VERSION 5.8 ;
BUSBITCHARS "[]" ;
DIVIDERCHAR "/" ;
UNITS
    DATABASE MICRONS 1000 ;
END UNITS

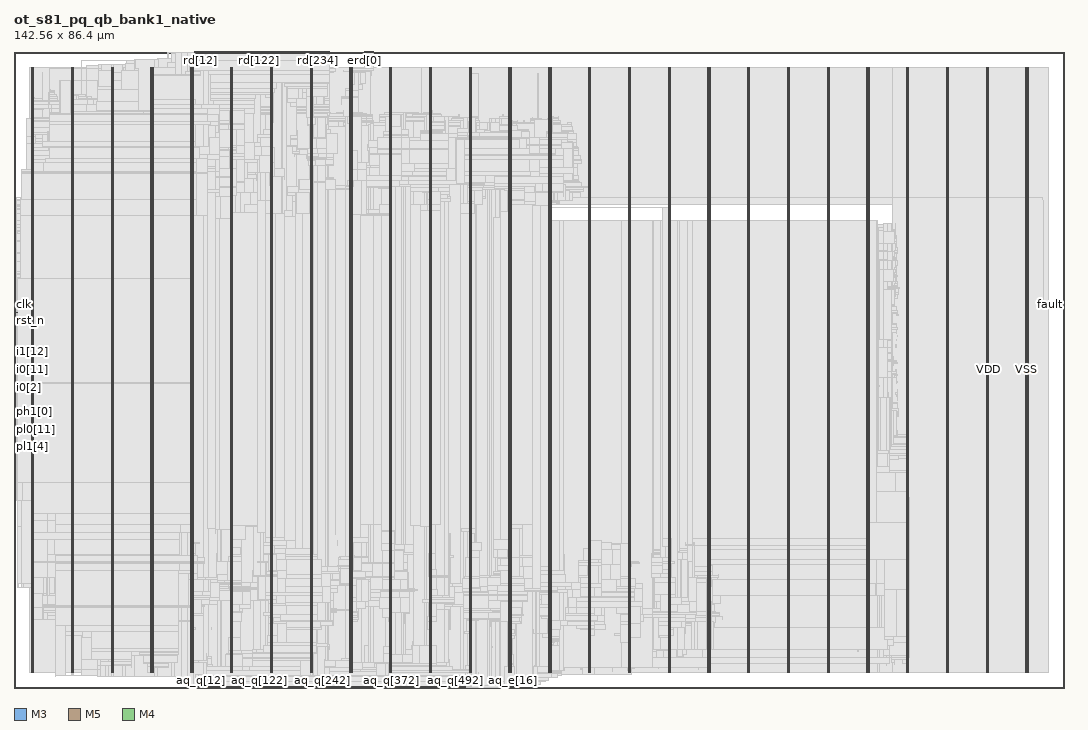
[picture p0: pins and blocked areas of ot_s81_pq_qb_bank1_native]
MACRO ot_s81_pq_qb_bank1_native
  FOREIGN ot_s81_pq_qb_bank1_native 0 0 ;
  CLASS BLOCK ;
  SIZE 142.56 BY 86.4 ;
  PIN aq_e[0]
    DIRECTION INPUT ;
    USE SIGNAL ;
    PORT
      LAYER M3 ;
        RECT  66.528 0 66.546 0.144 ;
    END
  END aq_e[0]
  PIN aq_e[10]
    DIRECTION INPUT ;
    USE SIGNAL ;
    PORT
      LAYER M3 ;
        RECT  67.248 0 67.266 0.144 ;
    END
  END aq_e[10]
  PIN aq_e[11]
    DIRECTION INPUT ;
    USE SIGNAL ;
    PORT
      LAYER M5 ;
        RECT  67.296 0 67.32 0.192 ;
    END
  END aq_e[11]
  PIN aq_e[12]
    DIRECTION INPUT ;
    USE SIGNAL ;
    PORT
      LAYER M3 ;
        RECT  67.392 0 67.41 0.144 ;
    END
  END aq_e[12]
  PIN aq_e[13]
    DIRECTION INPUT ;
    USE SIGNAL ;
    PORT
      LAYER M5 ;
        RECT  67.44 0 67.464 0.192 ;
    END
  END aq_e[13]
  PIN aq_e[14]
    DIRECTION INPUT ;
    USE SIGNAL ;
    PORT
      LAYER M3 ;
        RECT  67.536 0 67.554 0.144 ;
    END
  END aq_e[14]
  PIN aq_e[15]
    DIRECTION INPUT ;
    USE SIGNAL ;
    PORT
      LAYER M5 ;
        RECT  67.584 0 67.608 0.192 ;
    END
  END aq_e[15]
  PIN aq_e[16]
    DIRECTION INPUT ;
    USE SIGNAL ;
    PORT
      LAYER M3 ;
        RECT  67.68 0 67.698 0.144 ;
    END
  END aq_e[16]
  PIN aq_e[17]
    DIRECTION INPUT ;
    USE SIGNAL ;
    PORT
      LAYER M5 ;
        RECT  67.728 0 67.752 0.192 ;
    END
  END aq_e[17]
  PIN aq_e[18]
    DIRECTION INPUT ;
    USE SIGNAL ;
    PORT
      LAYER M3 ;
        RECT  67.824 0 67.842 0.144 ;
    END
  END aq_e[18]
  PIN aq_e[19]
    DIRECTION INPUT ;
    USE SIGNAL ;
    PORT
      LAYER M5 ;
        RECT  67.872 0 67.896 0.192 ;
    END
  END aq_e[19]
  PIN aq_e[1]
    DIRECTION INPUT ;
    USE SIGNAL ;
    PORT
      LAYER M5 ;
        RECT  66.576 0 66.6 0.192 ;
    END
  END aq_e[1]
  PIN aq_e[2]
    DIRECTION INPUT ;
    USE SIGNAL ;
    PORT
      LAYER M3 ;
        RECT  66.672 0 66.69 0.144 ;
    END
  END aq_e[2]
  PIN aq_e[3]
    DIRECTION INPUT ;
    USE SIGNAL ;
    PORT
      LAYER M5 ;
        RECT  66.72 0 66.744 0.192 ;
    END
  END aq_e[3]
  PIN aq_e[4]
    DIRECTION INPUT ;
    USE SIGNAL ;
    PORT
      LAYER M3 ;
        RECT  66.816 0 66.834 0.144 ;
    END
  END aq_e[4]
  PIN aq_e[5]
    DIRECTION INPUT ;
    USE SIGNAL ;
    PORT
      LAYER M5 ;
        RECT  66.864 0 66.888 0.192 ;
    END
  END aq_e[5]
  PIN aq_e[6]
    DIRECTION INPUT ;
    USE SIGNAL ;
    PORT
      LAYER M3 ;
        RECT  66.96 0 66.978 0.144 ;
    END
  END aq_e[6]
  PIN aq_e[7]
    DIRECTION INPUT ;
    USE SIGNAL ;
    PORT
      LAYER M5 ;
        RECT  67.008 0 67.032 0.192 ;
    END
  END aq_e[7]
  PIN aq_e[8]
    DIRECTION INPUT ;
    USE SIGNAL ;
    PORT
      LAYER M3 ;
        RECT  67.104 0 67.122 0.144 ;
    END
  END aq_e[8]
  PIN aq_e[9]
    DIRECTION INPUT ;
    USE SIGNAL ;
    PORT
      LAYER M5 ;
        RECT  67.152 0 67.176 0.192 ;
    END
  END aq_e[9]
  PIN aq_p[0]
    DIRECTION INPUT ;
    USE SIGNAL ;
    PORT
      LAYER M3 ;
        RECT  70.488 0 70.506 0.144 ;
    END
  END aq_p[0]
  PIN aq_p[1]
    DIRECTION INPUT ;
    USE SIGNAL ;
    PORT
      LAYER M5 ;
        RECT  70.512 0 70.536 0.192 ;
    END
  END aq_p[1]
  PIN aq_p[2]
    DIRECTION INPUT ;
    USE SIGNAL ;
    PORT
      LAYER M3 ;
        RECT  70.632 0 70.65 0.144 ;
    END
  END aq_p[2]
  PIN aq_p[3]
    DIRECTION INPUT ;
    USE SIGNAL ;
    PORT
      LAYER M5 ;
        RECT  70.656 0 70.68 0.192 ;
    END
  END aq_p[3]
  PIN aq_p[4]
    DIRECTION INPUT ;
    USE SIGNAL ;
    PORT
      LAYER M3 ;
        RECT  70.776 0 70.794 0.144 ;
    END
  END aq_p[4]
  PIN aq_p[5]
    DIRECTION INPUT ;
    USE SIGNAL ;
    PORT
      LAYER M5 ;
        RECT  70.8 0 70.824 0.192 ;
    END
  END aq_p[5]
  PIN aq_p[6]
    DIRECTION INPUT ;
    USE SIGNAL ;
    PORT
      LAYER M3 ;
        RECT  70.92 0 70.938 0.144 ;
    END
  END aq_p[6]
  PIN aq_p[7]
    DIRECTION INPUT ;
    USE SIGNAL ;
    PORT
      LAYER M5 ;
        RECT  70.944 0 70.968 0.192 ;
    END
  END aq_p[7]
  PIN aq_p[8]
    DIRECTION INPUT ;
    USE SIGNAL ;
    PORT
      LAYER M3 ;
        RECT  71.064 0 71.082 0.144 ;
    END
  END aq_p[8]
  PIN aq_p[9]
    DIRECTION INPUT ;
    USE SIGNAL ;
    PORT
      LAYER M5 ;
        RECT  71.088 0 71.112 0.192 ;
    END
  END aq_p[9]
  PIN aq_q[0]
    DIRECTION INPUT ;
    USE SIGNAL ;
    PORT
      LAYER M3 ;
        RECT  24.48 0 24.498 0.144 ;
    END
  END aq_q[0]
  PIN aq_q[100]
    DIRECTION INPUT ;
    USE SIGNAL ;
    PORT
      LAYER M3 ;
        RECT  31.68 0 31.698 0.144 ;
    END
  END aq_q[100]
  PIN aq_q[101]
    DIRECTION INPUT ;
    USE SIGNAL ;
    PORT
      LAYER M5 ;
        RECT  31.728 0 31.752 0.192 ;
    END
  END aq_q[101]
  PIN aq_q[102]
    DIRECTION INPUT ;
    USE SIGNAL ;
    PORT
      LAYER M3 ;
        RECT  31.824 0 31.842 0.144 ;
    END
  END aq_q[102]
  PIN aq_q[103]
    DIRECTION INPUT ;
    USE SIGNAL ;
    PORT
      LAYER M5 ;
        RECT  31.872 0 31.896 0.192 ;
    END
  END aq_q[103]
  PIN aq_q[104]
    DIRECTION INPUT ;
    USE SIGNAL ;
    PORT
      LAYER M3 ;
        RECT  31.968 0 31.986 0.144 ;
    END
  END aq_q[104]
  PIN aq_q[105]
    DIRECTION INPUT ;
    USE SIGNAL ;
    PORT
      LAYER M5 ;
        RECT  32.016 0 32.04 0.192 ;
    END
  END aq_q[105]
  PIN aq_q[106]
    DIRECTION INPUT ;
    USE SIGNAL ;
    PORT
      LAYER M3 ;
        RECT  32.112 0 32.13 0.144 ;
    END
  END aq_q[106]
  PIN aq_q[107]
    DIRECTION INPUT ;
    USE SIGNAL ;
    PORT
      LAYER M5 ;
        RECT  32.16 0 32.184 0.192 ;
    END
  END aq_q[107]
  PIN aq_q[108]
    DIRECTION INPUT ;
    USE SIGNAL ;
    PORT
      LAYER M3 ;
        RECT  32.256 0 32.274 0.144 ;
    END
  END aq_q[108]
  PIN aq_q[109]
    DIRECTION INPUT ;
    USE SIGNAL ;
    PORT
      LAYER M5 ;
        RECT  32.304 0 32.328 0.192 ;
    END
  END aq_q[109]
  PIN aq_q[10]
    DIRECTION INPUT ;
    USE SIGNAL ;
    PORT
      LAYER M3 ;
        RECT  25.2 0 25.218 0.144 ;
    END
  END aq_q[10]
  PIN aq_q[110]
    DIRECTION INPUT ;
    USE SIGNAL ;
    PORT
      LAYER M3 ;
        RECT  32.4 0 32.418 0.144 ;
    END
  END aq_q[110]
  PIN aq_q[111]
    DIRECTION INPUT ;
    USE SIGNAL ;
    PORT
      LAYER M5 ;
        RECT  32.448 0 32.472 0.192 ;
    END
  END aq_q[111]
  PIN aq_q[112]
    DIRECTION INPUT ;
    USE SIGNAL ;
    PORT
      LAYER M3 ;
        RECT  32.544 0 32.562 0.144 ;
    END
  END aq_q[112]
  PIN aq_q[113]
    DIRECTION INPUT ;
    USE SIGNAL ;
    PORT
      LAYER M5 ;
        RECT  32.592 0 32.616 0.192 ;
    END
  END aq_q[113]
  PIN aq_q[114]
    DIRECTION INPUT ;
    USE SIGNAL ;
    PORT
      LAYER M3 ;
        RECT  32.688 0 32.706 0.144 ;
    END
  END aq_q[114]
  PIN aq_q[115]
    DIRECTION INPUT ;
    USE SIGNAL ;
    PORT
      LAYER M5 ;
        RECT  32.736 0 32.76 0.192 ;
    END
  END aq_q[115]
  PIN aq_q[116]
    DIRECTION INPUT ;
    USE SIGNAL ;
    PORT
      LAYER M3 ;
        RECT  32.832 0 32.85 0.144 ;
    END
  END aq_q[116]
  PIN aq_q[117]
    DIRECTION INPUT ;
    USE SIGNAL ;
    PORT
      LAYER M5 ;
        RECT  32.88 0 32.904 0.192 ;
    END
  END aq_q[117]
  PIN aq_q[118]
    DIRECTION INPUT ;
    USE SIGNAL ;
    PORT
      LAYER M3 ;
        RECT  32.976 0 32.994 0.144 ;
    END
  END aq_q[118]
  PIN aq_q[119]
    DIRECTION INPUT ;
    USE SIGNAL ;
    PORT
      LAYER M5 ;
        RECT  33.024 0 33.048 0.192 ;
    END
  END aq_q[119]
  PIN aq_q[11]
    DIRECTION INPUT ;
    USE SIGNAL ;
    PORT
      LAYER M5 ;
        RECT  25.248 0 25.272 0.192 ;
    END
  END aq_q[11]
  PIN aq_q[120]
    DIRECTION INPUT ;
    USE SIGNAL ;
    PORT
      LAYER M3 ;
        RECT  33.12 0 33.138 0.144 ;
    END
  END aq_q[120]
  PIN aq_q[121]
    DIRECTION INPUT ;
    USE SIGNAL ;
    PORT
      LAYER M5 ;
        RECT  33.168 0 33.192 0.192 ;
    END
  END aq_q[121]
  PIN aq_q[122]
    DIRECTION INPUT ;
    USE SIGNAL ;
    PORT
      LAYER M3 ;
        RECT  33.264 0 33.282 0.144 ;
    END
  END aq_q[122]
  PIN aq_q[123]
    DIRECTION INPUT ;
    USE SIGNAL ;
    PORT
      LAYER M5 ;
        RECT  33.312 0 33.336 0.192 ;
    END
  END aq_q[123]
  PIN aq_q[124]
    DIRECTION INPUT ;
    USE SIGNAL ;
    PORT
      LAYER M3 ;
        RECT  33.408 0 33.426 0.144 ;
    END
  END aq_q[124]
  PIN aq_q[125]
    DIRECTION INPUT ;
    USE SIGNAL ;
    PORT
      LAYER M5 ;
        RECT  33.456 0 33.48 0.192 ;
    END
  END aq_q[125]
  PIN aq_q[126]
    DIRECTION INPUT ;
    USE SIGNAL ;
    PORT
      LAYER M3 ;
        RECT  33.552 0 33.57 0.144 ;
    END
  END aq_q[126]
  PIN aq_q[127]
    DIRECTION INPUT ;
    USE SIGNAL ;
    PORT
      LAYER M5 ;
        RECT  33.6 0 33.624 0.192 ;
    END
  END aq_q[127]
  PIN aq_q[128]
    DIRECTION INPUT ;
    USE SIGNAL ;
    PORT
      LAYER M3 ;
        RECT  33.696 0 33.714 0.144 ;
    END
  END aq_q[128]
  PIN aq_q[129]
    DIRECTION INPUT ;
    USE SIGNAL ;
    PORT
      LAYER M5 ;
        RECT  33.744 0 33.768 0.192 ;
    END
  END aq_q[129]
  PIN aq_q[12]
    DIRECTION INPUT ;
    USE SIGNAL ;
    PORT
      LAYER M3 ;
        RECT  25.344 0 25.362 0.144 ;
    END
  END aq_q[12]
  PIN aq_q[130]
    DIRECTION INPUT ;
    USE SIGNAL ;
    PORT
      LAYER M3 ;
        RECT  33.84 0 33.858 0.144 ;
    END
  END aq_q[130]
  PIN aq_q[131]
    DIRECTION INPUT ;
    USE SIGNAL ;
    PORT
      LAYER M5 ;
        RECT  33.888 0 33.912 0.192 ;
    END
  END aq_q[131]
  PIN aq_q[132]
    DIRECTION INPUT ;
    USE SIGNAL ;
    PORT
      LAYER M3 ;
        RECT  33.984 0 34.002 0.144 ;
    END
  END aq_q[132]
  PIN aq_q[133]
    DIRECTION INPUT ;
    USE SIGNAL ;
    PORT
      LAYER M5 ;
        RECT  34.032 0 34.056 0.192 ;
    END
  END aq_q[133]
  PIN aq_q[134]
    DIRECTION INPUT ;
    USE SIGNAL ;
    PORT
      LAYER M3 ;
        RECT  34.128 0 34.146 0.144 ;
    END
  END aq_q[134]
  PIN aq_q[135]
    DIRECTION INPUT ;
    USE SIGNAL ;
    PORT
      LAYER M5 ;
        RECT  34.176 0 34.2 0.192 ;
    END
  END aq_q[135]
  PIN aq_q[136]
    DIRECTION INPUT ;
    USE SIGNAL ;
    PORT
      LAYER M3 ;
        RECT  34.272 0 34.29 0.144 ;
    END
  END aq_q[136]
  PIN aq_q[137]
    DIRECTION INPUT ;
    USE SIGNAL ;
    PORT
      LAYER M5 ;
        RECT  34.32 0 34.344 0.192 ;
    END
  END aq_q[137]
  PIN aq_q[138]
    DIRECTION INPUT ;
    USE SIGNAL ;
    PORT
      LAYER M3 ;
        RECT  34.416 0 34.434 0.144 ;
    END
  END aq_q[138]
  PIN aq_q[139]
    DIRECTION INPUT ;
    USE SIGNAL ;
    PORT
      LAYER M5 ;
        RECT  34.464 0 34.488 0.192 ;
    END
  END aq_q[139]
  PIN aq_q[13]
    DIRECTION INPUT ;
    USE SIGNAL ;
    PORT
      LAYER M5 ;
        RECT  25.392 0 25.416 0.192 ;
    END
  END aq_q[13]
  PIN aq_q[140]
    DIRECTION INPUT ;
    USE SIGNAL ;
    PORT
      LAYER M3 ;
        RECT  34.56 0 34.578 0.144 ;
    END
  END aq_q[140]
  PIN aq_q[141]
    DIRECTION INPUT ;
    USE SIGNAL ;
    PORT
      LAYER M5 ;
        RECT  34.608 0 34.632 0.192 ;
    END
  END aq_q[141]
  PIN aq_q[142]
    DIRECTION INPUT ;
    USE SIGNAL ;
    PORT
      LAYER M3 ;
        RECT  34.704 0 34.722 0.144 ;
    END
  END aq_q[142]
  PIN aq_q[143]
    DIRECTION INPUT ;
    USE SIGNAL ;
    PORT
      LAYER M5 ;
        RECT  34.752 0 34.776 0.192 ;
    END
  END aq_q[143]
  PIN aq_q[144]
    DIRECTION INPUT ;
    USE SIGNAL ;
    PORT
      LAYER M3 ;
        RECT  34.848 0 34.866 0.144 ;
    END
  END aq_q[144]
  PIN aq_q[145]
    DIRECTION INPUT ;
    USE SIGNAL ;
    PORT
      LAYER M5 ;
        RECT  34.896 0 34.92 0.192 ;
    END
  END aq_q[145]
  PIN aq_q[146]
    DIRECTION INPUT ;
    USE SIGNAL ;
    PORT
      LAYER M3 ;
        RECT  34.992 0 35.01 0.144 ;
    END
  END aq_q[146]
  PIN aq_q[147]
    DIRECTION INPUT ;
    USE SIGNAL ;
    PORT
      LAYER M5 ;
        RECT  35.04 0 35.064 0.192 ;
    END
  END aq_q[147]
  PIN aq_q[148]
    DIRECTION INPUT ;
    USE SIGNAL ;
    PORT
      LAYER M3 ;
        RECT  35.136 0 35.154 0.144 ;
    END
  END aq_q[148]
  PIN aq_q[149]
    DIRECTION INPUT ;
    USE SIGNAL ;
    PORT
      LAYER M5 ;
        RECT  35.184 0 35.208 0.192 ;
    END
  END aq_q[149]
  PIN aq_q[14]
    DIRECTION INPUT ;
    USE SIGNAL ;
    PORT
      LAYER M3 ;
        RECT  25.488 0 25.506 0.144 ;
    END
  END aq_q[14]
  PIN aq_q[150]
    DIRECTION INPUT ;
    USE SIGNAL ;
    PORT
      LAYER M3 ;
        RECT  35.28 0 35.298 0.144 ;
    END
  END aq_q[150]
  PIN aq_q[151]
    DIRECTION INPUT ;
    USE SIGNAL ;
    PORT
      LAYER M5 ;
        RECT  35.328 0 35.352 0.192 ;
    END
  END aq_q[151]
  PIN aq_q[152]
    DIRECTION INPUT ;
    USE SIGNAL ;
    PORT
      LAYER M3 ;
        RECT  35.424 0 35.442 0.144 ;
    END
  END aq_q[152]
  PIN aq_q[153]
    DIRECTION INPUT ;
    USE SIGNAL ;
    PORT
      LAYER M5 ;
        RECT  35.472 0 35.496 0.192 ;
    END
  END aq_q[153]
  PIN aq_q[154]
    DIRECTION INPUT ;
    USE SIGNAL ;
    PORT
      LAYER M3 ;
        RECT  35.568 0 35.586 0.144 ;
    END
  END aq_q[154]
  PIN aq_q[155]
    DIRECTION INPUT ;
    USE SIGNAL ;
    PORT
      LAYER M5 ;
        RECT  35.616 0 35.64 0.192 ;
    END
  END aq_q[155]
  PIN aq_q[156]
    DIRECTION INPUT ;
    USE SIGNAL ;
    PORT
      LAYER M3 ;
        RECT  35.712 0 35.73 0.144 ;
    END
  END aq_q[156]
  PIN aq_q[157]
    DIRECTION INPUT ;
    USE SIGNAL ;
    PORT
      LAYER M5 ;
        RECT  35.76 0 35.784 0.192 ;
    END
  END aq_q[157]
  PIN aq_q[158]
    DIRECTION INPUT ;
    USE SIGNAL ;
    PORT
      LAYER M3 ;
        RECT  35.856 0 35.874 0.144 ;
    END
  END aq_q[158]
  PIN aq_q[159]
    DIRECTION INPUT ;
    USE SIGNAL ;
    PORT
      LAYER M5 ;
        RECT  35.904 0 35.928 0.192 ;
    END
  END aq_q[159]
  PIN aq_q[15]
    DIRECTION INPUT ;
    USE SIGNAL ;
    PORT
      LAYER M5 ;
        RECT  25.536 0 25.56 0.192 ;
    END
  END aq_q[15]
  PIN aq_q[160]
    DIRECTION INPUT ;
    USE SIGNAL ;
    PORT
      LAYER M3 ;
        RECT  36 0 36.018 0.144 ;
    END
  END aq_q[160]
  PIN aq_q[161]
    DIRECTION INPUT ;
    USE SIGNAL ;
    PORT
      LAYER M5 ;
        RECT  36.048 0 36.072 0.192 ;
    END
  END aq_q[161]
  PIN aq_q[162]
    DIRECTION INPUT ;
    USE SIGNAL ;
    PORT
      LAYER M3 ;
        RECT  36.144 0 36.162 0.144 ;
    END
  END aq_q[162]
  PIN aq_q[163]
    DIRECTION INPUT ;
    USE SIGNAL ;
    PORT
      LAYER M5 ;
        RECT  36.192 0 36.216 0.192 ;
    END
  END aq_q[163]
  PIN aq_q[164]
    DIRECTION INPUT ;
    USE SIGNAL ;
    PORT
      LAYER M3 ;
        RECT  36.288 0 36.306 0.144 ;
    END
  END aq_q[164]
  PIN aq_q[165]
    DIRECTION INPUT ;
    USE SIGNAL ;
    PORT
      LAYER M5 ;
        RECT  36.336 0 36.36 0.192 ;
    END
  END aq_q[165]
  PIN aq_q[166]
    DIRECTION INPUT ;
    USE SIGNAL ;
    PORT
      LAYER M3 ;
        RECT  36.432 0 36.45 0.144 ;
    END
  END aq_q[166]
  PIN aq_q[167]
    DIRECTION INPUT ;
    USE SIGNAL ;
    PORT
      LAYER M5 ;
        RECT  36.48 0 36.504 0.192 ;
    END
  END aq_q[167]
  PIN aq_q[168]
    DIRECTION INPUT ;
    USE SIGNAL ;
    PORT
      LAYER M3 ;
        RECT  36.576 0 36.594 0.144 ;
    END
  END aq_q[168]
  PIN aq_q[169]
    DIRECTION INPUT ;
    USE SIGNAL ;
    PORT
      LAYER M5 ;
        RECT  36.624 0 36.648 0.192 ;
    END
  END aq_q[169]
  PIN aq_q[16]
    DIRECTION INPUT ;
    USE SIGNAL ;
    PORT
      LAYER M3 ;
        RECT  25.632 0 25.65 0.144 ;
    END
  END aq_q[16]
  PIN aq_q[170]
    DIRECTION INPUT ;
    USE SIGNAL ;
    PORT
      LAYER M3 ;
        RECT  36.72 0 36.738 0.144 ;
    END
  END aq_q[170]
  PIN aq_q[171]
    DIRECTION INPUT ;
    USE SIGNAL ;
    PORT
      LAYER M5 ;
        RECT  36.768 0 36.792 0.192 ;
    END
  END aq_q[171]
  PIN aq_q[172]
    DIRECTION INPUT ;
    USE SIGNAL ;
    PORT
      LAYER M3 ;
        RECT  36.864 0 36.882 0.144 ;
    END
  END aq_q[172]
  PIN aq_q[173]
    DIRECTION INPUT ;
    USE SIGNAL ;
    PORT
      LAYER M5 ;
        RECT  36.912 0 36.936 0.192 ;
    END
  END aq_q[173]
  PIN aq_q[174]
    DIRECTION INPUT ;
    USE SIGNAL ;
    PORT
      LAYER M3 ;
        RECT  37.008 0 37.026 0.144 ;
    END
  END aq_q[174]
  PIN aq_q[175]
    DIRECTION INPUT ;
    USE SIGNAL ;
    PORT
      LAYER M5 ;
        RECT  37.056 0 37.08 0.192 ;
    END
  END aq_q[175]
  PIN aq_q[176]
    DIRECTION INPUT ;
    USE SIGNAL ;
    PORT
      LAYER M3 ;
        RECT  37.152 0 37.17 0.144 ;
    END
  END aq_q[176]
  PIN aq_q[177]
    DIRECTION INPUT ;
    USE SIGNAL ;
    PORT
      LAYER M5 ;
        RECT  37.2 0 37.224 0.192 ;
    END
  END aq_q[177]
  PIN aq_q[178]
    DIRECTION INPUT ;
    USE SIGNAL ;
    PORT
      LAYER M3 ;
        RECT  37.296 0 37.314 0.144 ;
    END
  END aq_q[178]
  PIN aq_q[179]
    DIRECTION INPUT ;
    USE SIGNAL ;
    PORT
      LAYER M5 ;
        RECT  37.344 0 37.368 0.192 ;
    END
  END aq_q[179]
  PIN aq_q[17]
    DIRECTION INPUT ;
    USE SIGNAL ;
    PORT
      LAYER M5 ;
        RECT  25.68 0 25.704 0.192 ;
    END
  END aq_q[17]
  PIN aq_q[180]
    DIRECTION INPUT ;
    USE SIGNAL ;
    PORT
      LAYER M3 ;
        RECT  37.44 0 37.458 0.144 ;
    END
  END aq_q[180]
  PIN aq_q[181]
    DIRECTION INPUT ;
    USE SIGNAL ;
    PORT
      LAYER M5 ;
        RECT  37.488 0 37.512 0.192 ;
    END
  END aq_q[181]
  PIN aq_q[182]
    DIRECTION INPUT ;
    USE SIGNAL ;
    PORT
      LAYER M3 ;
        RECT  37.584 0 37.602 0.144 ;
    END
  END aq_q[182]
  PIN aq_q[183]
    DIRECTION INPUT ;
    USE SIGNAL ;
    PORT
      LAYER M5 ;
        RECT  37.632 0 37.656 0.192 ;
    END
  END aq_q[183]
  PIN aq_q[184]
    DIRECTION INPUT ;
    USE SIGNAL ;
    PORT
      LAYER M3 ;
        RECT  37.728 0 37.746 0.144 ;
    END
  END aq_q[184]
  PIN aq_q[185]
    DIRECTION INPUT ;
    USE SIGNAL ;
    PORT
      LAYER M5 ;
        RECT  37.776 0 37.8 0.192 ;
    END
  END aq_q[185]
  PIN aq_q[186]
    DIRECTION INPUT ;
    USE SIGNAL ;
    PORT
      LAYER M3 ;
        RECT  37.872 0 37.89 0.144 ;
    END
  END aq_q[186]
  PIN aq_q[187]
    DIRECTION INPUT ;
    USE SIGNAL ;
    PORT
      LAYER M5 ;
        RECT  37.92 0 37.944 0.192 ;
    END
  END aq_q[187]
  PIN aq_q[188]
    DIRECTION INPUT ;
    USE SIGNAL ;
    PORT
      LAYER M3 ;
        RECT  38.016 0 38.034 0.144 ;
    END
  END aq_q[188]
  PIN aq_q[189]
    DIRECTION INPUT ;
    USE SIGNAL ;
    PORT
      LAYER M5 ;
        RECT  38.064 0 38.088 0.192 ;
    END
  END aq_q[189]
  PIN aq_q[18]
    DIRECTION INPUT ;
    USE SIGNAL ;
    PORT
      LAYER M3 ;
        RECT  25.776 0 25.794 0.144 ;
    END
  END aq_q[18]
  PIN aq_q[190]
    DIRECTION INPUT ;
    USE SIGNAL ;
    PORT
      LAYER M3 ;
        RECT  38.16 0 38.178 0.144 ;
    END
  END aq_q[190]
  PIN aq_q[191]
    DIRECTION INPUT ;
    USE SIGNAL ;
    PORT
      LAYER M5 ;
        RECT  38.208 0 38.232 0.192 ;
    END
  END aq_q[191]
  PIN aq_q[192]
    DIRECTION INPUT ;
    USE SIGNAL ;
    PORT
      LAYER M3 ;
        RECT  38.304 0 38.322 0.144 ;
    END
  END aq_q[192]
  PIN aq_q[193]
    DIRECTION INPUT ;
    USE SIGNAL ;
    PORT
      LAYER M5 ;
        RECT  38.352 0 38.376 0.192 ;
    END
  END aq_q[193]
  PIN aq_q[194]
    DIRECTION INPUT ;
    USE SIGNAL ;
    PORT
      LAYER M3 ;
        RECT  38.448 0 38.466 0.144 ;
    END
  END aq_q[194]
  PIN aq_q[195]
    DIRECTION INPUT ;
    USE SIGNAL ;
    PORT
      LAYER M5 ;
        RECT  38.496 0 38.52 0.192 ;
    END
  END aq_q[195]
  PIN aq_q[196]
    DIRECTION INPUT ;
    USE SIGNAL ;
    PORT
      LAYER M3 ;
        RECT  38.592 0 38.61 0.144 ;
    END
  END aq_q[196]
  PIN aq_q[197]
    DIRECTION INPUT ;
    USE SIGNAL ;
    PORT
      LAYER M5 ;
        RECT  38.64 0 38.664 0.192 ;
    END
  END aq_q[197]
  PIN aq_q[198]
    DIRECTION INPUT ;
    USE SIGNAL ;
    PORT
      LAYER M3 ;
        RECT  38.736 0 38.754 0.144 ;
    END
  END aq_q[198]
  PIN aq_q[199]
    DIRECTION INPUT ;
    USE SIGNAL ;
    PORT
      LAYER M5 ;
        RECT  38.784 0 38.808 0.192 ;
    END
  END aq_q[199]
  PIN aq_q[19]
    DIRECTION INPUT ;
    USE SIGNAL ;
    PORT
      LAYER M5 ;
        RECT  25.824 0 25.848 0.192 ;
    END
  END aq_q[19]
  PIN aq_q[1]
    DIRECTION INPUT ;
    USE SIGNAL ;
    PORT
      LAYER M5 ;
        RECT  24.528 0 24.552 0.192 ;
    END
  END aq_q[1]
  PIN aq_q[200]
    DIRECTION INPUT ;
    USE SIGNAL ;
    PORT
      LAYER M3 ;
        RECT  38.88 0 38.898 0.144 ;
    END
  END aq_q[200]
  PIN aq_q[201]
    DIRECTION INPUT ;
    USE SIGNAL ;
    PORT
      LAYER M5 ;
        RECT  38.928 0 38.952 0.192 ;
    END
  END aq_q[201]
  PIN aq_q[202]
    DIRECTION INPUT ;
    USE SIGNAL ;
    PORT
      LAYER M3 ;
        RECT  39.024 0 39.042 0.144 ;
    END
  END aq_q[202]
  PIN aq_q[203]
    DIRECTION INPUT ;
    USE SIGNAL ;
    PORT
      LAYER M5 ;
        RECT  39.072 0 39.096 0.192 ;
    END
  END aq_q[203]
  PIN aq_q[204]
    DIRECTION INPUT ;
    USE SIGNAL ;
    PORT
      LAYER M3 ;
        RECT  39.168 0 39.186 0.144 ;
    END
  END aq_q[204]
  PIN aq_q[205]
    DIRECTION INPUT ;
    USE SIGNAL ;
    PORT
      LAYER M5 ;
        RECT  39.216 0 39.24 0.192 ;
    END
  END aq_q[205]
  PIN aq_q[206]
    DIRECTION INPUT ;
    USE SIGNAL ;
    PORT
      LAYER M3 ;
        RECT  39.312 0 39.33 0.144 ;
    END
  END aq_q[206]
  PIN aq_q[207]
    DIRECTION INPUT ;
    USE SIGNAL ;
    PORT
      LAYER M5 ;
        RECT  39.36 0 39.384 0.192 ;
    END
  END aq_q[207]
  PIN aq_q[208]
    DIRECTION INPUT ;
    USE SIGNAL ;
    PORT
      LAYER M3 ;
        RECT  39.456 0 39.474 0.144 ;
    END
  END aq_q[208]
  PIN aq_q[209]
    DIRECTION INPUT ;
    USE SIGNAL ;
    PORT
      LAYER M5 ;
        RECT  39.504 0 39.528 0.192 ;
    END
  END aq_q[209]
  PIN aq_q[20]
    DIRECTION INPUT ;
    USE SIGNAL ;
    PORT
      LAYER M3 ;
        RECT  25.92 0 25.938 0.144 ;
    END
  END aq_q[20]
  PIN aq_q[210]
    DIRECTION INPUT ;
    USE SIGNAL ;
    PORT
      LAYER M3 ;
        RECT  39.6 0 39.618 0.144 ;
    END
  END aq_q[210]
  PIN aq_q[211]
    DIRECTION INPUT ;
    USE SIGNAL ;
    PORT
      LAYER M5 ;
        RECT  39.648 0 39.672 0.192 ;
    END
  END aq_q[211]
  PIN aq_q[212]
    DIRECTION INPUT ;
    USE SIGNAL ;
    PORT
      LAYER M3 ;
        RECT  39.744 0 39.762 0.144 ;
    END
  END aq_q[212]
  PIN aq_q[213]
    DIRECTION INPUT ;
    USE SIGNAL ;
    PORT
      LAYER M5 ;
        RECT  39.792 0 39.816 0.192 ;
    END
  END aq_q[213]
  PIN aq_q[214]
    DIRECTION INPUT ;
    USE SIGNAL ;
    PORT
      LAYER M3 ;
        RECT  39.888 0 39.906 0.144 ;
    END
  END aq_q[214]
  PIN aq_q[215]
    DIRECTION INPUT ;
    USE SIGNAL ;
    PORT
      LAYER M5 ;
        RECT  39.936 0 39.96 0.192 ;
    END
  END aq_q[215]
  PIN aq_q[216]
    DIRECTION INPUT ;
    USE SIGNAL ;
    PORT
      LAYER M3 ;
        RECT  40.032 0 40.05 0.144 ;
    END
  END aq_q[216]
  PIN aq_q[217]
    DIRECTION INPUT ;
    USE SIGNAL ;
    PORT
      LAYER M5 ;
        RECT  40.08 0 40.104 0.192 ;
    END
  END aq_q[217]
  PIN aq_q[218]
    DIRECTION INPUT ;
    USE SIGNAL ;
    PORT
      LAYER M3 ;
        RECT  40.176 0 40.194 0.144 ;
    END
  END aq_q[218]
  PIN aq_q[219]
    DIRECTION INPUT ;
    USE SIGNAL ;
    PORT
      LAYER M5 ;
        RECT  40.224 0 40.248 0.192 ;
    END
  END aq_q[219]
  PIN aq_q[21]
    DIRECTION INPUT ;
    USE SIGNAL ;
    PORT
      LAYER M5 ;
        RECT  25.968 0 25.992 0.192 ;
    END
  END aq_q[21]
  PIN aq_q[220]
    DIRECTION INPUT ;
    USE SIGNAL ;
    PORT
      LAYER M3 ;
        RECT  40.32 0 40.338 0.144 ;
    END
  END aq_q[220]
  PIN aq_q[221]
    DIRECTION INPUT ;
    USE SIGNAL ;
    PORT
      LAYER M5 ;
        RECT  40.368 0 40.392 0.192 ;
    END
  END aq_q[221]
  PIN aq_q[222]
    DIRECTION INPUT ;
    USE SIGNAL ;
    PORT
      LAYER M3 ;
        RECT  40.464 0 40.482 0.144 ;
    END
  END aq_q[222]
  PIN aq_q[223]
    DIRECTION INPUT ;
    USE SIGNAL ;
    PORT
      LAYER M5 ;
        RECT  40.512 0 40.536 0.192 ;
    END
  END aq_q[223]
  PIN aq_q[224]
    DIRECTION INPUT ;
    USE SIGNAL ;
    PORT
      LAYER M3 ;
        RECT  40.608 0 40.626 0.144 ;
    END
  END aq_q[224]
  PIN aq_q[225]
    DIRECTION INPUT ;
    USE SIGNAL ;
    PORT
      LAYER M5 ;
        RECT  40.656 0 40.68 0.192 ;
    END
  END aq_q[225]
  PIN aq_q[226]
    DIRECTION INPUT ;
    USE SIGNAL ;
    PORT
      LAYER M3 ;
        RECT  40.752 0 40.77 0.144 ;
    END
  END aq_q[226]
  PIN aq_q[227]
    DIRECTION INPUT ;
    USE SIGNAL ;
    PORT
      LAYER M5 ;
        RECT  40.8 0 40.824 0.192 ;
    END
  END aq_q[227]
  PIN aq_q[228]
    DIRECTION INPUT ;
    USE SIGNAL ;
    PORT
      LAYER M3 ;
        RECT  40.896 0 40.914 0.144 ;
    END
  END aq_q[228]
  PIN aq_q[229]
    DIRECTION INPUT ;
    USE SIGNAL ;
    PORT
      LAYER M5 ;
        RECT  40.944 0 40.968 0.192 ;
    END
  END aq_q[229]
  PIN aq_q[22]
    DIRECTION INPUT ;
    USE SIGNAL ;
    PORT
      LAYER M3 ;
        RECT  26.064 0 26.082 0.144 ;
    END
  END aq_q[22]
  PIN aq_q[230]
    DIRECTION INPUT ;
    USE SIGNAL ;
    PORT
      LAYER M3 ;
        RECT  41.04 0 41.058 0.144 ;
    END
  END aq_q[230]
  PIN aq_q[231]
    DIRECTION INPUT ;
    USE SIGNAL ;
    PORT
      LAYER M5 ;
        RECT  41.088 0 41.112 0.192 ;
    END
  END aq_q[231]
  PIN aq_q[232]
    DIRECTION INPUT ;
    USE SIGNAL ;
    PORT
      LAYER M3 ;
        RECT  41.184 0 41.202 0.144 ;
    END
  END aq_q[232]
  PIN aq_q[233]
    DIRECTION INPUT ;
    USE SIGNAL ;
    PORT
      LAYER M5 ;
        RECT  41.232 0 41.256 0.192 ;
    END
  END aq_q[233]
  PIN aq_q[234]
    DIRECTION INPUT ;
    USE SIGNAL ;
    PORT
      LAYER M3 ;
        RECT  41.328 0 41.346 0.144 ;
    END
  END aq_q[234]
  PIN aq_q[235]
    DIRECTION INPUT ;
    USE SIGNAL ;
    PORT
      LAYER M5 ;
        RECT  41.376 0 41.4 0.192 ;
    END
  END aq_q[235]
  PIN aq_q[236]
    DIRECTION INPUT ;
    USE SIGNAL ;
    PORT
      LAYER M3 ;
        RECT  41.472 0 41.49 0.144 ;
    END
  END aq_q[236]
  PIN aq_q[237]
    DIRECTION INPUT ;
    USE SIGNAL ;
    PORT
      LAYER M5 ;
        RECT  41.52 0 41.544 0.192 ;
    END
  END aq_q[237]
  PIN aq_q[238]
    DIRECTION INPUT ;
    USE SIGNAL ;
    PORT
      LAYER M3 ;
        RECT  41.616 0 41.634 0.144 ;
    END
  END aq_q[238]
  PIN aq_q[239]
    DIRECTION INPUT ;
    USE SIGNAL ;
    PORT
      LAYER M5 ;
        RECT  41.664 0 41.688 0.192 ;
    END
  END aq_q[239]
  PIN aq_q[23]
    DIRECTION INPUT ;
    USE SIGNAL ;
    PORT
      LAYER M5 ;
        RECT  26.112 0 26.136 0.192 ;
    END
  END aq_q[23]
  PIN aq_q[240]
    DIRECTION INPUT ;
    USE SIGNAL ;
    PORT
      LAYER M3 ;
        RECT  41.76 0 41.778 0.144 ;
    END
  END aq_q[240]
  PIN aq_q[241]
    DIRECTION INPUT ;
    USE SIGNAL ;
    PORT
      LAYER M5 ;
        RECT  41.808 0 41.832 0.192 ;
    END
  END aq_q[241]
  PIN aq_q[242]
    DIRECTION INPUT ;
    USE SIGNAL ;
    PORT
      LAYER M3 ;
        RECT  41.904 0 41.922 0.144 ;
    END
  END aq_q[242]
  PIN aq_q[243]
    DIRECTION INPUT ;
    USE SIGNAL ;
    PORT
      LAYER M5 ;
        RECT  41.952 0 41.976 0.192 ;
    END
  END aq_q[243]
  PIN aq_q[244]
    DIRECTION INPUT ;
    USE SIGNAL ;
    PORT
      LAYER M3 ;
        RECT  42.048 0 42.066 0.144 ;
    END
  END aq_q[244]
  PIN aq_q[245]
    DIRECTION INPUT ;
    USE SIGNAL ;
    PORT
      LAYER M5 ;
        RECT  42.096 0 42.12 0.192 ;
    END
  END aq_q[245]
  PIN aq_q[246]
    DIRECTION INPUT ;
    USE SIGNAL ;
    PORT
      LAYER M3 ;
        RECT  42.192 0 42.21 0.144 ;
    END
  END aq_q[246]
  PIN aq_q[247]
    DIRECTION INPUT ;
    USE SIGNAL ;
    PORT
      LAYER M5 ;
        RECT  42.24 0 42.264 0.192 ;
    END
  END aq_q[247]
  PIN aq_q[248]
    DIRECTION INPUT ;
    USE SIGNAL ;
    PORT
      LAYER M3 ;
        RECT  42.336 0 42.354 0.144 ;
    END
  END aq_q[248]
  PIN aq_q[249]
    DIRECTION INPUT ;
    USE SIGNAL ;
    PORT
      LAYER M5 ;
        RECT  42.384 0 42.408 0.192 ;
    END
  END aq_q[249]
  PIN aq_q[24]
    DIRECTION INPUT ;
    USE SIGNAL ;
    PORT
      LAYER M3 ;
        RECT  26.208 0 26.226 0.144 ;
    END
  END aq_q[24]
  PIN aq_q[250]
    DIRECTION INPUT ;
    USE SIGNAL ;
    PORT
      LAYER M3 ;
        RECT  42.48 0 42.498 0.144 ;
    END
  END aq_q[250]
  PIN aq_q[251]
    DIRECTION INPUT ;
    USE SIGNAL ;
    PORT
      LAYER M5 ;
        RECT  42.528 0 42.552 0.192 ;
    END
  END aq_q[251]
  PIN aq_q[252]
    DIRECTION INPUT ;
    USE SIGNAL ;
    PORT
      LAYER M3 ;
        RECT  42.624 0 42.642 0.144 ;
    END
  END aq_q[252]
  PIN aq_q[253]
    DIRECTION INPUT ;
    USE SIGNAL ;
    PORT
      LAYER M5 ;
        RECT  42.672 0 42.696 0.192 ;
    END
  END aq_q[253]
  PIN aq_q[254]
    DIRECTION INPUT ;
    USE SIGNAL ;
    PORT
      LAYER M3 ;
        RECT  42.768 0 42.786 0.144 ;
    END
  END aq_q[254]
  PIN aq_q[255]
    DIRECTION INPUT ;
    USE SIGNAL ;
    PORT
      LAYER M5 ;
        RECT  42.816 0 42.84 0.192 ;
    END
  END aq_q[255]
  PIN aq_q[256]
    DIRECTION INPUT ;
    USE SIGNAL ;
    PORT
      LAYER M3 ;
        RECT  42.912 0 42.93 0.144 ;
    END
  END aq_q[256]
  PIN aq_q[257]
    DIRECTION INPUT ;
    USE SIGNAL ;
    PORT
      LAYER M5 ;
        RECT  42.96 0 42.984 0.192 ;
    END
  END aq_q[257]
  PIN aq_q[258]
    DIRECTION INPUT ;
    USE SIGNAL ;
    PORT
      LAYER M3 ;
        RECT  43.056 0 43.074 0.144 ;
    END
  END aq_q[258]
  PIN aq_q[259]
    DIRECTION INPUT ;
    USE SIGNAL ;
    PORT
      LAYER M5 ;
        RECT  43.104 0 43.128 0.192 ;
    END
  END aq_q[259]
  PIN aq_q[25]
    DIRECTION INPUT ;
    USE SIGNAL ;
    PORT
      LAYER M5 ;
        RECT  26.256 0 26.28 0.192 ;
    END
  END aq_q[25]
  PIN aq_q[260]
    DIRECTION INPUT ;
    USE SIGNAL ;
    PORT
      LAYER M3 ;
        RECT  43.2 0 43.218 0.144 ;
    END
  END aq_q[260]
  PIN aq_q[261]
    DIRECTION INPUT ;
    USE SIGNAL ;
    PORT
      LAYER M5 ;
        RECT  43.248 0 43.272 0.192 ;
    END
  END aq_q[261]
  PIN aq_q[262]
    DIRECTION INPUT ;
    USE SIGNAL ;
    PORT
      LAYER M3 ;
        RECT  43.344 0 43.362 0.144 ;
    END
  END aq_q[262]
  PIN aq_q[263]
    DIRECTION INPUT ;
    USE SIGNAL ;
    PORT
      LAYER M5 ;
        RECT  43.392 0 43.416 0.192 ;
    END
  END aq_q[263]
  PIN aq_q[264]
    DIRECTION INPUT ;
    USE SIGNAL ;
    PORT
      LAYER M3 ;
        RECT  43.488 0 43.506 0.144 ;
    END
  END aq_q[264]
  PIN aq_q[265]
    DIRECTION INPUT ;
    USE SIGNAL ;
    PORT
      LAYER M5 ;
        RECT  43.536 0 43.56 0.192 ;
    END
  END aq_q[265]
  PIN aq_q[266]
    DIRECTION INPUT ;
    USE SIGNAL ;
    PORT
      LAYER M3 ;
        RECT  43.632 0 43.65 0.144 ;
    END
  END aq_q[266]
  PIN aq_q[267]
    DIRECTION INPUT ;
    USE SIGNAL ;
    PORT
      LAYER M5 ;
        RECT  43.68 0 43.704 0.192 ;
    END
  END aq_q[267]
  PIN aq_q[268]
    DIRECTION INPUT ;
    USE SIGNAL ;
    PORT
      LAYER M3 ;
        RECT  43.776 0 43.794 0.144 ;
    END
  END aq_q[268]
  PIN aq_q[269]
    DIRECTION INPUT ;
    USE SIGNAL ;
    PORT
      LAYER M5 ;
        RECT  43.824 0 43.848 0.192 ;
    END
  END aq_q[269]
  PIN aq_q[26]
    DIRECTION INPUT ;
    USE SIGNAL ;
    PORT
      LAYER M3 ;
        RECT  26.352 0 26.37 0.144 ;
    END
  END aq_q[26]
  PIN aq_q[270]
    DIRECTION INPUT ;
    USE SIGNAL ;
    PORT
      LAYER M3 ;
        RECT  43.92 0 43.938 0.144 ;
    END
  END aq_q[270]
  PIN aq_q[271]
    DIRECTION INPUT ;
    USE SIGNAL ;
    PORT
      LAYER M5 ;
        RECT  43.968 0 43.992 0.192 ;
    END
  END aq_q[271]
  PIN aq_q[272]
    DIRECTION INPUT ;
    USE SIGNAL ;
    PORT
      LAYER M3 ;
        RECT  44.064 0 44.082 0.144 ;
    END
  END aq_q[272]
  PIN aq_q[273]
    DIRECTION INPUT ;
    USE SIGNAL ;
    PORT
      LAYER M5 ;
        RECT  44.112 0 44.136 0.192 ;
    END
  END aq_q[273]
  PIN aq_q[274]
    DIRECTION INPUT ;
    USE SIGNAL ;
    PORT
      LAYER M3 ;
        RECT  44.208 0 44.226 0.144 ;
    END
  END aq_q[274]
  PIN aq_q[275]
    DIRECTION INPUT ;
    USE SIGNAL ;
    PORT
      LAYER M5 ;
        RECT  44.256 0 44.28 0.192 ;
    END
  END aq_q[275]
  PIN aq_q[276]
    DIRECTION INPUT ;
    USE SIGNAL ;
    PORT
      LAYER M3 ;
        RECT  44.352 0 44.37 0.144 ;
    END
  END aq_q[276]
  PIN aq_q[277]
    DIRECTION INPUT ;
    USE SIGNAL ;
    PORT
      LAYER M5 ;
        RECT  44.4 0 44.424 0.192 ;
    END
  END aq_q[277]
  PIN aq_q[278]
    DIRECTION INPUT ;
    USE SIGNAL ;
    PORT
      LAYER M3 ;
        RECT  44.496 0 44.514 0.144 ;
    END
  END aq_q[278]
  PIN aq_q[279]
    DIRECTION INPUT ;
    USE SIGNAL ;
    PORT
      LAYER M5 ;
        RECT  44.544 0 44.568 0.192 ;
    END
  END aq_q[279]
  PIN aq_q[27]
    DIRECTION INPUT ;
    USE SIGNAL ;
    PORT
      LAYER M5 ;
        RECT  26.4 0 26.424 0.192 ;
    END
  END aq_q[27]
  PIN aq_q[280]
    DIRECTION INPUT ;
    USE SIGNAL ;
    PORT
      LAYER M3 ;
        RECT  44.64 0 44.658 0.144 ;
    END
  END aq_q[280]
  PIN aq_q[281]
    DIRECTION INPUT ;
    USE SIGNAL ;
    PORT
      LAYER M5 ;
        RECT  44.688 0 44.712 0.192 ;
    END
  END aq_q[281]
  PIN aq_q[282]
    DIRECTION INPUT ;
    USE SIGNAL ;
    PORT
      LAYER M3 ;
        RECT  44.784 0 44.802 0.144 ;
    END
  END aq_q[282]
  PIN aq_q[283]
    DIRECTION INPUT ;
    USE SIGNAL ;
    PORT
      LAYER M5 ;
        RECT  44.832 0 44.856 0.192 ;
    END
  END aq_q[283]
  PIN aq_q[284]
    DIRECTION INPUT ;
    USE SIGNAL ;
    PORT
      LAYER M3 ;
        RECT  44.928 0 44.946 0.144 ;
    END
  END aq_q[284]
  PIN aq_q[285]
    DIRECTION INPUT ;
    USE SIGNAL ;
    PORT
      LAYER M5 ;
        RECT  44.976 0 45 0.192 ;
    END
  END aq_q[285]
  PIN aq_q[286]
    DIRECTION INPUT ;
    USE SIGNAL ;
    PORT
      LAYER M3 ;
        RECT  45.072 0 45.09 0.144 ;
    END
  END aq_q[286]
  PIN aq_q[287]
    DIRECTION INPUT ;
    USE SIGNAL ;
    PORT
      LAYER M5 ;
        RECT  45.12 0 45.144 0.192 ;
    END
  END aq_q[287]
  PIN aq_q[288]
    DIRECTION INPUT ;
    USE SIGNAL ;
    PORT
      LAYER M3 ;
        RECT  45.216 0 45.234 0.144 ;
    END
  END aq_q[288]
  PIN aq_q[289]
    DIRECTION INPUT ;
    USE SIGNAL ;
    PORT
      LAYER M5 ;
        RECT  45.264 0 45.288 0.192 ;
    END
  END aq_q[289]
  PIN aq_q[28]
    DIRECTION INPUT ;
    USE SIGNAL ;
    PORT
      LAYER M3 ;
        RECT  26.496 0 26.514 0.144 ;
    END
  END aq_q[28]
  PIN aq_q[290]
    DIRECTION INPUT ;
    USE SIGNAL ;
    PORT
      LAYER M3 ;
        RECT  45.36 0 45.378 0.144 ;
    END
  END aq_q[290]
  PIN aq_q[291]
    DIRECTION INPUT ;
    USE SIGNAL ;
    PORT
      LAYER M5 ;
        RECT  45.408 0 45.432 0.192 ;
    END
  END aq_q[291]
  PIN aq_q[292]
    DIRECTION INPUT ;
    USE SIGNAL ;
    PORT
      LAYER M3 ;
        RECT  45.504 0 45.522 0.144 ;
    END
  END aq_q[292]
  PIN aq_q[293]
    DIRECTION INPUT ;
    USE SIGNAL ;
    PORT
      LAYER M5 ;
        RECT  45.552 0 45.576 0.192 ;
    END
  END aq_q[293]
  PIN aq_q[294]
    DIRECTION INPUT ;
    USE SIGNAL ;
    PORT
      LAYER M3 ;
        RECT  45.648 0 45.666 0.144 ;
    END
  END aq_q[294]
  PIN aq_q[295]
    DIRECTION INPUT ;
    USE SIGNAL ;
    PORT
      LAYER M5 ;
        RECT  45.696 0 45.72 0.192 ;
    END
  END aq_q[295]
  PIN aq_q[296]
    DIRECTION INPUT ;
    USE SIGNAL ;
    PORT
      LAYER M3 ;
        RECT  45.792 0 45.81 0.144 ;
    END
  END aq_q[296]
  PIN aq_q[297]
    DIRECTION INPUT ;
    USE SIGNAL ;
    PORT
      LAYER M5 ;
        RECT  45.84 0 45.864 0.192 ;
    END
  END aq_q[297]
  PIN aq_q[298]
    DIRECTION INPUT ;
    USE SIGNAL ;
    PORT
      LAYER M3 ;
        RECT  45.936 0 45.954 0.144 ;
    END
  END aq_q[298]
  PIN aq_q[299]
    DIRECTION INPUT ;
    USE SIGNAL ;
    PORT
      LAYER M5 ;
        RECT  45.984 0 46.008 0.192 ;
    END
  END aq_q[299]
  PIN aq_q[29]
    DIRECTION INPUT ;
    USE SIGNAL ;
    PORT
      LAYER M5 ;
        RECT  26.544 0 26.568 0.192 ;
    END
  END aq_q[29]
  PIN aq_q[2]
    DIRECTION INPUT ;
    USE SIGNAL ;
    PORT
      LAYER M3 ;
        RECT  24.624 0 24.642 0.144 ;
    END
  END aq_q[2]
  PIN aq_q[300]
    DIRECTION INPUT ;
    USE SIGNAL ;
    PORT
      LAYER M3 ;
        RECT  46.08 0 46.098 0.144 ;
    END
  END aq_q[300]
  PIN aq_q[301]
    DIRECTION INPUT ;
    USE SIGNAL ;
    PORT
      LAYER M5 ;
        RECT  46.128 0 46.152 0.192 ;
    END
  END aq_q[301]
  PIN aq_q[302]
    DIRECTION INPUT ;
    USE SIGNAL ;
    PORT
      LAYER M3 ;
        RECT  46.224 0 46.242 0.144 ;
    END
  END aq_q[302]
  PIN aq_q[303]
    DIRECTION INPUT ;
    USE SIGNAL ;
    PORT
      LAYER M5 ;
        RECT  46.272 0 46.296 0.192 ;
    END
  END aq_q[303]
  PIN aq_q[304]
    DIRECTION INPUT ;
    USE SIGNAL ;
    PORT
      LAYER M3 ;
        RECT  46.368 0 46.386 0.144 ;
    END
  END aq_q[304]
  PIN aq_q[305]
    DIRECTION INPUT ;
    USE SIGNAL ;
    PORT
      LAYER M5 ;
        RECT  46.416 0 46.44 0.192 ;
    END
  END aq_q[305]
  PIN aq_q[306]
    DIRECTION INPUT ;
    USE SIGNAL ;
    PORT
      LAYER M3 ;
        RECT  46.512 0 46.53 0.144 ;
    END
  END aq_q[306]
  PIN aq_q[307]
    DIRECTION INPUT ;
    USE SIGNAL ;
    PORT
      LAYER M5 ;
        RECT  46.56 0 46.584 0.192 ;
    END
  END aq_q[307]
  PIN aq_q[308]
    DIRECTION INPUT ;
    USE SIGNAL ;
    PORT
      LAYER M3 ;
        RECT  46.656 0 46.674 0.144 ;
    END
  END aq_q[308]
  PIN aq_q[309]
    DIRECTION INPUT ;
    USE SIGNAL ;
    PORT
      LAYER M5 ;
        RECT  46.704 0 46.728 0.192 ;
    END
  END aq_q[309]
  PIN aq_q[30]
    DIRECTION INPUT ;
    USE SIGNAL ;
    PORT
      LAYER M3 ;
        RECT  26.64 0 26.658 0.144 ;
    END
  END aq_q[30]
  PIN aq_q[310]
    DIRECTION INPUT ;
    USE SIGNAL ;
    PORT
      LAYER M3 ;
        RECT  46.8 0 46.818 0.144 ;
    END
  END aq_q[310]
  PIN aq_q[311]
    DIRECTION INPUT ;
    USE SIGNAL ;
    PORT
      LAYER M5 ;
        RECT  46.848 0 46.872 0.192 ;
    END
  END aq_q[311]
  PIN aq_q[312]
    DIRECTION INPUT ;
    USE SIGNAL ;
    PORT
      LAYER M3 ;
        RECT  46.944 0 46.962 0.144 ;
    END
  END aq_q[312]
  PIN aq_q[313]
    DIRECTION INPUT ;
    USE SIGNAL ;
    PORT
      LAYER M5 ;
        RECT  46.992 0 47.016 0.192 ;
    END
  END aq_q[313]
  PIN aq_q[314]
    DIRECTION INPUT ;
    USE SIGNAL ;
    PORT
      LAYER M3 ;
        RECT  47.088 0 47.106 0.144 ;
    END
  END aq_q[314]
  PIN aq_q[315]
    DIRECTION INPUT ;
    USE SIGNAL ;
    PORT
      LAYER M5 ;
        RECT  47.136 0 47.16 0.192 ;
    END
  END aq_q[315]
  PIN aq_q[316]
    DIRECTION INPUT ;
    USE SIGNAL ;
    PORT
      LAYER M3 ;
        RECT  47.232 0 47.25 0.144 ;
    END
  END aq_q[316]
  PIN aq_q[317]
    DIRECTION INPUT ;
    USE SIGNAL ;
    PORT
      LAYER M5 ;
        RECT  47.28 0 47.304 0.192 ;
    END
  END aq_q[317]
  PIN aq_q[318]
    DIRECTION INPUT ;
    USE SIGNAL ;
    PORT
      LAYER M3 ;
        RECT  47.376 0 47.394 0.144 ;
    END
  END aq_q[318]
  PIN aq_q[319]
    DIRECTION INPUT ;
    USE SIGNAL ;
    PORT
      LAYER M5 ;
        RECT  47.424 0 47.448 0.192 ;
    END
  END aq_q[319]
  PIN aq_q[31]
    DIRECTION INPUT ;
    USE SIGNAL ;
    PORT
      LAYER M5 ;
        RECT  26.688 0 26.712 0.192 ;
    END
  END aq_q[31]
  PIN aq_q[320]
    DIRECTION INPUT ;
    USE SIGNAL ;
    PORT
      LAYER M3 ;
        RECT  47.52 0 47.538 0.144 ;
    END
  END aq_q[320]
  PIN aq_q[321]
    DIRECTION INPUT ;
    USE SIGNAL ;
    PORT
      LAYER M5 ;
        RECT  47.568 0 47.592 0.192 ;
    END
  END aq_q[321]
  PIN aq_q[322]
    DIRECTION INPUT ;
    USE SIGNAL ;
    PORT
      LAYER M3 ;
        RECT  47.664 0 47.682 0.144 ;
    END
  END aq_q[322]
  PIN aq_q[323]
    DIRECTION INPUT ;
    USE SIGNAL ;
    PORT
      LAYER M5 ;
        RECT  47.712 0 47.736 0.192 ;
    END
  END aq_q[323]
  PIN aq_q[324]
    DIRECTION INPUT ;
    USE SIGNAL ;
    PORT
      LAYER M3 ;
        RECT  47.808 0 47.826 0.144 ;
    END
  END aq_q[324]
  PIN aq_q[325]
    DIRECTION INPUT ;
    USE SIGNAL ;
    PORT
      LAYER M5 ;
        RECT  47.856 0 47.88 0.192 ;
    END
  END aq_q[325]
  PIN aq_q[326]
    DIRECTION INPUT ;
    USE SIGNAL ;
    PORT
      LAYER M3 ;
        RECT  47.952 0 47.97 0.144 ;
    END
  END aq_q[326]
  PIN aq_q[327]
    DIRECTION INPUT ;
    USE SIGNAL ;
    PORT
      LAYER M5 ;
        RECT  48 0 48.024 0.192 ;
    END
  END aq_q[327]
  PIN aq_q[328]
    DIRECTION INPUT ;
    USE SIGNAL ;
    PORT
      LAYER M3 ;
        RECT  48.096 0 48.114 0.144 ;
    END
  END aq_q[328]
  PIN aq_q[329]
    DIRECTION INPUT ;
    USE SIGNAL ;
    PORT
      LAYER M5 ;
        RECT  48.144 0 48.168 0.192 ;
    END
  END aq_q[329]
  PIN aq_q[32]
    DIRECTION INPUT ;
    USE SIGNAL ;
    PORT
      LAYER M3 ;
        RECT  26.784 0 26.802 0.144 ;
    END
  END aq_q[32]
  PIN aq_q[330]
    DIRECTION INPUT ;
    USE SIGNAL ;
    PORT
      LAYER M3 ;
        RECT  48.24 0 48.258 0.144 ;
    END
  END aq_q[330]
  PIN aq_q[331]
    DIRECTION INPUT ;
    USE SIGNAL ;
    PORT
      LAYER M5 ;
        RECT  48.288 0 48.312 0.192 ;
    END
  END aq_q[331]
  PIN aq_q[332]
    DIRECTION INPUT ;
    USE SIGNAL ;
    PORT
      LAYER M3 ;
        RECT  48.384 0 48.402 0.144 ;
    END
  END aq_q[332]
  PIN aq_q[333]
    DIRECTION INPUT ;
    USE SIGNAL ;
    PORT
      LAYER M5 ;
        RECT  48.432 0 48.456 0.192 ;
    END
  END aq_q[333]
  PIN aq_q[334]
    DIRECTION INPUT ;
    USE SIGNAL ;
    PORT
      LAYER M3 ;
        RECT  48.528 0 48.546 0.144 ;
    END
  END aq_q[334]
  PIN aq_q[335]
    DIRECTION INPUT ;
    USE SIGNAL ;
    PORT
      LAYER M5 ;
        RECT  48.576 0 48.6 0.192 ;
    END
  END aq_q[335]
  PIN aq_q[336]
    DIRECTION INPUT ;
    USE SIGNAL ;
    PORT
      LAYER M3 ;
        RECT  48.672 0 48.69 0.144 ;
    END
  END aq_q[336]
  PIN aq_q[337]
    DIRECTION INPUT ;
    USE SIGNAL ;
    PORT
      LAYER M5 ;
        RECT  48.72 0 48.744 0.192 ;
    END
  END aq_q[337]
  PIN aq_q[338]
    DIRECTION INPUT ;
    USE SIGNAL ;
    PORT
      LAYER M3 ;
        RECT  48.816 0 48.834 0.144 ;
    END
  END aq_q[338]
  PIN aq_q[339]
    DIRECTION INPUT ;
    USE SIGNAL ;
    PORT
      LAYER M5 ;
        RECT  48.864 0 48.888 0.192 ;
    END
  END aq_q[339]
  PIN aq_q[33]
    DIRECTION INPUT ;
    USE SIGNAL ;
    PORT
      LAYER M5 ;
        RECT  26.832 0 26.856 0.192 ;
    END
  END aq_q[33]
  PIN aq_q[340]
    DIRECTION INPUT ;
    USE SIGNAL ;
    PORT
      LAYER M3 ;
        RECT  48.96 0 48.978 0.144 ;
    END
  END aq_q[340]
  PIN aq_q[341]
    DIRECTION INPUT ;
    USE SIGNAL ;
    PORT
      LAYER M5 ;
        RECT  49.008 0 49.032 0.192 ;
    END
  END aq_q[341]
  PIN aq_q[342]
    DIRECTION INPUT ;
    USE SIGNAL ;
    PORT
      LAYER M3 ;
        RECT  49.104 0 49.122 0.144 ;
    END
  END aq_q[342]
  PIN aq_q[343]
    DIRECTION INPUT ;
    USE SIGNAL ;
    PORT
      LAYER M5 ;
        RECT  49.152 0 49.176 0.192 ;
    END
  END aq_q[343]
  PIN aq_q[344]
    DIRECTION INPUT ;
    USE SIGNAL ;
    PORT
      LAYER M3 ;
        RECT  49.248 0 49.266 0.144 ;
    END
  END aq_q[344]
  PIN aq_q[345]
    DIRECTION INPUT ;
    USE SIGNAL ;
    PORT
      LAYER M5 ;
        RECT  49.296 0 49.32 0.192 ;
    END
  END aq_q[345]
  PIN aq_q[346]
    DIRECTION INPUT ;
    USE SIGNAL ;
    PORT
      LAYER M3 ;
        RECT  49.392 0 49.41 0.144 ;
    END
  END aq_q[346]
  PIN aq_q[347]
    DIRECTION INPUT ;
    USE SIGNAL ;
    PORT
      LAYER M5 ;
        RECT  49.44 0 49.464 0.192 ;
    END
  END aq_q[347]
  PIN aq_q[348]
    DIRECTION INPUT ;
    USE SIGNAL ;
    PORT
      LAYER M3 ;
        RECT  49.536 0 49.554 0.144 ;
    END
  END aq_q[348]
  PIN aq_q[349]
    DIRECTION INPUT ;
    USE SIGNAL ;
    PORT
      LAYER M5 ;
        RECT  49.584 0 49.608 0.192 ;
    END
  END aq_q[349]
  PIN aq_q[34]
    DIRECTION INPUT ;
    USE SIGNAL ;
    PORT
      LAYER M3 ;
        RECT  26.928 0 26.946 0.144 ;
    END
  END aq_q[34]
  PIN aq_q[350]
    DIRECTION INPUT ;
    USE SIGNAL ;
    PORT
      LAYER M3 ;
        RECT  49.68 0 49.698 0.144 ;
    END
  END aq_q[350]
  PIN aq_q[351]
    DIRECTION INPUT ;
    USE SIGNAL ;
    PORT
      LAYER M5 ;
        RECT  49.728 0 49.752 0.192 ;
    END
  END aq_q[351]
  PIN aq_q[352]
    DIRECTION INPUT ;
    USE SIGNAL ;
    PORT
      LAYER M3 ;
        RECT  49.824 0 49.842 0.144 ;
    END
  END aq_q[352]
  PIN aq_q[353]
    DIRECTION INPUT ;
    USE SIGNAL ;
    PORT
      LAYER M5 ;
        RECT  49.872 0 49.896 0.192 ;
    END
  END aq_q[353]
  PIN aq_q[354]
    DIRECTION INPUT ;
    USE SIGNAL ;
    PORT
      LAYER M3 ;
        RECT  49.968 0 49.986 0.144 ;
    END
  END aq_q[354]
  PIN aq_q[355]
    DIRECTION INPUT ;
    USE SIGNAL ;
    PORT
      LAYER M5 ;
        RECT  50.016 0 50.04 0.192 ;
    END
  END aq_q[355]
  PIN aq_q[356]
    DIRECTION INPUT ;
    USE SIGNAL ;
    PORT
      LAYER M3 ;
        RECT  50.112 0 50.13 0.144 ;
    END
  END aq_q[356]
  PIN aq_q[357]
    DIRECTION INPUT ;
    USE SIGNAL ;
    PORT
      LAYER M5 ;
        RECT  50.16 0 50.184 0.192 ;
    END
  END aq_q[357]
  PIN aq_q[358]
    DIRECTION INPUT ;
    USE SIGNAL ;
    PORT
      LAYER M3 ;
        RECT  50.256 0 50.274 0.144 ;
    END
  END aq_q[358]
  PIN aq_q[359]
    DIRECTION INPUT ;
    USE SIGNAL ;
    PORT
      LAYER M5 ;
        RECT  50.304 0 50.328 0.192 ;
    END
  END aq_q[359]
  PIN aq_q[35]
    DIRECTION INPUT ;
    USE SIGNAL ;
    PORT
      LAYER M5 ;
        RECT  26.976 0 27 0.192 ;
    END
  END aq_q[35]
  PIN aq_q[360]
    DIRECTION INPUT ;
    USE SIGNAL ;
    PORT
      LAYER M3 ;
        RECT  50.4 0 50.418 0.144 ;
    END
  END aq_q[360]
  PIN aq_q[361]
    DIRECTION INPUT ;
    USE SIGNAL ;
    PORT
      LAYER M5 ;
        RECT  50.448 0 50.472 0.192 ;
    END
  END aq_q[361]
  PIN aq_q[362]
    DIRECTION INPUT ;
    USE SIGNAL ;
    PORT
      LAYER M3 ;
        RECT  50.544 0 50.562 0.144 ;
    END
  END aq_q[362]
  PIN aq_q[363]
    DIRECTION INPUT ;
    USE SIGNAL ;
    PORT
      LAYER M5 ;
        RECT  50.592 0 50.616 0.192 ;
    END
  END aq_q[363]
  PIN aq_q[364]
    DIRECTION INPUT ;
    USE SIGNAL ;
    PORT
      LAYER M3 ;
        RECT  50.688 0 50.706 0.144 ;
    END
  END aq_q[364]
  PIN aq_q[365]
    DIRECTION INPUT ;
    USE SIGNAL ;
    PORT
      LAYER M5 ;
        RECT  50.736 0 50.76 0.192 ;
    END
  END aq_q[365]
  PIN aq_q[366]
    DIRECTION INPUT ;
    USE SIGNAL ;
    PORT
      LAYER M3 ;
        RECT  50.832 0 50.85 0.144 ;
    END
  END aq_q[366]
  PIN aq_q[367]
    DIRECTION INPUT ;
    USE SIGNAL ;
    PORT
      LAYER M5 ;
        RECT  50.88 0 50.904 0.192 ;
    END
  END aq_q[367]
  PIN aq_q[368]
    DIRECTION INPUT ;
    USE SIGNAL ;
    PORT
      LAYER M3 ;
        RECT  50.976 0 50.994 0.144 ;
    END
  END aq_q[368]
  PIN aq_q[369]
    DIRECTION INPUT ;
    USE SIGNAL ;
    PORT
      LAYER M5 ;
        RECT  51.024 0 51.048 0.192 ;
    END
  END aq_q[369]
  PIN aq_q[36]
    DIRECTION INPUT ;
    USE SIGNAL ;
    PORT
      LAYER M3 ;
        RECT  27.072 0 27.09 0.144 ;
    END
  END aq_q[36]
  PIN aq_q[370]
    DIRECTION INPUT ;
    USE SIGNAL ;
    PORT
      LAYER M3 ;
        RECT  51.12 0 51.138 0.144 ;
    END
  END aq_q[370]
  PIN aq_q[371]
    DIRECTION INPUT ;
    USE SIGNAL ;
    PORT
      LAYER M5 ;
        RECT  51.168 0 51.192 0.192 ;
    END
  END aq_q[371]
  PIN aq_q[372]
    DIRECTION INPUT ;
    USE SIGNAL ;
    PORT
      LAYER M3 ;
        RECT  51.264 0 51.282 0.144 ;
    END
  END aq_q[372]
  PIN aq_q[373]
    DIRECTION INPUT ;
    USE SIGNAL ;
    PORT
      LAYER M5 ;
        RECT  51.312 0 51.336 0.192 ;
    END
  END aq_q[373]
  PIN aq_q[374]
    DIRECTION INPUT ;
    USE SIGNAL ;
    PORT
      LAYER M3 ;
        RECT  51.408 0 51.426 0.144 ;
    END
  END aq_q[374]
  PIN aq_q[375]
    DIRECTION INPUT ;
    USE SIGNAL ;
    PORT
      LAYER M5 ;
        RECT  51.456 0 51.48 0.192 ;
    END
  END aq_q[375]
  PIN aq_q[376]
    DIRECTION INPUT ;
    USE SIGNAL ;
    PORT
      LAYER M3 ;
        RECT  51.552 0 51.57 0.144 ;
    END
  END aq_q[376]
  PIN aq_q[377]
    DIRECTION INPUT ;
    USE SIGNAL ;
    PORT
      LAYER M5 ;
        RECT  51.6 0 51.624 0.192 ;
    END
  END aq_q[377]
  PIN aq_q[378]
    DIRECTION INPUT ;
    USE SIGNAL ;
    PORT
      LAYER M3 ;
        RECT  51.696 0 51.714 0.144 ;
    END
  END aq_q[378]
  PIN aq_q[379]
    DIRECTION INPUT ;
    USE SIGNAL ;
    PORT
      LAYER M5 ;
        RECT  51.744 0 51.768 0.192 ;
    END
  END aq_q[379]
  PIN aq_q[37]
    DIRECTION INPUT ;
    USE SIGNAL ;
    PORT
      LAYER M5 ;
        RECT  27.12 0 27.144 0.192 ;
    END
  END aq_q[37]
  PIN aq_q[380]
    DIRECTION INPUT ;
    USE SIGNAL ;
    PORT
      LAYER M3 ;
        RECT  51.84 0 51.858 0.144 ;
    END
  END aq_q[380]
  PIN aq_q[381]
    DIRECTION INPUT ;
    USE SIGNAL ;
    PORT
      LAYER M5 ;
        RECT  51.888 0 51.912 0.192 ;
    END
  END aq_q[381]
  PIN aq_q[382]
    DIRECTION INPUT ;
    USE SIGNAL ;
    PORT
      LAYER M3 ;
        RECT  51.984 0 52.002 0.144 ;
    END
  END aq_q[382]
  PIN aq_q[383]
    DIRECTION INPUT ;
    USE SIGNAL ;
    PORT
      LAYER M5 ;
        RECT  52.032 0 52.056 0.192 ;
    END
  END aq_q[383]
  PIN aq_q[384]
    DIRECTION INPUT ;
    USE SIGNAL ;
    PORT
      LAYER M3 ;
        RECT  52.128 0 52.146 0.144 ;
    END
  END aq_q[384]
  PIN aq_q[385]
    DIRECTION INPUT ;
    USE SIGNAL ;
    PORT
      LAYER M5 ;
        RECT  52.176 0 52.2 0.192 ;
    END
  END aq_q[385]
  PIN aq_q[386]
    DIRECTION INPUT ;
    USE SIGNAL ;
    PORT
      LAYER M3 ;
        RECT  52.272 0 52.29 0.144 ;
    END
  END aq_q[386]
  PIN aq_q[387]
    DIRECTION INPUT ;
    USE SIGNAL ;
    PORT
      LAYER M5 ;
        RECT  52.32 0 52.344 0.192 ;
    END
  END aq_q[387]
  PIN aq_q[388]
    DIRECTION INPUT ;
    USE SIGNAL ;
    PORT
      LAYER M3 ;
        RECT  52.416 0 52.434 0.144 ;
    END
  END aq_q[388]
  PIN aq_q[389]
    DIRECTION INPUT ;
    USE SIGNAL ;
    PORT
      LAYER M5 ;
        RECT  52.464 0 52.488 0.192 ;
    END
  END aq_q[389]
  PIN aq_q[38]
    DIRECTION INPUT ;
    USE SIGNAL ;
    PORT
      LAYER M3 ;
        RECT  27.216 0 27.234 0.144 ;
    END
  END aq_q[38]
  PIN aq_q[390]
    DIRECTION INPUT ;
    USE SIGNAL ;
    PORT
      LAYER M3 ;
        RECT  52.56 0 52.578 0.144 ;
    END
  END aq_q[390]
  PIN aq_q[391]
    DIRECTION INPUT ;
    USE SIGNAL ;
    PORT
      LAYER M5 ;
        RECT  52.608 0 52.632 0.192 ;
    END
  END aq_q[391]
  PIN aq_q[392]
    DIRECTION INPUT ;
    USE SIGNAL ;
    PORT
      LAYER M3 ;
        RECT  52.704 0 52.722 0.144 ;
    END
  END aq_q[392]
  PIN aq_q[393]
    DIRECTION INPUT ;
    USE SIGNAL ;
    PORT
      LAYER M5 ;
        RECT  52.752 0 52.776 0.192 ;
    END
  END aq_q[393]
  PIN aq_q[394]
    DIRECTION INPUT ;
    USE SIGNAL ;
    PORT
      LAYER M3 ;
        RECT  52.848 0 52.866 0.144 ;
    END
  END aq_q[394]
  PIN aq_q[395]
    DIRECTION INPUT ;
    USE SIGNAL ;
    PORT
      LAYER M5 ;
        RECT  52.896 0 52.92 0.192 ;
    END
  END aq_q[395]
  PIN aq_q[396]
    DIRECTION INPUT ;
    USE SIGNAL ;
    PORT
      LAYER M3 ;
        RECT  52.992 0 53.01 0.144 ;
    END
  END aq_q[396]
  PIN aq_q[397]
    DIRECTION INPUT ;
    USE SIGNAL ;
    PORT
      LAYER M5 ;
        RECT  53.04 0 53.064 0.192 ;
    END
  END aq_q[397]
  PIN aq_q[398]
    DIRECTION INPUT ;
    USE SIGNAL ;
    PORT
      LAYER M3 ;
        RECT  53.136 0 53.154 0.144 ;
    END
  END aq_q[398]
  PIN aq_q[399]
    DIRECTION INPUT ;
    USE SIGNAL ;
    PORT
      LAYER M5 ;
        RECT  53.184 0 53.208 0.192 ;
    END
  END aq_q[399]
  PIN aq_q[39]
    DIRECTION INPUT ;
    USE SIGNAL ;
    PORT
      LAYER M5 ;
        RECT  27.264 0 27.288 0.192 ;
    END
  END aq_q[39]
  PIN aq_q[3]
    DIRECTION INPUT ;
    USE SIGNAL ;
    PORT
      LAYER M5 ;
        RECT  24.672 0 24.696 0.192 ;
    END
  END aq_q[3]
  PIN aq_q[400]
    DIRECTION INPUT ;
    USE SIGNAL ;
    PORT
      LAYER M3 ;
        RECT  53.28 0 53.298 0.144 ;
    END
  END aq_q[400]
  PIN aq_q[401]
    DIRECTION INPUT ;
    USE SIGNAL ;
    PORT
      LAYER M5 ;
        RECT  53.328 0 53.352 0.192 ;
    END
  END aq_q[401]
  PIN aq_q[402]
    DIRECTION INPUT ;
    USE SIGNAL ;
    PORT
      LAYER M3 ;
        RECT  53.424 0 53.442 0.144 ;
    END
  END aq_q[402]
  PIN aq_q[403]
    DIRECTION INPUT ;
    USE SIGNAL ;
    PORT
      LAYER M5 ;
        RECT  53.472 0 53.496 0.192 ;
    END
  END aq_q[403]
  PIN aq_q[404]
    DIRECTION INPUT ;
    USE SIGNAL ;
    PORT
      LAYER M3 ;
        RECT  53.568 0 53.586 0.144 ;
    END
  END aq_q[404]
  PIN aq_q[405]
    DIRECTION INPUT ;
    USE SIGNAL ;
    PORT
      LAYER M5 ;
        RECT  53.616 0 53.64 0.192 ;
    END
  END aq_q[405]
  PIN aq_q[406]
    DIRECTION INPUT ;
    USE SIGNAL ;
    PORT
      LAYER M3 ;
        RECT  53.712 0 53.73 0.144 ;
    END
  END aq_q[406]
  PIN aq_q[407]
    DIRECTION INPUT ;
    USE SIGNAL ;
    PORT
      LAYER M5 ;
        RECT  53.76 0 53.784 0.192 ;
    END
  END aq_q[407]
  PIN aq_q[408]
    DIRECTION INPUT ;
    USE SIGNAL ;
    PORT
      LAYER M3 ;
        RECT  53.856 0 53.874 0.144 ;
    END
  END aq_q[408]
  PIN aq_q[409]
    DIRECTION INPUT ;
    USE SIGNAL ;
    PORT
      LAYER M5 ;
        RECT  53.904 0 53.928 0.192 ;
    END
  END aq_q[409]
  PIN aq_q[40]
    DIRECTION INPUT ;
    USE SIGNAL ;
    PORT
      LAYER M3 ;
        RECT  27.36 0 27.378 0.144 ;
    END
  END aq_q[40]
  PIN aq_q[410]
    DIRECTION INPUT ;
    USE SIGNAL ;
    PORT
      LAYER M3 ;
        RECT  54 0 54.018 0.144 ;
    END
  END aq_q[410]
  PIN aq_q[411]
    DIRECTION INPUT ;
    USE SIGNAL ;
    PORT
      LAYER M5 ;
        RECT  54.048 0 54.072 0.192 ;
    END
  END aq_q[411]
  PIN aq_q[412]
    DIRECTION INPUT ;
    USE SIGNAL ;
    PORT
      LAYER M3 ;
        RECT  54.144 0 54.162 0.144 ;
    END
  END aq_q[412]
  PIN aq_q[413]
    DIRECTION INPUT ;
    USE SIGNAL ;
    PORT
      LAYER M5 ;
        RECT  54.192 0 54.216 0.192 ;
    END
  END aq_q[413]
  PIN aq_q[414]
    DIRECTION INPUT ;
    USE SIGNAL ;
    PORT
      LAYER M3 ;
        RECT  54.288 0 54.306 0.144 ;
    END
  END aq_q[414]
  PIN aq_q[415]
    DIRECTION INPUT ;
    USE SIGNAL ;
    PORT
      LAYER M5 ;
        RECT  54.336 0 54.36 0.192 ;
    END
  END aq_q[415]
  PIN aq_q[416]
    DIRECTION INPUT ;
    USE SIGNAL ;
    PORT
      LAYER M3 ;
        RECT  54.432 0 54.45 0.144 ;
    END
  END aq_q[416]
  PIN aq_q[417]
    DIRECTION INPUT ;
    USE SIGNAL ;
    PORT
      LAYER M5 ;
        RECT  54.48 0 54.504 0.192 ;
    END
  END aq_q[417]
  PIN aq_q[418]
    DIRECTION INPUT ;
    USE SIGNAL ;
    PORT
      LAYER M3 ;
        RECT  54.576 0 54.594 0.144 ;
    END
  END aq_q[418]
  PIN aq_q[419]
    DIRECTION INPUT ;
    USE SIGNAL ;
    PORT
      LAYER M5 ;
        RECT  54.624 0 54.648 0.192 ;
    END
  END aq_q[419]
  PIN aq_q[41]
    DIRECTION INPUT ;
    USE SIGNAL ;
    PORT
      LAYER M5 ;
        RECT  27.408 0 27.432 0.192 ;
    END
  END aq_q[41]
  PIN aq_q[420]
    DIRECTION INPUT ;
    USE SIGNAL ;
    PORT
      LAYER M3 ;
        RECT  54.72 0 54.738 0.144 ;
    END
  END aq_q[420]
  PIN aq_q[421]
    DIRECTION INPUT ;
    USE SIGNAL ;
    PORT
      LAYER M5 ;
        RECT  54.768 0 54.792 0.192 ;
    END
  END aq_q[421]
  PIN aq_q[422]
    DIRECTION INPUT ;
    USE SIGNAL ;
    PORT
      LAYER M3 ;
        RECT  54.864 0 54.882 0.144 ;
    END
  END aq_q[422]
  PIN aq_q[423]
    DIRECTION INPUT ;
    USE SIGNAL ;
    PORT
      LAYER M5 ;
        RECT  54.912 0 54.936 0.192 ;
    END
  END aq_q[423]
  PIN aq_q[424]
    DIRECTION INPUT ;
    USE SIGNAL ;
    PORT
      LAYER M3 ;
        RECT  55.008 0 55.026 0.144 ;
    END
  END aq_q[424]
  PIN aq_q[425]
    DIRECTION INPUT ;
    USE SIGNAL ;
    PORT
      LAYER M5 ;
        RECT  55.056 0 55.08 0.192 ;
    END
  END aq_q[425]
  PIN aq_q[426]
    DIRECTION INPUT ;
    USE SIGNAL ;
    PORT
      LAYER M3 ;
        RECT  55.152 0 55.17 0.144 ;
    END
  END aq_q[426]
  PIN aq_q[427]
    DIRECTION INPUT ;
    USE SIGNAL ;
    PORT
      LAYER M5 ;
        RECT  55.2 0 55.224 0.192 ;
    END
  END aq_q[427]
  PIN aq_q[428]
    DIRECTION INPUT ;
    USE SIGNAL ;
    PORT
      LAYER M3 ;
        RECT  55.296 0 55.314 0.144 ;
    END
  END aq_q[428]
  PIN aq_q[429]
    DIRECTION INPUT ;
    USE SIGNAL ;
    PORT
      LAYER M5 ;
        RECT  55.344 0 55.368 0.192 ;
    END
  END aq_q[429]
  PIN aq_q[42]
    DIRECTION INPUT ;
    USE SIGNAL ;
    PORT
      LAYER M3 ;
        RECT  27.504 0 27.522 0.144 ;
    END
  END aq_q[42]
  PIN aq_q[430]
    DIRECTION INPUT ;
    USE SIGNAL ;
    PORT
      LAYER M3 ;
        RECT  55.44 0 55.458 0.144 ;
    END
  END aq_q[430]
  PIN aq_q[431]
    DIRECTION INPUT ;
    USE SIGNAL ;
    PORT
      LAYER M5 ;
        RECT  55.488 0 55.512 0.192 ;
    END
  END aq_q[431]
  PIN aq_q[432]
    DIRECTION INPUT ;
    USE SIGNAL ;
    PORT
      LAYER M3 ;
        RECT  55.584 0 55.602 0.144 ;
    END
  END aq_q[432]
  PIN aq_q[433]
    DIRECTION INPUT ;
    USE SIGNAL ;
    PORT
      LAYER M5 ;
        RECT  55.632 0 55.656 0.192 ;
    END
  END aq_q[433]
  PIN aq_q[434]
    DIRECTION INPUT ;
    USE SIGNAL ;
    PORT
      LAYER M3 ;
        RECT  55.728 0 55.746 0.144 ;
    END
  END aq_q[434]
  PIN aq_q[435]
    DIRECTION INPUT ;
    USE SIGNAL ;
    PORT
      LAYER M5 ;
        RECT  55.776 0 55.8 0.192 ;
    END
  END aq_q[435]
  PIN aq_q[436]
    DIRECTION INPUT ;
    USE SIGNAL ;
    PORT
      LAYER M3 ;
        RECT  55.872 0 55.89 0.144 ;
    END
  END aq_q[436]
  PIN aq_q[437]
    DIRECTION INPUT ;
    USE SIGNAL ;
    PORT
      LAYER M5 ;
        RECT  55.92 0 55.944 0.192 ;
    END
  END aq_q[437]
  PIN aq_q[438]
    DIRECTION INPUT ;
    USE SIGNAL ;
    PORT
      LAYER M3 ;
        RECT  56.016 0 56.034 0.144 ;
    END
  END aq_q[438]
  PIN aq_q[439]
    DIRECTION INPUT ;
    USE SIGNAL ;
    PORT
      LAYER M5 ;
        RECT  56.064 0 56.088 0.192 ;
    END
  END aq_q[439]
  PIN aq_q[43]
    DIRECTION INPUT ;
    USE SIGNAL ;
    PORT
      LAYER M5 ;
        RECT  27.552 0 27.576 0.192 ;
    END
  END aq_q[43]
  PIN aq_q[440]
    DIRECTION INPUT ;
    USE SIGNAL ;
    PORT
      LAYER M3 ;
        RECT  56.16 0 56.178 0.144 ;
    END
  END aq_q[440]
  PIN aq_q[441]
    DIRECTION INPUT ;
    USE SIGNAL ;
    PORT
      LAYER M5 ;
        RECT  56.208 0 56.232 0.192 ;
    END
  END aq_q[441]
  PIN aq_q[442]
    DIRECTION INPUT ;
    USE SIGNAL ;
    PORT
      LAYER M3 ;
        RECT  56.304 0 56.322 0.144 ;
    END
  END aq_q[442]
  PIN aq_q[443]
    DIRECTION INPUT ;
    USE SIGNAL ;
    PORT
      LAYER M5 ;
        RECT  56.352 0 56.376 0.192 ;
    END
  END aq_q[443]
  PIN aq_q[444]
    DIRECTION INPUT ;
    USE SIGNAL ;
    PORT
      LAYER M3 ;
        RECT  56.448 0 56.466 0.144 ;
    END
  END aq_q[444]
  PIN aq_q[445]
    DIRECTION INPUT ;
    USE SIGNAL ;
    PORT
      LAYER M5 ;
        RECT  56.496 0 56.52 0.192 ;
    END
  END aq_q[445]
  PIN aq_q[446]
    DIRECTION INPUT ;
    USE SIGNAL ;
    PORT
      LAYER M3 ;
        RECT  56.592 0 56.61 0.144 ;
    END
  END aq_q[446]
  PIN aq_q[447]
    DIRECTION INPUT ;
    USE SIGNAL ;
    PORT
      LAYER M5 ;
        RECT  56.64 0 56.664 0.192 ;
    END
  END aq_q[447]
  PIN aq_q[448]
    DIRECTION INPUT ;
    USE SIGNAL ;
    PORT
      LAYER M3 ;
        RECT  56.736 0 56.754 0.144 ;
    END
  END aq_q[448]
  PIN aq_q[449]
    DIRECTION INPUT ;
    USE SIGNAL ;
    PORT
      LAYER M5 ;
        RECT  56.784 0 56.808 0.192 ;
    END
  END aq_q[449]
  PIN aq_q[44]
    DIRECTION INPUT ;
    USE SIGNAL ;
    PORT
      LAYER M3 ;
        RECT  27.648 0 27.666 0.144 ;
    END
  END aq_q[44]
  PIN aq_q[450]
    DIRECTION INPUT ;
    USE SIGNAL ;
    PORT
      LAYER M3 ;
        RECT  56.88 0 56.898 0.144 ;
    END
  END aq_q[450]
  PIN aq_q[451]
    DIRECTION INPUT ;
    USE SIGNAL ;
    PORT
      LAYER M5 ;
        RECT  56.928 0 56.952 0.192 ;
    END
  END aq_q[451]
  PIN aq_q[452]
    DIRECTION INPUT ;
    USE SIGNAL ;
    PORT
      LAYER M3 ;
        RECT  57.024 0 57.042 0.144 ;
    END
  END aq_q[452]
  PIN aq_q[453]
    DIRECTION INPUT ;
    USE SIGNAL ;
    PORT
      LAYER M5 ;
        RECT  57.072 0 57.096 0.192 ;
    END
  END aq_q[453]
  PIN aq_q[454]
    DIRECTION INPUT ;
    USE SIGNAL ;
    PORT
      LAYER M3 ;
        RECT  57.168 0 57.186 0.144 ;
    END
  END aq_q[454]
  PIN aq_q[455]
    DIRECTION INPUT ;
    USE SIGNAL ;
    PORT
      LAYER M5 ;
        RECT  57.216 0 57.24 0.192 ;
    END
  END aq_q[455]
  PIN aq_q[456]
    DIRECTION INPUT ;
    USE SIGNAL ;
    PORT
      LAYER M3 ;
        RECT  57.312 0 57.33 0.144 ;
    END
  END aq_q[456]
  PIN aq_q[457]
    DIRECTION INPUT ;
    USE SIGNAL ;
    PORT
      LAYER M5 ;
        RECT  57.36 0 57.384 0.192 ;
    END
  END aq_q[457]
  PIN aq_q[458]
    DIRECTION INPUT ;
    USE SIGNAL ;
    PORT
      LAYER M3 ;
        RECT  57.456 0 57.474 0.144 ;
    END
  END aq_q[458]
  PIN aq_q[459]
    DIRECTION INPUT ;
    USE SIGNAL ;
    PORT
      LAYER M5 ;
        RECT  57.504 0 57.528 0.192 ;
    END
  END aq_q[459]
  PIN aq_q[45]
    DIRECTION INPUT ;
    USE SIGNAL ;
    PORT
      LAYER M5 ;
        RECT  27.696 0 27.72 0.192 ;
    END
  END aq_q[45]
  PIN aq_q[460]
    DIRECTION INPUT ;
    USE SIGNAL ;
    PORT
      LAYER M3 ;
        RECT  57.6 0 57.618 0.144 ;
    END
  END aq_q[460]
  PIN aq_q[461]
    DIRECTION INPUT ;
    USE SIGNAL ;
    PORT
      LAYER M5 ;
        RECT  57.648 0 57.672 0.192 ;
    END
  END aq_q[461]
  PIN aq_q[462]
    DIRECTION INPUT ;
    USE SIGNAL ;
    PORT
      LAYER M3 ;
        RECT  57.744 0 57.762 0.144 ;
    END
  END aq_q[462]
  PIN aq_q[463]
    DIRECTION INPUT ;
    USE SIGNAL ;
    PORT
      LAYER M5 ;
        RECT  57.792 0 57.816 0.192 ;
    END
  END aq_q[463]
  PIN aq_q[464]
    DIRECTION INPUT ;
    USE SIGNAL ;
    PORT
      LAYER M3 ;
        RECT  57.888 0 57.906 0.144 ;
    END
  END aq_q[464]
  PIN aq_q[465]
    DIRECTION INPUT ;
    USE SIGNAL ;
    PORT
      LAYER M5 ;
        RECT  57.936 0 57.96 0.192 ;
    END
  END aq_q[465]
  PIN aq_q[466]
    DIRECTION INPUT ;
    USE SIGNAL ;
    PORT
      LAYER M3 ;
        RECT  58.032 0 58.05 0.144 ;
    END
  END aq_q[466]
  PIN aq_q[467]
    DIRECTION INPUT ;
    USE SIGNAL ;
    PORT
      LAYER M5 ;
        RECT  58.08 0 58.104 0.192 ;
    END
  END aq_q[467]
  PIN aq_q[468]
    DIRECTION INPUT ;
    USE SIGNAL ;
    PORT
      LAYER M3 ;
        RECT  58.176 0 58.194 0.144 ;
    END
  END aq_q[468]
  PIN aq_q[469]
    DIRECTION INPUT ;
    USE SIGNAL ;
    PORT
      LAYER M5 ;
        RECT  58.224 0 58.248 0.192 ;
    END
  END aq_q[469]
  PIN aq_q[46]
    DIRECTION INPUT ;
    USE SIGNAL ;
    PORT
      LAYER M3 ;
        RECT  27.792 0 27.81 0.144 ;
    END
  END aq_q[46]
  PIN aq_q[470]
    DIRECTION INPUT ;
    USE SIGNAL ;
    PORT
      LAYER M3 ;
        RECT  58.32 0 58.338 0.144 ;
    END
  END aq_q[470]
  PIN aq_q[471]
    DIRECTION INPUT ;
    USE SIGNAL ;
    PORT
      LAYER M5 ;
        RECT  58.368 0 58.392 0.192 ;
    END
  END aq_q[471]
  PIN aq_q[472]
    DIRECTION INPUT ;
    USE SIGNAL ;
    PORT
      LAYER M3 ;
        RECT  58.464 0 58.482 0.144 ;
    END
  END aq_q[472]
  PIN aq_q[473]
    DIRECTION INPUT ;
    USE SIGNAL ;
    PORT
      LAYER M5 ;
        RECT  58.512 0 58.536 0.192 ;
    END
  END aq_q[473]
  PIN aq_q[474]
    DIRECTION INPUT ;
    USE SIGNAL ;
    PORT
      LAYER M3 ;
        RECT  58.608 0 58.626 0.144 ;
    END
  END aq_q[474]
  PIN aq_q[475]
    DIRECTION INPUT ;
    USE SIGNAL ;
    PORT
      LAYER M5 ;
        RECT  58.656 0 58.68 0.192 ;
    END
  END aq_q[475]
  PIN aq_q[476]
    DIRECTION INPUT ;
    USE SIGNAL ;
    PORT
      LAYER M3 ;
        RECT  58.752 0 58.77 0.144 ;
    END
  END aq_q[476]
  PIN aq_q[477]
    DIRECTION INPUT ;
    USE SIGNAL ;
    PORT
      LAYER M5 ;
        RECT  58.8 0 58.824 0.192 ;
    END
  END aq_q[477]
  PIN aq_q[478]
    DIRECTION INPUT ;
    USE SIGNAL ;
    PORT
      LAYER M3 ;
        RECT  58.896 0 58.914 0.144 ;
    END
  END aq_q[478]
  PIN aq_q[479]
    DIRECTION INPUT ;
    USE SIGNAL ;
    PORT
      LAYER M5 ;
        RECT  58.944 0 58.968 0.192 ;
    END
  END aq_q[479]
  PIN aq_q[47]
    DIRECTION INPUT ;
    USE SIGNAL ;
    PORT
      LAYER M5 ;
        RECT  27.84 0 27.864 0.192 ;
    END
  END aq_q[47]
  PIN aq_q[480]
    DIRECTION INPUT ;
    USE SIGNAL ;
    PORT
      LAYER M3 ;
        RECT  59.04 0 59.058 0.144 ;
    END
  END aq_q[480]
  PIN aq_q[481]
    DIRECTION INPUT ;
    USE SIGNAL ;
    PORT
      LAYER M5 ;
        RECT  59.088 0 59.112 0.192 ;
    END
  END aq_q[481]
  PIN aq_q[482]
    DIRECTION INPUT ;
    USE SIGNAL ;
    PORT
      LAYER M3 ;
        RECT  59.184 0 59.202 0.144 ;
    END
  END aq_q[482]
  PIN aq_q[483]
    DIRECTION INPUT ;
    USE SIGNAL ;
    PORT
      LAYER M5 ;
        RECT  59.232 0 59.256 0.192 ;
    END
  END aq_q[483]
  PIN aq_q[484]
    DIRECTION INPUT ;
    USE SIGNAL ;
    PORT
      LAYER M3 ;
        RECT  59.328 0 59.346 0.144 ;
    END
  END aq_q[484]
  PIN aq_q[485]
    DIRECTION INPUT ;
    USE SIGNAL ;
    PORT
      LAYER M5 ;
        RECT  59.376 0 59.4 0.192 ;
    END
  END aq_q[485]
  PIN aq_q[486]
    DIRECTION INPUT ;
    USE SIGNAL ;
    PORT
      LAYER M3 ;
        RECT  59.472 0 59.49 0.144 ;
    END
  END aq_q[486]
  PIN aq_q[487]
    DIRECTION INPUT ;
    USE SIGNAL ;
    PORT
      LAYER M5 ;
        RECT  59.52 0 59.544 0.192 ;
    END
  END aq_q[487]
  PIN aq_q[488]
    DIRECTION INPUT ;
    USE SIGNAL ;
    PORT
      LAYER M3 ;
        RECT  59.616 0 59.634 0.144 ;
    END
  END aq_q[488]
  PIN aq_q[489]
    DIRECTION INPUT ;
    USE SIGNAL ;
    PORT
      LAYER M5 ;
        RECT  59.664 0 59.688 0.192 ;
    END
  END aq_q[489]
  PIN aq_q[48]
    DIRECTION INPUT ;
    USE SIGNAL ;
    PORT
      LAYER M3 ;
        RECT  27.936 0 27.954 0.144 ;
    END
  END aq_q[48]
  PIN aq_q[490]
    DIRECTION INPUT ;
    USE SIGNAL ;
    PORT
      LAYER M3 ;
        RECT  59.76 0 59.778 0.144 ;
    END
  END aq_q[490]
  PIN aq_q[491]
    DIRECTION INPUT ;
    USE SIGNAL ;
    PORT
      LAYER M5 ;
        RECT  59.808 0 59.832 0.192 ;
    END
  END aq_q[491]
  PIN aq_q[492]
    DIRECTION INPUT ;
    USE SIGNAL ;
    PORT
      LAYER M3 ;
        RECT  59.904 0 59.922 0.144 ;
    END
  END aq_q[492]
  PIN aq_q[493]
    DIRECTION INPUT ;
    USE SIGNAL ;
    PORT
      LAYER M5 ;
        RECT  59.952 0 59.976 0.192 ;
    END
  END aq_q[493]
  PIN aq_q[494]
    DIRECTION INPUT ;
    USE SIGNAL ;
    PORT
      LAYER M3 ;
        RECT  60.048 0 60.066 0.144 ;
    END
  END aq_q[494]
  PIN aq_q[495]
    DIRECTION INPUT ;
    USE SIGNAL ;
    PORT
      LAYER M5 ;
        RECT  60.096 0 60.12 0.192 ;
    END
  END aq_q[495]
  PIN aq_q[496]
    DIRECTION INPUT ;
    USE SIGNAL ;
    PORT
      LAYER M3 ;
        RECT  60.192 0 60.21 0.144 ;
    END
  END aq_q[496]
  PIN aq_q[497]
    DIRECTION INPUT ;
    USE SIGNAL ;
    PORT
      LAYER M5 ;
        RECT  60.24 0 60.264 0.192 ;
    END
  END aq_q[497]
  PIN aq_q[498]
    DIRECTION INPUT ;
    USE SIGNAL ;
    PORT
      LAYER M3 ;
        RECT  60.336 0 60.354 0.144 ;
    END
  END aq_q[498]
  PIN aq_q[499]
    DIRECTION INPUT ;
    USE SIGNAL ;
    PORT
      LAYER M5 ;
        RECT  60.384 0 60.408 0.192 ;
    END
  END aq_q[499]
  PIN aq_q[49]
    DIRECTION INPUT ;
    USE SIGNAL ;
    PORT
      LAYER M5 ;
        RECT  27.984 0 28.008 0.192 ;
    END
  END aq_q[49]
  PIN aq_q[4]
    DIRECTION INPUT ;
    USE SIGNAL ;
    PORT
      LAYER M3 ;
        RECT  24.768 0 24.786 0.144 ;
    END
  END aq_q[4]
  PIN aq_q[500]
    DIRECTION INPUT ;
    USE SIGNAL ;
    PORT
      LAYER M3 ;
        RECT  60.48 0 60.498 0.144 ;
    END
  END aq_q[500]
  PIN aq_q[501]
    DIRECTION INPUT ;
    USE SIGNAL ;
    PORT
      LAYER M5 ;
        RECT  60.528 0 60.552 0.192 ;
    END
  END aq_q[501]
  PIN aq_q[502]
    DIRECTION INPUT ;
    USE SIGNAL ;
    PORT
      LAYER M3 ;
        RECT  60.624 0 60.642 0.144 ;
    END
  END aq_q[502]
  PIN aq_q[503]
    DIRECTION INPUT ;
    USE SIGNAL ;
    PORT
      LAYER M5 ;
        RECT  60.672 0 60.696 0.192 ;
    END
  END aq_q[503]
  PIN aq_q[504]
    DIRECTION INPUT ;
    USE SIGNAL ;
    PORT
      LAYER M3 ;
        RECT  60.768 0 60.786 0.144 ;
    END
  END aq_q[504]
  PIN aq_q[505]
    DIRECTION INPUT ;
    USE SIGNAL ;
    PORT
      LAYER M5 ;
        RECT  60.816 0 60.84 0.192 ;
    END
  END aq_q[505]
  PIN aq_q[506]
    DIRECTION INPUT ;
    USE SIGNAL ;
    PORT
      LAYER M3 ;
        RECT  60.912 0 60.93 0.144 ;
    END
  END aq_q[506]
  PIN aq_q[507]
    DIRECTION INPUT ;
    USE SIGNAL ;
    PORT
      LAYER M5 ;
        RECT  60.96 0 60.984 0.192 ;
    END
  END aq_q[507]
  PIN aq_q[508]
    DIRECTION INPUT ;
    USE SIGNAL ;
    PORT
      LAYER M3 ;
        RECT  61.056 0 61.074 0.144 ;
    END
  END aq_q[508]
  PIN aq_q[509]
    DIRECTION INPUT ;
    USE SIGNAL ;
    PORT
      LAYER M5 ;
        RECT  61.104 0 61.128 0.192 ;
    END
  END aq_q[509]
  PIN aq_q[50]
    DIRECTION INPUT ;
    USE SIGNAL ;
    PORT
      LAYER M3 ;
        RECT  28.08 0 28.098 0.144 ;
    END
  END aq_q[50]
  PIN aq_q[510]
    DIRECTION INPUT ;
    USE SIGNAL ;
    PORT
      LAYER M3 ;
        RECT  61.2 0 61.218 0.144 ;
    END
  END aq_q[510]
  PIN aq_q[511]
    DIRECTION INPUT ;
    USE SIGNAL ;
    PORT
      LAYER M5 ;
        RECT  61.248 0 61.272 0.192 ;
    END
  END aq_q[511]
  PIN aq_q[51]
    DIRECTION INPUT ;
    USE SIGNAL ;
    PORT
      LAYER M5 ;
        RECT  28.128 0 28.152 0.192 ;
    END
  END aq_q[51]
  PIN aq_q[52]
    DIRECTION INPUT ;
    USE SIGNAL ;
    PORT
      LAYER M3 ;
        RECT  28.224 0 28.242 0.144 ;
    END
  END aq_q[52]
  PIN aq_q[53]
    DIRECTION INPUT ;
    USE SIGNAL ;
    PORT
      LAYER M5 ;
        RECT  28.272 0 28.296 0.192 ;
    END
  END aq_q[53]
  PIN aq_q[54]
    DIRECTION INPUT ;
    USE SIGNAL ;
    PORT
      LAYER M3 ;
        RECT  28.368 0 28.386 0.144 ;
    END
  END aq_q[54]
  PIN aq_q[55]
    DIRECTION INPUT ;
    USE SIGNAL ;
    PORT
      LAYER M5 ;
        RECT  28.416 0 28.44 0.192 ;
    END
  END aq_q[55]
  PIN aq_q[56]
    DIRECTION INPUT ;
    USE SIGNAL ;
    PORT
      LAYER M3 ;
        RECT  28.512 0 28.53 0.144 ;
    END
  END aq_q[56]
  PIN aq_q[57]
    DIRECTION INPUT ;
    USE SIGNAL ;
    PORT
      LAYER M5 ;
        RECT  28.56 0 28.584 0.192 ;
    END
  END aq_q[57]
  PIN aq_q[58]
    DIRECTION INPUT ;
    USE SIGNAL ;
    PORT
      LAYER M3 ;
        RECT  28.656 0 28.674 0.144 ;
    END
  END aq_q[58]
  PIN aq_q[59]
    DIRECTION INPUT ;
    USE SIGNAL ;
    PORT
      LAYER M5 ;
        RECT  28.704 0 28.728 0.192 ;
    END
  END aq_q[59]
  PIN aq_q[5]
    DIRECTION INPUT ;
    USE SIGNAL ;
    PORT
      LAYER M5 ;
        RECT  24.816 0 24.84 0.192 ;
    END
  END aq_q[5]
  PIN aq_q[60]
    DIRECTION INPUT ;
    USE SIGNAL ;
    PORT
      LAYER M3 ;
        RECT  28.8 0 28.818 0.144 ;
    END
  END aq_q[60]
  PIN aq_q[61]
    DIRECTION INPUT ;
    USE SIGNAL ;
    PORT
      LAYER M5 ;
        RECT  28.848 0 28.872 0.192 ;
    END
  END aq_q[61]
  PIN aq_q[62]
    DIRECTION INPUT ;
    USE SIGNAL ;
    PORT
      LAYER M3 ;
        RECT  28.944 0 28.962 0.144 ;
    END
  END aq_q[62]
  PIN aq_q[63]
    DIRECTION INPUT ;
    USE SIGNAL ;
    PORT
      LAYER M5 ;
        RECT  28.992 0 29.016 0.192 ;
    END
  END aq_q[63]
  PIN aq_q[64]
    DIRECTION INPUT ;
    USE SIGNAL ;
    PORT
      LAYER M3 ;
        RECT  29.088 0 29.106 0.144 ;
    END
  END aq_q[64]
  PIN aq_q[65]
    DIRECTION INPUT ;
    USE SIGNAL ;
    PORT
      LAYER M5 ;
        RECT  29.136 0 29.16 0.192 ;
    END
  END aq_q[65]
  PIN aq_q[66]
    DIRECTION INPUT ;
    USE SIGNAL ;
    PORT
      LAYER M3 ;
        RECT  29.232 0 29.25 0.144 ;
    END
  END aq_q[66]
  PIN aq_q[67]
    DIRECTION INPUT ;
    USE SIGNAL ;
    PORT
      LAYER M5 ;
        RECT  29.28 0 29.304 0.192 ;
    END
  END aq_q[67]
  PIN aq_q[68]
    DIRECTION INPUT ;
    USE SIGNAL ;
    PORT
      LAYER M3 ;
        RECT  29.376 0 29.394 0.144 ;
    END
  END aq_q[68]
  PIN aq_q[69]
    DIRECTION INPUT ;
    USE SIGNAL ;
    PORT
      LAYER M5 ;
        RECT  29.424 0 29.448 0.192 ;
    END
  END aq_q[69]
  PIN aq_q[6]
    DIRECTION INPUT ;
    USE SIGNAL ;
    PORT
      LAYER M3 ;
        RECT  24.912 0 24.93 0.144 ;
    END
  END aq_q[6]
  PIN aq_q[70]
    DIRECTION INPUT ;
    USE SIGNAL ;
    PORT
      LAYER M3 ;
        RECT  29.52 0 29.538 0.144 ;
    END
  END aq_q[70]
  PIN aq_q[71]
    DIRECTION INPUT ;
    USE SIGNAL ;
    PORT
      LAYER M5 ;
        RECT  29.568 0 29.592 0.192 ;
    END
  END aq_q[71]
  PIN aq_q[72]
    DIRECTION INPUT ;
    USE SIGNAL ;
    PORT
      LAYER M3 ;
        RECT  29.664 0 29.682 0.144 ;
    END
  END aq_q[72]
  PIN aq_q[73]
    DIRECTION INPUT ;
    USE SIGNAL ;
    PORT
      LAYER M5 ;
        RECT  29.712 0 29.736 0.192 ;
    END
  END aq_q[73]
  PIN aq_q[74]
    DIRECTION INPUT ;
    USE SIGNAL ;
    PORT
      LAYER M3 ;
        RECT  29.808 0 29.826 0.144 ;
    END
  END aq_q[74]
  PIN aq_q[75]
    DIRECTION INPUT ;
    USE SIGNAL ;
    PORT
      LAYER M5 ;
        RECT  29.856 0 29.88 0.192 ;
    END
  END aq_q[75]
  PIN aq_q[76]
    DIRECTION INPUT ;
    USE SIGNAL ;
    PORT
      LAYER M3 ;
        RECT  29.952 0 29.97 0.144 ;
    END
  END aq_q[76]
  PIN aq_q[77]
    DIRECTION INPUT ;
    USE SIGNAL ;
    PORT
      LAYER M5 ;
        RECT  30 0 30.024 0.192 ;
    END
  END aq_q[77]
  PIN aq_q[78]
    DIRECTION INPUT ;
    USE SIGNAL ;
    PORT
      LAYER M3 ;
        RECT  30.096 0 30.114 0.144 ;
    END
  END aq_q[78]
  PIN aq_q[79]
    DIRECTION INPUT ;
    USE SIGNAL ;
    PORT
      LAYER M5 ;
        RECT  30.144 0 30.168 0.192 ;
    END
  END aq_q[79]
  PIN aq_q[7]
    DIRECTION INPUT ;
    USE SIGNAL ;
    PORT
      LAYER M5 ;
        RECT  24.96 0 24.984 0.192 ;
    END
  END aq_q[7]
  PIN aq_q[80]
    DIRECTION INPUT ;
    USE SIGNAL ;
    PORT
      LAYER M3 ;
        RECT  30.24 0 30.258 0.144 ;
    END
  END aq_q[80]
  PIN aq_q[81]
    DIRECTION INPUT ;
    USE SIGNAL ;
    PORT
      LAYER M5 ;
        RECT  30.288 0 30.312 0.192 ;
    END
  END aq_q[81]
  PIN aq_q[82]
    DIRECTION INPUT ;
    USE SIGNAL ;
    PORT
      LAYER M3 ;
        RECT  30.384 0 30.402 0.144 ;
    END
  END aq_q[82]
  PIN aq_q[83]
    DIRECTION INPUT ;
    USE SIGNAL ;
    PORT
      LAYER M5 ;
        RECT  30.432 0 30.456 0.192 ;
    END
  END aq_q[83]
  PIN aq_q[84]
    DIRECTION INPUT ;
    USE SIGNAL ;
    PORT
      LAYER M3 ;
        RECT  30.528 0 30.546 0.144 ;
    END
  END aq_q[84]
  PIN aq_q[85]
    DIRECTION INPUT ;
    USE SIGNAL ;
    PORT
      LAYER M5 ;
        RECT  30.576 0 30.6 0.192 ;
    END
  END aq_q[85]
  PIN aq_q[86]
    DIRECTION INPUT ;
    USE SIGNAL ;
    PORT
      LAYER M3 ;
        RECT  30.672 0 30.69 0.144 ;
    END
  END aq_q[86]
  PIN aq_q[87]
    DIRECTION INPUT ;
    USE SIGNAL ;
    PORT
      LAYER M5 ;
        RECT  30.72 0 30.744 0.192 ;
    END
  END aq_q[87]
  PIN aq_q[88]
    DIRECTION INPUT ;
    USE SIGNAL ;
    PORT
      LAYER M3 ;
        RECT  30.816 0 30.834 0.144 ;
    END
  END aq_q[88]
  PIN aq_q[89]
    DIRECTION INPUT ;
    USE SIGNAL ;
    PORT
      LAYER M5 ;
        RECT  30.864 0 30.888 0.192 ;
    END
  END aq_q[89]
  PIN aq_q[8]
    DIRECTION INPUT ;
    USE SIGNAL ;
    PORT
      LAYER M3 ;
        RECT  25.056 0 25.074 0.144 ;
    END
  END aq_q[8]
  PIN aq_q[90]
    DIRECTION INPUT ;
    USE SIGNAL ;
    PORT
      LAYER M3 ;
        RECT  30.96 0 30.978 0.144 ;
    END
  END aq_q[90]
  PIN aq_q[91]
    DIRECTION INPUT ;
    USE SIGNAL ;
    PORT
      LAYER M5 ;
        RECT  31.008 0 31.032 0.192 ;
    END
  END aq_q[91]
  PIN aq_q[92]
    DIRECTION INPUT ;
    USE SIGNAL ;
    PORT
      LAYER M3 ;
        RECT  31.104 0 31.122 0.144 ;
    END
  END aq_q[92]
  PIN aq_q[93]
    DIRECTION INPUT ;
    USE SIGNAL ;
    PORT
      LAYER M5 ;
        RECT  31.152 0 31.176 0.192 ;
    END
  END aq_q[93]
  PIN aq_q[94]
    DIRECTION INPUT ;
    USE SIGNAL ;
    PORT
      LAYER M3 ;
        RECT  31.248 0 31.266 0.144 ;
    END
  END aq_q[94]
  PIN aq_q[95]
    DIRECTION INPUT ;
    USE SIGNAL ;
    PORT
      LAYER M5 ;
        RECT  31.296 0 31.32 0.192 ;
    END
  END aq_q[95]
  PIN aq_q[96]
    DIRECTION INPUT ;
    USE SIGNAL ;
    PORT
      LAYER M3 ;
        RECT  31.392 0 31.41 0.144 ;
    END
  END aq_q[96]
  PIN aq_q[97]
    DIRECTION INPUT ;
    USE SIGNAL ;
    PORT
      LAYER M5 ;
        RECT  31.44 0 31.464 0.192 ;
    END
  END aq_q[97]
  PIN aq_q[98]
    DIRECTION INPUT ;
    USE SIGNAL ;
    PORT
      LAYER M3 ;
        RECT  31.536 0 31.554 0.144 ;
    END
  END aq_q[98]
  PIN aq_q[99]
    DIRECTION INPUT ;
    USE SIGNAL ;
    PORT
      LAYER M5 ;
        RECT  31.584 0 31.608 0.192 ;
    END
  END aq_q[99]
  PIN aq_q[9]
    DIRECTION INPUT ;
    USE SIGNAL ;
    PORT
      LAYER M5 ;
        RECT  25.104 0 25.128 0.192 ;
    END
  END aq_q[9]
  PIN clk
    DIRECTION INPUT ;
    USE SIGNAL ;
    PORT
      LAYER M4 ;
        RECT  0 52.032 0.192 52.056 ;
    END
    PORT
      LAYER M4 ;
        RECT  0.156 52.032 0.205 52.056 ;
    END
  END clk
  PIN erd[0]
    DIRECTION OUTPUT ;
    USE SIGNAL ;
    PORT
      LAYER M3 ;
        RECT  47.52 86.256 47.538 86.4 ;
    END
  END erd[0]
  PIN erd[1]
    DIRECTION OUTPUT ;
    USE SIGNAL ;
    PORT
      LAYER M3 ;
        RECT  47.664 86.256 47.682 86.4 ;
    END
  END erd[1]
  PIN erd[2]
    DIRECTION OUTPUT ;
    USE SIGNAL ;
    PORT
      LAYER M3 ;
        RECT  47.808 86.256 47.826 86.4 ;
    END
  END erd[2]
  PIN erd[3]
    DIRECTION OUTPUT ;
    USE SIGNAL ;
    PORT
      LAYER M3 ;
        RECT  47.952 86.256 47.97 86.4 ;
    END
  END erd[3]
  PIN erd[4]
    DIRECTION OUTPUT ;
    USE SIGNAL ;
    PORT
      LAYER M3 ;
        RECT  48.096 86.256 48.114 86.4 ;
    END
  END erd[4]
  PIN erd[5]
    DIRECTION OUTPUT ;
    USE SIGNAL ;
    PORT
      LAYER M3 ;
        RECT  48.24 86.256 48.258 86.4 ;
    END
  END erd[5]
  PIN erd[6]
    DIRECTION OUTPUT ;
    USE SIGNAL ;
    PORT
      LAYER M3 ;
        RECT  48.384 86.256 48.402 86.4 ;
    END
  END erd[6]
  PIN erd[7]
    DIRECTION OUTPUT ;
    USE SIGNAL ;
    PORT
      LAYER M3 ;
        RECT  48.528 86.256 48.546 86.4 ;
    END
  END erd[7]
  PIN erd[8]
    DIRECTION OUTPUT ;
    USE SIGNAL ;
    PORT
      LAYER M3 ;
        RECT  48.672 86.256 48.69 86.4 ;
    END
  END erd[8]
  PIN erd[9]
    DIRECTION OUTPUT ;
    USE SIGNAL ;
    PORT
      LAYER M3 ;
        RECT  48.816 86.256 48.834 86.4 ;
    END
  END erd[9]
  PIN fault
    DIRECTION OUTPUT ;
    USE SIGNAL ;
    PORT
      LAYER M4 ;
        RECT  142.368 52.032 142.56 52.056 ;
    END
    PORT
      LAYER M4 ;
        RECT  139.813 52.032 142.38 52.056 ;
    END
  END fault
  PIN i0[0]
    DIRECTION INPUT ;
    USE SIGNAL ;
    PORT
      LAYER M4 ;
        RECT  0 41.616 0.192 41.64 ;
    END
  END i0[0]
  PIN i0[10]
    DIRECTION INPUT ;
    USE SIGNAL ;
    PORT
      LAYER M4 ;
        RECT  0 43.056 0.192 43.08 ;
    END
  END i0[10]
  PIN i0[11]
    DIRECTION INPUT ;
    USE SIGNAL ;
    PORT
      LAYER M4 ;
        RECT  0 43.2 0.192 43.224 ;
    END
  END i0[11]
  PIN i0[12]
    DIRECTION INPUT ;
    USE SIGNAL ;
    PORT
      LAYER M4 ;
        RECT  0 43.344 0.192 43.368 ;
    END
  END i0[12]
  PIN i0[13]
    DIRECTION INPUT ;
    USE SIGNAL ;
    PORT
      LAYER M4 ;
        RECT  0 43.488 0.192 43.512 ;
    END
  END i0[13]
  PIN i0[14]
    DIRECTION INPUT ;
    USE SIGNAL ;
    PORT
      LAYER M4 ;
        RECT  0 43.632 0.192 43.656 ;
    END
  END i0[14]
  PIN i0[15]
    DIRECTION INPUT ;
    USE SIGNAL ;
    PORT
      LAYER M4 ;
        RECT  0 43.776 0.192 43.8 ;
    END
  END i0[15]
  PIN i0[1]
    DIRECTION INPUT ;
    USE SIGNAL ;
    PORT
      LAYER M4 ;
        RECT  0 41.76 0.192 41.784 ;
    END
  END i0[1]
  PIN i0[2]
    DIRECTION INPUT ;
    USE SIGNAL ;
    PORT
      LAYER M4 ;
        RECT  0 41.904 0.192 41.928 ;
    END
  END i0[2]
  PIN i0[3]
    DIRECTION INPUT ;
    USE SIGNAL ;
    PORT
      LAYER M4 ;
        RECT  0 42.048 0.192 42.072 ;
    END
  END i0[3]
  PIN i0[4]
    DIRECTION INPUT ;
    USE SIGNAL ;
    PORT
      LAYER M4 ;
        RECT  0 42.192 0.192 42.216 ;
    END
  END i0[4]
  PIN i0[5]
    DIRECTION INPUT ;
    USE SIGNAL ;
    PORT
      LAYER M4 ;
        RECT  0 42.336 0.192 42.36 ;
    END
  END i0[5]
  PIN i0[6]
    DIRECTION INPUT ;
    USE SIGNAL ;
    PORT
      LAYER M4 ;
        RECT  0 42.48 0.192 42.504 ;
    END
  END i0[6]
  PIN i0[7]
    DIRECTION INPUT ;
    USE SIGNAL ;
    PORT
      LAYER M4 ;
        RECT  0 42.624 0.192 42.648 ;
    END
  END i0[7]
  PIN i0[8]
    DIRECTION INPUT ;
    USE SIGNAL ;
    PORT
      LAYER M4 ;
        RECT  0 42.768 0.192 42.792 ;
    END
  END i0[8]
  PIN i0[9]
    DIRECTION INPUT ;
    USE SIGNAL ;
    PORT
      LAYER M4 ;
        RECT  0 42.912 0.192 42.936 ;
    END
  END i0[9]
  PIN i1[0]
    DIRECTION INPUT ;
    USE SIGNAL ;
    PORT
      LAYER M4 ;
        RECT  0 43.92 0.192 43.944 ;
    END
  END i1[0]
  PIN i1[10]
    DIRECTION INPUT ;
    USE SIGNAL ;
    PORT
      LAYER M4 ;
        RECT  0 45.36 0.192 45.384 ;
    END
  END i1[10]
  PIN i1[11]
    DIRECTION INPUT ;
    USE SIGNAL ;
    PORT
      LAYER M4 ;
        RECT  0 45.504 0.192 45.528 ;
    END
  END i1[11]
  PIN i1[12]
    DIRECTION INPUT ;
    USE SIGNAL ;
    PORT
      LAYER M4 ;
        RECT  0 45.648 0.192 45.672 ;
    END
  END i1[12]
  PIN i1[13]
    DIRECTION INPUT ;
    USE SIGNAL ;
    PORT
      LAYER M4 ;
        RECT  0 45.792 0.192 45.816 ;
    END
  END i1[13]
  PIN i1[14]
    DIRECTION INPUT ;
    USE SIGNAL ;
    PORT
      LAYER M4 ;
        RECT  0 45.936 0.192 45.96 ;
    END
  END i1[14]
  PIN i1[15]
    DIRECTION INPUT ;
    USE SIGNAL ;
    PORT
      LAYER M4 ;
        RECT  0 46.08 0.192 46.104 ;
    END
  END i1[15]
  PIN i1[1]
    DIRECTION INPUT ;
    USE SIGNAL ;
    PORT
      LAYER M4 ;
        RECT  0 44.064 0.192 44.088 ;
    END
  END i1[1]
  PIN i1[2]
    DIRECTION INPUT ;
    USE SIGNAL ;
    PORT
      LAYER M4 ;
        RECT  0 44.208 0.192 44.232 ;
    END
  END i1[2]
  PIN i1[3]
    DIRECTION INPUT ;
    USE SIGNAL ;
    PORT
      LAYER M4 ;
        RECT  0 44.352 0.192 44.376 ;
    END
  END i1[3]
  PIN i1[4]
    DIRECTION INPUT ;
    USE SIGNAL ;
    PORT
      LAYER M4 ;
        RECT  0 44.496 0.192 44.52 ;
    END
  END i1[4]
  PIN i1[5]
    DIRECTION INPUT ;
    USE SIGNAL ;
    PORT
      LAYER M4 ;
        RECT  0 44.64 0.192 44.664 ;
    END
  END i1[5]
  PIN i1[6]
    DIRECTION INPUT ;
    USE SIGNAL ;
    PORT
      LAYER M4 ;
        RECT  0 44.784 0.192 44.808 ;
    END
  END i1[6]
  PIN i1[7]
    DIRECTION INPUT ;
    USE SIGNAL ;
    PORT
      LAYER M4 ;
        RECT  0 44.928 0.192 44.952 ;
    END
  END i1[7]
  PIN i1[8]
    DIRECTION INPUT ;
    USE SIGNAL ;
    PORT
      LAYER M4 ;
        RECT  0 45.072 0.192 45.096 ;
    END
  END i1[8]
  PIN i1[9]
    DIRECTION INPUT ;
    USE SIGNAL ;
    PORT
      LAYER M4 ;
        RECT  0 45.216 0.192 45.24 ;
    END
  END i1[9]
  PIN ph0[0]
    DIRECTION INPUT ;
    USE SIGNAL ;
    PORT
      LAYER M4 ;
        RECT  0 38.448 0.192 38.472 ;
    END
  END ph0[0]
  PIN ph0[1]
    DIRECTION INPUT ;
    USE SIGNAL ;
    PORT
      LAYER M4 ;
        RECT  0 38.304 0.192 38.328 ;
    END
  END ph0[1]
  PIN ph0[2]
    DIRECTION INPUT ;
    USE SIGNAL ;
    PORT
      LAYER M4 ;
        RECT  0 38.16 0.192 38.184 ;
    END
  END ph0[2]
  PIN ph0[3]
    DIRECTION INPUT ;
    USE SIGNAL ;
    PORT
      LAYER M4 ;
        RECT  0 38.016 0.192 38.04 ;
    END
  END ph0[3]
  PIN ph0[4]
    DIRECTION INPUT ;
    USE SIGNAL ;
    PORT
      LAYER M4 ;
        RECT  0 37.872 0.192 37.896 ;
    END
  END ph0[4]
  PIN ph0[5]
    DIRECTION INPUT ;
    USE SIGNAL ;
    PORT
      LAYER M4 ;
        RECT  0 37.728 0.192 37.752 ;
    END
  END ph0[5]
  PIN ph1[0]
    DIRECTION INPUT ;
    USE SIGNAL ;
    PORT
      LAYER M4 ;
        RECT  0 37.584 0.192 37.608 ;
    END
  END ph1[0]
  PIN ph1[1]
    DIRECTION INPUT ;
    USE SIGNAL ;
    PORT
      LAYER M4 ;
        RECT  0 37.44 0.192 37.464 ;
    END
  END ph1[1]
  PIN ph1[2]
    DIRECTION INPUT ;
    USE SIGNAL ;
    PORT
      LAYER M4 ;
        RECT  0 37.296 0.192 37.32 ;
    END
  END ph1[2]
  PIN ph1[3]
    DIRECTION INPUT ;
    USE SIGNAL ;
    PORT
      LAYER M4 ;
        RECT  0 37.152 0.192 37.176 ;
    END
  END ph1[3]
  PIN ph1[4]
    DIRECTION INPUT ;
    USE SIGNAL ;
    PORT
      LAYER M4 ;
        RECT  0 37.008 0.192 37.032 ;
    END
  END ph1[4]
  PIN ph1[5]
    DIRECTION INPUT ;
    USE SIGNAL ;
    PORT
      LAYER M4 ;
        RECT  0 36.864 0.192 36.888 ;
    END
  END ph1[5]
  PIN pl0[0]
    DIRECTION INPUT ;
    USE SIGNAL ;
    PORT
      LAYER M4 ;
        RECT  0 36.72 0.192 36.744 ;
    END
  END pl0[0]
  PIN pl0[10]
    DIRECTION INPUT ;
    USE SIGNAL ;
    PORT
      LAYER M4 ;
        RECT  0 35.28 0.192 35.304 ;
    END
  END pl0[10]
  PIN pl0[11]
    DIRECTION INPUT ;
    USE SIGNAL ;
    PORT
      LAYER M4 ;
        RECT  0 35.136 0.192 35.16 ;
    END
  END pl0[11]
  PIN pl0[12]
    DIRECTION INPUT ;
    USE SIGNAL ;
    PORT
      LAYER M4 ;
        RECT  0 34.992 0.192 35.016 ;
    END
  END pl0[12]
  PIN pl0[13]
    DIRECTION INPUT ;
    USE SIGNAL ;
    PORT
      LAYER M4 ;
        RECT  0 34.848 0.192 34.872 ;
    END
  END pl0[13]
  PIN pl0[14]
    DIRECTION INPUT ;
    USE SIGNAL ;
    PORT
      LAYER M4 ;
        RECT  0 34.704 0.192 34.728 ;
    END
  END pl0[14]
  PIN pl0[15]
    DIRECTION INPUT ;
    USE SIGNAL ;
    PORT
      LAYER M4 ;
        RECT  0 34.56 0.192 34.584 ;
    END
  END pl0[15]
  PIN pl0[1]
    DIRECTION INPUT ;
    USE SIGNAL ;
    PORT
      LAYER M4 ;
        RECT  0 36.576 0.192 36.6 ;
    END
  END pl0[1]
  PIN pl0[2]
    DIRECTION INPUT ;
    USE SIGNAL ;
    PORT
      LAYER M4 ;
        RECT  0 36.432 0.192 36.456 ;
    END
  END pl0[2]
  PIN pl0[3]
    DIRECTION INPUT ;
    USE SIGNAL ;
    PORT
      LAYER M4 ;
        RECT  0 36.288 0.192 36.312 ;
    END
  END pl0[3]
  PIN pl0[4]
    DIRECTION INPUT ;
    USE SIGNAL ;
    PORT
      LAYER M4 ;
        RECT  0 36.144 0.192 36.168 ;
    END
  END pl0[4]
  PIN pl0[5]
    DIRECTION INPUT ;
    USE SIGNAL ;
    PORT
      LAYER M4 ;
        RECT  0 36 0.192 36.024 ;
    END
  END pl0[5]
  PIN pl0[6]
    DIRECTION INPUT ;
    USE SIGNAL ;
    PORT
      LAYER M4 ;
        RECT  0 35.856 0.192 35.88 ;
    END
  END pl0[6]
  PIN pl0[7]
    DIRECTION INPUT ;
    USE SIGNAL ;
    PORT
      LAYER M4 ;
        RECT  0 35.712 0.192 35.736 ;
    END
  END pl0[7]
  PIN pl0[8]
    DIRECTION INPUT ;
    USE SIGNAL ;
    PORT
      LAYER M4 ;
        RECT  0 35.568 0.192 35.592 ;
    END
  END pl0[8]
  PIN pl0[9]
    DIRECTION INPUT ;
    USE SIGNAL ;
    PORT
      LAYER M4 ;
        RECT  0 35.424 0.192 35.448 ;
    END
  END pl0[9]
  PIN pl1[0]
    DIRECTION INPUT ;
    USE SIGNAL ;
    PORT
      LAYER M4 ;
        RECT  0 34.416 0.192 34.44 ;
    END
  END pl1[0]
  PIN pl1[10]
    DIRECTION INPUT ;
    USE SIGNAL ;
    PORT
      LAYER M4 ;
        RECT  0 32.976 0.192 33 ;
    END
  END pl1[10]
  PIN pl1[11]
    DIRECTION INPUT ;
    USE SIGNAL ;
    PORT
      LAYER M4 ;
        RECT  0 32.832 0.192 32.856 ;
    END
  END pl1[11]
  PIN pl1[12]
    DIRECTION INPUT ;
    USE SIGNAL ;
    PORT
      LAYER M4 ;
        RECT  0 32.688 0.192 32.712 ;
    END
  END pl1[12]
  PIN pl1[13]
    DIRECTION INPUT ;
    USE SIGNAL ;
    PORT
      LAYER M4 ;
        RECT  0 32.544 0.192 32.568 ;
    END
  END pl1[13]
  PIN pl1[14]
    DIRECTION INPUT ;
    USE SIGNAL ;
    PORT
      LAYER M4 ;
        RECT  0 32.4 0.192 32.424 ;
    END
  END pl1[14]
  PIN pl1[15]
    DIRECTION INPUT ;
    USE SIGNAL ;
    PORT
      LAYER M4 ;
        RECT  0 32.256 0.192 32.28 ;
    END
  END pl1[15]
  PIN pl1[1]
    DIRECTION INPUT ;
    USE SIGNAL ;
    PORT
      LAYER M4 ;
        RECT  0 34.272 0.192 34.296 ;
    END
  END pl1[1]
  PIN pl1[2]
    DIRECTION INPUT ;
    USE SIGNAL ;
    PORT
      LAYER M4 ;
        RECT  0 34.128 0.192 34.152 ;
    END
  END pl1[2]
  PIN pl1[3]
    DIRECTION INPUT ;
    USE SIGNAL ;
    PORT
      LAYER M4 ;
        RECT  0 33.984 0.192 34.008 ;
    END
  END pl1[3]
  PIN pl1[4]
    DIRECTION INPUT ;
    USE SIGNAL ;
    PORT
      LAYER M4 ;
        RECT  0 33.84 0.192 33.864 ;
    END
  END pl1[4]
  PIN pl1[5]
    DIRECTION INPUT ;
    USE SIGNAL ;
    PORT
      LAYER M4 ;
        RECT  0 33.696 0.192 33.72 ;
    END
  END pl1[5]
  PIN pl1[6]
    DIRECTION INPUT ;
    USE SIGNAL ;
    PORT
      LAYER M4 ;
        RECT  0 33.552 0.192 33.576 ;
    END
  END pl1[6]
  PIN pl1[7]
    DIRECTION INPUT ;
    USE SIGNAL ;
    PORT
      LAYER M4 ;
        RECT  0 33.408 0.192 33.432 ;
    END
  END pl1[7]
  PIN pl1[8]
    DIRECTION INPUT ;
    USE SIGNAL ;
    PORT
      LAYER M4 ;
        RECT  0 33.264 0.192 33.288 ;
    END
  END pl1[8]
  PIN pl1[9]
    DIRECTION INPUT ;
    USE SIGNAL ;
    PORT
      LAYER M4 ;
        RECT  0 33.12 0.192 33.144 ;
    END
  END pl1[9]
  PIN rd[0]
    DIRECTION OUTPUT ;
    USE SIGNAL ;
    PORT
      LAYER M3 ;
        RECT  24.48 86.256 24.498 86.4 ;
    END
  END rd[0]
  PIN rd[100]
    DIRECTION OUTPUT ;
    USE SIGNAL ;
    PORT
      LAYER M3 ;
        RECT  31.68 86.256 31.698 86.4 ;
    END
  END rd[100]
  PIN rd[101]
    DIRECTION OUTPUT ;
    USE SIGNAL ;
    PORT
      LAYER M5 ;
        RECT  31.728 86.208 31.752 86.4 ;
    END
  END rd[101]
  PIN rd[102]
    DIRECTION OUTPUT ;
    USE SIGNAL ;
    PORT
      LAYER M3 ;
        RECT  31.824 86.256 31.842 86.4 ;
    END
  END rd[102]
  PIN rd[103]
    DIRECTION OUTPUT ;
    USE SIGNAL ;
    PORT
      LAYER M5 ;
        RECT  31.872 86.208 31.896 86.4 ;
    END
  END rd[103]
  PIN rd[104]
    DIRECTION OUTPUT ;
    USE SIGNAL ;
    PORT
      LAYER M3 ;
        RECT  31.968 86.256 31.986 86.4 ;
    END
  END rd[104]
  PIN rd[105]
    DIRECTION OUTPUT ;
    USE SIGNAL ;
    PORT
      LAYER M5 ;
        RECT  32.016 86.208 32.04 86.4 ;
    END
  END rd[105]
  PIN rd[106]
    DIRECTION OUTPUT ;
    USE SIGNAL ;
    PORT
      LAYER M3 ;
        RECT  32.112 86.256 32.13 86.4 ;
    END
  END rd[106]
  PIN rd[107]
    DIRECTION OUTPUT ;
    USE SIGNAL ;
    PORT
      LAYER M5 ;
        RECT  32.16 86.208 32.184 86.4 ;
    END
  END rd[107]
  PIN rd[108]
    DIRECTION OUTPUT ;
    USE SIGNAL ;
    PORT
      LAYER M3 ;
        RECT  32.256 86.256 32.274 86.4 ;
    END
  END rd[108]
  PIN rd[109]
    DIRECTION OUTPUT ;
    USE SIGNAL ;
    PORT
      LAYER M5 ;
        RECT  32.304 86.208 32.328 86.4 ;
    END
  END rd[109]
  PIN rd[10]
    DIRECTION OUTPUT ;
    USE SIGNAL ;
    PORT
      LAYER M3 ;
        RECT  25.2 86.256 25.218 86.4 ;
    END
  END rd[10]
  PIN rd[110]
    DIRECTION OUTPUT ;
    USE SIGNAL ;
    PORT
      LAYER M3 ;
        RECT  32.4 86.256 32.418 86.4 ;
    END
  END rd[110]
  PIN rd[111]
    DIRECTION OUTPUT ;
    USE SIGNAL ;
    PORT
      LAYER M5 ;
        RECT  32.448 86.208 32.472 86.4 ;
    END
  END rd[111]
  PIN rd[112]
    DIRECTION OUTPUT ;
    USE SIGNAL ;
    PORT
      LAYER M3 ;
        RECT  32.544 86.256 32.562 86.4 ;
    END
  END rd[112]
  PIN rd[113]
    DIRECTION OUTPUT ;
    USE SIGNAL ;
    PORT
      LAYER M5 ;
        RECT  32.592 86.208 32.616 86.4 ;
    END
  END rd[113]
  PIN rd[114]
    DIRECTION OUTPUT ;
    USE SIGNAL ;
    PORT
      LAYER M3 ;
        RECT  32.688 86.256 32.706 86.4 ;
    END
    PORT
      LAYER M3 ;
        RECT  32.652 86.268 32.778 86.333 ;
    END
  END rd[114]
  PIN rd[115]
    DIRECTION OUTPUT ;
    USE SIGNAL ;
    PORT
      LAYER M5 ;
        RECT  32.736 86.208 32.76 86.4 ;
    END
  END rd[115]
  PIN rd[116]
    DIRECTION OUTPUT ;
    USE SIGNAL ;
    PORT
      LAYER M3 ;
        RECT  32.832 86.256 32.85 86.4 ;
    END
  END rd[116]
  PIN rd[117]
    DIRECTION OUTPUT ;
    USE SIGNAL ;
    PORT
      LAYER M5 ;
        RECT  32.88 86.208 32.904 86.4 ;
    END
  END rd[117]
  PIN rd[118]
    DIRECTION OUTPUT ;
    USE SIGNAL ;
    PORT
      LAYER M3 ;
        RECT  32.976 86.256 32.994 86.4 ;
    END
  END rd[118]
  PIN rd[119]
    DIRECTION OUTPUT ;
    USE SIGNAL ;
    PORT
      LAYER M5 ;
        RECT  33.024 86.208 33.048 86.4 ;
    END
  END rd[119]
  PIN rd[11]
    DIRECTION OUTPUT ;
    USE SIGNAL ;
    PORT
      LAYER M5 ;
        RECT  25.248 86.208 25.272 86.4 ;
    END
  END rd[11]
  PIN rd[120]
    DIRECTION OUTPUT ;
    USE SIGNAL ;
    PORT
      LAYER M3 ;
        RECT  33.12 86.256 33.138 86.4 ;
    END
  END rd[120]
  PIN rd[121]
    DIRECTION OUTPUT ;
    USE SIGNAL ;
    PORT
      LAYER M5 ;
        RECT  33.168 86.208 33.192 86.4 ;
    END
  END rd[121]
  PIN rd[122]
    DIRECTION OUTPUT ;
    USE SIGNAL ;
    PORT
      LAYER M3 ;
        RECT  33.264 86.256 33.282 86.4 ;
    END
  END rd[122]
  PIN rd[123]
    DIRECTION OUTPUT ;
    USE SIGNAL ;
    PORT
      LAYER M5 ;
        RECT  33.312 86.208 33.336 86.4 ;
    END
  END rd[123]
  PIN rd[124]
    DIRECTION OUTPUT ;
    USE SIGNAL ;
    PORT
      LAYER M3 ;
        RECT  33.408 86.256 33.426 86.4 ;
    END
  END rd[124]
  PIN rd[125]
    DIRECTION OUTPUT ;
    USE SIGNAL ;
    PORT
      LAYER M5 ;
        RECT  33.456 86.208 33.48 86.4 ;
    END
  END rd[125]
  PIN rd[126]
    DIRECTION OUTPUT ;
    USE SIGNAL ;
    PORT
      LAYER M3 ;
        RECT  33.552 86.256 33.57 86.4 ;
    END
  END rd[126]
  PIN rd[127]
    DIRECTION OUTPUT ;
    USE SIGNAL ;
    PORT
      LAYER M5 ;
        RECT  33.6 86.208 33.624 86.4 ;
    END
  END rd[127]
  PIN rd[128]
    DIRECTION OUTPUT ;
    USE SIGNAL ;
    PORT
      LAYER M3 ;
        RECT  33.696 86.256 33.714 86.4 ;
    END
  END rd[128]
  PIN rd[129]
    DIRECTION OUTPUT ;
    USE SIGNAL ;
    PORT
      LAYER M5 ;
        RECT  33.744 86.208 33.768 86.4 ;
    END
  END rd[129]
  PIN rd[12]
    DIRECTION OUTPUT ;
    USE SIGNAL ;
    PORT
      LAYER M3 ;
        RECT  25.344 86.256 25.362 86.4 ;
    END
  END rd[12]
  PIN rd[130]
    DIRECTION OUTPUT ;
    USE SIGNAL ;
    PORT
      LAYER M3 ;
        RECT  33.84 86.256 33.858 86.4 ;
    END
  END rd[130]
  PIN rd[131]
    DIRECTION OUTPUT ;
    USE SIGNAL ;
    PORT
      LAYER M5 ;
        RECT  33.888 86.208 33.912 86.4 ;
    END
  END rd[131]
  PIN rd[132]
    DIRECTION OUTPUT ;
    USE SIGNAL ;
    PORT
      LAYER M3 ;
        RECT  33.984 86.256 34.002 86.4 ;
    END
    PORT
      LAYER M3 ;
        RECT  33.948 86.268 34.074 86.333 ;
    END
  END rd[132]
  PIN rd[133]
    DIRECTION OUTPUT ;
    USE SIGNAL ;
    PORT
      LAYER M5 ;
        RECT  34.032 86.208 34.056 86.4 ;
    END
  END rd[133]
  PIN rd[134]
    DIRECTION OUTPUT ;
    USE SIGNAL ;
    PORT
      LAYER M3 ;
        RECT  34.128 86.256 34.146 86.4 ;
    END
  END rd[134]
  PIN rd[135]
    DIRECTION OUTPUT ;
    USE SIGNAL ;
    PORT
      LAYER M5 ;
        RECT  34.176 86.208 34.2 86.4 ;
    END
  END rd[135]
  PIN rd[136]
    DIRECTION OUTPUT ;
    USE SIGNAL ;
    PORT
      LAYER M3 ;
        RECT  34.272 86.256 34.29 86.4 ;
    END
  END rd[136]
  PIN rd[137]
    DIRECTION OUTPUT ;
    USE SIGNAL ;
    PORT
      LAYER M5 ;
        RECT  34.32 86.208 34.344 86.4 ;
    END
  END rd[137]
  PIN rd[138]
    DIRECTION OUTPUT ;
    USE SIGNAL ;
    PORT
      LAYER M3 ;
        RECT  34.416 86.256 34.434 86.4 ;
    END
  END rd[138]
  PIN rd[139]
    DIRECTION OUTPUT ;
    USE SIGNAL ;
    PORT
      LAYER M5 ;
        RECT  34.464 86.208 34.488 86.4 ;
    END
  END rd[139]
  PIN rd[13]
    DIRECTION OUTPUT ;
    USE SIGNAL ;
    PORT
      LAYER M5 ;
        RECT  25.392 86.208 25.416 86.4 ;
    END
  END rd[13]
  PIN rd[140]
    DIRECTION OUTPUT ;
    USE SIGNAL ;
    PORT
      LAYER M3 ;
        RECT  34.56 86.256 34.578 86.4 ;
    END
  END rd[140]
  PIN rd[141]
    DIRECTION OUTPUT ;
    USE SIGNAL ;
    PORT
      LAYER M5 ;
        RECT  34.608 86.208 34.632 86.4 ;
    END
  END rd[141]
  PIN rd[142]
    DIRECTION OUTPUT ;
    USE SIGNAL ;
    PORT
      LAYER M3 ;
        RECT  34.704 86.256 34.722 86.4 ;
    END
  END rd[142]
  PIN rd[143]
    DIRECTION OUTPUT ;
    USE SIGNAL ;
    PORT
      LAYER M5 ;
        RECT  34.752 86.208 34.776 86.4 ;
    END
  END rd[143]
  PIN rd[144]
    DIRECTION OUTPUT ;
    USE SIGNAL ;
    PORT
      LAYER M3 ;
        RECT  34.848 86.256 34.866 86.4 ;
    END
  END rd[144]
  PIN rd[145]
    DIRECTION OUTPUT ;
    USE SIGNAL ;
    PORT
      LAYER M5 ;
        RECT  34.896 86.208 34.92 86.4 ;
    END
  END rd[145]
  PIN rd[146]
    DIRECTION OUTPUT ;
    USE SIGNAL ;
    PORT
      LAYER M3 ;
        RECT  34.992 86.256 35.01 86.4 ;
    END
  END rd[146]
  PIN rd[147]
    DIRECTION OUTPUT ;
    USE SIGNAL ;
    PORT
      LAYER M5 ;
        RECT  35.04 86.208 35.064 86.4 ;
    END
  END rd[147]
  PIN rd[148]
    DIRECTION OUTPUT ;
    USE SIGNAL ;
    PORT
      LAYER M3 ;
        RECT  35.136 86.256 35.154 86.4 ;
    END
  END rd[148]
  PIN rd[149]
    DIRECTION OUTPUT ;
    USE SIGNAL ;
    PORT
      LAYER M5 ;
        RECT  35.184 86.208 35.208 86.4 ;
    END
  END rd[149]
  PIN rd[14]
    DIRECTION OUTPUT ;
    USE SIGNAL ;
    PORT
      LAYER M3 ;
        RECT  25.488 86.256 25.506 86.4 ;
    END
  END rd[14]
  PIN rd[150]
    DIRECTION OUTPUT ;
    USE SIGNAL ;
    PORT
      LAYER M3 ;
        RECT  35.28 86.256 35.298 86.4 ;
    END
  END rd[150]
  PIN rd[151]
    DIRECTION OUTPUT ;
    USE SIGNAL ;
    PORT
      LAYER M5 ;
        RECT  35.328 86.208 35.352 86.4 ;
    END
  END rd[151]
  PIN rd[152]
    DIRECTION OUTPUT ;
    USE SIGNAL ;
    PORT
      LAYER M3 ;
        RECT  35.424 86.256 35.442 86.4 ;
    END
  END rd[152]
  PIN rd[153]
    DIRECTION OUTPUT ;
    USE SIGNAL ;
    PORT
      LAYER M5 ;
        RECT  35.472 86.208 35.496 86.4 ;
    END
  END rd[153]
  PIN rd[154]
    DIRECTION OUTPUT ;
    USE SIGNAL ;
    PORT
      LAYER M3 ;
        RECT  35.568 86.256 35.586 86.4 ;
    END
  END rd[154]
  PIN rd[155]
    DIRECTION OUTPUT ;
    USE SIGNAL ;
    PORT
      LAYER M5 ;
        RECT  35.616 86.208 35.64 86.4 ;
    END
  END rd[155]
  PIN rd[156]
    DIRECTION OUTPUT ;
    USE SIGNAL ;
    PORT
      LAYER M3 ;
        RECT  35.712 86.256 35.73 86.4 ;
    END
  END rd[156]
  PIN rd[157]
    DIRECTION OUTPUT ;
    USE SIGNAL ;
    PORT
      LAYER M5 ;
        RECT  35.76 86.208 35.784 86.4 ;
    END
  END rd[157]
  PIN rd[158]
    DIRECTION OUTPUT ;
    USE SIGNAL ;
    PORT
      LAYER M3 ;
        RECT  35.856 86.256 35.874 86.4 ;
    END
  END rd[158]
  PIN rd[159]
    DIRECTION OUTPUT ;
    USE SIGNAL ;
    PORT
      LAYER M5 ;
        RECT  35.904 86.208 35.928 86.4 ;
    END
  END rd[159]
  PIN rd[15]
    DIRECTION OUTPUT ;
    USE SIGNAL ;
    PORT
      LAYER M5 ;
        RECT  25.536 86.208 25.56 86.4 ;
    END
  END rd[15]
  PIN rd[160]
    DIRECTION OUTPUT ;
    USE SIGNAL ;
    PORT
      LAYER M3 ;
        RECT  36 86.256 36.018 86.4 ;
    END
  END rd[160]
  PIN rd[161]
    DIRECTION OUTPUT ;
    USE SIGNAL ;
    PORT
      LAYER M5 ;
        RECT  36.048 86.208 36.072 86.4 ;
    END
  END rd[161]
  PIN rd[162]
    DIRECTION OUTPUT ;
    USE SIGNAL ;
    PORT
      LAYER M3 ;
        RECT  36.144 86.256 36.162 86.4 ;
    END
  END rd[162]
  PIN rd[163]
    DIRECTION OUTPUT ;
    USE SIGNAL ;
    PORT
      LAYER M5 ;
        RECT  36.192 86.208 36.216 86.4 ;
    END
  END rd[163]
  PIN rd[164]
    DIRECTION OUTPUT ;
    USE SIGNAL ;
    PORT
      LAYER M3 ;
        RECT  36.288 86.256 36.306 86.4 ;
    END
  END rd[164]
  PIN rd[165]
    DIRECTION OUTPUT ;
    USE SIGNAL ;
    PORT
      LAYER M5 ;
        RECT  36.336 86.208 36.36 86.4 ;
    END
  END rd[165]
  PIN rd[166]
    DIRECTION OUTPUT ;
    USE SIGNAL ;
    PORT
      LAYER M3 ;
        RECT  36.432 86.256 36.45 86.4 ;
    END
  END rd[166]
  PIN rd[167]
    DIRECTION OUTPUT ;
    USE SIGNAL ;
    PORT
      LAYER M5 ;
        RECT  36.48 86.208 36.504 86.4 ;
    END
  END rd[167]
  PIN rd[168]
    DIRECTION OUTPUT ;
    USE SIGNAL ;
    PORT
      LAYER M3 ;
        RECT  36.576 86.256 36.594 86.4 ;
    END
  END rd[168]
  PIN rd[169]
    DIRECTION OUTPUT ;
    USE SIGNAL ;
    PORT
      LAYER M5 ;
        RECT  36.624 86.208 36.648 86.4 ;
    END
  END rd[169]
  PIN rd[16]
    DIRECTION OUTPUT ;
    USE SIGNAL ;
    PORT
      LAYER M3 ;
        RECT  25.632 86.256 25.65 86.4 ;
    END
  END rd[16]
  PIN rd[170]
    DIRECTION OUTPUT ;
    USE SIGNAL ;
    PORT
      LAYER M3 ;
        RECT  36.72 86.256 36.738 86.4 ;
    END
  END rd[170]
  PIN rd[171]
    DIRECTION OUTPUT ;
    USE SIGNAL ;
    PORT
      LAYER M5 ;
        RECT  36.768 86.208 36.792 86.4 ;
    END
  END rd[171]
  PIN rd[172]
    DIRECTION OUTPUT ;
    USE SIGNAL ;
    PORT
      LAYER M3 ;
        RECT  36.864 86.256 36.882 86.4 ;
    END
  END rd[172]
  PIN rd[173]
    DIRECTION OUTPUT ;
    USE SIGNAL ;
    PORT
      LAYER M5 ;
        RECT  36.912 86.208 36.936 86.4 ;
    END
  END rd[173]
  PIN rd[174]
    DIRECTION OUTPUT ;
    USE SIGNAL ;
    PORT
      LAYER M3 ;
        RECT  37.008 86.256 37.026 86.4 ;
    END
  END rd[174]
  PIN rd[175]
    DIRECTION OUTPUT ;
    USE SIGNAL ;
    PORT
      LAYER M5 ;
        RECT  37.056 86.208 37.08 86.4 ;
    END
  END rd[175]
  PIN rd[176]
    DIRECTION OUTPUT ;
    USE SIGNAL ;
    PORT
      LAYER M3 ;
        RECT  37.152 86.256 37.17 86.4 ;
    END
  END rd[176]
  PIN rd[177]
    DIRECTION OUTPUT ;
    USE SIGNAL ;
    PORT
      LAYER M5 ;
        RECT  37.2 86.208 37.224 86.4 ;
    END
  END rd[177]
  PIN rd[178]
    DIRECTION OUTPUT ;
    USE SIGNAL ;
    PORT
      LAYER M3 ;
        RECT  37.296 86.256 37.314 86.4 ;
    END
  END rd[178]
  PIN rd[179]
    DIRECTION OUTPUT ;
    USE SIGNAL ;
    PORT
      LAYER M5 ;
        RECT  37.344 86.208 37.368 86.4 ;
    END
  END rd[179]
  PIN rd[17]
    DIRECTION OUTPUT ;
    USE SIGNAL ;
    PORT
      LAYER M5 ;
        RECT  25.68 86.208 25.704 86.4 ;
    END
  END rd[17]
  PIN rd[180]
    DIRECTION OUTPUT ;
    USE SIGNAL ;
    PORT
      LAYER M3 ;
        RECT  37.44 86.256 37.458 86.4 ;
    END
  END rd[180]
  PIN rd[181]
    DIRECTION OUTPUT ;
    USE SIGNAL ;
    PORT
      LAYER M5 ;
        RECT  37.488 86.208 37.512 86.4 ;
    END
  END rd[181]
  PIN rd[182]
    DIRECTION OUTPUT ;
    USE SIGNAL ;
    PORT
      LAYER M3 ;
        RECT  37.584 86.256 37.602 86.4 ;
    END
  END rd[182]
  PIN rd[183]
    DIRECTION OUTPUT ;
    USE SIGNAL ;
    PORT
      LAYER M5 ;
        RECT  37.632 86.208 37.656 86.4 ;
    END
  END rd[183]
  PIN rd[184]
    DIRECTION OUTPUT ;
    USE SIGNAL ;
    PORT
      LAYER M3 ;
        RECT  37.728 86.256 37.746 86.4 ;
    END
  END rd[184]
  PIN rd[185]
    DIRECTION OUTPUT ;
    USE SIGNAL ;
    PORT
      LAYER M5 ;
        RECT  37.776 86.208 37.8 86.4 ;
    END
  END rd[185]
  PIN rd[186]
    DIRECTION OUTPUT ;
    USE SIGNAL ;
    PORT
      LAYER M3 ;
        RECT  37.872 86.256 37.89 86.4 ;
    END
  END rd[186]
  PIN rd[187]
    DIRECTION OUTPUT ;
    USE SIGNAL ;
    PORT
      LAYER M5 ;
        RECT  37.92 86.208 37.944 86.4 ;
    END
  END rd[187]
  PIN rd[188]
    DIRECTION OUTPUT ;
    USE SIGNAL ;
    PORT
      LAYER M3 ;
        RECT  38.016 86.256 38.034 86.4 ;
    END
  END rd[188]
  PIN rd[189]
    DIRECTION OUTPUT ;
    USE SIGNAL ;
    PORT
      LAYER M5 ;
        RECT  38.064 86.208 38.088 86.4 ;
    END
  END rd[189]
  PIN rd[18]
    DIRECTION OUTPUT ;
    USE SIGNAL ;
    PORT
      LAYER M3 ;
        RECT  25.776 86.256 25.794 86.4 ;
    END
  END rd[18]
  PIN rd[190]
    DIRECTION OUTPUT ;
    USE SIGNAL ;
    PORT
      LAYER M3 ;
        RECT  38.16 86.256 38.178 86.4 ;
    END
  END rd[190]
  PIN rd[191]
    DIRECTION OUTPUT ;
    USE SIGNAL ;
    PORT
      LAYER M5 ;
        RECT  38.208 86.208 38.232 86.4 ;
    END
  END rd[191]
  PIN rd[192]
    DIRECTION OUTPUT ;
    USE SIGNAL ;
    PORT
      LAYER M3 ;
        RECT  38.304 86.256 38.322 86.4 ;
    END
  END rd[192]
  PIN rd[193]
    DIRECTION OUTPUT ;
    USE SIGNAL ;
    PORT
      LAYER M5 ;
        RECT  38.352 86.208 38.376 86.4 ;
    END
  END rd[193]
  PIN rd[194]
    DIRECTION OUTPUT ;
    USE SIGNAL ;
    PORT
      LAYER M3 ;
        RECT  38.448 86.256 38.466 86.4 ;
    END
  END rd[194]
  PIN rd[195]
    DIRECTION OUTPUT ;
    USE SIGNAL ;
    PORT
      LAYER M5 ;
        RECT  38.496 86.208 38.52 86.4 ;
    END
  END rd[195]
  PIN rd[196]
    DIRECTION OUTPUT ;
    USE SIGNAL ;
    PORT
      LAYER M3 ;
        RECT  38.592 86.256 38.61 86.4 ;
    END
  END rd[196]
  PIN rd[197]
    DIRECTION OUTPUT ;
    USE SIGNAL ;
    PORT
      LAYER M5 ;
        RECT  38.64 86.208 38.664 86.4 ;
    END
  END rd[197]
  PIN rd[198]
    DIRECTION OUTPUT ;
    USE SIGNAL ;
    PORT
      LAYER M3 ;
        RECT  38.736 86.256 38.754 86.4 ;
    END
  END rd[198]
  PIN rd[199]
    DIRECTION OUTPUT ;
    USE SIGNAL ;
    PORT
      LAYER M5 ;
        RECT  38.784 86.208 38.808 86.4 ;
    END
  END rd[199]
  PIN rd[19]
    DIRECTION OUTPUT ;
    USE SIGNAL ;
    PORT
      LAYER M5 ;
        RECT  25.824 86.208 25.848 86.4 ;
    END
  END rd[19]
  PIN rd[1]
    DIRECTION OUTPUT ;
    USE SIGNAL ;
    PORT
      LAYER M5 ;
        RECT  24.528 86.208 24.552 86.4 ;
    END
  END rd[1]
  PIN rd[200]
    DIRECTION OUTPUT ;
    USE SIGNAL ;
    PORT
      LAYER M3 ;
        RECT  38.88 86.256 38.898 86.4 ;
    END
  END rd[200]
  PIN rd[201]
    DIRECTION OUTPUT ;
    USE SIGNAL ;
    PORT
      LAYER M5 ;
        RECT  38.928 86.208 38.952 86.4 ;
    END
  END rd[201]
  PIN rd[202]
    DIRECTION OUTPUT ;
    USE SIGNAL ;
    PORT
      LAYER M3 ;
        RECT  39.024 86.256 39.042 86.4 ;
    END
  END rd[202]
  PIN rd[203]
    DIRECTION OUTPUT ;
    USE SIGNAL ;
    PORT
      LAYER M5 ;
        RECT  39.072 86.208 39.096 86.4 ;
    END
  END rd[203]
  PIN rd[204]
    DIRECTION OUTPUT ;
    USE SIGNAL ;
    PORT
      LAYER M3 ;
        RECT  39.168 86.256 39.186 86.4 ;
    END
  END rd[204]
  PIN rd[205]
    DIRECTION OUTPUT ;
    USE SIGNAL ;
    PORT
      LAYER M5 ;
        RECT  39.216 86.208 39.24 86.4 ;
    END
  END rd[205]
  PIN rd[206]
    DIRECTION OUTPUT ;
    USE SIGNAL ;
    PORT
      LAYER M3 ;
        RECT  39.312 86.256 39.33 86.4 ;
    END
  END rd[206]
  PIN rd[207]
    DIRECTION OUTPUT ;
    USE SIGNAL ;
    PORT
      LAYER M5 ;
        RECT  39.36 86.208 39.384 86.4 ;
    END
  END rd[207]
  PIN rd[208]
    DIRECTION OUTPUT ;
    USE SIGNAL ;
    PORT
      LAYER M3 ;
        RECT  39.456 86.256 39.474 86.4 ;
    END
    PORT
      LAYER M3 ;
        RECT  39.42 86.268 39.546 86.333 ;
    END
  END rd[208]
  PIN rd[209]
    DIRECTION OUTPUT ;
    USE SIGNAL ;
    PORT
      LAYER M5 ;
        RECT  39.504 86.208 39.528 86.4 ;
    END
  END rd[209]
  PIN rd[20]
    DIRECTION OUTPUT ;
    USE SIGNAL ;
    PORT
      LAYER M3 ;
        RECT  25.92 86.256 25.938 86.4 ;
    END
  END rd[20]
  PIN rd[210]
    DIRECTION OUTPUT ;
    USE SIGNAL ;
    PORT
      LAYER M3 ;
        RECT  39.6 86.256 39.618 86.4 ;
    END
  END rd[210]
  PIN rd[211]
    DIRECTION OUTPUT ;
    USE SIGNAL ;
    PORT
      LAYER M5 ;
        RECT  39.648 86.208 39.672 86.4 ;
    END
  END rd[211]
  PIN rd[212]
    DIRECTION OUTPUT ;
    USE SIGNAL ;
    PORT
      LAYER M3 ;
        RECT  39.744 86.256 39.762 86.4 ;
    END
  END rd[212]
  PIN rd[213]
    DIRECTION OUTPUT ;
    USE SIGNAL ;
    PORT
      LAYER M5 ;
        RECT  39.792 86.208 39.816 86.4 ;
    END
  END rd[213]
  PIN rd[214]
    DIRECTION OUTPUT ;
    USE SIGNAL ;
    PORT
      LAYER M3 ;
        RECT  39.888 86.256 39.906 86.4 ;
    END
  END rd[214]
  PIN rd[215]
    DIRECTION OUTPUT ;
    USE SIGNAL ;
    PORT
      LAYER M5 ;
        RECT  39.936 86.208 39.96 86.4 ;
    END
  END rd[215]
  PIN rd[216]
    DIRECTION OUTPUT ;
    USE SIGNAL ;
    PORT
      LAYER M3 ;
        RECT  40.032 86.256 40.05 86.4 ;
    END
  END rd[216]
  PIN rd[217]
    DIRECTION OUTPUT ;
    USE SIGNAL ;
    PORT
      LAYER M5 ;
        RECT  40.08 86.208 40.104 86.4 ;
    END
  END rd[217]
  PIN rd[218]
    DIRECTION OUTPUT ;
    USE SIGNAL ;
    PORT
      LAYER M3 ;
        RECT  40.176 86.256 40.194 86.4 ;
    END
  END rd[218]
  PIN rd[219]
    DIRECTION OUTPUT ;
    USE SIGNAL ;
    PORT
      LAYER M5 ;
        RECT  40.224 86.208 40.248 86.4 ;
    END
  END rd[219]
  PIN rd[21]
    DIRECTION OUTPUT ;
    USE SIGNAL ;
    PORT
      LAYER M5 ;
        RECT  25.968 86.208 25.992 86.4 ;
    END
  END rd[21]
  PIN rd[220]
    DIRECTION OUTPUT ;
    USE SIGNAL ;
    PORT
      LAYER M3 ;
        RECT  40.32 86.256 40.338 86.4 ;
    END
  END rd[220]
  PIN rd[221]
    DIRECTION OUTPUT ;
    USE SIGNAL ;
    PORT
      LAYER M5 ;
        RECT  40.368 86.208 40.392 86.4 ;
    END
  END rd[221]
  PIN rd[222]
    DIRECTION OUTPUT ;
    USE SIGNAL ;
    PORT
      LAYER M3 ;
        RECT  40.464 86.256 40.482 86.4 ;
    END
  END rd[222]
  PIN rd[223]
    DIRECTION OUTPUT ;
    USE SIGNAL ;
    PORT
      LAYER M5 ;
        RECT  40.512 86.208 40.536 86.4 ;
    END
  END rd[223]
  PIN rd[224]
    DIRECTION OUTPUT ;
    USE SIGNAL ;
    PORT
      LAYER M3 ;
        RECT  40.608 86.256 40.626 86.4 ;
    END
  END rd[224]
  PIN rd[225]
    DIRECTION OUTPUT ;
    USE SIGNAL ;
    PORT
      LAYER M5 ;
        RECT  40.656 86.208 40.68 86.4 ;
    END
  END rd[225]
  PIN rd[226]
    DIRECTION OUTPUT ;
    USE SIGNAL ;
    PORT
      LAYER M3 ;
        RECT  40.752 86.256 40.77 86.4 ;
    END
  END rd[226]
  PIN rd[227]
    DIRECTION OUTPUT ;
    USE SIGNAL ;
    PORT
      LAYER M5 ;
        RECT  40.8 86.208 40.824 86.4 ;
    END
  END rd[227]
  PIN rd[228]
    DIRECTION OUTPUT ;
    USE SIGNAL ;
    PORT
      LAYER M3 ;
        RECT  40.896 86.256 40.914 86.4 ;
    END
  END rd[228]
  PIN rd[229]
    DIRECTION OUTPUT ;
    USE SIGNAL ;
    PORT
      LAYER M5 ;
        RECT  40.944 86.208 40.968 86.4 ;
    END
  END rd[229]
  PIN rd[22]
    DIRECTION OUTPUT ;
    USE SIGNAL ;
    PORT
      LAYER M3 ;
        RECT  26.064 86.256 26.082 86.4 ;
    END
  END rd[22]
  PIN rd[230]
    DIRECTION OUTPUT ;
    USE SIGNAL ;
    PORT
      LAYER M3 ;
        RECT  41.04 86.256 41.058 86.4 ;
    END
  END rd[230]
  PIN rd[231]
    DIRECTION OUTPUT ;
    USE SIGNAL ;
    PORT
      LAYER M5 ;
        RECT  41.088 86.208 41.112 86.4 ;
    END
  END rd[231]
  PIN rd[232]
    DIRECTION OUTPUT ;
    USE SIGNAL ;
    PORT
      LAYER M3 ;
        RECT  41.184 86.256 41.202 86.4 ;
    END
  END rd[232]
  PIN rd[233]
    DIRECTION OUTPUT ;
    USE SIGNAL ;
    PORT
      LAYER M5 ;
        RECT  41.232 86.208 41.256 86.4 ;
    END
  END rd[233]
  PIN rd[234]
    DIRECTION OUTPUT ;
    USE SIGNAL ;
    PORT
      LAYER M3 ;
        RECT  41.328 86.256 41.346 86.4 ;
    END
  END rd[234]
  PIN rd[235]
    DIRECTION OUTPUT ;
    USE SIGNAL ;
    PORT
      LAYER M5 ;
        RECT  41.376 86.208 41.4 86.4 ;
    END
  END rd[235]
  PIN rd[236]
    DIRECTION OUTPUT ;
    USE SIGNAL ;
    PORT
      LAYER M3 ;
        RECT  41.472 86.256 41.49 86.4 ;
    END
  END rd[236]
  PIN rd[237]
    DIRECTION OUTPUT ;
    USE SIGNAL ;
    PORT
      LAYER M5 ;
        RECT  41.52 86.208 41.544 86.4 ;
    END
  END rd[237]
  PIN rd[238]
    DIRECTION OUTPUT ;
    USE SIGNAL ;
    PORT
      LAYER M3 ;
        RECT  41.616 86.256 41.634 86.4 ;
    END
  END rd[238]
  PIN rd[239]
    DIRECTION OUTPUT ;
    USE SIGNAL ;
    PORT
      LAYER M5 ;
        RECT  41.664 86.208 41.688 86.4 ;
    END
  END rd[239]
  PIN rd[23]
    DIRECTION OUTPUT ;
    USE SIGNAL ;
    PORT
      LAYER M5 ;
        RECT  26.112 86.208 26.136 86.4 ;
    END
  END rd[23]
  PIN rd[240]
    DIRECTION OUTPUT ;
    USE SIGNAL ;
    PORT
      LAYER M3 ;
        RECT  41.76 86.256 41.778 86.4 ;
    END
  END rd[240]
  PIN rd[241]
    DIRECTION OUTPUT ;
    USE SIGNAL ;
    PORT
      LAYER M5 ;
        RECT  41.808 86.208 41.832 86.4 ;
    END
  END rd[241]
  PIN rd[242]
    DIRECTION OUTPUT ;
    USE SIGNAL ;
    PORT
      LAYER M3 ;
        RECT  41.904 86.256 41.922 86.4 ;
    END
  END rd[242]
  PIN rd[243]
    DIRECTION OUTPUT ;
    USE SIGNAL ;
    PORT
      LAYER M5 ;
        RECT  41.952 86.208 41.976 86.4 ;
    END
  END rd[243]
  PIN rd[244]
    DIRECTION OUTPUT ;
    USE SIGNAL ;
    PORT
      LAYER M3 ;
        RECT  42.048 86.256 42.066 86.4 ;
    END
  END rd[244]
  PIN rd[245]
    DIRECTION OUTPUT ;
    USE SIGNAL ;
    PORT
      LAYER M5 ;
        RECT  42.096 86.208 42.12 86.4 ;
    END
  END rd[245]
  PIN rd[246]
    DIRECTION OUTPUT ;
    USE SIGNAL ;
    PORT
      LAYER M3 ;
        RECT  42.192 86.256 42.21 86.4 ;
    END
  END rd[246]
  PIN rd[247]
    DIRECTION OUTPUT ;
    USE SIGNAL ;
    PORT
      LAYER M5 ;
        RECT  42.24 86.208 42.264 86.4 ;
    END
  END rd[247]
  PIN rd[248]
    DIRECTION OUTPUT ;
    USE SIGNAL ;
    PORT
      LAYER M3 ;
        RECT  42.336 86.256 42.354 86.4 ;
    END
  END rd[248]
  PIN rd[249]
    DIRECTION OUTPUT ;
    USE SIGNAL ;
    PORT
      LAYER M5 ;
        RECT  42.384 86.208 42.408 86.4 ;
    END
  END rd[249]
  PIN rd[24]
    DIRECTION OUTPUT ;
    USE SIGNAL ;
    PORT
      LAYER M3 ;
        RECT  26.208 86.256 26.226 86.4 ;
    END
  END rd[24]
  PIN rd[250]
    DIRECTION OUTPUT ;
    USE SIGNAL ;
    PORT
      LAYER M3 ;
        RECT  42.48 86.256 42.498 86.4 ;
    END
  END rd[250]
  PIN rd[251]
    DIRECTION OUTPUT ;
    USE SIGNAL ;
    PORT
      LAYER M5 ;
        RECT  42.528 86.208 42.552 86.4 ;
    END
  END rd[251]
  PIN rd[252]
    DIRECTION OUTPUT ;
    USE SIGNAL ;
    PORT
      LAYER M3 ;
        RECT  42.624 86.256 42.642 86.4 ;
    END
  END rd[252]
  PIN rd[253]
    DIRECTION OUTPUT ;
    USE SIGNAL ;
    PORT
      LAYER M5 ;
        RECT  42.672 86.208 42.696 86.4 ;
    END
  END rd[253]
  PIN rd[254]
    DIRECTION OUTPUT ;
    USE SIGNAL ;
    PORT
      LAYER M3 ;
        RECT  42.768 86.256 42.786 86.4 ;
    END
  END rd[254]
  PIN rd[255]
    DIRECTION OUTPUT ;
    USE SIGNAL ;
    PORT
      LAYER M5 ;
        RECT  42.816 86.208 42.84 86.4 ;
    END
  END rd[255]
  PIN rd[25]
    DIRECTION OUTPUT ;
    USE SIGNAL ;
    PORT
      LAYER M5 ;
        RECT  26.256 86.208 26.28 86.4 ;
    END
  END rd[25]
  PIN rd[26]
    DIRECTION OUTPUT ;
    USE SIGNAL ;
    PORT
      LAYER M3 ;
        RECT  26.352 86.256 26.37 86.4 ;
    END
  END rd[26]
  PIN rd[27]
    DIRECTION OUTPUT ;
    USE SIGNAL ;
    PORT
      LAYER M5 ;
        RECT  26.4 86.208 26.424 86.4 ;
    END
  END rd[27]
  PIN rd[28]
    DIRECTION OUTPUT ;
    USE SIGNAL ;
    PORT
      LAYER M3 ;
        RECT  26.496 86.256 26.514 86.4 ;
    END
  END rd[28]
  PIN rd[29]
    DIRECTION OUTPUT ;
    USE SIGNAL ;
    PORT
      LAYER M5 ;
        RECT  26.544 86.208 26.568 86.4 ;
    END
  END rd[29]
  PIN rd[2]
    DIRECTION OUTPUT ;
    USE SIGNAL ;
    PORT
      LAYER M3 ;
        RECT  24.624 86.256 24.642 86.4 ;
    END
  END rd[2]
  PIN rd[30]
    DIRECTION OUTPUT ;
    USE SIGNAL ;
    PORT
      LAYER M3 ;
        RECT  26.64 86.256 26.658 86.4 ;
    END
  END rd[30]
  PIN rd[31]
    DIRECTION OUTPUT ;
    USE SIGNAL ;
    PORT
      LAYER M5 ;
        RECT  26.688 86.208 26.712 86.4 ;
    END
  END rd[31]
  PIN rd[32]
    DIRECTION OUTPUT ;
    USE SIGNAL ;
    PORT
      LAYER M3 ;
        RECT  26.784 86.256 26.802 86.4 ;
    END
  END rd[32]
  PIN rd[33]
    DIRECTION OUTPUT ;
    USE SIGNAL ;
    PORT
      LAYER M5 ;
        RECT  26.832 86.208 26.856 86.4 ;
    END
  END rd[33]
  PIN rd[34]
    DIRECTION OUTPUT ;
    USE SIGNAL ;
    PORT
      LAYER M3 ;
        RECT  26.928 86.256 26.946 86.4 ;
    END
  END rd[34]
  PIN rd[35]
    DIRECTION OUTPUT ;
    USE SIGNAL ;
    PORT
      LAYER M5 ;
        RECT  26.976 86.208 27 86.4 ;
    END
  END rd[35]
  PIN rd[36]
    DIRECTION OUTPUT ;
    USE SIGNAL ;
    PORT
      LAYER M3 ;
        RECT  27.072 86.256 27.09 86.4 ;
    END
  END rd[36]
  PIN rd[37]
    DIRECTION OUTPUT ;
    USE SIGNAL ;
    PORT
      LAYER M5 ;
        RECT  27.12 86.208 27.144 86.4 ;
    END
  END rd[37]
  PIN rd[38]
    DIRECTION OUTPUT ;
    USE SIGNAL ;
    PORT
      LAYER M3 ;
        RECT  27.216 86.256 27.234 86.4 ;
    END
  END rd[38]
  PIN rd[39]
    DIRECTION OUTPUT ;
    USE SIGNAL ;
    PORT
      LAYER M5 ;
        RECT  27.264 86.208 27.288 86.4 ;
    END
  END rd[39]
  PIN rd[3]
    DIRECTION OUTPUT ;
    USE SIGNAL ;
    PORT
      LAYER M5 ;
        RECT  24.672 86.208 24.696 86.4 ;
    END
  END rd[3]
  PIN rd[40]
    DIRECTION OUTPUT ;
    USE SIGNAL ;
    PORT
      LAYER M3 ;
        RECT  27.36 86.256 27.378 86.4 ;
    END
  END rd[40]
  PIN rd[41]
    DIRECTION OUTPUT ;
    USE SIGNAL ;
    PORT
      LAYER M5 ;
        RECT  27.408 86.208 27.432 86.4 ;
    END
  END rd[41]
  PIN rd[42]
    DIRECTION OUTPUT ;
    USE SIGNAL ;
    PORT
      LAYER M3 ;
        RECT  27.504 86.256 27.522 86.4 ;
    END
  END rd[42]
  PIN rd[43]
    DIRECTION OUTPUT ;
    USE SIGNAL ;
    PORT
      LAYER M5 ;
        RECT  27.552 86.208 27.576 86.4 ;
    END
  END rd[43]
  PIN rd[44]
    DIRECTION OUTPUT ;
    USE SIGNAL ;
    PORT
      LAYER M3 ;
        RECT  27.648 86.256 27.666 86.4 ;
    END
  END rd[44]
  PIN rd[45]
    DIRECTION OUTPUT ;
    USE SIGNAL ;
    PORT
      LAYER M5 ;
        RECT  27.696 86.208 27.72 86.4 ;
    END
  END rd[45]
  PIN rd[46]
    DIRECTION OUTPUT ;
    USE SIGNAL ;
    PORT
      LAYER M3 ;
        RECT  27.792 86.256 27.81 86.4 ;
    END
  END rd[46]
  PIN rd[47]
    DIRECTION OUTPUT ;
    USE SIGNAL ;
    PORT
      LAYER M5 ;
        RECT  27.84 86.208 27.864 86.4 ;
    END
  END rd[47]
  PIN rd[48]
    DIRECTION OUTPUT ;
    USE SIGNAL ;
    PORT
      LAYER M3 ;
        RECT  27.936 86.256 27.954 86.4 ;
    END
  END rd[48]
  PIN rd[49]
    DIRECTION OUTPUT ;
    USE SIGNAL ;
    PORT
      LAYER M5 ;
        RECT  27.984 86.208 28.008 86.4 ;
    END
  END rd[49]
  PIN rd[4]
    DIRECTION OUTPUT ;
    USE SIGNAL ;
    PORT
      LAYER M3 ;
        RECT  24.768 86.256 24.786 86.4 ;
    END
  END rd[4]
  PIN rd[50]
    DIRECTION OUTPUT ;
    USE SIGNAL ;
    PORT
      LAYER M3 ;
        RECT  28.08 86.256 28.098 86.4 ;
    END
  END rd[50]
  PIN rd[51]
    DIRECTION OUTPUT ;
    USE SIGNAL ;
    PORT
      LAYER M5 ;
        RECT  28.128 86.208 28.152 86.4 ;
    END
  END rd[51]
  PIN rd[52]
    DIRECTION OUTPUT ;
    USE SIGNAL ;
    PORT
      LAYER M3 ;
        RECT  28.224 86.256 28.242 86.4 ;
    END
  END rd[52]
  PIN rd[53]
    DIRECTION OUTPUT ;
    USE SIGNAL ;
    PORT
      LAYER M5 ;
        RECT  28.272 86.208 28.296 86.4 ;
    END
  END rd[53]
  PIN rd[54]
    DIRECTION OUTPUT ;
    USE SIGNAL ;
    PORT
      LAYER M3 ;
        RECT  28.368 86.256 28.386 86.4 ;
    END
  END rd[54]
  PIN rd[55]
    DIRECTION OUTPUT ;
    USE SIGNAL ;
    PORT
      LAYER M5 ;
        RECT  28.416 86.208 28.44 86.4 ;
    END
  END rd[55]
  PIN rd[56]
    DIRECTION OUTPUT ;
    USE SIGNAL ;
    PORT
      LAYER M3 ;
        RECT  28.512 86.256 28.53 86.4 ;
    END
  END rd[56]
  PIN rd[57]
    DIRECTION OUTPUT ;
    USE SIGNAL ;
    PORT
      LAYER M5 ;
        RECT  28.56 86.208 28.584 86.4 ;
    END
  END rd[57]
  PIN rd[58]
    DIRECTION OUTPUT ;
    USE SIGNAL ;
    PORT
      LAYER M3 ;
        RECT  28.656 86.256 28.674 86.4 ;
    END
  END rd[58]
  PIN rd[59]
    DIRECTION OUTPUT ;
    USE SIGNAL ;
    PORT
      LAYER M5 ;
        RECT  28.704 86.208 28.728 86.4 ;
    END
  END rd[59]
  PIN rd[5]
    DIRECTION OUTPUT ;
    USE SIGNAL ;
    PORT
      LAYER M5 ;
        RECT  24.816 86.208 24.84 86.4 ;
    END
  END rd[5]
  PIN rd[60]
    DIRECTION OUTPUT ;
    USE SIGNAL ;
    PORT
      LAYER M3 ;
        RECT  28.8 86.256 28.818 86.4 ;
    END
  END rd[60]
  PIN rd[61]
    DIRECTION OUTPUT ;
    USE SIGNAL ;
    PORT
      LAYER M5 ;
        RECT  28.848 86.208 28.872 86.4 ;
    END
  END rd[61]
  PIN rd[62]
    DIRECTION OUTPUT ;
    USE SIGNAL ;
    PORT
      LAYER M3 ;
        RECT  28.944 86.256 28.962 86.4 ;
    END
  END rd[62]
  PIN rd[63]
    DIRECTION OUTPUT ;
    USE SIGNAL ;
    PORT
      LAYER M5 ;
        RECT  28.992 86.208 29.016 86.4 ;
    END
  END rd[63]
  PIN rd[64]
    DIRECTION OUTPUT ;
    USE SIGNAL ;
    PORT
      LAYER M3 ;
        RECT  29.088 86.256 29.106 86.4 ;
    END
  END rd[64]
  PIN rd[65]
    DIRECTION OUTPUT ;
    USE SIGNAL ;
    PORT
      LAYER M5 ;
        RECT  29.136 86.208 29.16 86.4 ;
    END
  END rd[65]
  PIN rd[66]
    DIRECTION OUTPUT ;
    USE SIGNAL ;
    PORT
      LAYER M3 ;
        RECT  29.232 86.256 29.25 86.4 ;
    END
  END rd[66]
  PIN rd[67]
    DIRECTION OUTPUT ;
    USE SIGNAL ;
    PORT
      LAYER M5 ;
        RECT  29.28 86.208 29.304 86.4 ;
    END
  END rd[67]
  PIN rd[68]
    DIRECTION OUTPUT ;
    USE SIGNAL ;
    PORT
      LAYER M3 ;
        RECT  29.376 86.256 29.394 86.4 ;
    END
  END rd[68]
  PIN rd[69]
    DIRECTION OUTPUT ;
    USE SIGNAL ;
    PORT
      LAYER M5 ;
        RECT  29.424 86.208 29.448 86.4 ;
    END
  END rd[69]
  PIN rd[6]
    DIRECTION OUTPUT ;
    USE SIGNAL ;
    PORT
      LAYER M3 ;
        RECT  24.912 86.256 24.93 86.4 ;
    END
  END rd[6]
  PIN rd[70]
    DIRECTION OUTPUT ;
    USE SIGNAL ;
    PORT
      LAYER M3 ;
        RECT  29.52 86.256 29.538 86.4 ;
    END
  END rd[70]
  PIN rd[71]
    DIRECTION OUTPUT ;
    USE SIGNAL ;
    PORT
      LAYER M5 ;
        RECT  29.568 86.208 29.592 86.4 ;
    END
  END rd[71]
  PIN rd[72]
    DIRECTION OUTPUT ;
    USE SIGNAL ;
    PORT
      LAYER M3 ;
        RECT  29.664 86.256 29.682 86.4 ;
    END
  END rd[72]
  PIN rd[73]
    DIRECTION OUTPUT ;
    USE SIGNAL ;
    PORT
      LAYER M5 ;
        RECT  29.712 86.208 29.736 86.4 ;
    END
  END rd[73]
  PIN rd[74]
    DIRECTION OUTPUT ;
    USE SIGNAL ;
    PORT
      LAYER M3 ;
        RECT  29.808 86.256 29.826 86.4 ;
    END
  END rd[74]
  PIN rd[75]
    DIRECTION OUTPUT ;
    USE SIGNAL ;
    PORT
      LAYER M5 ;
        RECT  29.856 86.208 29.88 86.4 ;
    END
  END rd[75]
  PIN rd[76]
    DIRECTION OUTPUT ;
    USE SIGNAL ;
    PORT
      LAYER M3 ;
        RECT  29.952 86.256 29.97 86.4 ;
    END
  END rd[76]
  PIN rd[77]
    DIRECTION OUTPUT ;
    USE SIGNAL ;
    PORT
      LAYER M5 ;
        RECT  30 86.208 30.024 86.4 ;
    END
  END rd[77]
  PIN rd[78]
    DIRECTION OUTPUT ;
    USE SIGNAL ;
    PORT
      LAYER M3 ;
        RECT  30.096 86.256 30.114 86.4 ;
    END
  END rd[78]
  PIN rd[79]
    DIRECTION OUTPUT ;
    USE SIGNAL ;
    PORT
      LAYER M5 ;
        RECT  30.144 86.208 30.168 86.4 ;
    END
  END rd[79]
  PIN rd[7]
    DIRECTION OUTPUT ;
    USE SIGNAL ;
    PORT
      LAYER M5 ;
        RECT  24.96 86.208 24.984 86.4 ;
    END
  END rd[7]
  PIN rd[80]
    DIRECTION OUTPUT ;
    USE SIGNAL ;
    PORT
      LAYER M3 ;
        RECT  30.24 86.256 30.258 86.4 ;
    END
  END rd[80]
  PIN rd[81]
    DIRECTION OUTPUT ;
    USE SIGNAL ;
    PORT
      LAYER M5 ;
        RECT  30.288 86.208 30.312 86.4 ;
    END
  END rd[81]
  PIN rd[82]
    DIRECTION OUTPUT ;
    USE SIGNAL ;
    PORT
      LAYER M3 ;
        RECT  30.384 86.256 30.402 86.4 ;
    END
  END rd[82]
  PIN rd[83]
    DIRECTION OUTPUT ;
    USE SIGNAL ;
    PORT
      LAYER M5 ;
        RECT  30.432 86.208 30.456 86.4 ;
    END
  END rd[83]
  PIN rd[84]
    DIRECTION OUTPUT ;
    USE SIGNAL ;
    PORT
      LAYER M3 ;
        RECT  30.528 86.256 30.546 86.4 ;
    END
  END rd[84]
  PIN rd[85]
    DIRECTION OUTPUT ;
    USE SIGNAL ;
    PORT
      LAYER M5 ;
        RECT  30.576 86.208 30.6 86.4 ;
    END
  END rd[85]
  PIN rd[86]
    DIRECTION OUTPUT ;
    USE SIGNAL ;
    PORT
      LAYER M3 ;
        RECT  30.672 86.256 30.69 86.4 ;
    END
  END rd[86]
  PIN rd[87]
    DIRECTION OUTPUT ;
    USE SIGNAL ;
    PORT
      LAYER M5 ;
        RECT  30.72 86.208 30.744 86.4 ;
    END
  END rd[87]
  PIN rd[88]
    DIRECTION OUTPUT ;
    USE SIGNAL ;
    PORT
      LAYER M3 ;
        RECT  30.816 86.256 30.834 86.4 ;
    END
  END rd[88]
  PIN rd[89]
    DIRECTION OUTPUT ;
    USE SIGNAL ;
    PORT
      LAYER M5 ;
        RECT  30.864 86.208 30.888 86.4 ;
    END
  END rd[89]
  PIN rd[8]
    DIRECTION OUTPUT ;
    USE SIGNAL ;
    PORT
      LAYER M3 ;
        RECT  25.056 86.256 25.074 86.4 ;
    END
  END rd[8]
  PIN rd[90]
    DIRECTION OUTPUT ;
    USE SIGNAL ;
    PORT
      LAYER M3 ;
        RECT  30.96 86.256 30.978 86.4 ;
    END
  END rd[90]
  PIN rd[91]
    DIRECTION OUTPUT ;
    USE SIGNAL ;
    PORT
      LAYER M5 ;
        RECT  31.008 86.208 31.032 86.4 ;
    END
  END rd[91]
  PIN rd[92]
    DIRECTION OUTPUT ;
    USE SIGNAL ;
    PORT
      LAYER M3 ;
        RECT  31.104 86.256 31.122 86.4 ;
    END
  END rd[92]
  PIN rd[93]
    DIRECTION OUTPUT ;
    USE SIGNAL ;
    PORT
      LAYER M5 ;
        RECT  31.152 86.208 31.176 86.4 ;
    END
  END rd[93]
  PIN rd[94]
    DIRECTION OUTPUT ;
    USE SIGNAL ;
    PORT
      LAYER M3 ;
        RECT  31.248 86.256 31.266 86.4 ;
    END
  END rd[94]
  PIN rd[95]
    DIRECTION OUTPUT ;
    USE SIGNAL ;
    PORT
      LAYER M5 ;
        RECT  31.296 86.208 31.32 86.4 ;
    END
  END rd[95]
  PIN rd[96]
    DIRECTION OUTPUT ;
    USE SIGNAL ;
    PORT
      LAYER M3 ;
        RECT  31.392 86.256 31.41 86.4 ;
    END
  END rd[96]
  PIN rd[97]
    DIRECTION OUTPUT ;
    USE SIGNAL ;
    PORT
      LAYER M5 ;
        RECT  31.44 86.208 31.464 86.4 ;
    END
  END rd[97]
  PIN rd[98]
    DIRECTION OUTPUT ;
    USE SIGNAL ;
    PORT
      LAYER M3 ;
        RECT  31.536 86.256 31.554 86.4 ;
    END
  END rd[98]
  PIN rd[99]
    DIRECTION OUTPUT ;
    USE SIGNAL ;
    PORT
      LAYER M5 ;
        RECT  31.584 86.208 31.608 86.4 ;
    END
  END rd[99]
  PIN rd[9]
    DIRECTION OUTPUT ;
    USE SIGNAL ;
    PORT
      LAYER M5 ;
        RECT  25.104 86.208 25.128 86.4 ;
    END
  END rd[9]
  PIN rq0
    DIRECTION INPUT ;
    USE SIGNAL ;
    PORT
      LAYER M4 ;
        RECT  0 38.736 0.192 38.76 ;
    END
  END rq0
  PIN rq1
    DIRECTION INPUT ;
    USE SIGNAL ;
    PORT
      LAYER M4 ;
        RECT  0 38.592 0.192 38.616 ;
    END
  END rq1
  PIN rst_n
    DIRECTION INPUT ;
    USE SIGNAL ;
    PORT
      LAYER M4 ;
        RECT  0 51.024 0.192 51.048 ;
    END
    PORT
      LAYER M4 ;
        RECT  0.156 51.024 0.517 51.048 ;
    END
  END rst_n
  PIN w0[0]
    DIRECTION INPUT ;
    USE SIGNAL ;
    PORT
      LAYER M4 ;
        RECT  0 38.88 0.192 38.904 ;
    END
  END w0[0]
  PIN w0[1]
    DIRECTION INPUT ;
    USE SIGNAL ;
    PORT
      LAYER M4 ;
        RECT  0 39.024 0.192 39.048 ;
    END
  END w0[1]
  PIN w0[2]
    DIRECTION INPUT ;
    USE SIGNAL ;
    PORT
      LAYER M4 ;
        RECT  0 39.168 0.192 39.192 ;
    END
  END w0[2]
  PIN w0[3]
    DIRECTION INPUT ;
    USE SIGNAL ;
    PORT
      LAYER M4 ;
        RECT  0 39.312 0.192 39.336 ;
    END
  END w0[3]
  PIN w0[4]
    DIRECTION INPUT ;
    USE SIGNAL ;
    PORT
      LAYER M4 ;
        RECT  0 39.456 0.192 39.48 ;
    END
  END w0[4]
  PIN w0[5]
    DIRECTION INPUT ;
    USE SIGNAL ;
    PORT
      LAYER M4 ;
        RECT  0 39.6 0.192 39.624 ;
    END
  END w0[5]
  PIN w0[6]
    DIRECTION INPUT ;
    USE SIGNAL ;
    PORT
      LAYER M4 ;
        RECT  0 39.744 0.192 39.768 ;
    END
  END w0[6]
  PIN w0[7]
    DIRECTION INPUT ;
    USE SIGNAL ;
    PORT
      LAYER M4 ;
        RECT  0 39.888 0.192 39.912 ;
    END
  END w0[7]
  PIN w0[8]
    DIRECTION INPUT ;
    USE SIGNAL ;
    PORT
      LAYER M4 ;
        RECT  0 40.032 0.192 40.056 ;
    END
  END w0[8]
  PIN w1[0]
    DIRECTION INPUT ;
    USE SIGNAL ;
    PORT
      LAYER M4 ;
        RECT  0 40.176 0.192 40.2 ;
    END
  END w1[0]
  PIN w1[1]
    DIRECTION INPUT ;
    USE SIGNAL ;
    PORT
      LAYER M4 ;
        RECT  0 40.32 0.192 40.344 ;
    END
  END w1[1]
  PIN w1[2]
    DIRECTION INPUT ;
    USE SIGNAL ;
    PORT
      LAYER M4 ;
        RECT  0 40.464 0.192 40.488 ;
    END
  END w1[2]
  PIN w1[3]
    DIRECTION INPUT ;
    USE SIGNAL ;
    PORT
      LAYER M4 ;
        RECT  0 40.608 0.192 40.632 ;
    END
  END w1[3]
  PIN w1[4]
    DIRECTION INPUT ;
    USE SIGNAL ;
    PORT
      LAYER M4 ;
        RECT  0 40.752 0.192 40.776 ;
    END
  END w1[4]
  PIN w1[5]
    DIRECTION INPUT ;
    USE SIGNAL ;
    PORT
      LAYER M4 ;
        RECT  0 40.896 0.192 40.92 ;
    END
  END w1[5]
  PIN w1[6]
    DIRECTION INPUT ;
    USE SIGNAL ;
    PORT
      LAYER M4 ;
        RECT  0 41.04 0.192 41.064 ;
    END
  END w1[6]
  PIN w1[7]
    DIRECTION INPUT ;
    USE SIGNAL ;
    PORT
      LAYER M4 ;
        RECT  0 41.184 0.192 41.208 ;
    END
  END w1[7]
  PIN w1[8]
    DIRECTION INPUT ;
    USE SIGNAL ;
    PORT
      LAYER M4 ;
        RECT  0 41.328 0.192 41.352 ;
    END
  END w1[8]
  PIN wv
    DIRECTION INPUT ;
    USE SIGNAL ;
    PORT
      LAYER M4 ;
        RECT  0 41.472 0.192 41.496 ;
    END
  END wv
  PIN VDD
    DIRECTION INOUT ;
    USE POWER ;
    PORT
      LAYER M5 ;
        RECT  137.592 2.151 137.712 84.249 ;
        RECT  132.192 2.151 132.312 84.249 ;
        RECT  126.792 2.151 126.912 84.249 ;
        RECT  121.392 2.151 121.512 84.249 ;
        RECT  115.992 2.151 116.112 84.249 ;
        RECT  110.592 2.151 110.712 84.249 ;
        RECT  105.192 2.151 105.312 84.249 ;
        RECT  99.792 2.151 99.912 84.249 ;
        RECT  94.392 2.151 94.512 84.249 ;
        RECT  88.992 2.151 89.112 84.249 ;
        RECT  83.592 2.151 83.712 84.249 ;
        RECT  78.192 2.151 78.312 84.249 ;
        RECT  72.792 2.151 72.912 84.249 ;
        RECT  67.392 2.151 67.512 84.249 ;
        RECT  61.992 2.151 62.112 84.249 ;
        RECT  56.592 2.151 56.712 84.249 ;
        RECT  51.192 2.151 51.312 84.249 ;
        RECT  45.792 2.151 45.912 84.249 ;
        RECT  40.392 2.151 40.512 84.249 ;
        RECT  34.992 2.151 35.112 84.249 ;
        RECT  29.592 2.151 29.712 84.249 ;
        RECT  24.192 2.151 24.312 84.249 ;
        RECT  18.792 2.151 18.912 84.249 ;
        RECT  13.392 2.151 13.512 84.249 ;
        RECT  7.992 2.151 8.112 84.249 ;
        RECT  2.592 2.151 2.712 84.249 ;
    END
  END VDD
  PIN VSS
    DIRECTION INOUT ;
    USE GROUND ;
    PORT
      LAYER M5 ;
        RECT  137.4 2.137 137.52 84.263 ;
        RECT  132 2.137 132.12 84.263 ;
        RECT  126.6 2.137 126.72 84.263 ;
        RECT  121.2 2.137 121.32 84.263 ;
        RECT  115.8 2.137 115.92 84.263 ;
        RECT  110.4 2.137 110.52 84.263 ;
        RECT  105 2.137 105.12 84.263 ;
        RECT  99.6 2.137 99.72 84.263 ;
        RECT  94.2 2.137 94.32 84.263 ;
        RECT  88.8 2.137 88.92 84.263 ;
        RECT  83.4 2.137 83.52 84.263 ;
        RECT  78 2.137 78.12 84.263 ;
        RECT  72.6 2.137 72.72 84.263 ;
        RECT  67.2 2.137 67.32 84.263 ;
        RECT  61.8 2.137 61.92 84.263 ;
        RECT  56.4 2.137 56.52 84.263 ;
        RECT  51 2.137 51.12 84.263 ;
        RECT  45.6 2.137 45.72 84.263 ;
        RECT  40.2 2.137 40.32 84.263 ;
        RECT  34.8 2.137 34.92 84.263 ;
        RECT  29.4 2.137 29.52 84.263 ;
        RECT  24 2.137 24.12 84.263 ;
        RECT  18.6 2.137 18.72 84.263 ;
        RECT  13.2 2.137 13.32 84.263 ;
        RECT  7.8 2.137 7.92 84.263 ;
        RECT  2.4 2.137 2.52 84.263 ;
    END
  END VSS
  # OT_OBS_CLOSED layer=M5 d_um=1.536 added=485
  OBS
    LAYER RVTN ;
     RECT  2.16 2.16 140.4 2.295 ;
     RECT  2.16 2.565 140.4 2.835 ;
     RECT  2.16 3.105 140.4 3.375 ;
     RECT  2.16 3.645 140.4 3.915 ;
     RECT  2.16 4.185 140.4 4.455 ;
     RECT  2.16 4.725 140.4 4.995 ;
     RECT  2.16 5.265 140.4 5.535 ;
     RECT  2.16 5.805 140.4 6.075 ;
     RECT  2.16 6.345 140.4 6.615 ;
     RECT  2.16 6.885 140.4 7.155 ;
     RECT  2.16 7.425 140.4 7.695 ;
     RECT  2.16 7.965 140.4 8.235 ;
     RECT  2.16 8.505 140.4 8.775 ;
     RECT  2.16 9.045 140.4 9.315 ;
     RECT  2.16 9.585 140.4 9.855 ;
     RECT  2.16 10.125 140.4 10.395 ;
     RECT  2.16 10.665 140.4 10.935 ;
     RECT  2.16 11.205 140.4 11.475 ;
     RECT  2.16 11.745 140.4 12.015 ;
     RECT  2.16 12.285 140.4 12.555 ;
     RECT  2.16 12.825 140.4 13.095 ;
     RECT  2.16 13.365 140.4 13.635 ;
     RECT  2.16 13.905 140.4 14.175 ;
     RECT  2.16 14.445 140.4 14.715 ;
     RECT  2.16 14.985 140.4 15.255 ;
     RECT  2.16 15.525 140.4 15.795 ;
     RECT  2.16 16.065 140.4 16.335 ;
     RECT  2.16 16.605 140.4 16.875 ;
     RECT  2.16 17.145 140.4 17.415 ;
     RECT  2.16 17.685 140.4 17.955 ;
     RECT  2.16 18.225 140.4 18.495 ;
     RECT  2.16 18.765 140.4 19.035 ;
     RECT  2.16 19.305 140.4 19.575 ;
     RECT  2.16 19.845 140.4 20.115 ;
     RECT  2.16 20.385 20.412 20.655 ;
     RECT  119.34 20.385 140.4 20.655 ;
     RECT  2.16 20.925 20.412 21.195 ;
     RECT  119.34 20.925 140.4 21.195 ;
     RECT  2.16 21.465 20.412 21.735 ;
     RECT  119.34 21.465 140.4 21.735 ;
     RECT  2.16 22.005 20.412 22.275 ;
     RECT  119.34 22.005 140.4 22.275 ;
     RECT  2.16 22.545 20.412 22.815 ;
     RECT  119.34 22.545 140.4 22.815 ;
     RECT  2.16 23.085 20.412 23.355 ;
     RECT  119.34 23.085 140.4 23.355 ;
     RECT  2.16 23.625 20.412 23.895 ;
     RECT  119.34 23.625 140.4 23.895 ;
     RECT  2.16 24.165 20.412 24.435 ;
     RECT  119.34 24.165 140.4 24.435 ;
     RECT  2.16 24.705 20.412 24.975 ;
     RECT  119.34 24.705 140.4 24.975 ;
     RECT  2.16 25.245 20.412 25.515 ;
     RECT  119.34 25.245 140.4 25.515 ;
     RECT  2.16 25.785 20.412 26.055 ;
     RECT  119.34 25.785 140.4 26.055 ;
     RECT  2.16 26.325 20.412 26.595 ;
     RECT  119.34 26.325 140.4 26.595 ;
     RECT  2.16 26.865 20.412 27.135 ;
     RECT  119.34 26.865 140.4 27.135 ;
     RECT  2.16 27.405 20.412 27.675 ;
     RECT  119.34 27.405 140.4 27.675 ;
     RECT  2.16 27.945 20.412 28.215 ;
     RECT  119.34 27.945 140.4 28.215 ;
     RECT  2.16 28.485 20.412 28.755 ;
     RECT  119.34 28.485 140.4 28.755 ;
     RECT  2.16 29.025 20.412 29.295 ;
     RECT  119.34 29.025 140.4 29.295 ;
     RECT  2.16 29.565 20.412 29.835 ;
     RECT  119.34 29.565 140.4 29.835 ;
     RECT  2.16 30.105 20.412 30.375 ;
     RECT  119.34 30.105 140.4 30.375 ;
     RECT  2.16 30.645 20.412 30.915 ;
     RECT  119.34 30.645 140.4 30.915 ;
     RECT  2.16 31.185 20.412 31.455 ;
     RECT  119.34 31.185 140.4 31.455 ;
     RECT  2.16 31.725 20.412 31.995 ;
     RECT  119.34 31.725 140.4 31.995 ;
     RECT  2.16 32.265 20.412 32.535 ;
     RECT  119.34 32.265 140.4 32.535 ;
     RECT  2.16 32.805 20.412 33.075 ;
     RECT  119.34 32.805 140.4 33.075 ;
     RECT  2.16 33.345 20.412 33.615 ;
     RECT  119.34 33.345 140.4 33.615 ;
     RECT  2.16 33.885 20.412 34.155 ;
     RECT  119.34 33.885 140.4 34.155 ;
     RECT  2.16 34.425 20.412 34.695 ;
     RECT  119.34 34.425 140.4 34.695 ;
     RECT  2.16 34.965 20.412 35.235 ;
     RECT  119.34 34.965 140.4 35.235 ;
     RECT  2.16 35.505 20.412 35.775 ;
     RECT  119.34 35.505 140.4 35.775 ;
     RECT  2.16 36.045 20.412 36.315 ;
     RECT  119.34 36.045 140.4 36.315 ;
     RECT  2.16 36.585 20.412 36.855 ;
     RECT  119.34 36.585 140.4 36.855 ;
     RECT  2.16 37.125 20.412 37.395 ;
     RECT  119.34 37.125 140.4 37.395 ;
     RECT  2.16 37.665 20.412 37.935 ;
     RECT  119.34 37.665 140.4 37.935 ;
     RECT  2.16 38.205 20.412 38.475 ;
     RECT  119.34 38.205 140.4 38.475 ;
     RECT  2.16 38.745 20.412 39.015 ;
     RECT  119.34 38.745 140.4 39.015 ;
     RECT  2.16 39.285 20.412 39.555 ;
     RECT  119.34 39.285 140.4 39.555 ;
     RECT  2.16 39.825 20.412 40.095 ;
     RECT  119.34 39.825 140.4 40.095 ;
     RECT  2.16 40.365 20.412 40.635 ;
     RECT  119.34 40.365 140.4 40.635 ;
     RECT  2.16 40.905 20.412 41.175 ;
     RECT  119.34 40.905 140.4 41.175 ;
     RECT  2.16 41.445 20.412 41.715 ;
     RECT  119.34 41.445 140.4 41.715 ;
     RECT  2.16 41.985 20.412 42.255 ;
     RECT  119.34 41.985 140.4 42.255 ;
     RECT  2.16 42.525 20.412 42.795 ;
     RECT  119.34 42.525 140.4 42.795 ;
     RECT  2.16 43.065 20.412 43.335 ;
     RECT  119.34 43.065 140.4 43.335 ;
     RECT  2.16 43.605 20.412 43.875 ;
     RECT  119.34 43.605 140.4 43.875 ;
     RECT  2.16 44.145 20.412 44.415 ;
     RECT  119.34 44.145 140.4 44.415 ;
     RECT  2.16 44.685 20.412 44.955 ;
     RECT  119.34 44.685 140.4 44.955 ;
     RECT  2.16 45.225 20.412 45.495 ;
     RECT  119.34 45.225 140.4 45.495 ;
     RECT  2.16 45.765 20.412 46.035 ;
     RECT  119.34 45.765 140.4 46.035 ;
     RECT  2.16 46.305 20.412 46.575 ;
     RECT  119.34 46.305 140.4 46.575 ;
     RECT  2.16 46.845 20.412 47.115 ;
     RECT  119.34 46.845 140.4 47.115 ;
     RECT  2.16 47.385 20.412 47.655 ;
     RECT  119.34 47.385 140.4 47.655 ;
     RECT  2.16 47.925 20.412 48.195 ;
     RECT  119.34 47.925 140.4 48.195 ;
     RECT  2.16 48.465 20.412 48.735 ;
     RECT  119.34 48.465 140.4 48.735 ;
     RECT  2.16 49.005 20.412 49.275 ;
     RECT  119.34 49.005 140.4 49.275 ;
     RECT  2.16 49.545 20.412 49.815 ;
     RECT  119.34 49.545 140.4 49.815 ;
     RECT  2.16 50.085 20.412 50.355 ;
     RECT  119.34 50.085 140.4 50.355 ;
     RECT  2.16 50.625 20.412 50.895 ;
     RECT  119.34 50.625 140.4 50.895 ;
     RECT  2.16 51.165 20.412 51.435 ;
     RECT  119.34 51.165 140.4 51.435 ;
     RECT  2.16 51.705 20.412 51.975 ;
     RECT  119.34 51.705 140.4 51.975 ;
     RECT  2.16 52.245 20.412 52.515 ;
     RECT  119.34 52.245 140.4 52.515 ;
     RECT  2.16 52.785 20.412 53.055 ;
     RECT  119.34 52.785 140.4 53.055 ;
     RECT  2.16 53.325 20.412 53.595 ;
     RECT  119.34 53.325 140.4 53.595 ;
     RECT  2.16 53.865 20.412 54.135 ;
     RECT  119.34 53.865 140.4 54.135 ;
     RECT  2.16 54.405 20.412 54.675 ;
     RECT  119.34 54.405 140.4 54.675 ;
     RECT  2.16 54.945 20.412 55.215 ;
     RECT  119.34 54.945 140.4 55.215 ;
     RECT  2.16 55.485 20.412 55.755 ;
     RECT  119.34 55.485 140.4 55.755 ;
     RECT  2.16 56.025 20.412 56.295 ;
     RECT  119.34 56.025 140.4 56.295 ;
     RECT  2.16 56.565 20.412 56.835 ;
     RECT  119.34 56.565 140.4 56.835 ;
     RECT  2.16 57.105 20.412 57.375 ;
     RECT  119.34 57.105 140.4 57.375 ;
     RECT  2.16 57.645 20.412 57.915 ;
     RECT  119.34 57.645 140.4 57.915 ;
     RECT  2.16 58.185 20.412 58.455 ;
     RECT  119.34 58.185 140.4 58.455 ;
     RECT  2.16 58.725 20.412 58.995 ;
     RECT  119.34 58.725 140.4 58.995 ;
     RECT  2.16 59.265 20.412 59.535 ;
     RECT  119.34 59.265 140.4 59.535 ;
     RECT  2.16 59.805 20.412 60.075 ;
     RECT  119.34 59.805 140.4 60.075 ;
     RECT  2.16 60.345 20.412 60.615 ;
     RECT  119.34 60.345 140.4 60.615 ;
     RECT  2.16 60.885 20.412 61.155 ;
     RECT  119.34 60.885 140.4 61.155 ;
     RECT  2.16 61.425 20.412 61.695 ;
     RECT  119.34 61.425 140.4 61.695 ;
     RECT  2.16 61.965 20.412 62.235 ;
     RECT  119.34 61.965 140.4 62.235 ;
     RECT  2.16 62.505 20.412 62.775 ;
     RECT  119.34 62.505 140.4 62.775 ;
     RECT  2.16 63.045 20.412 63.315 ;
     RECT  119.34 63.045 140.4 63.315 ;
     RECT  2.16 63.585 20.412 63.855 ;
     RECT  119.34 63.585 140.4 63.855 ;
     RECT  2.16 64.125 20.412 64.395 ;
     RECT  119.34 64.125 140.4 64.395 ;
     RECT  2.16 64.665 20.412 64.935 ;
     RECT  119.34 64.665 140.4 64.935 ;
     RECT  2.16 65.205 20.412 65.475 ;
     RECT  119.34 65.205 140.4 65.475 ;
     RECT  2.16 65.745 140.4 66.015 ;
     RECT  2.16 66.285 140.4 66.555 ;
     RECT  2.16 66.825 140.4 67.095 ;
     RECT  2.16 67.365 140.4 67.635 ;
     RECT  2.16 67.905 140.4 68.175 ;
     RECT  2.16 68.445 140.4 68.715 ;
     RECT  2.16 68.985 140.4 69.255 ;
     RECT  2.16 69.525 140.4 69.795 ;
     RECT  2.16 70.065 140.4 70.335 ;
     RECT  2.16 70.605 140.4 70.875 ;
     RECT  2.16 71.145 140.4 71.415 ;
     RECT  2.16 71.685 140.4 71.955 ;
     RECT  2.16 72.225 140.4 72.495 ;
     RECT  2.16 72.765 140.4 73.035 ;
     RECT  2.16 73.305 140.4 73.575 ;
     RECT  2.16 73.845 140.4 74.115 ;
     RECT  2.16 74.385 140.4 74.655 ;
     RECT  2.16 74.925 140.4 75.195 ;
     RECT  2.16 75.465 140.4 75.735 ;
     RECT  2.16 76.005 140.4 76.275 ;
     RECT  2.16 76.545 140.4 76.815 ;
     RECT  2.16 77.085 140.4 77.355 ;
     RECT  2.16 77.625 140.4 77.895 ;
     RECT  2.16 78.165 140.4 78.435 ;
     RECT  2.16 78.705 140.4 78.975 ;
     RECT  2.16 79.245 140.4 79.515 ;
     RECT  2.16 79.785 140.4 80.055 ;
     RECT  2.16 80.325 140.4 80.595 ;
     RECT  2.16 80.865 140.4 81.135 ;
     RECT  2.16 81.405 140.4 81.675 ;
     RECT  2.16 81.945 140.4 82.215 ;
     RECT  2.16 82.485 140.4 82.755 ;
     RECT  2.16 83.025 140.4 83.295 ;
     RECT  2.16 83.565 140.4 83.835 ;
     RECT  2.16 84.105 140.4 84.24 ;
    LAYER RVTP ;
     RECT  2.16 2.295 140.4 2.565 ;
     RECT  2.16 2.835 140.4 3.105 ;
     RECT  2.16 3.375 140.4 3.645 ;
     RECT  2.16 3.915 140.4 4.185 ;
     RECT  2.16 4.455 140.4 4.725 ;
     RECT  2.16 4.995 140.4 5.265 ;
     RECT  2.16 5.535 140.4 5.805 ;
     RECT  2.16 6.075 140.4 6.345 ;
     RECT  2.16 6.615 140.4 6.885 ;
     RECT  2.16 7.155 140.4 7.425 ;
     RECT  2.16 7.695 140.4 7.965 ;
     RECT  2.16 8.235 140.4 8.505 ;
     RECT  2.16 8.775 140.4 9.045 ;
     RECT  2.16 9.315 140.4 9.585 ;
     RECT  2.16 9.855 140.4 10.125 ;
     RECT  2.16 10.395 140.4 10.665 ;
     RECT  2.16 10.935 140.4 11.205 ;
     RECT  2.16 11.475 140.4 11.745 ;
     RECT  2.16 12.015 140.4 12.285 ;
     RECT  2.16 12.555 140.4 12.825 ;
     RECT  2.16 13.095 140.4 13.365 ;
     RECT  2.16 13.635 140.4 13.905 ;
     RECT  2.16 14.175 140.4 14.445 ;
     RECT  2.16 14.715 140.4 14.985 ;
     RECT  2.16 15.255 140.4 15.525 ;
     RECT  2.16 15.795 140.4 16.065 ;
     RECT  2.16 16.335 140.4 16.605 ;
     RECT  2.16 16.875 140.4 17.145 ;
     RECT  2.16 17.415 140.4 17.685 ;
     RECT  2.16 17.955 140.4 18.225 ;
     RECT  2.16 18.495 140.4 18.765 ;
     RECT  2.16 19.035 140.4 19.305 ;
     RECT  2.16 19.575 140.4 19.845 ;
     RECT  2.16 20.115 140.4 20.25 ;
     RECT  2.16 20.25 20.412 20.385 ;
     RECT  119.34 20.25 140.4 20.385 ;
     RECT  2.16 20.655 20.412 20.925 ;
     RECT  119.34 20.655 140.4 20.925 ;
     RECT  2.16 21.195 20.412 21.465 ;
     RECT  119.34 21.195 140.4 21.465 ;
     RECT  2.16 21.735 20.412 22.005 ;
     RECT  119.34 21.735 140.4 22.005 ;
     RECT  2.16 22.275 20.412 22.545 ;
     RECT  119.34 22.275 140.4 22.545 ;
     RECT  2.16 22.815 20.412 23.085 ;
     RECT  119.34 22.815 140.4 23.085 ;
     RECT  2.16 23.355 20.412 23.625 ;
     RECT  119.34 23.355 140.4 23.625 ;
     RECT  2.16 23.895 20.412 24.165 ;
     RECT  119.34 23.895 140.4 24.165 ;
     RECT  2.16 24.435 20.412 24.705 ;
     RECT  119.34 24.435 140.4 24.705 ;
     RECT  2.16 24.975 20.412 25.245 ;
     RECT  119.34 24.975 140.4 25.245 ;
     RECT  2.16 25.515 20.412 25.785 ;
     RECT  119.34 25.515 140.4 25.785 ;
     RECT  2.16 26.055 20.412 26.325 ;
     RECT  119.34 26.055 140.4 26.325 ;
     RECT  2.16 26.595 20.412 26.865 ;
     RECT  119.34 26.595 140.4 26.865 ;
     RECT  2.16 27.135 20.412 27.405 ;
     RECT  119.34 27.135 140.4 27.405 ;
     RECT  2.16 27.675 20.412 27.945 ;
     RECT  119.34 27.675 140.4 27.945 ;
     RECT  2.16 28.215 20.412 28.485 ;
     RECT  119.34 28.215 140.4 28.485 ;
     RECT  2.16 28.755 20.412 29.025 ;
     RECT  119.34 28.755 140.4 29.025 ;
     RECT  2.16 29.295 20.412 29.565 ;
     RECT  119.34 29.295 140.4 29.565 ;
     RECT  2.16 29.835 20.412 30.105 ;
     RECT  119.34 29.835 140.4 30.105 ;
     RECT  2.16 30.375 20.412 30.645 ;
     RECT  119.34 30.375 140.4 30.645 ;
     RECT  2.16 30.915 20.412 31.185 ;
     RECT  119.34 30.915 140.4 31.185 ;
     RECT  2.16 31.455 20.412 31.725 ;
     RECT  119.34 31.455 140.4 31.725 ;
     RECT  2.16 31.995 20.412 32.265 ;
     RECT  119.34 31.995 140.4 32.265 ;
     RECT  2.16 32.535 20.412 32.805 ;
     RECT  119.34 32.535 140.4 32.805 ;
     RECT  2.16 33.075 20.412 33.345 ;
     RECT  119.34 33.075 140.4 33.345 ;
     RECT  2.16 33.615 20.412 33.885 ;
     RECT  119.34 33.615 140.4 33.885 ;
     RECT  2.16 34.155 20.412 34.425 ;
     RECT  119.34 34.155 140.4 34.425 ;
     RECT  2.16 34.695 20.412 34.965 ;
     RECT  119.34 34.695 140.4 34.965 ;
     RECT  2.16 35.235 20.412 35.505 ;
     RECT  119.34 35.235 140.4 35.505 ;
     RECT  2.16 35.775 20.412 36.045 ;
     RECT  119.34 35.775 140.4 36.045 ;
     RECT  2.16 36.315 20.412 36.585 ;
     RECT  119.34 36.315 140.4 36.585 ;
     RECT  2.16 36.855 20.412 37.125 ;
     RECT  119.34 36.855 140.4 37.125 ;
     RECT  2.16 37.395 20.412 37.665 ;
     RECT  119.34 37.395 140.4 37.665 ;
     RECT  2.16 37.935 20.412 38.205 ;
     RECT  119.34 37.935 140.4 38.205 ;
     RECT  2.16 38.475 20.412 38.745 ;
     RECT  119.34 38.475 140.4 38.745 ;
     RECT  2.16 39.015 20.412 39.285 ;
     RECT  119.34 39.015 140.4 39.285 ;
     RECT  2.16 39.555 20.412 39.825 ;
     RECT  119.34 39.555 140.4 39.825 ;
     RECT  2.16 40.095 20.412 40.365 ;
     RECT  119.34 40.095 140.4 40.365 ;
     RECT  2.16 40.635 20.412 40.905 ;
     RECT  119.34 40.635 140.4 40.905 ;
     RECT  2.16 41.175 20.412 41.445 ;
     RECT  119.34 41.175 140.4 41.445 ;
     RECT  2.16 41.715 20.412 41.985 ;
     RECT  119.34 41.715 140.4 41.985 ;
     RECT  2.16 42.255 20.412 42.525 ;
     RECT  119.34 42.255 140.4 42.525 ;
     RECT  2.16 42.795 20.412 43.065 ;
     RECT  119.34 42.795 140.4 43.065 ;
     RECT  2.16 43.335 20.412 43.605 ;
     RECT  119.34 43.335 140.4 43.605 ;
     RECT  2.16 43.875 20.412 44.145 ;
     RECT  119.34 43.875 140.4 44.145 ;
     RECT  2.16 44.415 20.412 44.685 ;
     RECT  119.34 44.415 140.4 44.685 ;
     RECT  2.16 44.955 20.412 45.225 ;
     RECT  119.34 44.955 140.4 45.225 ;
     RECT  2.16 45.495 20.412 45.765 ;
     RECT  119.34 45.495 140.4 45.765 ;
     RECT  2.16 46.035 20.412 46.305 ;
     RECT  119.34 46.035 140.4 46.305 ;
     RECT  2.16 46.575 20.412 46.845 ;
     RECT  119.34 46.575 140.4 46.845 ;
     RECT  2.16 47.115 20.412 47.385 ;
     RECT  119.34 47.115 140.4 47.385 ;
     RECT  2.16 47.655 20.412 47.925 ;
     RECT  119.34 47.655 140.4 47.925 ;
     RECT  2.16 48.195 20.412 48.465 ;
     RECT  119.34 48.195 140.4 48.465 ;
     RECT  2.16 48.735 20.412 49.005 ;
     RECT  119.34 48.735 140.4 49.005 ;
     RECT  2.16 49.275 20.412 49.545 ;
     RECT  119.34 49.275 140.4 49.545 ;
     RECT  2.16 49.815 20.412 50.085 ;
     RECT  119.34 49.815 140.4 50.085 ;
     RECT  2.16 50.355 20.412 50.625 ;
     RECT  119.34 50.355 140.4 50.625 ;
     RECT  2.16 50.895 20.412 51.165 ;
     RECT  119.34 50.895 140.4 51.165 ;
     RECT  2.16 51.435 20.412 51.705 ;
     RECT  119.34 51.435 140.4 51.705 ;
     RECT  2.16 51.975 20.412 52.245 ;
     RECT  119.34 51.975 140.4 52.245 ;
     RECT  2.16 52.515 20.412 52.785 ;
     RECT  119.34 52.515 140.4 52.785 ;
     RECT  2.16 53.055 20.412 53.325 ;
     RECT  119.34 53.055 140.4 53.325 ;
     RECT  2.16 53.595 20.412 53.865 ;
     RECT  119.34 53.595 140.4 53.865 ;
     RECT  2.16 54.135 20.412 54.405 ;
     RECT  119.34 54.135 140.4 54.405 ;
     RECT  2.16 54.675 20.412 54.945 ;
     RECT  119.34 54.675 140.4 54.945 ;
     RECT  2.16 55.215 20.412 55.485 ;
     RECT  119.34 55.215 140.4 55.485 ;
     RECT  2.16 55.755 20.412 56.025 ;
     RECT  119.34 55.755 140.4 56.025 ;
     RECT  2.16 56.295 20.412 56.565 ;
     RECT  119.34 56.295 140.4 56.565 ;
     RECT  2.16 56.835 20.412 57.105 ;
     RECT  119.34 56.835 140.4 57.105 ;
     RECT  2.16 57.375 20.412 57.645 ;
     RECT  119.34 57.375 140.4 57.645 ;
     RECT  2.16 57.915 20.412 58.185 ;
     RECT  119.34 57.915 140.4 58.185 ;
     RECT  2.16 58.455 20.412 58.725 ;
     RECT  119.34 58.455 140.4 58.725 ;
     RECT  2.16 58.995 20.412 59.265 ;
     RECT  119.34 58.995 140.4 59.265 ;
     RECT  2.16 59.535 20.412 59.805 ;
     RECT  119.34 59.535 140.4 59.805 ;
     RECT  2.16 60.075 20.412 60.345 ;
     RECT  119.34 60.075 140.4 60.345 ;
     RECT  2.16 60.615 20.412 60.885 ;
     RECT  119.34 60.615 140.4 60.885 ;
     RECT  2.16 61.155 20.412 61.425 ;
     RECT  119.34 61.155 140.4 61.425 ;
     RECT  2.16 61.695 20.412 61.965 ;
     RECT  119.34 61.695 140.4 61.965 ;
     RECT  2.16 62.235 20.412 62.505 ;
     RECT  119.34 62.235 140.4 62.505 ;
     RECT  2.16 62.775 20.412 63.045 ;
     RECT  119.34 62.775 140.4 63.045 ;
     RECT  2.16 63.315 20.412 63.585 ;
     RECT  119.34 63.315 140.4 63.585 ;
     RECT  2.16 63.855 20.412 64.125 ;
     RECT  119.34 63.855 140.4 64.125 ;
     RECT  2.16 64.395 20.412 64.665 ;
     RECT  119.34 64.395 140.4 64.665 ;
     RECT  2.16 64.935 20.412 65.205 ;
     RECT  119.34 64.935 140.4 65.205 ;
     RECT  2.16 65.475 20.412 65.61 ;
     RECT  119.34 65.475 140.4 65.61 ;
     RECT  2.16 65.61 140.4 65.745 ;
     RECT  2.16 66.015 140.4 66.285 ;
     RECT  2.16 66.555 140.4 66.825 ;
     RECT  2.16 67.095 140.4 67.365 ;
     RECT  2.16 67.635 140.4 67.905 ;
     RECT  2.16 68.175 140.4 68.445 ;
     RECT  2.16 68.715 140.4 68.985 ;
     RECT  2.16 69.255 140.4 69.525 ;
     RECT  2.16 69.795 140.4 70.065 ;
     RECT  2.16 70.335 140.4 70.605 ;
     RECT  2.16 70.875 140.4 71.145 ;
     RECT  2.16 71.415 140.4 71.685 ;
     RECT  2.16 71.955 140.4 72.225 ;
     RECT  2.16 72.495 140.4 72.765 ;
     RECT  2.16 73.035 140.4 73.305 ;
     RECT  2.16 73.575 140.4 73.845 ;
     RECT  2.16 74.115 140.4 74.385 ;
     RECT  2.16 74.655 140.4 74.925 ;
     RECT  2.16 75.195 140.4 75.465 ;
     RECT  2.16 75.735 140.4 76.005 ;
     RECT  2.16 76.275 140.4 76.545 ;
     RECT  2.16 76.815 140.4 77.085 ;
     RECT  2.16 77.355 140.4 77.625 ;
     RECT  2.16 77.895 140.4 78.165 ;
     RECT  2.16 78.435 140.4 78.705 ;
     RECT  2.16 78.975 140.4 79.245 ;
     RECT  2.16 79.515 140.4 79.785 ;
     RECT  2.16 80.055 140.4 80.325 ;
     RECT  2.16 80.595 140.4 80.865 ;
     RECT  2.16 81.135 140.4 81.405 ;
     RECT  2.16 81.675 140.4 81.945 ;
     RECT  2.16 82.215 140.4 82.485 ;
     RECT  2.16 82.755 140.4 83.025 ;
     RECT  2.16 83.295 140.4 83.565 ;
     RECT  2.16 83.835 140.4 84.105 ;
    LAYER M1 ;
     RECT  2.16 2.151 140.4 20.259 ;
     RECT  22.464 22.464 117.288 63.528 ;
     RECT  2.16 20.259 20.412 65.601 ;
     RECT  119.34 20.259 140.4 65.601 ;
     RECT  2.16 65.601 140.4 84.249 ;
    LAYER M2 ;
     RECT  0.211 37.17 0.247 39.24 ;
     RECT  0.211 40.374 0.247 42.75 ;
     RECT  0.211 32.436 0.319 33.876 ;
     RECT  0.211 35.046 0.319 35.604 ;
     RECT  0.247 37.17 0.319 43.02 ;
     RECT  0.355 25.452 0.391 25.47 ;
     RECT  0.319 32.436 0.823 43.02 ;
     RECT  0.319 66.636 0.823 66.654 ;
     RECT  0.355 55.926 0.859 55.944 ;
     RECT  0.283 62.55 0.967 62.568 ;
     RECT  0.967 62.514 1.003 62.568 ;
     RECT  0.823 32.346 1.147 43.02 ;
     RECT  1.111 50.976 1.363 50.994 ;
     RECT  1.471 61.704 1.507 61.722 ;
     RECT  1.147 51.912 1.543 51.93 ;
     RECT  1.363 48.906 1.615 48.924 ;
     RECT  1.363 50.256 1.615 50.994 ;
     RECT  1.003 62.478 1.615 62.568 ;
     RECT  1.147 32.346 1.723 43.29 ;
     RECT  0.211 44.892 2.083 44.91 ;
     RECT  1.543 51.912 2.119 52.344 ;
     RECT  0.859 55.926 2.119 56.088 ;
     RECT  0.535 15.03 2.16 15.048 ;
     RECT  0.391 25.452 2.16 26.154 ;
     RECT  1.723 31.806 2.16 43.668 ;
     RECT  2.083 44.892 2.16 45.252 ;
     RECT  1.615 48.906 2.16 48.996 ;
     RECT  1.615 50.166 2.16 50.994 ;
     RECT  2.119 51.912 2.16 53.046 ;
     RECT  2.119 55.926 2.16 56.556 ;
     RECT  2.155 59.976 2.16 59.994 ;
     RECT  1.507 61.506 2.16 61.722 ;
     RECT  1.615 62.478 2.16 62.604 ;
     RECT  1.687 65.016 2.16 65.034 ;
     RECT  0.823 66.366 2.16 66.654 ;
     RECT  2.16 2.151 15.223 84.249 ;
     RECT  9.103 85.194 15.223 85.212 ;
     RECT  15.223 2.151 16.339 85.212 ;
     RECT  16.339 2.151 19.795 85.284 ;
     RECT  19.795 2.151 20.412 85.329 ;
     RECT  20.412 23.976 20.435 33.804 ;
     RECT  20.435 23.976 20.471 24.894 ;
     RECT  20.435 25.866 20.471 33.804 ;
     RECT  20.412 57.348 20.515 85.329 ;
     RECT  20.412 38.25 20.543 38.538 ;
     RECT  20.412 45.504 20.543 54.324 ;
     RECT  20.412 55.26 20.543 56.592 ;
     RECT  20.471 25.866 20.579 30.564 ;
     RECT  20.543 48.816 20.579 54.324 ;
     RECT  20.515 57.348 20.579 85.518 ;
     RECT  20.412 41.526 20.759 43.362 ;
     RECT  20.579 57.348 20.759 58.14 ;
     RECT  20.579 29.07 20.795 30.564 ;
     RECT  20.412 39.528 20.795 39.924 ;
     RECT  20.579 59.274 20.795 85.518 ;
     RECT  20.471 23.976 20.867 24.228 ;
     RECT  20.795 60.966 20.875 85.518 ;
     RECT  20.875 60.966 20.911 86.256 ;
     RECT  20.911 60.966 20.939 86.292 ;
     RECT  20.759 57.348 21.011 57.366 ;
     RECT  20.579 25.866 21.083 28.206 ;
     RECT  20.759 42.066 21.083 43.362 ;
     RECT  20.412 2.151 21.091 23.076 ;
     RECT  20.579 51.174 21.119 54.324 ;
     RECT  20.412 44.226 21.155 44.748 ;
     RECT  20.795 29.07 21.191 29.088 ;
     RECT  20.543 38.286 21.199 38.538 ;
     RECT  21.155 44.73 21.199 44.748 ;
     RECT  20.543 45.504 21.199 48.024 ;
     RECT  21.119 51.174 21.263 53.586 ;
     RECT  20.867 23.976 21.299 23.994 ;
     RECT  21.199 56.961 21.299 56.979 ;
     RECT  20.795 59.274 21.299 59.832 ;
     RECT  20.795 30.456 21.307 30.564 ;
     RECT  20.471 31.896 21.307 33.804 ;
     RECT  21.091 2.034 21.343 23.076 ;
     RECT  20.412 34.596 21.407 37.044 ;
     RECT  20.939 60.966 21.407 85.374 ;
     RECT  21.083 25.866 21.443 26.388 ;
     RECT  21.083 42.066 21.443 43.29 ;
     RECT  21.407 61.704 21.443 85.374 ;
     RECT  21.307 31.626 21.451 33.804 ;
     RECT  21.307 30.456 21.479 30.636 ;
     RECT  21.451 31.626 21.479 34.11 ;
     RECT  21.199 44.73 21.479 48.024 ;
     RECT  20.543 55.26 21.479 56.124 ;
     RECT  21.443 42.066 21.515 43.164 ;
     RECT  21.299 59.814 21.515 59.832 ;
     RECT  21.443 62.316 21.515 85.374 ;
     RECT  21.083 27.216 21.523 28.206 ;
     RECT  21.479 55.26 21.523 55.278 ;
     RECT  21.479 31.896 21.551 34.11 ;
     RECT  20.579 48.816 21.551 50.382 ;
     RECT  21.443 26.37 21.587 26.388 ;
     RECT  21.407 35.28 21.587 37.044 ;
     RECT  21.479 44.73 21.623 47.304 ;
     RECT  21.479 56.034 21.623 56.124 ;
     RECT  21.523 25.101 21.659 25.119 ;
     RECT  21.523 27.216 21.659 28.278 ;
     RECT  21.551 31.896 21.659 33.408 ;
     RECT  21.199 38.286 21.659 38.934 ;
     RECT  20.795 39.87 21.659 39.924 ;
     RECT  21.515 43.11 21.659 43.164 ;
     RECT  21.623 46.62 21.659 47.304 ;
     RECT  21.551 48.816 21.659 49.194 ;
     RECT  21.263 51.606 21.659 53.586 ;
     RECT  21.659 31.896 21.695 32.724 ;
     RECT  21.551 50.364 21.695 50.382 ;
     RECT  21.523 54.684 21.695 55.278 ;
     RECT  21.523 60.426 21.695 60.444 ;
     RECT  21.343 1.998 21.847 23.076 ;
     RECT  21.847 1.962 21.919 23.076 ;
     RECT  21.523 29.772 21.955 29.79 ;
     RECT  21.515 42.066 22.027 42.174 ;
     RECT  22.027 42.03 22.099 42.174 ;
     RECT  21.955 29.07 22.135 29.79 ;
     RECT  21.919 1.26 22.464 23.076 ;
     RECT  21.659 27.216 22.464 28.044 ;
     RECT  22.135 28.998 22.464 29.79 ;
     RECT  21.695 32.004 22.464 32.724 ;
     RECT  21.587 35.28 22.464 36.81 ;
     RECT  21.659 38.754 22.464 38.844 ;
     RECT  21.659 39.87 22.464 39.888 ;
     RECT  22.099 41.346 22.464 42.174 ;
     RECT  21.659 43.11 22.464 43.128 ;
     RECT  21.623 44.73 22.464 45.639 ;
     RECT  21.659 47.286 22.464 47.304 ;
     RECT  21.659 48.816 22.464 49.032 ;
     RECT  21.659 51.606 22.464 51.624 ;
     RECT  21.659 52.416 22.464 53.586 ;
     RECT  21.695 54.684 22.464 54.702 ;
     RECT  21.623 56.034 22.464 56.052 ;
     RECT  20.759 58.122 22.464 58.14 ;
     RECT  21.515 62.712 22.464 85.374 ;
     RECT  22.464 1.26 22.531 85.374 ;
     RECT  22.531 0.846 26.023 85.374 ;
     RECT  26.023 0.216 26.059 85.374 ;
     RECT  26.059 0.144 26.159 85.374 ;
     RECT  26.159 0.216 26.231 85.374 ;
     RECT  20.939 86.238 26.779 86.292 ;
     RECT  26.231 0.846 26.851 85.374 ;
     RECT  26.779 86.166 26.879 86.292 ;
     RECT  26.851 0.846 26.951 85.41 ;
     RECT  26.879 86.202 27.419 86.292 ;
     RECT  26.951 0.846 27.715 85.374 ;
     RECT  27.419 86.202 27.815 86.22 ;
     RECT  27.715 0.486 27.931 85.374 ;
     RECT  27.931 0.144 28.543 85.374 ;
     RECT  28.543 0.144 28.679 85.446 ;
     RECT  28.679 0.144 28.895 85.374 ;
     RECT  28.895 0.486 29.659 85.374 ;
     RECT  30.523 86.238 30.559 86.256 ;
     RECT  30.559 86.238 30.659 86.328 ;
     RECT  29.659 0.144 30.767 85.374 ;
     RECT  30.767 0.486 31.999 85.374 ;
     RECT  31.999 0.144 32.287 85.518 ;
     RECT  32.287 0.144 32.647 85.599 ;
     RECT  32.647 0.144 32.783 86.328 ;
     RECT  32.783 0.144 32.855 85.599 ;
     RECT  32.855 0.144 33.395 85.518 ;
     RECT  33.395 0.144 33.467 64.422 ;
     RECT  33.467 0.144 33.503 64.152 ;
     RECT  33.503 0.216 33.575 64.152 ;
     RECT  33.395 65.25 33.979 85.518 ;
     RECT  33.943 86.31 33.979 86.328 ;
     RECT  33.979 65.25 34.079 86.328 ;
     RECT  33.575 0.486 34.555 64.152 ;
     RECT  34.079 65.25 35.015 85.599 ;
     RECT  34.555 0.144 35.627 64.152 ;
     RECT  35.627 0.486 36.571 64.152 ;
     RECT  35.015 65.25 36.599 85.248 ;
     RECT  36.571 0.261 37.291 64.152 ;
     RECT  37.291 0.144 37.607 64.152 ;
     RECT  37.607 0.261 38.695 64.152 ;
     RECT  38.695 0.144 39.191 64.152 ;
     RECT  39.415 86.31 39.451 86.328 ;
     RECT  39.451 86.238 39.551 86.328 ;
     RECT  36.599 65.25 39.767 84.708 ;
     RECT  39.191 0.261 40.171 64.152 ;
     RECT  40.171 0.144 41.863 64.152 ;
     RECT  39.767 65.25 41.927 84.636 ;
     RECT  41.863 0.108 42.079 64.152 ;
     RECT  42.079 0.072 42.151 64.152 ;
     RECT  42.151 0.036 44.123 64.152 ;
     RECT  41.927 65.25 46.759 84.249 ;
     RECT  46.759 65.25 48.407 84.294 ;
     RECT  48.407 65.25 55.391 84.249 ;
     RECT  44.123 0.036 66.371 63.528 ;
     RECT  66.371 0.144 67.631 63.528 ;
     RECT  67.631 0.531 70.987 63.528 ;
     RECT  70.987 0.144 71.087 63.528 ;
     RECT  71.087 0.531 71.483 63.528 ;
     RECT  71.483 0.846 72.095 63.528 ;
     RECT  72.095 1.071 72.527 63.528 ;
     RECT  72.527 1.422 73.823 63.528 ;
     RECT  73.823 1.728 74.291 63.528 ;
     RECT  74.291 1.836 77.207 63.528 ;
     RECT  77.207 1.836 78.835 21.114 ;
     RECT  77.207 21.942 78.835 63.528 ;
     RECT  78.835 1.836 83.831 63.528 ;
     RECT  83.831 2.151 117.288 63.528 ;
     RECT  117.288 2.151 117.563 22.104 ;
     RECT  117.288 37.332 118.039 62.874 ;
     RECT  117.288 26.766 118.247 26.784 ;
     RECT  117.288 33.426 118.543 35.226 ;
     RECT  117.288 36.018 118.543 36.27 ;
     RECT  118.039 37.332 118.579 63 ;
     RECT  118.543 33.426 119.119 36.27 ;
     RECT  118.579 37.026 119.119 63 ;
     RECT  117.563 2.151 119.34 22.068 ;
     RECT  118.543 25.101 119.34 25.119 ;
     RECT  119.119 33.426 119.34 63 ;
     RECT  55.391 65.601 119.34 84.249 ;
     RECT  119.34 2.151 140.4 84.249 ;
    LAYER M3 ;
     RECT  42.156 0.031 42.174 0.067 ;
     RECT  42.084 0.067 42.174 0.103 ;
     RECT  62.064 0.067 62.082 0.103 ;
     RECT  66.348 0.031 66.366 0.103 ;
     RECT  41.868 0.103 42.174 0.108 ;
     RECT  60.516 0.103 60.534 0.108 ;
     RECT  61.524 0.103 62.082 0.108 ;
     RECT  66.132 0.103 66.366 0.108 ;
     RECT  24.48 0.108 62.082 0.187 ;
     RECT  70.488 0.108 71.082 0.187 ;
     RECT  24.372 0.187 62.082 0.221 ;
     RECT  23.616 0.427 23.634 0.523 ;
     RECT  24.372 0.221 61.218 0.523 ;
     RECT  70.344 0.187 71.082 0.526 ;
     RECT  23.616 0.523 61.218 0.571 ;
     RECT  62.064 0.221 62.082 0.571 ;
     RECT  64.548 0.283 64.566 0.763 ;
     RECT  22.788 0.811 22.806 0.841 ;
     RECT  70.344 0.526 71.478 0.841 ;
     RECT  64.548 0.763 64.854 0.907 ;
     RECT  63.684 0.877 63.702 0.913 ;
     RECT  64.548 0.907 65.394 0.955 ;
     RECT  66.132 0.108 67.842 0.955 ;
     RECT  70.344 0.841 72.09 1.066 ;
     RECT  22.536 0.841 22.806 1.147 ;
     RECT  23.58 0.571 61.218 1.147 ;
     RECT  22.536 1.147 61.218 1.255 ;
     RECT  70.344 1.066 72.522 1.387 ;
     RECT  64.548 0.955 67.842 1.435 ;
     RECT  21.924 1.255 61.218 1.453 ;
     RECT  62.064 0.571 62.622 1.453 ;
     RECT  21.924 1.453 62.622 1.483 ;
     RECT  63.468 0.913 63.702 1.483 ;
     RECT  69.804 1.387 72.522 1.489 ;
     RECT  21.924 1.483 63.702 1.723 ;
     RECT  64.548 1.435 68.094 1.723 ;
     RECT  73.8 1.417 73.818 1.723 ;
     RECT  69.804 1.489 72.954 1.921 ;
     RECT  73.8 1.723 74.286 1.921 ;
     RECT  21.924 1.723 68.094 1.957 ;
     RECT  21.852 1.957 68.094 1.993 ;
     RECT  21.348 1.993 68.094 2.029 ;
     RECT  69.804 1.921 74.286 2.065 ;
     RECT  18.792 2.059 18.81 2.143 ;
     RECT  83.808 1.831 83.826 2.143 ;
     RECT  69.624 2.065 74.286 2.191 ;
     RECT  21.096 2.029 68.346 2.263 ;
     RECT  83.415 2.143 83.826 2.335 ;
     RECT  69.624 2.191 74.322 2.347 ;
     RECT  69.624 2.347 74.538 2.371 ;
     RECT  2.415 2.143 2.505 2.413 ;
     RECT  7.815 2.143 7.905 2.413 ;
     RECT  13.215 2.143 13.305 2.413 ;
     RECT  18.615 2.143 18.81 2.413 ;
     RECT  78.015 2.143 78.105 2.413 ;
     RECT  88.815 2.143 88.905 2.413 ;
     RECT  94.215 2.143 94.305 2.413 ;
     RECT  99.615 2.143 99.705 2.413 ;
     RECT  105.015 2.143 105.105 2.413 ;
     RECT  110.415 2.143 110.505 2.413 ;
     RECT  115.815 2.143 115.905 2.413 ;
     RECT  121.215 2.143 121.305 2.413 ;
     RECT  126.615 2.143 126.705 2.413 ;
     RECT  132.015 2.143 132.105 2.413 ;
     RECT  137.415 2.143 137.505 2.413 ;
     RECT  21.096 2.263 68.85 2.443 ;
     RECT  69.624 2.371 74.754 2.443 ;
     RECT  18.615 2.413 18.897 2.461 ;
     RECT  83.232 2.335 83.826 2.605 ;
     RECT  18.615 2.461 18.954 2.641 ;
     RECT  78.015 2.413 78.297 2.731 ;
     RECT  88.815 2.413 89.097 2.731 ;
     RECT  92.916 2.569 92.934 2.731 ;
     RECT  94.215 2.413 94.497 2.731 ;
     RECT  88.704 2.731 89.097 2.803 ;
     RECT  87.444 2.641 87.462 2.911 ;
     RECT  18.072 2.641 18.954 2.923 ;
     RECT  81.288 2.263 81.306 3.001 ;
     RECT  82.08 2.839 82.098 3.001 ;
     RECT  18.072 2.923 18.99 3.019 ;
     RECT  87.012 2.911 87.462 3.019 ;
     RECT  77.904 2.731 78.297 3.037 ;
     RECT  87.012 3.019 87.822 3.073 ;
     RECT  81.288 3.001 82.098 3.145 ;
     RECT  83.232 2.605 84.258 3.145 ;
     RECT  21.096 2.443 74.754 3.181 ;
     RECT  77.904 3.037 78.678 3.181 ;
     RECT  119.52 3.145 119.538 3.181 ;
     RECT  18.072 3.019 19.026 3.197 ;
     RECT  21.06 3.181 74.754 3.298 ;
     RECT  79.524 3.073 79.542 3.299 ;
     RECT  86.652 3.073 87.822 3.299 ;
     RECT  88.704 2.803 89.514 3.299 ;
     RECT  77.796 3.181 78.678 3.307 ;
     RECT  121.215 2.413 121.497 3.343 ;
     RECT  79.452 3.307 79.47 3.344 ;
     RECT  21.06 3.298 74.79 3.355 ;
     RECT  81.288 3.145 84.258 3.379 ;
     RECT  85.176 3.181 85.194 3.379 ;
     RECT  88.704 3.299 89.097 3.379 ;
     RECT  90.468 3.073 90.486 3.379 ;
     RECT  21.06 3.355 75.186 3.407 ;
     RECT  81.288 3.379 85.194 3.407 ;
     RECT  76.968 2.461 76.986 3.415 ;
     RECT  77.76 3.307 78.678 3.415 ;
     RECT  119.484 3.181 119.538 3.415 ;
     RECT  21.06 3.407 73.746 3.443 ;
     RECT  80.388 2.767 80.406 3.451 ;
     RECT  81.288 3.407 84.654 3.451 ;
     RECT  13.215 2.413 13.497 3.547 ;
     RECT  21.06 3.443 71.262 3.569 ;
     RECT  80.388 3.451 84.654 3.569 ;
     RECT  13.215 3.547 13.59 3.613 ;
     RECT  77.724 3.415 78.678 3.613 ;
     RECT  74.52 3.407 75.186 3.641 ;
     RECT  80.388 3.569 81.414 3.643 ;
     RECT  74.556 3.641 75.186 3.677 ;
     RECT  80.352 3.643 81.414 3.677 ;
     RECT  114.588 3.547 114.606 3.677 ;
     RECT  86.652 3.299 87.462 3.685 ;
     RECT  74.592 3.677 75.186 3.713 ;
     RECT  80.352 3.677 81.378 3.713 ;
     RECT  13.215 3.613 13.842 3.721 ;
     RECT  21.06 3.569 64.782 3.721 ;
     RECT  76.608 3.415 76.986 3.721 ;
     RECT  92.916 2.731 94.497 3.721 ;
     RECT  72.504 3.443 73.746 3.749 ;
     RECT  80.352 3.713 81.27 3.811 ;
     RECT  20.808 3.721 64.782 3.839 ;
     RECT  76.572 3.721 76.986 3.839 ;
     RECT  77.724 3.613 79.002 3.839 ;
     RECT  85.968 3.685 87.462 3.839 ;
     RECT  92.916 3.721 94.59 3.839 ;
     RECT  76.572 3.839 76.59 3.883 ;
     RECT  72.504 3.749 73.422 3.911 ;
     RECT  119.196 3.415 119.538 3.919 ;
     RECT  120.636 3.343 121.497 3.919 ;
     RECT  74.664 3.713 75.186 3.955 ;
     RECT  76.428 3.883 76.59 3.955 ;
     RECT  82.296 3.569 84.654 3.983 ;
     RECT  90 3.379 90.486 3.991 ;
     RECT  77.724 3.839 78.678 4.109 ;
     RECT  86.508 3.839 87.462 4.109 ;
     RECT  118.404 3.109 118.422 4.117 ;
     RECT  119.196 3.919 121.497 4.123 ;
     RECT  82.656 3.983 84.654 4.205 ;
     RECT  85.5 4.153 85.518 4.205 ;
     RECT  77.724 4.109 78.57 4.261 ;
     RECT  80.244 3.811 81.27 4.261 ;
     RECT  90 3.991 90.846 4.289 ;
     RECT  21.096 3.839 64.782 4.351 ;
     RECT  65.628 3.569 71.262 4.351 ;
     RECT  74.664 3.955 75.582 4.415 ;
     RECT  21.096 4.351 71.262 4.423 ;
     RECT  72.504 3.911 73.314 4.423 ;
     RECT  118.08 4.117 118.422 4.423 ;
     RECT  119.196 4.123 121.554 4.423 ;
     RECT  77.616 4.261 78.57 4.451 ;
     RECT  82.692 4.205 84.654 4.487 ;
     RECT  90.828 4.289 90.846 4.531 ;
     RECT  18.072 3.197 18.954 4.559 ;
     RECT  77.688 4.451 78.57 4.559 ;
     RECT  21.096 4.423 73.314 4.793 ;
     RECT  21.096 4.793 73.17 4.801 ;
     RECT  86.508 4.109 87.282 4.919 ;
     RECT  82.764 4.487 84.654 4.991 ;
     RECT  7.815 2.413 8.097 4.999 ;
     RECT  87.264 4.919 87.282 5.071 ;
     RECT  88.2 3.379 89.097 5.071 ;
     RECT  74.844 4.415 75.582 5.189 ;
     RECT  77.832 4.559 78.57 5.225 ;
     RECT  13.215 3.721 13.95 5.233 ;
     RECT  14.724 4.531 14.742 5.233 ;
     RECT  76.356 3.955 76.59 5.233 ;
     RECT  78.015 5.225 78.57 5.341 ;
     RECT  79.596 4.261 81.27 5.341 ;
     RECT  13.215 5.233 14.742 5.431 ;
     RECT  15.912 4.963 15.93 5.431 ;
     RECT  93.492 3.839 94.59 5.539 ;
     RECT  18.072 4.559 18.918 5.605 ;
     RECT  20.592 4.801 73.17 5.737 ;
     RECT  76.356 5.233 76.806 5.809 ;
     RECT  114.588 4.963 114.606 5.837 ;
     RECT  20.592 5.737 73.206 5.845 ;
     RECT  18.072 5.605 18.99 5.851 ;
     RECT  78.015 5.341 81.27 5.873 ;
     RECT  82.764 4.991 84.15 5.971 ;
     RECT  11.268 5.971 11.286 6.007 ;
     RECT  118.08 4.423 121.554 6.115 ;
     RECT  20.592 5.845 73.278 6.143 ;
     RECT  74.952 5.189 75.582 6.151 ;
     RECT  76.356 5.809 77.238 6.151 ;
     RECT  82.656 5.971 84.15 6.151 ;
     RECT  11.232 6.007 11.286 6.241 ;
     RECT  20.592 6.143 24.57 6.241 ;
     RECT  25.38 6.143 73.278 6.241 ;
     RECT  80.424 5.873 81.27 6.241 ;
     RECT  10.836 6.241 11.286 6.269 ;
     RECT  74.088 4.801 74.106 6.277 ;
     RECT  74.952 6.151 77.238 6.277 ;
     RECT  25.38 6.241 73.35 6.283 ;
     RECT  74.088 6.277 77.238 6.283 ;
     RECT  25.38 6.283 77.238 6.313 ;
     RECT  86.508 4.919 86.526 6.349 ;
     RECT  25.38 6.313 77.274 6.413 ;
     RECT  80.424 6.241 81.45 6.421 ;
     RECT  82.188 6.151 84.15 6.421 ;
     RECT  86.004 6.349 86.526 6.421 ;
     RECT  19.872 6.241 24.57 6.557 ;
     RECT  18.072 5.851 19.098 6.583 ;
     RECT  19.872 6.557 22.662 6.583 ;
     RECT  31.896 6.413 77.274 6.583 ;
     RECT  78.015 5.873 79.686 6.583 ;
     RECT  31.896 6.583 79.686 6.611 ;
     RECT  32.076 6.611 79.686 6.691 ;
     RECT  80.424 6.421 84.15 6.691 ;
     RECT  85.932 6.421 86.526 6.691 ;
     RECT  93.204 5.539 94.59 6.691 ;
     RECT  23.472 6.557 24.57 6.701 ;
     RECT  85.536 6.691 86.526 6.781 ;
     RECT  87.264 5.071 89.097 6.781 ;
     RECT  7.815 4.999 8.766 6.817 ;
     RECT  17.1 6.691 17.118 6.845 ;
     RECT  25.38 6.413 31.158 6.845 ;
     RECT  90 4.289 90.018 6.853 ;
     RECT  90.828 4.531 91.242 6.853 ;
     RECT  93.204 6.691 94.698 6.853 ;
     RECT  85.32 6.781 89.097 6.859 ;
     RECT  10.836 6.269 11.25 6.881 ;
     RECT  93.204 6.853 95.022 6.881 ;
     RECT  84.924 6.859 89.097 6.889 ;
     RECT  90 6.853 91.242 6.889 ;
     RECT  26.244 6.845 31.158 6.893 ;
     RECT  23.472 6.701 24.462 6.917 ;
     RECT  84.924 6.889 91.242 6.925 ;
     RECT  117.72 6.115 121.554 6.925 ;
     RECT  99.615 2.413 99.897 6.952 ;
     RECT  110.415 2.413 110.697 6.952 ;
     RECT  26.28 6.893 31.158 6.953 ;
     RECT  99.504 6.952 99.897 6.989 ;
     RECT  110.304 6.952 110.697 6.989 ;
     RECT  32.076 6.691 84.15 7.115 ;
     RECT  82.692 7.115 84.15 7.159 ;
     RECT  84.924 6.925 91.638 7.159 ;
     RECT  25.38 6.845 25.398 7.223 ;
     RECT  32.076 7.115 81.918 7.259 ;
     RECT  82.692 7.159 91.638 7.259 ;
     RECT  82.692 7.259 91.566 7.349 ;
     RECT  92.304 7.321 92.322 7.627 ;
     RECT  26.388 6.953 31.158 7.709 ;
     RECT  39.78 7.259 57.438 7.709 ;
     RECT  32.076 7.259 38.97 7.805 ;
     RECT  23.472 6.917 24.297 7.819 ;
     RECT  25.056 7.435 25.074 7.819 ;
     RECT  82.692 7.349 91.386 7.915 ;
     RECT  26.388 7.709 27.126 7.925 ;
     RECT  17.1 7.861 17.118 7.961 ;
     RECT  23.472 7.819 25.074 7.961 ;
     RECT  26.388 7.925 27.09 7.961 ;
     RECT  58.356 7.259 81.918 7.969 ;
     RECT  82.656 7.915 91.386 7.969 ;
     RECT  92.304 7.627 92.502 7.969 ;
     RECT  93.276 6.881 95.022 7.969 ;
     RECT  117.72 6.925 121.59 7.969 ;
     RECT  26.388 7.961 27.054 7.997 ;
     RECT  39.852 7.709 57.438 8.041 ;
     RECT  58.356 7.969 91.386 8.041 ;
     RECT  34.704 7.805 38.97 8.045 ;
     RECT  39.852 8.041 91.386 8.167 ;
     RECT  92.304 7.969 95.022 8.167 ;
     RECT  13.215 5.431 15.93 8.251 ;
     RECT  39.852 8.167 95.022 8.285 ;
     RECT  6.372 7.123 6.39 8.299 ;
     RECT  10.152 7.861 10.17 8.347 ;
     RECT  10.944 6.881 11.25 8.347 ;
     RECT  39.96 8.285 95.022 8.401 ;
     RECT  5.688 8.299 6.39 8.429 ;
     RECT  34.815 8.045 38.97 8.443 ;
     RECT  5.904 8.429 6.39 8.537 ;
     RECT  28.188 7.709 31.158 8.581 ;
     RECT  39.96 8.401 95.058 8.699 ;
     RECT  23.472 7.961 24.498 8.707 ;
     RECT  84.636 8.699 95.058 8.707 ;
     RECT  18.072 6.583 22.662 8.743 ;
     RECT  23.472 8.707 24.57 8.743 ;
     RECT  28.188 8.581 31.338 8.779 ;
     RECT  26.388 7.997 26.91 8.815 ;
     RECT  12.132 8.815 12.15 8.851 ;
     RECT  13.104 8.251 15.93 8.851 ;
     RECT  26.388 8.815 27.27 8.851 ;
     RECT  28.008 8.779 31.338 8.851 ;
     RECT  17.1 8.743 17.118 8.941 ;
     RECT  84.636 8.707 95.13 8.941 ;
     RECT  32.076 7.805 33.966 8.971 ;
     RECT  34.815 8.443 39.222 8.971 ;
     RECT  39.96 8.699 83.898 9.041 ;
     RECT  17.1 8.941 17.19 9.049 ;
     RECT  26.388 8.851 31.338 9.049 ;
     RECT  32.076 8.971 39.222 9.049 ;
     RECT  10.152 8.347 11.25 9.085 ;
     RECT  17.1 9.049 17.226 9.085 ;
     RECT  18.072 8.743 24.57 9.085 ;
     RECT  26.388 9.049 39.222 9.085 ;
     RECT  39.96 9.041 78.786 9.085 ;
     RECT  7.815 6.817 8.946 9.121 ;
     RECT  12.132 8.851 15.93 9.121 ;
     RECT  26.388 9.085 78.786 9.211 ;
     RECT  10.044 9.085 11.25 9.247 ;
     RECT  26.244 9.211 78.786 9.283 ;
     RECT  17.028 9.085 24.57 9.307 ;
     RECT  26.172 9.283 78.786 9.319 ;
     RECT  25.56 9.319 78.786 9.383 ;
     RECT  6.372 8.537 6.39 9.391 ;
     RECT  7.416 9.121 8.946 9.391 ;
     RECT  9.936 9.247 11.25 9.391 ;
     RECT  17.028 9.307 24.642 9.391 ;
     RECT  25.56 9.383 46.818 9.391 ;
     RECT  96.228 9.319 96.246 9.391 ;
     RECT  96.156 9.391 96.246 9.419 ;
     RECT  6.372 9.391 8.946 9.451 ;
     RECT  9.828 9.391 11.25 9.451 ;
     RECT  25.524 9.391 46.818 9.589 ;
     RECT  6.372 9.451 11.25 9.595 ;
     RECT  4.968 9.553 4.986 9.625 ;
     RECT  6.264 9.595 11.25 9.625 ;
     RECT  4.968 9.625 11.25 9.661 ;
     RECT  12.024 9.121 15.93 9.661 ;
     RECT  84.636 8.941 95.274 9.661 ;
     RECT  96.156 9.419 96.174 9.661 ;
     RECT  25.488 9.589 46.818 9.689 ;
     RECT  84.636 9.661 96.174 9.689 ;
     RECT  4.968 9.661 15.93 9.787 ;
     RECT  16.74 9.391 24.642 9.787 ;
     RECT  25.488 9.689 46.782 9.787 ;
     RECT  47.7 9.383 78.786 9.787 ;
     RECT  79.596 9.041 83.898 9.787 ;
     RECT  84.636 9.689 95.742 9.787 ;
     RECT  47.7 9.787 95.742 10.085 ;
     RECT  74.412 10.085 95.742 10.193 ;
     RECT  4.5 9.787 16.002 10.201 ;
     RECT  16.74 9.787 46.782 10.201 ;
     RECT  4.5 10.201 46.782 10.219 ;
     RECT  3.816 10.219 46.782 10.291 ;
     RECT  74.412 10.193 95.634 10.301 ;
     RECT  74.412 10.301 95.238 10.319 ;
     RECT  74.412 10.319 95.094 10.427 ;
     RECT  3.708 10.291 46.782 10.507 ;
     RECT  47.7 10.085 73.53 10.705 ;
     RECT  3.708 10.507 46.89 10.867 ;
     RECT  47.664 10.705 73.53 10.867 ;
     RECT  3.708 10.867 73.53 10.939 ;
     RECT  3.708 10.939 73.638 10.975 ;
     RECT  3.636 10.975 73.638 11.011 ;
     RECT  2.415 2.413 2.697 11.173 ;
     RECT  3.42 11.011 73.638 11.173 ;
     RECT  74.412 10.427 95.058 11.281 ;
     RECT  2.415 11.173 73.638 11.407 ;
     RECT  74.412 11.281 95.166 11.407 ;
     RECT  2.415 11.407 95.166 11.419 ;
     RECT  95.904 11.407 95.922 11.419 ;
     RECT  2.415 11.419 95.922 12.595 ;
     RECT  2.415 12.595 96.174 12.785 ;
     RECT  2.415 12.785 95.418 13.019 ;
     RECT  2.415 13.019 90.054 13.055 ;
     RECT  96.156 12.785 96.174 13.055 ;
     RECT  90.792 13.019 95.418 13.289 ;
     RECT  33.804 13.055 90.054 13.361 ;
     RECT  2.415 13.055 33.066 13.405 ;
     RECT  99.615 6.989 99.897 13.432 ;
     RECT  110.415 6.989 110.697 13.432 ;
     RECT  2.376 13.405 33.066 13.595 ;
     RECT  47.196 13.361 90.054 13.595 ;
     RECT  2.415 13.595 33.066 13.801 ;
     RECT  33.804 13.361 46.314 13.801 ;
     RECT  99.504 13.432 99.897 14.009 ;
     RECT  110.304 13.432 110.697 14.009 ;
     RECT  47.376 13.595 90.054 14.071 ;
     RECT  90.792 13.289 91.818 14.071 ;
     RECT  92.7 13.289 95.418 14.107 ;
     RECT  114.588 13.963 114.606 14.141 ;
     RECT  2.415 13.801 46.314 14.347 ;
     RECT  2.415 14.347 46.494 14.485 ;
     RECT  47.376 14.071 91.818 14.485 ;
     RECT  2.415 14.485 91.818 14.521 ;
     RECT  92.7 14.107 95.454 14.521 ;
     RECT  2.415 14.521 95.454 15.061 ;
     RECT  2.415 15.061 95.67 15.215 ;
     RECT  95.652 15.215 95.67 15.359 ;
     RECT  2.415 15.215 94.842 15.827 ;
     RECT  117.72 7.969 121.626 16.339 ;
     RECT  2.415 15.827 76.986 16.555 ;
     RECT  2.376 16.555 76.986 16.609 ;
     RECT  77.724 15.827 94.842 16.609 ;
     RECT  2.376 16.609 94.842 16.829 ;
     RECT  2.376 16.829 94.554 16.979 ;
     RECT  90.828 16.979 94.554 17.105 ;
     RECT  2.376 16.979 90.054 17.411 ;
     RECT  2.376 17.411 84.762 18.023 ;
     RECT  85.5 17.411 90.054 18.139 ;
     RECT  31.896 18.023 84.762 18.235 ;
     RECT  85.5 18.139 90.09 18.235 ;
     RECT  31.896 18.235 90.09 18.257 ;
     RECT  32.04 18.257 90.09 18.427 ;
     RECT  90.828 17.105 94.497 18.427 ;
     RECT  2.376 18.023 31.158 18.689 ;
     RECT  32.04 18.427 94.497 18.689 ;
     RECT  32.04 18.689 32.058 19.111 ;
     RECT  32.976 18.689 94.497 19.139 ;
     RECT  32.976 19.139 93.258 19.229 ;
     RECT  74.484 19.229 93.15 19.265 ;
     RECT  32.976 19.229 73.494 19.277 ;
     RECT  74.484 19.265 92.466 19.301 ;
     RECT  74.484 19.301 89.586 19.373 ;
     RECT  90.468 19.301 92.466 19.373 ;
     RECT  74.484 19.373 84.546 19.421 ;
     RECT  31.932 19.111 32.058 19.499 ;
     RECT  32.976 19.277 73.422 19.499 ;
     RECT  90.468 19.373 92.43 19.499 ;
     RECT  32.976 19.499 65.79 19.535 ;
     RECT  74.484 19.421 84.438 19.535 ;
     RECT  85.284 19.373 89.298 19.535 ;
     RECT  2.415 18.689 31.158 19.571 ;
     RECT  66.636 19.499 73.422 19.571 ;
     RECT  85.428 19.535 89.298 19.571 ;
     RECT  32.976 19.535 41.166 19.607 ;
     RECT  31.932 19.499 32.022 19.643 ;
     RECT  79.632 19.535 84.366 19.679 ;
     RECT  2.415 19.571 26.73 19.769 ;
     RECT  41.904 19.535 65.79 19.769 ;
     RECT  79.632 19.679 83.79 19.769 ;
     RECT  85.5 19.571 89.298 19.769 ;
     RECT  92.304 19.499 92.43 19.769 ;
     RECT  27.72 19.571 31.158 19.805 ;
     RECT  33.768 19.607 38.898 19.805 ;
     RECT  49.968 19.769 65.538 19.805 ;
     RECT  66.708 19.571 73.422 19.805 ;
     RECT  74.484 19.535 78.858 19.805 ;
     RECT  85.5 19.769 89.19 19.805 ;
     RECT  92.304 19.769 92.322 19.805 ;
     RECT  39.924 19.607 41.166 19.841 ;
     RECT  60.912 19.805 65.538 19.841 ;
     RECT  38.592 19.805 38.898 19.853 ;
     RECT  29.16 19.805 31.158 19.877 ;
     RECT  38.592 19.853 38.79 19.877 ;
     RECT  90.468 19.499 91.566 19.886 ;
     RECT  79.632 19.769 81.522 19.901 ;
     RECT  41.904 19.769 49.23 19.913 ;
     RECT  49.968 19.805 60.138 19.913 ;
     RECT  69.084 19.805 73.422 19.913 ;
     RECT  79.632 19.901 80.658 19.913 ;
     RECT  85.788 19.805 89.19 19.913 ;
     RECT  30.816 19.877 31.158 19.949 ;
     RECT  38.7 19.877 38.79 19.949 ;
     RECT  41.904 19.913 47.79 19.949 ;
     RECT  49.968 19.913 51.894 19.949 ;
     RECT  60.912 19.841 65.25 19.949 ;
     RECT  79.632 19.913 80.622 19.949 ;
     RECT  81.504 19.901 81.522 19.949 ;
     RECT  33.768 19.805 37.494 19.997 ;
     RECT  41.904 19.949 47.718 19.997 ;
     RECT  74.664 19.805 78.858 19.997 ;
     RECT  90.468 19.886 91.53 19.997 ;
     RECT  94.215 19.139 94.497 19.997 ;
     RECT  99.615 14.009 99.897 19.997 ;
     RECT  105.015 2.413 105.297 19.997 ;
     RECT  110.415 14.009 110.697 19.997 ;
     RECT  115.815 2.413 116.097 19.997 ;
     RECT  31.14 19.949 31.158 20.011 ;
     RECT  31.14 20.011 31.626 20.039 ;
     RECT  34.956 19.997 37.494 20.039 ;
     RECT  40.068 19.841 41.166 20.039 ;
     RECT  41.904 19.997 44.946 20.039 ;
     RECT  45.807 19.997 47.718 20.039 ;
     RECT  48.528 19.913 49.05 20.039 ;
     RECT  66.708 19.805 68.346 20.039 ;
     RECT  69.552 19.913 73.422 20.039 ;
     RECT  79.632 19.949 80.37 20.039 ;
     RECT  90.468 19.997 91.314 20.039 ;
     RECT  32.976 19.607 32.994 20.075 ;
     RECT  40.068 20.039 41.094 20.075 ;
     RECT  48.528 20.039 48.978 20.075 ;
     RECT  52.74 19.913 60.138 20.075 ;
     RECT  60.912 19.949 64.998 20.075 ;
     RECT  69.552 20.039 71.586 20.075 ;
     RECT  79.632 20.039 80.154 20.075 ;
     RECT  90.468 20.039 90.882 20.075 ;
     RECT  69.552 20.075 71.298 20.093 ;
     RECT  34.956 20.039 36.558 20.111 ;
     RECT  37.476 20.039 37.494 20.111 ;
     RECT  41.904 20.039 44.01 20.141 ;
     RECT  27.72 19.805 28.386 20.147 ;
     RECT  41.904 20.141 43.398 20.147 ;
     RECT  45.807 20.039 47.574 20.147 ;
     RECT  45.807 20.147 47.034 20.183 ;
     RECT  52.74 20.075 55.566 20.183 ;
     RECT  86.112 19.913 89.097 20.183 ;
     RECT  2.415 19.769 24.297 20.189 ;
     RECT  61.848 20.075 64.998 20.219 ;
     RECT  74.664 19.997 77.31 20.219 ;
     RECT  5.796 20.189 24.297 20.267 ;
     RECT  29.16 19.877 30.006 20.267 ;
     RECT  35.007 20.111 36.558 20.267 ;
     RECT  40.407 20.075 40.77 20.267 ;
     RECT  45.807 20.183 45.897 20.267 ;
     RECT  49.968 19.949 51.462 20.267 ;
     RECT  61.848 20.219 63.63 20.267 ;
     RECT  66.708 20.039 67.986 20.267 ;
     RECT  72.807 20.039 73.422 20.267 ;
     RECT  78.207 19.997 78.858 20.267 ;
     RECT  82.296 19.769 83.697 20.267 ;
     RECT  88.488 20.183 89.097 20.267 ;
     RECT  94.407 19.997 94.497 20.267 ;
     RECT  99.807 19.997 99.897 20.267 ;
     RECT  105.207 19.997 105.297 20.267 ;
     RECT  110.607 19.997 110.697 20.267 ;
     RECT  116.007 19.997 116.097 20.267 ;
     RECT  38.772 19.949 38.79 20.309 ;
     RECT  77.148 20.219 77.31 20.309 ;
     RECT  25.092 19.769 26.73 20.317 ;
     RECT  31.248 20.039 31.626 20.345 ;
     RECT  47.016 20.183 47.034 20.345 ;
     RECT  67.68 20.267 67.986 20.345 ;
     RECT  31.356 20.345 31.626 20.381 ;
     RECT  41.904 20.147 43.002 20.381 ;
     RECT  62.784 20.267 63.63 20.381 ;
     RECT  66.708 20.267 66.834 20.381 ;
     RECT  77.184 20.309 77.31 20.381 ;
     RECT  25.092 20.317 26.802 20.417 ;
     RECT  29.988 20.267 30.006 20.417 ;
     RECT  31.356 20.381 31.518 20.417 ;
     RECT  72.972 20.267 73.422 20.417 ;
     RECT  56.376 20.075 60.138 20.429 ;
     RECT  69.984 20.093 71.298 20.453 ;
     RECT  74.664 20.219 76.41 20.453 ;
     RECT  80.136 20.075 80.154 20.453 ;
     RECT  31.428 20.417 31.518 20.489 ;
     RECT  35.136 20.267 36.558 20.489 ;
     RECT  35.136 20.489 36.414 20.525 ;
     RECT  56.376 20.429 57.87 20.525 ;
     RECT  66.816 20.381 66.834 20.525 ;
     RECT  35.928 20.525 36.414 20.534 ;
     RECT  86.112 20.183 87.426 20.534 ;
     RECT  27.792 20.147 28.386 20.579 ;
     RECT  35.136 20.525 35.154 20.615 ;
     RECT  70.74 20.453 71.298 20.615 ;
     RECT  74.7 20.453 76.41 20.615 ;
     RECT  51.444 20.267 51.462 20.651 ;
     RECT  52.74 20.183 53.226 20.804 ;
     RECT  87.264 20.534 87.426 20.813 ;
     RECT  88.488 20.267 88.506 20.849 ;
     RECT  49.968 20.267 50.67 20.861 ;
     RECT  35.964 20.534 36.414 20.885 ;
     RECT  71.28 20.615 71.298 20.885 ;
     RECT  28.08 20.579 28.386 20.909 ;
     RECT  53.964 20.183 55.566 20.909 ;
     RECT  74.772 20.615 76.41 20.921 ;
     RECT  25.488 20.417 26.622 20.957 ;
     RECT  29.16 20.267 29.178 20.957 ;
     RECT  82.296 20.267 83.178 20.957 ;
     RECT  2.415 20.189 5.058 20.965 ;
     RECT  5.796 20.267 23.49 20.965 ;
     RECT  25.488 20.957 26.334 20.993 ;
     RECT  87.264 20.813 87.282 20.993 ;
     RECT  64.404 20.219 64.998 21.005 ;
     RECT  28.116 20.909 28.386 21.119 ;
     RECT  33.768 19.997 34.218 21.119 ;
     RECT  86.112 20.534 86.13 21.119 ;
     RECT  33.624 21.199 33.642 21.245 ;
     RECT  75.276 20.921 76.41 21.293 ;
     RECT  36 20.885 36.414 21.341 ;
     RECT  64.404 21.005 64.422 21.341 ;
     RECT  36.396 21.341 36.414 21.389 ;
     RECT  53.964 20.909 55.206 21.389 ;
     RECT  77.184 20.381 77.202 21.389 ;
     RECT  78.84 20.267 78.858 21.389 ;
     RECT  63 20.381 63.63 21.425 ;
     RECT  90.864 20.075 90.882 21.425 ;
     RECT  53.964 21.389 53.982 21.437 ;
     RECT  82.296 20.957 82.458 21.485 ;
     RECT  41.904 20.381 42.102 21.497 ;
     RECT  40.752 20.267 40.77 21.533 ;
     RECT  42.984 20.381 43.002 21.533 ;
     RECT  57.204 20.525 57.87 21.533 ;
     RECT  28.116 21.119 28.314 21.569 ;
     RECT  25.488 20.993 25.686 21.614 ;
     RECT  60.912 20.075 60.93 21.629 ;
     RECT  55.08 21.389 55.206 21.643 ;
     RECT  61.848 20.267 61.866 21.677 ;
     RECT  67.68 20.345 67.698 21.677 ;
     RECT  75.492 21.293 76.41 21.856 ;
     RECT  0.54 15.025 0.558 21.931 ;
     RECT  2.415 20.965 23.49 22.464 ;
     RECT  25.488 21.614 25.506 22.464 ;
     RECT  28.116 21.569 28.134 22.464 ;
     RECT  42.084 21.497 42.102 22.464 ;
     RECT  48.528 20.075 48.546 22.464 ;
     RECT  50.652 20.861 50.67 22.464 ;
     RECT  52.74 20.804 52.758 22.464 ;
     RECT  55.08 21.643 55.278 22.464 ;
     RECT  56.376 20.525 56.394 22.464 ;
     RECT  57.852 21.533 57.87 22.464 ;
     RECT  59.148 20.429 60.138 22.464 ;
     RECT  63.144 21.425 63.63 22.464 ;
     RECT  69.984 20.453 70.002 22.464 ;
     RECT  73.404 20.417 73.422 22.464 ;
     RECT  74.664 21.856 74.682 22.464 ;
     RECT  75.492 21.856 76.554 22.464 ;
     RECT  82.296 21.485 82.314 22.464 ;
     RECT  117.324 16.339 121.626 22.464 ;
     RECT  2.415 22.464 121.626 23.657 ;
     RECT  3.816 23.657 121.626 23.693 ;
     RECT  3.888 23.693 121.626 23.819 ;
     RECT  2.415 23.657 3.078 24.637 ;
     RECT  4.14 23.819 121.626 24.637 ;
     RECT  2.415 24.637 121.626 25.037 ;
     RECT  0.432 21.931 0.558 25.447 ;
     RECT  2.415 25.037 121.59 25.853 ;
     RECT  1.332 14.443 1.35 26.635 ;
     RECT  2.415 25.853 121.497 31.531 ;
     RECT  1.332 26.635 1.566 31.801 ;
     RECT  2.304 31.531 121.497 31.801 ;
     RECT  0.36 25.447 0.558 32.251 ;
     RECT  0.216 32.251 0.558 32.341 ;
     RECT  1.332 31.801 121.497 32.341 ;
     RECT  0.216 32.341 121.497 32.765 ;
     RECT  0.216 32.765 118.386 32.861 ;
     RECT  0.216 32.861 118.206 32.957 ;
     RECT  0.216 32.957 117.558 33.629 ;
     RECT  0.216 33.629 117.414 33.881 ;
     RECT  119.16 32.765 121.497 34.013 ;
     RECT  119.232 34.013 121.497 34.109 ;
     RECT  119.484 34.109 121.497 34.397 ;
     RECT  0.252 33.881 117.414 34.627 ;
     RECT  0.252 34.627 118.026 34.877 ;
     RECT  119.484 34.397 119.97 34.973 ;
     RECT  0.252 34.877 117.414 34.987 ;
     RECT  119.484 34.973 119.754 35.005 ;
     RECT  119.088 35.005 119.754 35.069 ;
     RECT  118.548 35.203 118.674 35.339 ;
     RECT  119.592 35.069 119.754 35.453 ;
     RECT  0.216 34.987 117.414 35.549 ;
     RECT  0.216 35.549 117.378 35.609 ;
     RECT  118.548 35.339 118.602 35.645 ;
     RECT  119.7 35.453 119.754 35.803 ;
     RECT  119.7 35.803 119.79 35.879 ;
     RECT  118.584 35.645 118.602 35.933 ;
     RECT  0.324 35.609 117.378 36.275 ;
     RECT  119.7 35.879 119.754 36.283 ;
     RECT  0.324 36.275 117.288 36.331 ;
     RECT  119.124 36.283 119.754 36.815 ;
     RECT  119.52 36.815 119.754 36.859 ;
     RECT  0.252 36.331 117.288 37.147 ;
     RECT  0.216 37.147 117.288 37.243 ;
     RECT  118.584 37.021 118.602 37.561 ;
     RECT  119.52 36.859 120.078 37.561 ;
     RECT  118.584 37.561 120.078 37.895 ;
     RECT  119.952 37.895 120.078 37.967 ;
     RECT  0.216 37.243 117.378 38.005 ;
     RECT  118.584 37.895 119.106 38.677 ;
     RECT  119.952 37.967 119.97 38.677 ;
     RECT  118.584 38.677 119.97 38.813 ;
     RECT  0.216 38.005 117.414 39.091 ;
     RECT  0.216 39.091 117.45 39.197 ;
     RECT  0.216 39.197 117.414 39.245 ;
     RECT  118.584 38.813 119.106 39.389 ;
     RECT  119.988 39.091 120.006 39.631 ;
     RECT  119.844 39.631 120.006 39.857 ;
     RECT  119.844 39.857 119.97 39.901 ;
     RECT  0.252 39.245 117.414 40.027 ;
     RECT  119.736 39.901 119.97 40.055 ;
     RECT  118.584 39.389 118.674 40.163 ;
     RECT  119.952 40.055 119.97 40.469 ;
     RECT  118.584 40.163 118.638 40.667 ;
     RECT  0.216 40.027 117.414 40.972 ;
     RECT  118.584 40.667 118.602 41.009 ;
     RECT  0.216 40.972 117.45 41.021 ;
     RECT  119.772 41.341 119.79 41.449 ;
     RECT  119.772 41.449 119.97 41.549 ;
     RECT  119.772 41.549 119.79 42.139 ;
     RECT  119.592 42.139 119.79 42.421 ;
     RECT  119.592 42.421 119.898 42.557 ;
     RECT  119.592 42.557 119.862 42.565 ;
     RECT  119.088 42.565 119.862 42.727 ;
     RECT  0.216 41.021 117.414 42.755 ;
     RECT  118.584 42.727 119.862 42.755 ;
     RECT  118.584 42.755 119.754 42.941 ;
     RECT  0.252 42.755 117.414 43.025 ;
     RECT  119.736 42.941 119.754 43.295 ;
     RECT  0.288 43.025 117.414 43.672 ;
     RECT  0.288 43.672 117.45 43.709 ;
     RECT  119.448 43.771 119.466 43.843 ;
     RECT  119.376 43.843 119.466 44.041 ;
     RECT  119.376 44.041 119.898 44.177 ;
     RECT  118.584 42.941 118.602 44.383 ;
     RECT  119.376 44.177 119.862 44.383 ;
     RECT  118.584 44.383 119.862 44.447 ;
     RECT  118.584 44.447 119.466 44.573 ;
     RECT  0.288 43.709 117.414 44.779 ;
     RECT  0.216 44.779 117.414 44.915 ;
     RECT  119.448 44.573 119.466 45.059 ;
     RECT  0.288 44.915 117.414 45.121 ;
     RECT  0.288 45.121 117.45 45.341 ;
     RECT  118.584 44.573 118.602 45.427 ;
     RECT  118.584 45.427 119.106 45.959 ;
     RECT  118.62 45.959 119.106 46.205 ;
     RECT  119.736 46.273 119.754 46.607 ;
     RECT  118.584 46.741 118.602 47.155 ;
     RECT  119.844 47.155 119.862 47.309 ;
     RECT  119.988 47.659 120.006 47.849 ;
     RECT  0.288 45.341 117.414 48.127 ;
     RECT  118.584 47.155 119.106 48.235 ;
     RECT  119.844 48.127 119.862 48.235 ;
     RECT  0.288 48.127 117.45 48.317 ;
     RECT  118.584 48.235 119.862 48.703 ;
     RECT  0.288 48.317 117.414 48.893 ;
     RECT  118.584 48.703 119.898 48.929 ;
     RECT  118.584 48.929 119.754 49.379 ;
     RECT  119.088 49.379 119.754 49.541 ;
     RECT  0.288 48.893 117.378 49.813 ;
     RECT  119.088 49.541 119.106 50.287 ;
     RECT  118.584 50.287 119.106 50.459 ;
     RECT  119.844 50.593 119.862 50.629 ;
     RECT  119.844 50.629 120.078 50.729 ;
     RECT  118.62 50.459 119.106 50.827 ;
     RECT  119.844 50.729 119.898 50.827 ;
     RECT  118.62 50.827 119.898 50.927 ;
     RECT  118.656 50.927 119.898 51.197 ;
     RECT  118.656 51.197 119.754 51.773 ;
     RECT  118.656 51.773 119.538 51.943 ;
     RECT  0.288 49.813 117.414 52.027 ;
     RECT  0.216 52.027 117.414 52.205 ;
     RECT  118.584 51.943 119.538 52.619 ;
     RECT  119.088 52.619 119.538 52.795 ;
     RECT  119.088 52.795 119.574 52.861 ;
     RECT  119.088 52.861 119.934 53.401 ;
     RECT  119.088 53.401 120.042 53.671 ;
     RECT  118.62 53.671 120.042 54.211 ;
     RECT  118.62 54.211 120.186 54.329 ;
     RECT  118.62 54.329 119.934 54.509 ;
     RECT  119.268 54.509 119.934 54.707 ;
     RECT  119.556 54.707 119.934 54.869 ;
     RECT  0.288 52.205 117.414 55.099 ;
     RECT  119.628 54.869 119.934 55.175 ;
     RECT  0.288 55.099 118.026 55.291 ;
     RECT  119.628 55.175 119.754 55.675 ;
     RECT  119.34 55.675 119.754 55.921 ;
     RECT  119.34 55.921 119.898 56.021 ;
     RECT  119.34 56.021 119.754 56.093 ;
     RECT  0.288 55.291 118.062 56.191 ;
     RECT  0.288 56.191 118.602 56.263 ;
     RECT  0.288 56.263 118.638 56.561 ;
     RECT  118.584 56.561 118.638 56.804 ;
     RECT  118.584 56.804 118.602 56.939 ;
     RECT  119.556 56.093 119.754 57.029 ;
     RECT  119.7 57.029 119.754 57.145 ;
     RECT  119.7 57.145 119.862 57.415 ;
     RECT  0.288 56.561 117.45 57.947 ;
     RECT  119.7 57.415 119.97 58.075 ;
     RECT  119.268 58.075 119.97 58.109 ;
     RECT  119.268 58.109 119.79 58.171 ;
     RECT  119.088 58.171 119.79 58.261 ;
     RECT  118.728 58.261 119.79 58.351 ;
     RECT  118.584 58.351 119.79 58.487 ;
     RECT  118.584 58.487 118.746 58.559 ;
     RECT  119.556 58.487 119.79 59.035 ;
     RECT  118.584 58.559 118.638 59.063 ;
     RECT  119.556 59.035 119.97 59.189 ;
     RECT  119.556 59.189 119.934 59.459 ;
     RECT  119.736 59.459 119.934 59.765 ;
     RECT  118.584 59.063 118.602 60.341 ;
     RECT  119.736 59.765 119.754 60.379 ;
     RECT  119.556 60.379 119.754 60.667 ;
     RECT  119.268 60.667 119.754 61.051 ;
     RECT  119.268 61.051 119.79 61.187 ;
     RECT  119.268 61.187 119.754 61.385 ;
     RECT  119.268 61.385 119.646 61.723 ;
     RECT  0.288 57.947 117.414 61.819 ;
     RECT  0.288 61.819 118.026 62.107 ;
     RECT  119.16 61.723 119.646 62.131 ;
     RECT  119.16 62.131 119.718 62.303 ;
     RECT  0.288 62.107 118.062 62.573 ;
     RECT  0.324 62.573 118.062 62.879 ;
     RECT  118.044 62.879 118.062 63.005 ;
     RECT  119.7 62.303 119.718 63.005 ;
     RECT  0.324 62.879 117.288 63.528 ;
     RECT  0.324 63.528 23.562 64.363 ;
     RECT  33.228 63.528 33.246 64.399 ;
     RECT  30.276 63.528 30.294 64.411 ;
     RECT  29.232 64.363 29.25 64.471 ;
     RECT  30.276 64.411 30.798 64.541 ;
     RECT  35.316 64.411 35.55 64.541 ;
     RECT  30.276 64.541 30.294 64.633 ;
     RECT  63.792 63.528 63.81 64.651 ;
     RECT  25.56 64.327 25.578 64.786 ;
     RECT  26.604 63.528 26.622 64.786 ;
     RECT  0.324 64.363 23.814 64.939 ;
     RECT  32.004 63.528 32.022 64.939 ;
     RECT  62.316 64.363 62.334 64.939 ;
     RECT  48.996 64.363 49.014 64.987 ;
     RECT  25.56 64.786 26.622 65.011 ;
     RECT  24.984 65.011 26.622 65.056 ;
     RECT  0.324 64.939 23.958 65.137 ;
     RECT  24.84 65.056 26.622 65.137 ;
     RECT  28.656 64.471 29.25 65.209 ;
     RECT  30.024 64.633 30.294 65.209 ;
     RECT  63.792 64.651 63.882 65.275 ;
     RECT  0.324 65.137 26.622 65.326 ;
     RECT  34.524 65.227 34.542 65.479 ;
     RECT  71.316 63.528 71.334 65.515 ;
     RECT  0.324 65.326 26.658 65.551 ;
     RECT  27.828 64.747 27.846 65.551 ;
     RECT  38.196 65.179 38.214 65.551 ;
     RECT  44.1 63.528 44.118 65.551 ;
     RECT  31.464 64.939 32.022 65.563 ;
     RECT  48.996 64.987 49.482 65.563 ;
     RECT  55.368 65.245 55.386 65.563 ;
     RECT  70.344 65.515 70.362 65.563 ;
     RECT  34.524 65.479 34.578 65.593 ;
     RECT  35.316 64.541 35.334 65.593 ;
     RECT  68.148 64.747 68.166 65.593 ;
     RECT  72.756 64.939 72.774 65.593 ;
     RECT  0.324 65.551 26.766 65.641 ;
     RECT  61.596 64.939 62.334 65.641 ;
     RECT  31.356 65.563 32.022 65.677 ;
     RECT  34.524 65.593 35.334 65.677 ;
     RECT  48.996 65.563 50.094 65.707 ;
     RECT  51.207 65.593 51.297 65.707 ;
     RECT  67.407 65.593 68.166 65.713 ;
     RECT  43.236 63.528 43.254 65.785 ;
     RECT  48.996 65.707 51.297 65.785 ;
     RECT  65.88 63.528 65.898 65.785 ;
     RECT  66.852 65.713 68.166 65.785 ;
     RECT  73.62 65.641 73.638 65.785 ;
     RECT  38.196 65.551 38.826 65.803 ;
     RECT  70.092 65.563 70.362 65.803 ;
     RECT  43.128 65.785 43.254 65.821 ;
     RECT  44.1 65.551 44.19 65.821 ;
     RECT  55.152 65.563 55.386 65.821 ;
     RECT  57.636 65.785 57.654 65.821 ;
     RECT  63.792 65.275 64.422 65.821 ;
     RECT  71.136 65.515 71.334 65.821 ;
     RECT  72.756 65.593 72.897 65.821 ;
     RECT  39.636 65.281 39.654 65.863 ;
     RECT  40.407 65.593 40.497 65.863 ;
     RECT  45.807 65.593 45.897 65.863 ;
     RECT  55.152 65.821 55.818 65.863 ;
     RECT  56.607 65.593 56.697 65.863 ;
     RECT  78.207 65.593 78.297 65.863 ;
     RECT  83.607 65.593 83.697 65.863 ;
     RECT  89.007 65.593 89.097 65.863 ;
     RECT  94.407 65.593 94.497 65.863 ;
     RECT  99.807 65.593 99.897 65.863 ;
     RECT  105.207 65.593 105.297 65.863 ;
     RECT  110.607 65.593 110.697 65.863 ;
     RECT  116.007 65.593 116.097 65.863 ;
     RECT  34.524 65.677 35.514 65.899 ;
     RECT  71.136 65.821 72.897 65.911 ;
     RECT  73.62 65.785 74.07 65.911 ;
     RECT  43.128 65.821 44.19 65.941 ;
     RECT  48.528 65.785 51.297 65.941 ;
     RECT  37.584 65.803 38.826 65.947 ;
     RECT  48.528 65.941 51.786 65.947 ;
     RECT  54.252 65.641 54.27 65.947 ;
     RECT  63.684 65.821 64.422 65.947 ;
     RECT  34.308 65.899 35.514 65.995 ;
     RECT  37.548 65.947 38.826 66.019 ;
     RECT  48.456 65.947 51.786 66.019 ;
     RECT  43.128 65.941 44.766 66.043 ;
     RECT  45.615 65.863 45.897 66.043 ;
     RECT  57.564 65.821 57.654 66.043 ;
     RECT  47.556 65.911 47.574 66.055 ;
     RECT  48.42 66.019 51.786 66.055 ;
     RECT  54 65.947 54.27 66.055 ;
     RECT  55.152 65.863 56.697 66.055 ;
     RECT  65.88 65.785 68.166 66.055 ;
     RECT  69.552 65.803 70.362 66.055 ;
     RECT  71.136 65.911 74.07 66.055 ;
     RECT  31.356 65.677 32.202 66.091 ;
     RECT  33.228 64.399 33.462 66.091 ;
     RECT  36.648 65.443 36.666 66.091 ;
     RECT  37.548 66.019 38.862 66.091 ;
     RECT  48.348 66.055 51.786 66.091 ;
     RECT  53.172 65.947 53.19 66.091 ;
     RECT  54 66.055 56.697 66.091 ;
     RECT  57.564 66.043 58.194 66.091 ;
     RECT  59.652 65.947 59.67 66.091 ;
     RECT  63.684 65.947 65.034 66.091 ;
     RECT  65.808 66.055 68.166 66.091 ;
     RECT  69.552 66.055 74.07 66.091 ;
     RECT  48.348 66.091 53.19 66.139 ;
     RECT  0.324 65.641 26.946 66.181 ;
     RECT  27.72 65.551 27.846 66.181 ;
     RECT  43.128 66.043 45.897 66.181 ;
     RECT  48.348 66.139 53.262 66.181 ;
     RECT  54 66.091 59.67 66.181 ;
     RECT  61.596 65.641 62.658 66.181 ;
     RECT  139.824 52.027 139.842 66.209 ;
     RECT  0.324 66.181 27.846 66.217 ;
     RECT  28.656 65.209 30.294 66.217 ;
     RECT  47.556 66.055 47.61 66.217 ;
     RECT  48.348 66.181 59.67 66.217 ;
     RECT  63.684 66.091 68.166 66.217 ;
     RECT  69.336 66.091 74.07 66.217 ;
     RECT  61.596 66.181 62.874 66.235 ;
     RECT  63.684 66.217 74.25 66.235 ;
     RECT  43.128 66.181 46.206 66.253 ;
     RECT  47.556 66.217 59.67 66.253 ;
     RECT  61.596 66.235 74.25 66.28 ;
     RECT  36.648 66.091 38.862 66.289 ;
     RECT  39.636 65.863 40.497 66.289 ;
     RECT  47.124 66.253 60.138 66.289 ;
     RECT  36.648 66.289 40.497 66.361 ;
     RECT  42.732 66.253 46.206 66.361 ;
     RECT  47.052 66.289 60.138 66.361 ;
     RECT  61.2 66.28 74.25 66.361 ;
     RECT  75.852 66.235 75.87 66.361 ;
     RECT  0.324 66.217 30.438 66.389 ;
     RECT  42.732 66.361 60.138 66.389 ;
     RECT  1.08 66.389 30.438 66.451 ;
     RECT  31.356 66.091 33.462 66.451 ;
     RECT  34.2 65.995 35.514 66.487 ;
     RECT  36.252 66.361 41.022 66.487 ;
     RECT  61.2 66.361 74.394 66.487 ;
     RECT  75.168 66.361 75.87 66.487 ;
     RECT  61.056 66.487 74.394 66.517 ;
     RECT  41.832 66.325 41.85 66.559 ;
     RECT  42.732 66.389 56.697 66.559 ;
     RECT  60.948 66.517 74.394 66.559 ;
     RECT  75.132 66.487 75.87 66.559 ;
     RECT  1.08 66.451 33.462 66.605 ;
     RECT  139.608 66.325 139.626 66.605 ;
     RECT  34.2 66.487 41.022 66.631 ;
     RECT  41.832 66.559 56.697 66.631 ;
     RECT  57.456 66.389 60.138 66.631 ;
     RECT  60.948 66.559 75.87 66.631 ;
     RECT  0.324 66.389 0.342 66.659 ;
     RECT  2.196 66.605 33.462 66.757 ;
     RECT  34.2 66.631 56.697 66.757 ;
     RECT  57.456 66.631 76.374 67.243 ;
     RECT  2.196 66.757 56.697 67.333 ;
     RECT  57.456 67.243 76.842 67.333 ;
     RECT  2.196 67.333 76.842 67.433 ;
     RECT  60.984 67.433 76.842 67.441 ;
     RECT  60.984 67.441 77.274 67.739 ;
     RECT  61.056 67.739 77.274 67.981 ;
     RECT  78.015 65.863 78.297 67.981 ;
     RECT  61.056 67.981 78.297 68.135 ;
     RECT  61.056 68.135 76.986 68.639 ;
     RECT  61.056 68.639 76.842 68.747 ;
     RECT  61.056 68.747 76.662 68.881 ;
     RECT  2.196 67.433 60.21 68.917 ;
     RECT  60.984 68.881 76.662 68.917 ;
     RECT  2.196 68.917 76.662 69.053 ;
     RECT  1.08 66.605 1.098 69.341 ;
     RECT  2.232 69.053 76.662 69.521 ;
     RECT  2.232 69.521 76.482 70.673 ;
     RECT  61.092 70.673 76.482 71.221 ;
     RECT  61.092 71.221 76.986 71.581 ;
     RECT  2.232 70.673 60.21 71.689 ;
     RECT  61.02 71.581 76.986 71.689 ;
     RECT  2.232 71.689 76.986 71.789 ;
     RECT  2.232 71.789 76.914 72.293 ;
     RECT  2.232 72.293 76.698 72.959 ;
     RECT  2.232 72.959 76.59 73.337 ;
     RECT  2.232 73.337 76.518 73.499 ;
     RECT  2.232 73.499 76.446 73.535 ;
     RECT  2.232 73.535 76.41 74.111 ;
     RECT  64.26 74.111 76.41 74.453 ;
     RECT  64.26 74.453 69.066 74.651 ;
     RECT  2.232 74.111 63.378 74.759 ;
     RECT  2.412 74.759 63.378 74.906 ;
     RECT  2.412 74.906 63.486 74.929 ;
     RECT  64.26 74.651 68.958 74.929 ;
     RECT  69.804 74.453 76.41 75.227 ;
     RECT  2.412 74.929 68.958 75.389 ;
     RECT  2.412 75.389 49.086 75.425 ;
     RECT  49.932 75.389 68.958 75.533 ;
     RECT  64.44 75.533 68.958 75.541 ;
     RECT  69.804 75.227 75.942 75.541 ;
     RECT  64.44 75.541 75.942 75.659 ;
     RECT  2.415 75.425 49.086 76.037 ;
     RECT  2.415 76.037 44.046 76.109 ;
     RECT  64.44 75.659 75.798 76.199 ;
     RECT  44.784 76.037 49.086 76.363 ;
     RECT  49.932 75.533 63.234 76.363 ;
     RECT  64.44 76.199 75.654 76.477 ;
     RECT  64.26 76.477 75.654 76.505 ;
     RECT  64.26 76.505 74.25 76.541 ;
     RECT  74.988 76.505 75.654 76.541 ;
     RECT  64.404 76.541 74.25 76.577 ;
     RECT  44.784 76.363 63.234 76.739 ;
     RECT  64.512 76.577 74.25 76.739 ;
     RECT  75.204 76.541 75.654 76.739 ;
     RECT  64.512 76.739 68.382 76.775 ;
     RECT  75.204 76.739 75.222 76.775 ;
     RECT  69.12 76.739 74.142 76.811 ;
     RECT  65.412 76.775 68.382 76.847 ;
     RECT  2.415 76.109 44.01 76.891 ;
     RECT  44.784 76.739 48.87 76.891 ;
     RECT  65.412 76.847 67.59 76.919 ;
     RECT  64.512 76.775 64.638 77.009 ;
     RECT  68.364 76.847 68.382 77.009 ;
     RECT  69.12 76.811 69.246 77.009 ;
     RECT  70.128 76.811 74.142 77.009 ;
     RECT  2.415 76.891 48.87 77.045 ;
     RECT  49.608 76.739 63.234 77.045 ;
     RECT  69.228 77.009 69.246 77.081 ;
     RECT  70.128 77.009 71.658 77.165 ;
     RECT  64.512 77.009 64.53 77.261 ;
     RECT  2.415 77.045 48.654 77.279 ;
     RECT  59.4 77.045 63.018 77.279 ;
     RECT  65.412 76.919 67.554 77.279 ;
     RECT  70.128 77.165 71.622 77.279 ;
     RECT  70.128 77.279 71.262 77.315 ;
     RECT  72.432 77.009 73.926 77.315 ;
     RECT  65.412 77.279 67.497 77.357 ;
     RECT  49.608 77.045 58.482 77.423 ;
     RECT  59.544 77.279 63.018 77.423 ;
     RECT  59.544 77.423 61.074 77.459 ;
     RECT  70.38 77.315 70.398 77.459 ;
     RECT  71.136 77.315 71.262 77.459 ;
     RECT  72.615 77.315 73.926 77.459 ;
     RECT  59.544 77.459 60.426 77.549 ;
     RECT  61.815 77.423 63.018 77.549 ;
     RECT  65.916 77.357 67.497 77.549 ;
     RECT  72.615 77.459 73.17 77.549 ;
     RECT  73.908 77.459 73.926 77.549 ;
     RECT  4.788 77.279 48.654 77.555 ;
     RECT  4.788 77.555 44.73 77.585 ;
     RECT  49.608 77.423 58.086 77.585 ;
     RECT  61.815 77.549 62.262 77.585 ;
     RECT  59.544 77.549 59.562 77.597 ;
     RECT  45.504 77.555 48.654 77.693 ;
     RECT  60.3 77.549 60.426 77.819 ;
     RECT  66.348 77.549 66.402 77.819 ;
     RECT  45.615 77.693 48.654 77.855 ;
     RECT  60.3 77.819 60.318 77.855 ;
     RECT  66.348 77.819 66.366 77.855 ;
     RECT  48.636 77.855 48.654 77.891 ;
     RECT  49.608 77.585 53.298 77.891 ;
     RECT  54.144 77.585 58.086 77.891 ;
     RECT  54.144 77.891 57.942 77.963 ;
     RECT  8.964 77.585 44.73 77.999 ;
     RECT  45.615 77.855 47.898 77.999 ;
     RECT  54.252 77.963 57.294 77.999 ;
     RECT  54.864 77.999 54.882 78.077 ;
     RECT  8.964 77.999 43.038 78.089 ;
     RECT  43.776 77.999 44.73 78.089 ;
     RECT  45.615 77.999 47.322 78.089 ;
     RECT  50.256 77.891 53.298 78.089 ;
     RECT  55.656 77.999 56.754 78.089 ;
     RECT  43.776 78.089 43.83 78.125 ;
     RECT  45.615 78.089 46.674 78.125 ;
     RECT  50.94 78.089 53.01 78.125 ;
     RECT  43.812 78.125 43.83 78.161 ;
     RECT  46.656 78.125 46.674 78.161 ;
     RECT  44.712 78.089 44.73 78.359 ;
     RECT  56.415 78.089 56.754 78.359 ;
     RECT  4.788 77.585 8.19 78.367 ;
     RECT  8.964 78.089 42.858 78.367 ;
     RECT  4.788 78.367 42.858 78.503 ;
     RECT  2.415 77.279 3.906 78.511 ;
     RECT  2.415 78.511 4.05 78.745 ;
     RECT  4.788 78.503 8.262 78.745 ;
     RECT  9 78.503 42.858 78.809 ;
     RECT  14.508 78.809 42.858 78.935 ;
     RECT  14.508 78.935 16.902 79.085 ;
     RECT  17.64 78.935 42.858 79.169 ;
     RECT  2.415 78.745 8.262 79.285 ;
     RECT  9 78.809 13.77 79.285 ;
     RECT  2.415 79.285 13.77 79.565 ;
     RECT  14.544 79.085 16.902 79.672 ;
     RECT  2.415 79.565 13.497 79.709 ;
     RECT  14.544 79.672 16.938 79.709 ;
     RECT  2.415 79.709 5.958 79.745 ;
     RECT  14.58 79.709 16.758 79.781 ;
     RECT  17.676 79.169 42.858 79.781 ;
     RECT  6.84 79.709 13.497 79.979 ;
     RECT  14.58 79.781 16.686 79.979 ;
     RECT  44.46 79.177 44.478 79.987 ;
     RECT  45.615 78.125 45.897 79.987 ;
     RECT  2.415 79.745 3.906 80.015 ;
     RECT  4.644 79.745 5.958 80.015 ;
     RECT  6.84 79.979 10.566 80.015 ;
     RECT  14.58 79.979 16.578 80.015 ;
     RECT  2.415 80.015 2.934 80.087 ;
     RECT  14.832 80.015 16.506 80.087 ;
     RECT  18.036 79.781 42.858 80.087 ;
     RECT  2.415 80.087 2.826 80.123 ;
     RECT  11.412 79.979 13.497 80.159 ;
     RECT  44.46 79.987 45.897 80.221 ;
     RECT  46.764 79.591 46.782 80.221 ;
     RECT  4.716 80.015 5.958 80.249 ;
     RECT  7.092 80.015 10.566 80.249 ;
     RECT  44.46 80.221 46.782 80.249 ;
     RECT  7.164 80.249 9.882 80.291 ;
     RECT  7.164 80.291 9.702 80.321 ;
     RECT  11.808 80.159 13.497 80.429 ;
     RECT  4.716 80.249 5.814 80.519 ;
     RECT  7.815 80.321 9.702 80.519 ;
     RECT  12.384 80.429 13.497 80.519 ;
     RECT  7.815 80.519 9.126 80.555 ;
     RECT  12.384 80.519 12.402 80.555 ;
     RECT  4.716 80.519 5.562 80.789 ;
     RECT  4.788 80.789 5.562 80.933 ;
     RECT  4.968 80.933 5.562 81.095 ;
     RECT  45.072 80.249 46.782 81.095 ;
     RECT  4.968 81.095 5.49 81.167 ;
     RECT  46.764 81.095 46.782 81.211 ;
     RECT  4.968 81.167 4.986 81.239 ;
     RECT  45.072 81.095 45.954 81.329 ;
     RECT  13.215 80.519 13.497 81.643 ;
     RECT  13.215 81.643 13.59 81.773 ;
     RECT  46.764 81.211 47.25 81.905 ;
     RECT  45.615 81.329 45.954 81.949 ;
     RECT  47.052 81.905 47.25 82.021 ;
     RECT  15.228 80.087 16.506 82.517 ;
     RECT  15.228 82.517 16.47 82.589 ;
     RECT  18.615 80.087 42.858 83.309 ;
     RECT  18.615 83.309 22.086 83.357 ;
     RECT  22.824 83.309 42.858 83.363 ;
     RECT  61.815 77.585 62.097 83.371 ;
     RECT  63 77.549 63.018 83.371 ;
     RECT  71.136 77.459 71.154 83.399 ;
     RECT  61.815 83.371 63.018 83.489 ;
     RECT  3.888 80.015 3.906 83.525 ;
     RECT  22.896 83.363 42.858 83.605 ;
     RECT  45.615 81.949 46.206 83.605 ;
     RECT  47.052 82.021 47.754 83.605 ;
     RECT  45.615 83.605 47.754 83.641 ;
     RECT  44.748 83.641 47.754 83.731 ;
     RECT  48.528 83.191 48.546 83.731 ;
     RECT  44.748 83.731 48.546 83.759 ;
     RECT  22.896 83.605 43.362 83.767 ;
     RECT  44.748 83.759 44.766 83.795 ;
     RECT  13.215 81.773 13.497 83.803 ;
     RECT  45.615 83.759 48.546 83.839 ;
     RECT  13.215 83.803 13.59 83.933 ;
     RECT  2.415 80.123 2.697 83.987 ;
     RECT  7.815 80.555 8.097 83.987 ;
     RECT  13.215 83.933 13.497 83.987 ;
     RECT  51.015 78.125 51.297 83.987 ;
     RECT  56.415 78.359 56.697 83.987 ;
     RECT  61.815 83.489 62.097 83.987 ;
     RECT  67.215 77.549 67.497 83.987 ;
     RECT  72.615 77.549 72.897 83.987 ;
     RECT  78.015 68.135 78.297 83.987 ;
     RECT  83.415 65.863 83.697 83.987 ;
     RECT  88.815 65.863 89.097 83.987 ;
     RECT  94.215 65.863 94.497 83.987 ;
     RECT  99.615 65.863 99.897 83.987 ;
     RECT  105.015 65.863 105.297 83.987 ;
     RECT  110.415 65.863 110.697 83.987 ;
     RECT  115.815 65.863 116.097 83.987 ;
     RECT  121.215 34.397 121.497 83.987 ;
     RECT  126.615 2.413 126.897 83.987 ;
     RECT  132.015 2.413 132.297 83.987 ;
     RECT  137.415 2.413 137.697 83.987 ;
     RECT  22.896 83.767 43.614 84.065 ;
     RECT  45.615 83.839 48.834 84.065 ;
     RECT  21.744 83.357 22.086 84.125 ;
     RECT  22.896 84.065 43.362 84.137 ;
     RECT  22.896 84.137 42.786 84.145 ;
     RECT  45.615 84.065 46.782 84.209 ;
     RECT  2.415 83.987 2.505 84.257 ;
     RECT  7.815 83.987 7.905 84.257 ;
     RECT  13.215 83.987 13.305 84.257 ;
     RECT  18.615 83.357 20.97 84.257 ;
     RECT  45.615 84.209 45.705 84.257 ;
     RECT  51.015 83.987 51.105 84.257 ;
     RECT  56.415 83.987 56.505 84.257 ;
     RECT  61.815 83.987 61.905 84.257 ;
     RECT  67.215 83.987 67.305 84.257 ;
     RECT  72.615 83.987 72.705 84.257 ;
     RECT  78.015 83.987 78.105 84.257 ;
     RECT  83.415 83.987 83.505 84.257 ;
     RECT  88.815 83.987 88.905 84.257 ;
     RECT  94.215 83.987 94.305 84.257 ;
     RECT  99.615 83.987 99.705 84.257 ;
     RECT  105.015 83.987 105.105 84.257 ;
     RECT  110.415 83.987 110.505 84.257 ;
     RECT  115.815 83.987 115.905 84.257 ;
     RECT  121.215 83.987 121.305 84.257 ;
     RECT  126.615 83.987 126.705 84.257 ;
     RECT  132.015 83.987 132.105 84.257 ;
     RECT  137.415 83.987 137.505 84.257 ;
     RECT  46.764 84.209 46.782 84.299 ;
     RECT  18.792 84.257 20.97 84.317 ;
     RECT  22.32 84.145 42.786 84.317 ;
     RECT  19.476 84.317 20.97 84.605 ;
     RECT  15.228 82.589 16.434 84.641 ;
     RECT  15.372 84.641 16.434 84.677 ;
     RECT  15.372 84.677 15.39 84.713 ;
     RECT  19.8 84.605 20.97 84.749 ;
     RECT  9.108 80.555 9.126 85.217 ;
     RECT  16.344 84.677 16.434 85.253 ;
     RECT  16.344 85.253 16.362 85.289 ;
     RECT  19.8 84.749 20.898 85.334 ;
     RECT  20.52 85.334 20.898 85.495 ;
     RECT  23.04 84.317 42.786 85.517 ;
     RECT  20.52 85.495 20.934 85.523 ;
     RECT  23.256 85.517 42.786 85.661 ;
     RECT  23.256 85.661 23.274 85.709 ;
     RECT  24.408 85.661 42.786 86.141 ;
     RECT  20.88 85.523 20.934 86.261 ;
     RECT  24.48 86.141 42.786 86.268 ;
     RECT  47.52 84.065 48.834 86.268 ;
     RECT  20.916 86.261 20.934 86.297 ;
     RECT  27.396 86.268 27.414 86.297 ;
     RECT  30.564 86.268 30.654 86.333 ;
    LAYER M4 ;
     RECT  0.156 32.256 0.245 42.792 ;
     RECT  0.205 52.032 0.245 52.2 ;
     RECT  0.245 32.4 0.281 42.792 ;
     RECT  0.421 21.936 0.469 21.96 ;
     RECT  0.421 55.776 0.469 55.8 ;
     RECT  0.457 26.784 0.493 26.808 ;
     RECT  0.457 61.92 0.493 61.944 ;
     RECT  0.281 32.4 0.497 42.216 ;
     RECT  0.156 44.064 0.901 45.096 ;
     RECT  0.889 57.408 0.925 57.432 ;
     RECT  0.385 59.04 0.925 59.064 ;
     RECT  0.493 26.016 0.949 26.808 ;
     RECT  0.529 60.672 0.949 60.696 ;
     RECT  0.517 13.632 0.997 13.656 ;
     RECT  0.517 50.64 0.997 51.048 ;
     RECT  1.069 69.312 1.093 69.336 ;
     RECT  0.997 50.064 1.181 51.048 ;
     RECT  0.997 13.632 1.321 14.184 ;
     RECT  0.245 52.176 1.393 52.2 ;
     RECT  1.393 52.176 1.429 52.536 ;
     RECT  1.321 53.568 1.429 53.592 ;
     RECT  0.901 66.288 1.573 66.312 ;
     RECT  0.493 61.728 1.645 61.944 ;
     RECT  1.033 63.024 1.645 63.048 ;
     RECT  1.045 28.512 1.669 28.536 ;
     RECT  0.497 39.312 2.077 42.216 ;
     RECT  0.901 43.632 2.077 45.096 ;
     RECT  1.093 69.264 2.185 69.336 ;
     RECT  0.497 32.4 2.257 38.328 ;
     RECT  1.573 66.288 2.365 66.6 ;
     RECT  1.321 13.632 2.408 14.472 ;
     RECT  2.365 16.56 2.408 16.584 ;
     RECT  2.365 18.144 2.408 18.168 ;
     RECT  0.469 21.936 2.408 22.008 ;
     RECT  0.949 25.296 2.408 26.808 ;
     RECT  1.669 27.888 2.408 28.536 ;
     RECT  2.257 32.208 2.408 38.328 ;
     RECT  2.077 39.312 2.408 45.096 ;
     RECT  1.181 50.064 2.408 50.568 ;
     RECT  1.429 52.176 2.408 53.592 ;
     RECT  0.469 55.536 2.408 55.8 ;
     RECT  0.925 57.408 2.408 59.064 ;
     RECT  0.949 60.288 2.408 60.696 ;
     RECT  1.645 61.728 2.408 63.048 ;
     RECT  2.365 66.24 2.408 66.6 ;
     RECT  2.185 69.024 2.408 69.336 ;
     RECT  1.045 70.32 2.408 70.344 ;
     RECT  1.669 77.328 2.408 77.352 ;
     RECT  2.408 2.148 2.512 84.252 ;
     RECT  2.512 2.418 2.704 83.982 ;
     RECT  2.704 77.328 2.801 77.448 ;
     RECT  2.704 55.536 2.873 64.44 ;
     RECT  2.704 73.392 2.915 75.144 ;
     RECT  2.873 55.536 2.963 64.344 ;
     RECT  2.704 21.408 3.059 23.784 ;
     RECT  2.704 31.92 3.169 37.608 ;
     RECT  2.704 12.816 3.305 19.032 ;
     RECT  2.963 56.88 3.413 64.344 ;
     RECT  2.704 20.16 3.449 20.184 ;
     RECT  3.413 57.552 3.557 64.344 ;
     RECT  2.704 65.52 3.635 67.896 ;
     RECT  2.704 50.064 3.692 53.592 ;
     RECT  3.169 32.064 3.697 37.608 ;
     RECT  3.557 61.728 3.701 64.344 ;
     RECT  2.704 39.552 3.733 42.6 ;
     RECT  2.704 43.632 3.733 45.096 ;
     RECT  2.704 48.384 3.733 48.984 ;
     RECT  3.692 50.064 3.733 53.832 ;
     RECT  2.704 79.248 3.733 79.272 ;
     RECT  3.733 39.552 3.737 45.192 ;
     RECT  3.733 48.384 3.769 49.032 ;
     RECT  3.733 50.064 3.769 54.504 ;
     RECT  2.704 46.8 3.809 47.352 ;
     RECT  3.805 10.224 3.829 10.248 ;
     RECT  2.704 11.376 3.829 11.4 ;
     RECT  3.697 32.064 3.829 37.992 ;
     RECT  2.915 73.392 3.884 73.416 ;
     RECT  2.915 74.592 3.884 75.144 ;
     RECT  3.829 9.312 3.971 11.4 ;
     RECT  2.704 69.024 3.973 70.344 ;
     RECT  3.701 61.728 3.989 64.296 ;
     RECT  3.829 32.064 4.093 38.136 ;
     RECT  3.809 46.8 4.124 47.112 ;
     RECT  3.737 43.344 4.129 45.192 ;
     RECT  3.737 39.552 4.169 42.168 ;
     RECT  4.129 43.344 4.201 45.384 ;
     RECT  4.124 46.656 4.201 47.112 ;
     RECT  4.093 32.064 4.261 38.184 ;
     RECT  3.973 69.024 4.273 71.352 ;
     RECT  3.305 12.816 4.345 17.496 ;
     RECT  3.059 21.408 4.345 23.64 ;
     RECT  4.273 69.024 4.357 71.832 ;
     RECT  4.201 43.344 4.403 47.112 ;
     RECT  3.557 57.552 4.453 60.696 ;
     RECT  4.169 40.704 4.457 42.168 ;
     RECT  4.345 20.736 4.489 23.64 ;
     RECT  2.704 25.2 4.489 30.744 ;
     RECT  3.971 11.376 4.501 11.4 ;
     RECT  4.345 12.528 4.501 17.496 ;
     RECT  3.635 65.808 4.501 67.896 ;
     RECT  3.971 9.312 4.529 10.248 ;
     RECT  3.305 18.48 4.561 19.032 ;
     RECT  3.884 73.392 4.561 75.144 ;
     RECT  4.489 20.736 4.597 30.744 ;
     RECT  3.769 48.384 4.645 54.504 ;
     RECT  4.561 73.392 4.669 75.528 ;
     RECT  3.733 79.2 4.693 79.272 ;
     RECT  4.457 40.848 4.705 42.168 ;
     RECT  4.453 57.456 4.741 60.696 ;
     RECT  3.989 61.728 4.741 64.152 ;
     RECT  4.597 20.736 4.777 30.84 ;
     RECT  4.261 32.064 4.777 38.52 ;
     RECT  4.645 48.24 4.777 54.504 ;
     RECT  2.963 55.536 4.777 55.896 ;
     RECT  2.801 77.424 4.813 77.448 ;
     RECT  4.501 11.376 4.817 17.496 ;
     RECT  4.693 80.256 4.817 80.28 ;
     RECT  4.777 48.24 4.993 55.896 ;
     RECT  4.501 65.808 5.029 67.944 ;
     RECT  4.357 69.024 5.029 71.208 ;
     RECT  4.813 77.184 5.029 77.448 ;
     RECT  4.693 78.624 5.029 79.272 ;
     RECT  4.669 73.152 5.065 75.528 ;
     RECT  4.403 43.44 5.101 47.112 ;
     RECT  4.993 48.24 5.101 55.992 ;
     RECT  5.029 76.944 5.101 77.448 ;
     RECT  5.029 78.432 5.101 79.272 ;
     RECT  4.741 57.456 5.125 64.152 ;
     RECT  5.101 43.44 5.137 55.992 ;
     RECT  5.125 57.456 5.137 64.584 ;
     RECT  5.029 65.808 5.137 71.208 ;
     RECT  4.561 18.48 5.173 19.368 ;
     RECT  4.777 20.736 5.173 38.52 ;
     RECT  5.101 76.944 5.209 79.272 ;
     RECT  5.173 18.48 5.245 38.52 ;
     RECT  4.169 39.552 5.245 39.72 ;
     RECT  5.137 57.456 5.245 71.208 ;
     RECT  5.137 43.44 5.269 56.088 ;
     RECT  5.245 57.12 5.269 71.208 ;
     RECT  5.065 72.432 5.353 75.528 ;
     RECT  5.209 76.56 5.389 79.272 ;
     RECT  4.705 40.848 5.425 42.312 ;
     RECT  5.269 43.44 5.425 71.208 ;
     RECT  5.245 18.48 5.461 39.72 ;
     RECT  5.425 40.848 5.461 71.208 ;
     RECT  4.817 12.816 5.509 17.496 ;
     RECT  5.461 18.48 5.509 71.208 ;
     RECT  5.509 12.816 5.555 71.208 ;
     RECT  5.555 12.816 5.645 18.744 ;
     RECT  4.817 11.376 5.749 11.4 ;
     RECT  5.677 8.304 5.893 8.328 ;
     RECT  4.529 9.312 5.893 9.816 ;
     RECT  5.749 11.136 5.989 11.4 ;
     RECT  5.645 12.816 5.989 18.504 ;
     RECT  5.893 8.304 6.073 9.816 ;
     RECT  5.989 11.136 6.073 18.504 ;
     RECT  6.073 8.304 6.083 18.504 ;
     RECT  5.555 19.824 6.661 71.208 ;
     RECT  5.353 72.288 6.661 75.528 ;
     RECT  6.083 9.312 6.797 18.504 ;
     RECT  6.661 19.824 6.901 75.528 ;
     RECT  5.389 76.512 6.901 79.272 ;
     RECT  6.797 10.848 6.937 18.504 ;
     RECT  6.901 19.824 6.937 79.272 ;
     RECT  5.653 1.632 6.949 1.656 ;
     RECT  6.229 82.416 7.669 82.44 ;
     RECT  6.949 1.632 7.808 1.704 ;
     RECT  6.083 8.304 7.808 8.328 ;
     RECT  6.797 9.312 7.808 9.624 ;
     RECT  6.937 10.848 7.808 79.272 ;
     RECT  7.669 82.416 7.808 82.488 ;
     RECT  4.837 84.048 7.808 84.072 ;
     RECT  7.808 1.632 7.912 84.252 ;
     RECT  7.912 1.632 8.104 84.072 ;
     RECT  8.104 8.304 8.237 80.424 ;
     RECT  8.237 67.92 8.741 80.424 ;
     RECT  8.104 1.632 9.109 1.704 ;
     RECT  8.741 67.92 9.203 79.848 ;
     RECT  8.104 7.2 9.253 7.224 ;
     RECT  8.237 8.304 9.541 66.792 ;
     RECT  9.541 8.304 9.589 66.84 ;
     RECT  9.203 67.92 9.589 73.128 ;
     RECT  8.104 84.048 9.781 84.072 ;
     RECT  9.203 74.208 9.836 79.848 ;
     RECT  9.836 74.208 9.923 80.28 ;
     RECT  9.253 6.816 10.069 7.224 ;
     RECT  9.589 8.256 10.069 73.128 ;
     RECT  10.069 6.816 10.741 73.128 ;
     RECT  9.923 74.208 10.741 79.848 ;
     RECT  10.549 3.936 10.885 3.96 ;
     RECT  10.693 5.232 10.885 5.256 ;
     RECT  9.109 1.632 11.317 2.52 ;
     RECT  11.317 1.632 11.365 2.568 ;
     RECT  8.104 82.416 11.365 82.488 ;
     RECT  9.781 84.048 11.461 84.456 ;
     RECT  10.741 6.816 11.653 79.848 ;
     RECT  11.653 6.624 11.657 79.848 ;
     RECT  11.657 12.384 11.729 79.848 ;
     RECT  11.365 1.584 11.749 2.568 ;
     RECT  10.885 3.936 11.749 5.256 ;
     RECT  11.461 84.048 11.845 84.696 ;
     RECT  11.749 1.584 12.373 5.256 ;
     RECT  11.657 6.624 12.373 11.208 ;
     RECT  12.373 1.584 12.841 11.208 ;
     RECT  11.729 12.528 12.841 79.848 ;
     RECT  12.841 1.584 13.208 79.848 ;
     RECT  11.365 81.648 13.208 82.488 ;
     RECT  11.845 83.52 13.208 84.696 ;
     RECT  13.208 1.584 13.504 84.696 ;
     RECT  13.504 1.584 14.725 82.488 ;
     RECT  13.504 83.52 14.725 84.696 ;
     RECT  14.725 1.584 15.157 84.696 ;
     RECT  15.157 1.584 16.405 84.84 ;
     RECT  16.405 1.584 19.045 85.32 ;
     RECT  19.045 1.584 19.525 85.368 ;
     RECT  19.525 1.584 21.349 85.416 ;
     RECT  21.349 1.584 21.829 86.184 ;
     RECT  21.829 1.584 22.777 86.232 ;
     RECT  22.777 0.816 23.569 86.232 ;
     RECT  23.569 0.576 23.605 86.232 ;
     RECT  23.605 0.432 24.361 86.232 ;
     RECT  24.361 0.192 25.715 86.232 ;
     RECT  25.715 0.432 26.435 86.232 ;
     RECT  26.435 0.576 27.587 86.232 ;
     RECT  27.587 1.056 28.019 86.232 ;
     RECT  28.019 1.2 28.145 86.232 ;
     RECT  29.173 0.288 29.221 0.312 ;
     RECT  29.221 0.288 29.701 0.408 ;
     RECT  29.701 0.192 29.909 0.408 ;
     RECT  28.145 1.488 30.133 86.232 ;
     RECT  30.133 1.152 30.809 86.232 ;
     RECT  30.809 1.152 32.483 86.136 ;
     RECT  32.483 1.152 32.537 85.512 ;
     RECT  32.537 1.584 33.437 85.512 ;
     RECT  33.437 1.584 34.165 77.928 ;
     RECT  34.165 0.864 34.765 77.928 ;
     RECT  33.437 78.912 34.765 85.512 ;
     RECT  34.765 0.864 35.029 85.512 ;
     RECT  35.029 0.816 35.075 85.512 ;
     RECT  35.075 0.816 36.325 85.416 ;
     RECT  36.325 0.816 36.449 85.512 ;
     RECT  36.449 0.24 36.493 85.512 ;
     RECT  36.493 0.144 36.961 85.512 ;
     RECT  36.961 0.144 38.387 85.608 ;
     RECT  38.387 78.96 39.107 85.608 ;
     RECT  39.107 81.888 39.395 85.608 ;
     RECT  39.395 81.888 39.539 85.416 ;
     RECT  38.387 0.144 40.057 77.976 ;
     RECT  39.107 78.96 40.057 80.904 ;
     RECT  40.057 0.144 40.208 80.904 ;
     RECT  39.539 81.888 40.208 85.368 ;
     RECT  40.208 0.144 40.504 85.368 ;
     RECT  40.504 78.96 40.565 80.904 ;
     RECT  40.504 0.144 40.643 77.976 ;
     RECT  40.504 84.336 40.643 85.368 ;
     RECT  40.643 84.96 40.645 85.368 ;
     RECT  40.504 81.888 40.781 83.016 ;
     RECT  40.781 81.888 40.835 82.536 ;
     RECT  40.565 79.2 41.123 80.904 ;
     RECT  40.643 0.144 41.141 77.4 ;
     RECT  40.645 84.96 41.411 85.512 ;
     RECT  41.411 85.248 41.699 85.512 ;
     RECT  41.699 85.344 41.843 85.512 ;
     RECT  41.843 85.488 41.987 85.512 ;
     RECT  41.123 79.2 42.077 80.376 ;
     RECT  42.077 79.2 42.131 79.224 ;
     RECT  41.141 0.192 42.289 77.4 ;
     RECT  40.835 81.888 42.419 82.488 ;
     RECT  42.289 0.144 42.505 77.4 ;
     RECT  42.505 0.144 42.541 77.784 ;
     RECT  42.541 0.144 42.545 78.12 ;
     RECT  42.077 80.352 42.563 80.376 ;
     RECT  42.419 82.08 42.707 82.488 ;
     RECT  42.545 0.144 42.755 76.488 ;
     RECT  42.545 77.568 42.797 78.12 ;
     RECT  42.707 82.08 42.851 82.104 ;
     RECT  42.755 0.144 45.025 76.248 ;
     RECT  42.797 77.568 45.025 77.592 ;
     RECT  45.025 0.144 45.608 77.592 ;
     RECT  45.608 0.144 45.712 84.252 ;
     RECT  45.712 0.144 45.904 83.982 ;
     RECT  45.904 0.144 47.153 77.592 ;
     RECT  47.153 77.568 47.891 77.592 ;
     RECT  47.153 0.144 48.193 76.344 ;
     RECT  48.193 0.144 48.373 76.536 ;
     RECT  48.373 0.144 48.773 76.584 ;
     RECT  49.993 77.568 50.137 77.592 ;
     RECT  50.137 77.52 50.389 77.592 ;
     RECT  48.773 0.144 50.461 76.392 ;
     RECT  50.389 77.424 50.461 77.592 ;
     RECT  50.461 0.144 51.008 77.592 ;
     RECT  51.008 0.144 51.112 84.252 ;
     RECT  51.112 0.144 51.304 83.982 ;
     RECT  51.304 0.144 51.833 76.632 ;
     RECT  51.833 0.144 51.949 3.48 ;
     RECT  51.833 4.464 52.549 76.632 ;
     RECT  52.501 77.808 52.549 77.832 ;
     RECT  52.549 4.464 52.909 77.832 ;
     RECT  52.909 4.464 53.093 78.072 ;
     RECT  51.949 0.144 54.277 3.432 ;
     RECT  53.093 4.464 54.277 76.968 ;
     RECT  53.093 78.048 54.893 78.072 ;
     RECT  54.277 0.144 55.717 76.968 ;
     RECT  55.717 0.144 55.969 77.592 ;
     RECT  55.969 0.144 56.408 77.928 ;
     RECT  56.408 0.144 56.512 84.252 ;
     RECT  56.512 0.144 56.704 83.982 ;
     RECT  56.704 76.848 56.909 77.592 ;
     RECT  56.704 0.144 58.417 75.768 ;
     RECT  56.909 76.944 58.417 77.592 ;
     RECT  58.417 0.144 58.961 77.592 ;
     RECT  58.961 77.568 59.573 77.592 ;
     RECT  58.961 0.144 60.613 76.248 ;
     RECT  60.613 0.144 60.973 77.112 ;
     RECT  60.973 0.144 60.977 77.4 ;
     RECT  60.977 0.192 61.553 77.4 ;
     RECT  61.553 0.288 61.808 77.4 ;
     RECT  61.808 0.288 61.912 84.252 ;
     RECT  61.912 0.288 62.104 83.982 ;
     RECT  62.104 0.288 62.597 77.4 ;
     RECT  62.597 0.288 62.741 76.776 ;
     RECT  62.741 0.288 64.249 75.768 ;
     RECT  62.741 76.752 64.249 76.776 ;
     RECT  64.249 0.288 64.501 76.776 ;
     RECT  64.501 0.288 64.577 77.256 ;
     RECT  64.577 0.768 64.865 77.256 ;
     RECT  64.865 0.816 65.401 77.256 ;
     RECT  65.401 0.816 65.905 77.352 ;
     RECT  65.905 0.816 65.989 77.544 ;
     RECT  65.989 0.816 67.045 77.352 ;
     RECT  67.045 0.288 67.187 77.352 ;
     RECT  67.187 0.816 67.208 77.352 ;
     RECT  67.208 0.816 67.312 84.252 ;
     RECT  67.312 0.816 67.504 83.982 ;
     RECT  67.504 0.816 67.667 77.064 ;
     RECT  67.667 0.816 68.177 76.584 ;
     RECT  68.177 0.816 70.333 64.248 ;
     RECT  68.177 65.232 70.657 76.584 ;
     RECT  70.333 0.192 70.835 64.248 ;
     RECT  70.835 0.816 70.979 64.248 ;
     RECT  70.979 0.816 71.129 1.032 ;
     RECT  70.979 2.352 71.345 64.248 ;
     RECT  71.129 1.008 71.561 1.032 ;
     RECT  71.345 2.352 72.608 63.528 ;
     RECT  70.657 65.232 72.608 77.16 ;
     RECT  72.608 2.148 72.712 63.528 ;
     RECT  72.608 65.232 72.712 84.252 ;
     RECT  72.712 65.232 72.745 83.982 ;
     RECT  72.745 64.944 72.904 83.982 ;
     RECT  72.712 2.352 72.965 63.528 ;
     RECT  72.904 64.944 73.043 65.256 ;
     RECT  72.904 77.52 73.225 77.544 ;
     RECT  72.904 66.24 73.253 76.488 ;
     RECT  73.253 66.24 73.361 75.432 ;
     RECT  73.361 73.536 73.549 75.432 ;
     RECT  73.549 73.536 73.577 75.288 ;
     RECT  73.577 73.536 73.721 74.664 ;
     RECT  73.361 66.24 73.763 72.456 ;
     RECT  73.763 66.24 73.859 71.64 ;
     RECT  72.965 2.352 74.005 5.736 ;
     RECT  72.965 6.96 74.005 63.528 ;
     RECT  73.721 73.536 74.341 74.568 ;
     RECT  73.253 76.464 74.387 76.488 ;
     RECT  74.005 2.352 74.549 63.528 ;
     RECT  73.859 69.504 74.693 71.64 ;
     RECT  73.859 66.24 74.945 68.376 ;
     RECT  74.693 69.84 75.053 71.64 ;
     RECT  74.341 72.672 75.157 74.568 ;
     RECT  75.157 72.672 75.203 75.384 ;
     RECT  75.203 75.36 75.244 75.384 ;
     RECT  75.053 70.416 75.269 71.64 ;
     RECT  74.945 66.24 75.377 67.56 ;
     RECT  75.203 72.672 75.521 74.184 ;
     RECT  75.377 66.24 75.881 67.272 ;
     RECT  75.521 73.248 75.881 74.184 ;
     RECT  75.805 68.928 75.917 69.048 ;
     RECT  75.917 68.928 75.923 68.952 ;
     RECT  75.269 70.416 75.923 71.256 ;
     RECT  75.881 73.248 75.923 74.088 ;
     RECT  75.923 71.232 75.989 71.256 ;
     RECT  75.923 73.248 76.565 73.272 ;
     RECT  75.881 66.576 76.853 67.272 ;
     RECT  74.549 2.736 78.008 63.528 ;
     RECT  73.043 65.232 78.008 65.256 ;
     RECT  76.853 66.576 78.008 66.6 ;
     RECT  78.008 2.148 78.112 63.528 ;
     RECT  78.008 65.232 78.112 84.252 ;
     RECT  78.112 2.418 78.304 63.528 ;
     RECT  78.112 65.232 78.304 83.982 ;
     RECT  78.304 2.736 82.433 63.528 ;
     RECT  82.433 2.736 83.408 15.192 ;
     RECT  82.433 16.272 83.408 63.528 ;
     RECT  78.304 65.232 83.408 65.256 ;
     RECT  78.304 66.576 83.408 66.6 ;
     RECT  83.408 2.148 83.512 63.528 ;
     RECT  83.408 65.232 83.512 84.252 ;
     RECT  83.512 2.418 83.704 63.528 ;
     RECT  83.512 65.232 83.704 83.982 ;
     RECT  83.704 2.736 86.717 63.528 ;
     RECT  86.717 5.184 86.789 63.528 ;
     RECT  86.789 5.184 87.757 17.736 ;
     RECT  86.789 18.768 87.757 63.528 ;
     RECT  83.704 65.232 88.067 65.256 ;
     RECT  86.717 2.736 88.808 4.152 ;
     RECT  87.757 5.184 88.808 63.528 ;
     RECT  83.704 66.576 88.808 66.6 ;
     RECT  88.808 2.148 88.912 63.528 ;
     RECT  88.808 65.598 88.912 84.252 ;
     RECT  88.912 2.418 89.104 63.528 ;
     RECT  88.912 65.598 89.104 83.982 ;
     RECT  89.104 5.184 90.101 63.528 ;
     RECT  90.101 5.184 90.137 17.448 ;
     RECT  90.101 18.432 90.137 63.528 ;
     RECT  90.137 18.48 90.389 63.528 ;
     RECT  90.137 9.552 90.497 17.448 ;
     RECT  90.497 11.376 90.611 17.448 ;
     RECT  90.497 9.552 90.803 10.392 ;
     RECT  90.137 5.184 91.073 8.52 ;
     RECT  90.803 9.6 91.253 10.392 ;
     RECT  90.611 11.424 91.465 17.448 ;
     RECT  90.389 18.912 91.465 63.528 ;
     RECT  91.073 5.184 92.041 8.472 ;
     RECT  91.253 9.6 92.041 10.296 ;
     RECT  91.465 11.424 92.125 63.528 ;
     RECT  92.041 5.184 92.365 10.296 ;
     RECT  92.125 11.424 92.365 19.368 ;
     RECT  92.365 5.184 92.369 19.368 ;
     RECT  92.369 5.184 92.764 15.336 ;
     RECT  92.764 10.944 92.765 15.336 ;
     RECT  92.765 11.424 92.837 15.336 ;
     RECT  92.837 11.424 94.028 14.664 ;
     RECT  94.028 10.944 94.049 14.664 ;
     RECT  92.764 5.184 94.057 9.864 ;
     RECT  94.049 10.848 94.057 14.856 ;
     RECT  89.104 2.736 94.208 4.152 ;
     RECT  94.057 5.184 94.208 14.856 ;
     RECT  92.369 16.512 94.208 19.368 ;
     RECT  92.125 20.352 94.208 63.528 ;
     RECT  89.104 66.576 94.208 66.6 ;
     RECT  94.208 2.148 94.312 63.528 ;
     RECT  94.208 65.868 94.312 84.252 ;
     RECT  94.312 65.868 94.4 83.982 ;
     RECT  94.312 2.418 94.504 63.528 ;
     RECT  94.4 65.598 94.504 83.982 ;
     RECT  94.504 5.184 94.637 14.856 ;
     RECT  94.637 11.424 94.684 14.856 ;
     RECT  94.637 5.184 94.752 10.44 ;
     RECT  94.752 10.272 94.817 10.44 ;
     RECT  94.684 11.424 94.889 14.76 ;
     RECT  94.752 5.184 94.961 9.048 ;
     RECT  94.889 11.424 95.321 11.496 ;
     RECT  94.817 10.272 95.645 10.296 ;
     RECT  95.321 11.472 95.789 11.496 ;
     RECT  94.504 3.312 99.608 4.152 ;
     RECT  94.961 5.184 99.608 8.28 ;
     RECT  94.889 12.624 99.608 14.76 ;
     RECT  94.504 16.8 99.608 17.448 ;
     RECT  94.504 18.816 99.608 19.368 ;
     RECT  94.504 20.352 99.608 63.528 ;
     RECT  94.504 66.576 99.608 66.6 ;
     RECT  99.608 2.148 99.712 63.528 ;
     RECT  99.608 65.868 99.712 84.252 ;
     RECT  99.712 65.868 99.8 83.982 ;
     RECT  99.712 2.418 99.904 63.528 ;
     RECT  99.8 65.598 99.904 83.982 ;
     RECT  99.904 3.312 105.008 4.152 ;
     RECT  99.904 5.184 105.008 8.28 ;
     RECT  99.904 12.624 105.008 14.76 ;
     RECT  99.904 16.8 105.008 17.448 ;
     RECT  99.904 18.816 105.008 19.368 ;
     RECT  99.904 20.352 105.008 63.528 ;
     RECT  99.904 66.576 105.008 66.6 ;
     RECT  105.008 2.148 105.112 63.528 ;
     RECT  105.008 65.868 105.112 84.252 ;
     RECT  105.112 65.868 105.2 83.982 ;
     RECT  105.112 2.418 105.304 63.528 ;
     RECT  105.2 65.598 105.304 83.982 ;
     RECT  105.304 3.312 110.408 4.152 ;
     RECT  105.304 5.184 110.408 8.28 ;
     RECT  105.304 12.624 110.408 14.76 ;
     RECT  105.304 16.8 110.408 17.448 ;
     RECT  105.304 18.816 110.408 19.368 ;
     RECT  105.304 20.352 110.408 63.528 ;
     RECT  105.304 66.576 110.408 66.6 ;
     RECT  110.408 2.148 110.512 63.528 ;
     RECT  110.408 65.868 110.512 84.252 ;
     RECT  110.512 65.868 110.6 83.982 ;
     RECT  110.512 2.418 110.704 63.528 ;
     RECT  110.6 65.598 110.704 83.982 ;
     RECT  110.704 3.312 115.808 4.152 ;
     RECT  110.704 5.184 115.808 8.28 ;
     RECT  110.704 12.624 115.808 14.76 ;
     RECT  110.704 16.8 115.808 17.448 ;
     RECT  110.704 18.816 115.808 19.368 ;
     RECT  110.704 20.352 115.808 63.528 ;
     RECT  110.704 66.576 115.808 66.6 ;
     RECT  115.808 2.148 115.912 63.528 ;
     RECT  115.808 65.868 115.912 84.252 ;
     RECT  115.912 65.868 116 83.982 ;
     RECT  115.912 2.418 116.104 63.528 ;
     RECT  116 65.598 116.104 83.982 ;
     RECT  116.104 16.8 116.915 17.448 ;
     RECT  116.104 12.624 117.011 14.76 ;
     RECT  117.011 12.624 117.059 14.184 ;
     RECT  116.104 20.352 117.216 63.528 ;
     RECT  116.915 17.424 117.347 17.448 ;
     RECT  117.216 20.352 117.425 62.424 ;
     RECT  117.425 40.992 117.461 41.016 ;
     RECT  117.425 47.328 117.461 58.2 ;
     RECT  117.425 23.424 117.713 39.384 ;
     RECT  117.425 20.352 117.779 22.392 ;
     RECT  117.779 20.352 117.827 22.296 ;
     RECT  117.713 23.424 117.857 28.056 ;
     RECT  117.827 20.352 118.019 22.152 ;
     RECT  117.461 47.328 118.037 56.76 ;
     RECT  117.857 23.424 118.067 27.96 ;
     RECT  117.425 60.384 118.073 62.136 ;
     RECT  116.104 18.816 118.115 19.368 ;
     RECT  118.115 19.104 118.259 19.368 ;
     RECT  117.713 29.088 118.433 39.384 ;
     RECT  117.461 58.08 118.609 58.2 ;
     RECT  117.425 59.232 118.609 59.352 ;
     RECT  117.425 42.144 118.613 46.2 ;
     RECT  118.609 58.08 118.613 59.352 ;
     RECT  118.019 20.352 118.643 22.056 ;
     RECT  116.104 5.184 118.691 8.28 ;
     RECT  118.691 5.472 118.739 8.28 ;
     RECT  118.739 5.472 118.787 5.832 ;
     RECT  118.433 29.088 118.787 29.64 ;
     RECT  118.643 20.352 118.835 21.288 ;
     RECT  116.104 3.312 118.931 4.152 ;
     RECT  118.433 31.008 118.931 39.384 ;
     RECT  118.931 32.544 118.937 39.384 ;
     RECT  118.937 33.024 119.117 39.384 ;
     RECT  118.613 42.144 119.117 42.936 ;
     RECT  118.613 44.544 119.117 44.568 ;
     RECT  118.613 45.6 119.117 46.2 ;
     RECT  118.037 47.328 119.117 54.168 ;
     RECT  118.835 20.352 119.171 20.952 ;
     RECT  119.117 51.84 119.189 54.168 ;
     RECT  118.613 58.08 119.297 59.256 ;
     RECT  118.739 6.96 119.363 8.28 ;
     RECT  119.117 33.024 119.369 37.656 ;
     RECT  118.037 55.2 119.369 56.76 ;
     RECT  117.059 12.624 119.411 14.136 ;
     RECT  118.787 5.808 119.459 5.832 ;
     RECT  119.369 33.12 119.477 37.656 ;
     RECT  119.189 52.128 119.549 54.168 ;
     RECT  119.549 52.8 119.585 54.168 ;
     RECT  119.297 58.608 119.585 59.256 ;
     RECT  118.073 60.384 119.585 62.04 ;
     RECT  119.117 42.144 119.621 42.168 ;
     RECT  119.117 48.96 119.621 48.984 ;
     RECT  119.585 53.184 119.657 54.072 ;
     RECT  119.369 55.2 119.657 55.224 ;
     RECT  119.369 56.352 119.657 56.76 ;
     RECT  119.585 61.248 119.657 62.04 ;
     RECT  119.171 20.832 119.747 20.952 ;
     RECT  118.067 23.616 119.765 27.96 ;
     RECT  119.477 34.272 119.765 37.656 ;
     RECT  119.363 6.96 119.795 7.752 ;
     RECT  118.259 19.104 119.801 19.128 ;
     RECT  119.765 34.272 119.801 35.832 ;
     RECT  119.765 23.616 119.837 27.864 ;
     RECT  119.411 12.624 119.843 13.464 ;
     RECT  119.795 6.96 119.891 6.984 ;
     RECT  119.837 23.616 119.891 27.672 ;
     RECT  119.765 36.864 119.909 37.56 ;
     RECT  119.909 36.864 119.945 37.368 ;
     RECT  119.801 34.272 119.981 34.968 ;
     RECT  119.981 34.272 120.017 34.392 ;
     RECT  118.931 31.008 120.053 31.512 ;
     RECT  120.053 31.008 120.089 31.128 ;
     RECT  119.945 36.864 120.089 36.888 ;
     RECT  118.931 4.128 121.208 4.152 ;
     RECT  119.843 13.44 121.208 13.464 ;
     RECT  119.747 20.832 121.208 20.904 ;
     RECT  119.891 23.712 121.208 27.672 ;
     RECT  118.787 29.088 121.208 29.592 ;
     RECT  120.089 31.104 121.208 31.128 ;
     RECT  119.477 33.12 121.208 33.144 ;
     RECT  120.017 34.368 121.208 34.392 ;
     RECT  116.104 66.576 121.208 66.6 ;
     RECT  121.208 2.148 121.312 84.252 ;
     RECT  121.312 2.418 121.504 83.982 ;
     RECT  121.504 4.128 121.565 4.152 ;
     RECT  121.504 25.008 121.601 25.848 ;
     RECT  121.601 25.008 121.637 25.032 ;
     RECT  121.504 66.576 126.608 66.6 ;
     RECT  126.608 2.148 126.712 84.252 ;
     RECT  126.712 2.418 126.904 83.982 ;
     RECT  126.904 66.576 132.008 66.6 ;
     RECT  132.008 2.148 132.112 84.252 ;
     RECT  132.112 2.418 132.304 83.982 ;
     RECT  132.304 66.576 137.408 66.6 ;
     RECT  137.408 2.148 137.512 84.252 ;
     RECT  137.512 2.418 137.704 83.982 ;
     RECT  137.704 66.576 139.637 66.6 ;
    LAYER M5 ;
     RECT  24.528 0.144 61.272 0.227 ;
     RECT  24.672 0.227 61.272 0.851 ;
     RECT  26.112 0.851 61.272 1.523 ;
     RECT  26.112 1.523 41.112 1.667 ;
     RECT  40.2 1.667 41.112 1.715 ;
     RECT  42.816 1.523 61.272 1.715 ;
     RECT  42.816 1.715 49.608 1.763 ;
     RECT  50.592 1.715 61.272 1.763 ;
     RECT  24.672 0.851 24.984 1.859 ;
     RECT  63.024 1.957 63.048 2.099 ;
     RECT  6.96 1.669 6.984 2.137 ;
     RECT  18.192 2.053 18.216 2.137 ;
     RECT  50.88 1.763 61.272 2.137 ;
     RECT  2.4 2.137 2.52 2.151 ;
     RECT  6.96 2.137 7.92 2.151 ;
     RECT  13.2 2.137 13.32 2.151 ;
     RECT  18.192 2.137 18.72 2.151 ;
     RECT  50.88 2.137 61.92 2.151 ;
     RECT  72.6 2.137 72.72 2.151 ;
     RECT  78 2.137 78.12 2.151 ;
     RECT  83.4 2.137 83.52 2.151 ;
     RECT  88.8 2.137 88.92 2.151 ;
     RECT  94.2 2.137 94.32 2.151 ;
     RECT  99.6 2.137 99.72 2.151 ;
     RECT  105 2.137 105.12 2.151 ;
     RECT  110.4 2.137 110.52 2.151 ;
     RECT  115.8 2.137 115.92 2.151 ;
     RECT  121.2 2.137 121.32 2.151 ;
     RECT  126.6 2.137 126.72 2.151 ;
     RECT  132 2.137 132.12 2.151 ;
     RECT  137.4 2.137 137.52 2.151 ;
     RECT  42.816 1.763 49.176 2.195 ;
     RECT  26.112 1.667 38.952 2.387 ;
     RECT  50.88 2.151 62.112 2.387 ;
     RECT  60.528 2.387 62.112 2.531 ;
     RECT  11.376 1.573 11.4 2.533 ;
     RECT  46.992 2.195 49.176 2.579 ;
     RECT  47.28 2.579 49.176 2.771 ;
     RECT  20.208 2.725 20.232 2.773 ;
     RECT  42.816 2.195 45.912 2.773 ;
     RECT  42.288 2.773 45.912 2.819 ;
     RECT  42.288 2.819 42.312 2.821 ;
     RECT  26.112 2.387 31.032 2.867 ;
     RECT  18.192 2.151 18.912 2.869 ;
     RECT  20.208 2.773 21 2.869 ;
     RECT  26.112 2.867 27.288 2.915 ;
     RECT  28.416 2.867 31.032 2.915 ;
     RECT  32.016 2.387 38.952 2.915 ;
     RECT  50.88 2.387 59.544 2.915 ;
     RECT  66.576 0.144 67.896 2.915 ;
     RECT  70.512 0.144 71.112 2.915 ;
     RECT  42.096 2.821 42.312 2.963 ;
     RECT  66.864 2.915 67.896 2.963 ;
     RECT  50.88 2.915 57.672 3.011 ;
     RECT  70.656 2.915 70.68 3.011 ;
     RECT  11.328 2.533 11.4 3.013 ;
     RECT  61.248 2.531 62.112 3.107 ;
     RECT  14.544 3.061 14.568 3.109 ;
     RECT  15.888 2.821 15.912 3.109 ;
     RECT  26.256 2.915 26.904 3.155 ;
     RECT  66.96 2.963 67.752 3.155 ;
     RECT  13.2 2.151 13.512 3.157 ;
     RECT  14.544 3.109 15.912 3.157 ;
     RECT  50.88 3.011 57.384 3.347 ;
     RECT  67.008 3.155 67.752 3.347 ;
     RECT  18.192 2.869 21 3.349 ;
     RECT  50.88 3.347 54.072 3.349 ;
     RECT  47.28 2.771 48.936 3.395 ;
     RECT  58.704 2.915 59.112 3.395 ;
     RECT  24 2.137 24.312 3.397 ;
     RECT  50.112 3.349 54.072 3.491 ;
     RECT  17.52 3.349 21 3.493 ;
     RECT  22.176 3.397 22.2 3.493 ;
     RECT  13.2 3.157 15.912 3.637 ;
     RECT  118.896 3.301 118.92 3.637 ;
     RECT  24 3.397 25.08 3.683 ;
     RECT  43.584 2.819 45.912 3.731 ;
     RECT  32.448 2.915 38.952 3.781 ;
     RECT  40.2 1.715 40.512 3.781 ;
     RECT  42.192 2.963 42.216 3.827 ;
     RECT  11.328 3.013 11.784 3.877 ;
     RECT  12.768 3.637 15.912 3.877 ;
     RECT  59.088 3.395 59.112 3.923 ;
     RECT  11.328 3.877 15.912 3.925 ;
     RECT  26.256 3.155 26.856 3.971 ;
     RECT  32.448 3.781 40.512 3.973 ;
     RECT  44.4 3.731 45.912 4.019 ;
     RECT  32.064 3.973 40.512 4.115 ;
     RECT  26.256 3.971 26.76 4.307 ;
     RECT  17.52 3.493 22.2 4.405 ;
     RECT  16.992 4.405 22.2 4.549 ;
     RECT  28.704 2.915 31.032 4.595 ;
     RECT  52.752 3.491 54.072 4.595 ;
     RECT  67.2 3.347 67.752 4.595 ;
     RECT  28.848 4.595 31.032 4.643 ;
     RECT  50.112 3.491 51.312 4.643 ;
     RECT  32.448 4.115 40.512 4.645 ;
     RECT  26.16 4.549 26.184 4.691 ;
     RECT  32.448 4.645 41.112 4.787 ;
     RECT  16.992 4.549 22.296 4.837 ;
     RECT  10.56 3.925 15.912 4.981 ;
     RECT  16.992 4.837 22.392 4.981 ;
     RECT  29.184 4.643 30.936 5.075 ;
     RECT  32.448 4.787 32.904 5.171 ;
     RECT  53.184 4.595 54.072 5.171 ;
     RECT  118.848 3.637 118.92 5.173 ;
     RECT  32.592 5.171 32.616 5.219 ;
     RECT  67.2 4.595 67.608 5.219 ;
     RECT  10.56 4.981 22.392 5.315 ;
     RECT  64.944 5.461 64.968 5.603 ;
     RECT  24 3.683 24.408 5.651 ;
     RECT  50.208 4.643 51.312 5.651 ;
     RECT  42.768 5.269 42.792 5.701 ;
     RECT  33.888 4.787 41.112 5.747 ;
     RECT  47.52 3.395 48.168 5.747 ;
     RECT  53.904 5.171 54.072 5.747 ;
     RECT  55.056 3.347 57.384 5.747 ;
     RECT  56.4 5.747 56.904 5.795 ;
     RECT  118.656 5.173 118.92 5.797 ;
     RECT  42.576 5.701 42.792 5.939 ;
     RECT  42.576 5.939 42.6 6.035 ;
     RECT  34.464 5.747 41.112 6.131 ;
     RECT  54.048 5.747 54.072 6.323 ;
     RECT  118.656 5.797 119.448 6.613 ;
     RECT  67.2 5.219 67.512 6.661 ;
     RECT  9.12 2.485 9.144 6.805 ;
     RECT  72.6 2.151 72.912 6.805 ;
     RECT  29.184 5.075 30.696 6.899 ;
     RECT  118.176 6.613 119.448 6.949 ;
     RECT  34.464 6.131 35.784 7.139 ;
     RECT  87.552 6.805 87.576 7.139 ;
     RECT  6.96 2.151 8.112 7.189 ;
     RECT  9.12 6.805 9.288 7.189 ;
     RECT  67.2 6.661 67.992 7.189 ;
     RECT  78 2.151 78.312 7.189 ;
     RECT  82.32 6.229 82.344 7.189 ;
     RECT  88.8 2.151 89.112 7.189 ;
     RECT  81.504 7.189 82.344 7.379 ;
     RECT  61.8 3.107 62.112 7.381 ;
     RECT  67.2 7.189 68.088 7.427 ;
     RECT  71.808 6.805 72.912 7.427 ;
     RECT  48.144 5.747 48.168 7.571 ;
     RECT  6.96 7.189 9.288 7.669 ;
     RECT  10.56 5.315 22.296 7.669 ;
     RECT  61.2 7.381 62.112 7.715 ;
     RECT  78 7.189 78.792 7.909 ;
     RECT  36.96 6.131 41.112 7.957 ;
     RECT  56.4 5.795 56.712 7.957 ;
     RECT  77.76 7.909 78.792 7.957 ;
     RECT  67.2 7.427 67.992 8.003 ;
     RECT  70.512 7.381 70.536 8.003 ;
     RECT  88.8 7.189 89.496 8.003 ;
     RECT  24 5.651 24.312 8.005 ;
     RECT  77.472 7.957 78.792 8.005 ;
     RECT  48.768 7.957 48.792 8.099 ;
     RECT  76.896 8.005 78.792 8.101 ;
     RECT  24 8.005 24.6 8.195 ;
     RECT  26.784 8.005 26.808 8.195 ;
     RECT  91.2 7.381 91.224 8.197 ;
     RECT  36.96 7.957 41.784 8.243 ;
     RECT  72.6 7.427 72.912 8.437 ;
     RECT  5.664 1.621 5.688 8.485 ;
     RECT  6.96 7.669 22.296 8.485 ;
     RECT  76.32 8.101 78.792 8.485 ;
     RECT  80.256 7.909 80.28 8.675 ;
     RECT  82.32 7.379 82.344 8.677 ;
     RECT  83.4 2.151 83.712 8.677 ;
     RECT  34.56 7.139 35.784 8.723 ;
     RECT  85.056 6.805 85.08 8.821 ;
     RECT  94.2 2.151 94.512 8.821 ;
     RECT  24 8.195 24.312 8.965 ;
     RECT  68.832 8.725 68.856 8.965 ;
     RECT  85.008 8.821 85.08 8.965 ;
     RECT  51 5.651 51.312 9.013 ;
     RECT  87.504 8.533 87.528 9.013 ;
     RECT  88.8 8.003 89.112 9.013 ;
     RECT  82.32 8.677 83.712 9.059 ;
     RECT  29.4 6.899 30.696 9.061 ;
     RECT  36.96 8.243 41.592 9.061 ;
     RECT  43.296 8.437 43.32 9.061 ;
     RECT  45.6 4.019 45.912 9.061 ;
     RECT  56.16 7.957 56.712 9.061 ;
     RECT  67.2 8.003 67.512 9.061 ;
     RECT  68.832 8.965 68.952 9.061 ;
     RECT  75.216 8.485 78.792 9.061 ;
     RECT  87.504 9.013 89.112 9.061 ;
     RECT  90.576 8.197 91.224 9.061 ;
     RECT  23.712 8.965 24.312 9.107 ;
     RECT  74.16 7.909 74.184 9.107 ;
     RECT  61.488 7.715 62.112 9.109 ;
     RECT  36.24 9.061 41.592 9.155 ;
     RECT  42.912 9.061 43.32 9.155 ;
     RECT  75.216 9.061 79.272 9.157 ;
     RECT  64.704 8.293 64.728 9.203 ;
     RECT  52.992 8.773 53.016 9.251 ;
     RECT  72.384 8.437 72.912 9.253 ;
     RECT  45.6 9.061 46.632 9.301 ;
     RECT  61.488 9.109 63 9.349 ;
     RECT  61.44 9.349 63.336 9.397 ;
     RECT  92.544 9.061 92.568 9.397 ;
     RECT  61.44 9.397 63.528 9.493 ;
     RECT  72.384 9.253 73.032 9.493 ;
     RECT  45.6 9.301 46.728 9.587 ;
     RECT  67.2 9.061 67.608 9.589 ;
     RECT  68.64 9.061 68.952 9.589 ;
     RECT  87.504 9.061 91.224 9.589 ;
     RECT  94.08 8.821 94.512 9.589 ;
     RECT  34.56 8.723 35.208 9.635 ;
     RECT  50.88 9.013 51.312 9.637 ;
     RECT  87.168 9.589 91.224 9.637 ;
     RECT  56.16 9.061 57.384 9.731 ;
     RECT  71.664 9.493 73.032 9.733 ;
     RECT  34.56 9.635 35.112 9.781 ;
     RECT  67.2 9.589 68.952 9.781 ;
     RECT  74.88 9.157 79.272 9.781 ;
     RECT  74.88 9.781 79.8 9.827 ;
     RECT  79.776 9.827 79.8 9.829 ;
     RECT  92.496 9.397 92.568 9.829 ;
     RECT  93.984 9.589 94.512 9.829 ;
     RECT  71.28 9.733 73.032 9.875 ;
     RECT  45.6 9.587 46.632 9.877 ;
     RECT  67.2 9.781 69.144 9.923 ;
     RECT  36.24 9.155 41.16 9.971 ;
     RECT  86.688 9.637 91.224 9.973 ;
     RECT  92.496 9.829 92.712 9.973 ;
     RECT  85.008 8.965 85.512 10.019 ;
     RECT  82.32 9.059 82.344 10.021 ;
     RECT  83.4 9.059 83.712 10.021 ;
     RECT  82.32 10.021 83.712 10.117 ;
     RECT  74.88 9.827 78.792 10.163 ;
     RECT  25.728 9.877 25.752 10.165 ;
     RECT  53.088 9.589 53.112 10.165 ;
     RECT  29.4 9.061 30.84 10.213 ;
     RECT  53.088 10.165 53.64 10.213 ;
     RECT  42.912 9.155 42.936 10.261 ;
     RECT  33.936 9.781 35.112 10.307 ;
     RECT  45.504 9.877 46.632 10.307 ;
     RECT  86.688 9.973 92.712 10.307 ;
     RECT  61.008 9.493 64.392 10.309 ;
     RECT  86.688 10.307 90.024 10.355 ;
     RECT  91.68 10.307 92.712 10.355 ;
     RECT  29.4 10.213 30.984 10.403 ;
     RECT  45.6 10.307 46.632 10.403 ;
     RECT  42.912 10.261 43.752 10.453 ;
     RECT  66.096 9.013 66.12 10.453 ;
     RECT  42.912 10.453 43.848 10.501 ;
     RECT  61.008 10.309 64.968 10.547 ;
     RECT  42.912 10.501 44.04 10.643 ;
     RECT  59.184 7.957 59.208 10.693 ;
     RECT  86.688 10.355 87.816 10.739 ;
     RECT  42.912 10.643 43.848 10.787 ;
     RECT  61.008 10.547 64.632 10.787 ;
     RECT  49.968 9.637 51.312 10.789 ;
     RECT  3.84 9.301 3.864 10.837 ;
     RECT  3.84 10.837 3.96 10.883 ;
     RECT  74.88 10.163 75.24 10.883 ;
     RECT  76.368 10.163 78.792 10.883 ;
     RECT  5.664 8.485 22.296 10.933 ;
     RECT  67.2 9.923 68.952 10.933 ;
     RECT  71.328 9.875 73.032 10.979 ;
     RECT  76.416 10.883 78.792 10.981 ;
     RECT  79.776 9.829 80.136 10.981 ;
     RECT  81.792 10.117 83.712 10.981 ;
     RECT  85.008 10.019 85.368 11.027 ;
     RECT  47.664 10.789 47.688 11.077 ;
     RECT  5.664 10.933 22.824 11.125 ;
     RECT  24 9.107 24.312 11.125 ;
     RECT  25.392 10.165 25.752 11.125 ;
     RECT  58.512 10.693 59.208 11.125 ;
     RECT  36.96 9.971 41.16 11.221 ;
     RECT  5.664 11.125 24.312 11.267 ;
     RECT  25.392 11.125 25.896 11.267 ;
     RECT  71.328 10.979 72.912 11.315 ;
     RECT  3.936 10.883 3.96 11.365 ;
     RECT  27.6 10.693 27.624 11.365 ;
     RECT  29.4 10.403 30.552 11.365 ;
     RECT  58.512 11.125 59.592 11.365 ;
     RECT  88.8 10.355 90.024 11.365 ;
     RECT  34.56 10.307 35.112 11.413 ;
     RECT  56.304 9.731 57.384 11.413 ;
     RECT  58.512 11.365 59.832 11.413 ;
     RECT  36.864 11.221 41.16 11.653 ;
     RECT  56.304 11.413 59.832 11.653 ;
     RECT  45.6 10.403 46.44 11.701 ;
     RECT  91.68 10.355 92.616 11.701 ;
     RECT  67.2 10.933 69 11.749 ;
     RECT  76.416 10.981 83.712 11.749 ;
     RECT  87.168 10.739 87.816 11.749 ;
     RECT  47.664 11.077 48.12 11.795 ;
     RECT  66.048 10.453 66.12 11.797 ;
     RECT  67.2 11.749 69.672 11.797 ;
     RECT  93.984 9.829 94.68 11.797 ;
     RECT  48.096 11.795 48.12 11.939 ;
     RECT  26.592 11.365 27.624 11.941 ;
     RECT  42.912 10.787 42.936 11.941 ;
     RECT  66.048 11.797 69.672 11.941 ;
     RECT  34.56 11.413 35.64 11.989 ;
     RECT  55.44 11.653 59.832 12.035 ;
     RECT  71.328 11.315 71.592 12.037 ;
     RECT  25.392 11.267 25.416 12.083 ;
     RECT  88.8 11.365 90.6 12.227 ;
     RECT  26.592 11.941 27.912 12.275 ;
     RECT  49.584 10.789 51.312 12.275 ;
     RECT  56.4 12.035 59.832 12.275 ;
     RECT  52.416 10.213 53.64 12.277 ;
     RECT  75.216 10.883 75.24 12.277 ;
     RECT  76.416 11.749 84.216 12.277 ;
     RECT  45.504 11.701 46.44 12.323 ;
     RECT  75.216 12.277 84.216 12.323 ;
     RECT  76.896 12.323 84.216 12.467 ;
     RECT  34.176 11.989 35.64 12.517 ;
     RECT  36.864 11.653 41.832 12.517 ;
     RECT  3.936 11.365 4.536 12.563 ;
     RECT  56.4 12.275 58.2 12.563 ;
     RECT  61.008 10.787 64.44 12.565 ;
     RECT  65.712 11.941 69.672 12.565 ;
     RECT  61.008 12.565 69.672 12.707 ;
     RECT  86.976 11.749 87.816 12.709 ;
     RECT  88.8 12.227 89.88 12.709 ;
     RECT  71.28 12.037 71.592 12.757 ;
     RECT  72.6 11.315 72.912 12.757 ;
     RECT  2.4 2.151 2.712 12.805 ;
     RECT  3.936 12.563 3.96 12.805 ;
     RECT  34.176 12.517 41.832 12.899 ;
     RECT  71.28 12.757 72.912 12.901 ;
     RECT  79.776 12.467 84.216 12.947 ;
     RECT  42.912 11.941 43.416 12.949 ;
     RECT  61.008 12.707 64.44 12.949 ;
     RECT  52.32 12.277 53.64 13.045 ;
     RECT  71.28 12.901 73.752 13.045 ;
     RECT  65.712 12.707 69.672 13.091 ;
     RECT  80.928 12.947 84.216 13.091 ;
     RECT  25.632 12.517 25.656 13.139 ;
     RECT  60.864 12.949 64.44 13.139 ;
     RECT  29.4 11.365 31.032 13.141 ;
     RECT  32.112 10.789 32.136 13.141 ;
     RECT  49.824 12.275 51.312 13.141 ;
     RECT  52.32 13.045 54.312 13.141 ;
     RECT  70.992 13.045 73.752 13.235 ;
     RECT  64.272 13.139 64.44 13.283 ;
     RECT  29.4 13.141 32.136 13.285 ;
     RECT  49.824 13.141 54.312 13.285 ;
     RECT  49.824 13.285 54.744 13.331 ;
     RECT  75.216 12.323 75.816 13.331 ;
     RECT  29.28 13.285 32.136 13.333 ;
     RECT  33.12 11.941 33.144 13.333 ;
     RECT  49.824 13.331 52.44 13.379 ;
     RECT  53.424 13.331 54.744 13.427 ;
     RECT  56.4 12.563 57.432 13.427 ;
     RECT  75.216 13.331 75.72 13.429 ;
     RECT  118.176 6.949 119.88 13.429 ;
     RECT  121.2 2.151 121.512 13.429 ;
     RECT  42.912 12.949 43.896 13.475 ;
     RECT  60.864 13.139 63.288 13.475 ;
     RECT  29.28 13.333 33.144 13.477 ;
     RECT  53.424 13.427 54.312 13.523 ;
     RECT  81.792 13.091 84.216 13.573 ;
     RECT  29.184 13.477 33.144 13.619 ;
     RECT  32.112 13.619 33.144 13.667 ;
     RECT  63.12 13.475 63.288 13.667 ;
     RECT  76.896 12.467 78.792 13.669 ;
     RECT  79.776 12.947 79.8 13.669 ;
     RECT  29.184 13.619 31.032 13.715 ;
     RECT  36.864 12.899 41.832 13.715 ;
     RECT  81.792 13.573 84.36 13.715 ;
     RECT  93.984 11.797 94.776 13.715 ;
     RECT  63.216 13.667 63.288 13.763 ;
     RECT  29.184 13.715 30.888 13.765 ;
     RECT  59.184 12.275 59.832 13.811 ;
     RECT  71.52 13.235 73.752 13.813 ;
     RECT  74.88 13.429 75.72 13.813 ;
     RECT  65.712 13.091 69.288 13.859 ;
     RECT  45.6 12.323 46.44 13.909 ;
     RECT  29.136 13.765 30.888 14.005 ;
     RECT  44.256 13.957 44.28 14.053 ;
     RECT  53.424 13.523 53.592 14.147 ;
     RECT  59.184 13.811 59.592 14.147 ;
     RECT  66.048 13.859 69.288 14.147 ;
     RECT  0.528 13.621 0.552 14.149 ;
     RECT  115.8 2.151 116.112 14.149 ;
     RECT  44.256 14.053 44.616 14.195 ;
     RECT  85.344 11.027 85.368 14.195 ;
     RECT  76.896 13.669 79.8 14.243 ;
     RECT  29.088 14.005 30.888 14.245 ;
     RECT  26.736 12.275 27.912 14.291 ;
     RECT  71.52 13.813 75.72 14.291 ;
     RECT  86.976 12.709 89.88 14.291 ;
     RECT  32.112 13.667 32.136 14.339 ;
     RECT  29.04 14.245 30.888 14.341 ;
     RECT  93.984 13.715 94.728 14.387 ;
     RECT  48.432 12.901 48.456 14.485 ;
     RECT  28.608 14.341 30.888 14.579 ;
     RECT  42.912 13.475 42.936 14.581 ;
     RECT  44.256 14.195 44.28 14.581 ;
     RECT  23.664 11.267 24.312 14.677 ;
     RECT  94.08 14.387 94.728 14.723 ;
     RECT  48.096 14.485 48.456 14.725 ;
     RECT  42.912 14.581 44.28 14.771 ;
     RECT  49.968 13.379 52.44 14.771 ;
     RECT  23.664 14.677 24.552 14.773 ;
     RECT  26.736 14.291 27.624 14.773 ;
     RECT  60.864 13.475 62.112 14.867 ;
     RECT  82.32 13.715 84.36 14.867 ;
     RECT  94.08 14.723 94.632 14.867 ;
     RECT  36.864 13.715 41.784 14.915 ;
     RECT  45.6 13.909 46.488 14.915 ;
     RECT  67.2 14.147 69.288 14.915 ;
     RECT  82.32 14.867 84.216 14.915 ;
     RECT  61.104 14.867 62.112 14.917 ;
     RECT  63.216 13.763 63.24 14.917 ;
     RECT  45.6 14.915 46.152 14.963 ;
     RECT  86.976 14.291 89.832 14.963 ;
     RECT  2.4 12.805 3.96 14.965 ;
     RECT  47.76 14.725 48.456 14.965 ;
     RECT  49.968 14.771 51.72 14.965 ;
     RECT  56.4 13.427 57.336 14.965 ;
     RECT  76.896 14.243 78.312 14.965 ;
     RECT  64.272 13.283 64.344 15.011 ;
     RECT  86.976 14.963 89.496 15.013 ;
     RECT  26.064 14.773 27.624 15.059 ;
     RECT  86.592 15.013 89.496 15.059 ;
     RECT  91.632 11.701 92.616 15.059 ;
     RECT  56.4 14.965 57.816 15.107 ;
     RECT  67.2 14.915 69.192 15.107 ;
     RECT  33.12 13.667 33.144 15.109 ;
     RECT  34.176 12.899 35.736 15.109 ;
     RECT  33.12 15.109 35.736 15.155 ;
     RECT  47.76 14.965 51.72 15.155 ;
     RECT  56.4 15.107 57.72 15.157 ;
     RECT  61.104 14.917 63.24 15.203 ;
     RECT  82.32 14.915 83.712 15.203 ;
     RECT  76.608 14.965 78.312 15.251 ;
     RECT  33.6 15.155 35.736 15.299 ;
     RECT  56.304 15.157 57.72 15.299 ;
     RECT  64.608 15.013 64.632 15.299 ;
     RECT  76.608 15.251 76.92 15.299 ;
     RECT  27.504 15.059 27.624 15.347 ;
     RECT  66.048 14.147 66.072 15.349 ;
     RECT  59.184 14.147 59.304 15.395 ;
     RECT  34.176 15.299 35.736 15.443 ;
     RECT  36.96 14.915 41.784 15.443 ;
     RECT  71.52 14.291 74.904 15.443 ;
     RECT  42.912 14.771 43.224 15.491 ;
     RECT  87.744 15.059 89.208 15.539 ;
     RECT  65.664 15.349 66.072 15.541 ;
     RECT  23.664 14.773 24.888 15.587 ;
     RECT  53.424 14.147 53.448 15.589 ;
     RECT  53.424 15.589 53.496 15.731 ;
     RECT  34.272 15.443 35.736 15.779 ;
     RECT  65.04 15.541 66.072 15.827 ;
     RECT  41.76 15.443 41.784 15.877 ;
     RECT  44.256 14.771 44.28 15.877 ;
     RECT  47.76 15.155 48.696 15.877 ;
     RECT  53.424 15.731 53.448 15.877 ;
     RECT  53.232 15.877 53.448 15.925 ;
     RECT  65.664 15.827 66.072 15.925 ;
     RECT  67.2 15.107 67.608 15.925 ;
     RECT  34.56 15.779 35.736 15.971 ;
     RECT  5.664 11.267 22.344 15.973 ;
     RECT  32.448 15.493 32.472 16.019 ;
     RECT  71.52 15.443 74.712 16.019 ;
     RECT  45.6 14.963 46.008 16.021 ;
     RECT  52.848 15.925 53.448 16.067 ;
     RECT  56.304 15.299 57.336 16.067 ;
     RECT  88.032 15.539 89.208 16.117 ;
     RECT  44.016 15.877 44.28 16.213 ;
     RECT  44.016 16.213 44.376 16.453 ;
     RECT  45.6 16.021 46.152 16.453 ;
     RECT  41.76 15.877 42.504 16.499 ;
     RECT  71.52 16.019 72.912 16.499 ;
     RECT  83.4 15.203 83.712 16.501 ;
     RECT  68.64 15.107 69.192 16.547 ;
     RECT  65.664 15.925 67.608 16.595 ;
     RECT  86.592 15.059 86.616 16.595 ;
     RECT  43.92 16.453 46.152 16.691 ;
     RECT  76.608 15.299 76.632 16.693 ;
     RECT  77.904 15.251 78.312 16.693 ;
     RECT  79.344 14.243 79.8 16.693 ;
     RECT  81.024 14.773 81.048 16.789 ;
     RECT  81.024 16.789 81.288 16.835 ;
     RECT  47.232 15.877 48.696 16.837 ;
     RECT  49.968 15.155 51.72 16.837 ;
     RECT  5.664 15.973 22.44 16.885 ;
     RECT  24 15.587 24.888 16.885 ;
     RECT  88.032 16.117 89.304 16.885 ;
     RECT  47.232 16.837 51.72 16.979 ;
     RECT  76.608 16.693 79.8 16.979 ;
     RECT  2.4 14.965 4.488 16.981 ;
     RECT  5.664 16.885 24.888 16.981 ;
     RECT  25.872 16.837 25.896 16.981 ;
     RECT  83.4 16.501 83.88 16.981 ;
     RECT  84.912 16.885 84.936 16.981 ;
     RECT  83.4 16.981 84.936 17.027 ;
     RECT  52.848 16.067 53.4 17.075 ;
     RECT  2.4 16.981 25.896 17.123 ;
     RECT  29.04 14.579 30.888 17.123 ;
     RECT  33.024 16.981 33.048 17.123 ;
     RECT  84.816 17.027 84.84 17.123 ;
     RECT  88.032 16.885 89.736 17.171 ;
     RECT  91.632 15.059 92.088 17.171 ;
     RECT  76.608 16.979 78.312 17.363 ;
     RECT  115.8 14.149 117.048 17.413 ;
     RECT  118.176 13.429 121.512 17.413 ;
     RECT  41.76 16.499 41.784 17.507 ;
     RECT  44.016 16.691 46.152 17.507 ;
     RECT  79.392 16.979 79.8 17.507 ;
     RECT  36.96 15.443 40.512 17.509 ;
     RECT  66.048 16.595 67.608 17.605 ;
     RECT  25.872 17.123 25.896 17.651 ;
     RECT  44.016 17.507 44.28 17.651 ;
     RECT  68.64 16.547 69.096 17.653 ;
     RECT  70.368 13.525 70.392 17.653 ;
     RECT  61.296 15.203 63.24 17.699 ;
     RECT  65.616 17.605 67.608 17.699 ;
     RECT  74.592 16.019 74.712 17.699 ;
     RECT  88.032 17.171 89.304 17.699 ;
     RECT  88.464 17.699 89.304 17.747 ;
     RECT  45.6 17.507 46.152 17.749 ;
     RECT  47.232 16.979 48.12 17.749 ;
     RECT  59.184 15.395 59.208 17.749 ;
     RECT  65.616 17.699 65.64 17.749 ;
     RECT  29.136 17.123 30.888 17.795 ;
     RECT  45.6 17.749 48.12 17.843 ;
     RECT  36.864 17.509 40.512 17.845 ;
     RECT  44.256 17.651 44.28 17.891 ;
     RECT  5.664 17.123 24.888 17.939 ;
     RECT  45.6 17.843 46.296 17.987 ;
     RECT  68.64 17.653 70.392 17.987 ;
     RECT  23.424 17.939 24.6 18.035 ;
     RECT  59.184 17.749 59.736 18.035 ;
     RECT  29.4 17.795 30.888 18.083 ;
     RECT  74.784 17.893 74.808 18.083 ;
     RECT  36.864 17.845 41.208 18.131 ;
     RECT  88.8 17.747 89.304 18.131 ;
     RECT  34.56 15.971 35.64 18.133 ;
     RECT  5.664 17.939 22.44 18.181 ;
     RECT  56.304 16.067 57.288 18.227 ;
     RECT  24 18.035 24.6 18.275 ;
     RECT  27.504 15.347 27.528 18.275 ;
     RECT  33.888 18.133 35.64 18.275 ;
     RECT  86.544 16.981 86.568 18.275 ;
     RECT  52.848 17.075 52.872 18.373 ;
     RECT  49.968 16.979 51.72 18.661 ;
     RECT  52.848 18.373 53.016 18.661 ;
     RECT  61.8 17.699 63.24 18.661 ;
     RECT  65.04 17.749 65.64 18.757 ;
     RECT  66.96 17.699 67.512 18.757 ;
     RECT  81.264 16.835 81.288 18.757 ;
     RECT  82.32 15.203 82.344 18.757 ;
     RECT  52.8 18.661 53.016 18.803 ;
     RECT  81.264 18.757 82.344 18.805 ;
     RECT  36.864 18.131 40.512 18.899 ;
     RECT  77.28 17.363 78.312 18.899 ;
     RECT  36.864 18.899 38.232 18.947 ;
     RECT  29.4 18.083 30.744 19.045 ;
     RECT  88.8 18.131 89.208 19.237 ;
     RECT  33.888 18.275 35.352 19.331 ;
     RECT  92.064 17.171 92.088 19.333 ;
     RECT  91.152 19.333 92.088 19.427 ;
     RECT  54.24 18.181 54.264 19.475 ;
     RECT  81.072 18.805 82.344 19.475 ;
     RECT  52.992 18.803 53.016 19.523 ;
     RECT  82.32 19.475 82.344 19.571 ;
     RECT  49.872 18.661 51.72 19.667 ;
     RECT  24 18.275 24.312 19.669 ;
     RECT  33.888 19.331 35.112 19.715 ;
     RECT  81.072 19.475 81.096 19.763 ;
     RECT  24 19.669 25.128 19.811 ;
     RECT  61.8 18.661 63.432 19.811 ;
     RECT  91.152 19.427 91.176 19.811 ;
     RECT  45.6 17.987 46.152 19.813 ;
     RECT  47.856 17.843 48.12 19.813 ;
     RECT  79.776 17.507 79.8 20.003 ;
     RECT  43.872 19.333 43.896 20.051 ;
     RECT  36.96 18.947 38.232 20.053 ;
     RECT  65.04 18.757 67.512 20.099 ;
     RECT  2.4 17.123 4.536 20.149 ;
     RECT  5.52 18.181 22.44 20.149 ;
     RECT  29.4 19.045 30.888 20.197 ;
     RECT  88.032 19.237 89.208 20.339 ;
     RECT  45.6 19.813 48.12 20.387 ;
     RECT  34.08 19.715 35.112 20.485 ;
     RECT  59.184 18.035 59.208 20.963 ;
     RECT  61.8 19.811 62.52 20.965 ;
     RECT  2.4 20.149 22.44 21.061 ;
     RECT  2.4 21.061 22.584 21.155 ;
     RECT  49.872 19.667 49.896 21.253 ;
     RECT  51 19.667 51.72 21.253 ;
     RECT  49.872 21.253 51.72 21.443 ;
     RECT  27.36 21.013 27.384 21.541 ;
     RECT  60.672 21.301 60.696 21.637 ;
     RECT  61.8 20.965 62.664 21.637 ;
     RECT  67.2 20.099 67.512 21.637 ;
     RECT  68.64 17.987 69 21.637 ;
     RECT  0.528 14.149 1.032 21.973 ;
     RECT  33.072 21.061 33.096 21.973 ;
     RECT  29.4 20.197 31.464 22.021 ;
     RECT  32.736 21.973 33.096 22.021 ;
     RECT  5.664 21.155 22.584 22.165 ;
     RECT  67.2 21.637 69 22.165 ;
     RECT  70.368 17.987 70.392 22.165 ;
     RECT  5.664 22.165 22.968 22.213 ;
     RECT  24 19.811 24.312 22.213 ;
     RECT  46.992 20.387 48.12 22.213 ;
     RECT  56.4 18.227 57.288 22.213 ;
     RECT  72.6 16.499 72.912 22.213 ;
     RECT  115.8 17.413 121.512 22.403 ;
     RECT  2.4 21.155 4.536 22.789 ;
     RECT  2.4 22.789 4.584 23.701 ;
     RECT  5.664 22.213 24.312 23.701 ;
     RECT  0.48 21.973 1.032 25.477 ;
     RECT  117.144 22.403 121.512 26.627 ;
     RECT  0.48 25.477 1.128 27.877 ;
     RECT  2.4 23.701 24.312 27.877 ;
     RECT  117.144 26.627 119.736 29.315 ;
     RECT  117.144 29.315 118.92 30.083 ;
     RECT  118.656 30.083 118.92 31.811 ;
     RECT  118.704 31.811 118.92 32.195 ;
     RECT  118.8 32.195 118.92 32.387 ;
     RECT  118.8 32.387 118.872 33.347 ;
     RECT  118.8 33.347 118.824 33.731 ;
     RECT  0.48 27.877 24.312 41.365 ;
     RECT  0.288 41.365 24.312 41.507 ;
     RECT  0.48 41.507 24.312 55.571 ;
     RECT  117.144 30.083 117.24 63.528 ;
     RECT  27.36 21.541 27.96 63.733 ;
     RECT  65.04 20.099 66.12 63.875 ;
     RECT  36.72 20.053 38.232 64.019 ;
     RECT  46.992 22.213 48.744 64.117 ;
     RECT  49.872 21.443 51.312 64.117 ;
     RECT  0.912 55.571 24.312 64.213 ;
     RECT  46.992 64.117 51.312 64.259 ;
     RECT  47.856 64.259 51.312 64.403 ;
     RECT  60.672 21.637 62.664 64.403 ;
     RECT  34.08 20.485 35.448 64.451 ;
     RECT  39.216 18.899 40.512 64.451 ;
     RECT  29.4 22.021 33.096 64.547 ;
     RECT  66.096 63.875 66.12 64.739 ;
     RECT  36.72 64.019 36.744 64.787 ;
     RECT  56.4 22.213 57.864 64.837 ;
     RECT  72.6 22.213 73.032 64.979 ;
     RECT  47.856 64.403 48.12 65.027 ;
     RECT  88.032 20.339 89.112 65.267 ;
     RECT  71.52 16.499 71.544 65.555 ;
     RECT  31.344 64.547 33.096 65.603 ;
     RECT  49.584 64.403 51.312 65.603 ;
     RECT  55.152 21.925 55.176 65.603 ;
     RECT  56.208 64.837 57.864 65.603 ;
     RECT  67.2 22.165 70.392 65.603 ;
     RECT  60.672 64.403 62.52 65.843 ;
     RECT  37.776 64.019 38.232 65.987 ;
     RECT  61.536 65.843 62.52 65.987 ;
     RECT  38.208 65.987 38.232 66.035 ;
     RECT  34.08 64.451 35.112 66.179 ;
     RECT  67.2 65.603 69.288 66.181 ;
     RECT  45.6 20.387 45.912 66.229 ;
     RECT  0.912 64.213 24.792 66.323 ;
     RECT  67.056 66.181 69.288 66.323 ;
     RECT  56.208 65.603 56.712 66.325 ;
     RECT  59.232 66.037 59.256 66.421 ;
     RECT  63.6 65.701 63.624 66.469 ;
     RECT  58.848 66.421 59.256 66.707 ;
     RECT  27.36 63.733 28.056 66.755 ;
     RECT  45.6 66.229 46.008 66.755 ;
     RECT  63.6 66.469 63.96 66.755 ;
     RECT  29.4 64.547 29.712 66.901 ;
     RECT  57.84 65.603 57.864 67.045 ;
     RECT  58.848 66.707 59.112 67.045 ;
     RECT  32.16 65.603 33.096 67.237 ;
     RECT  40.2 64.451 40.512 67.237 ;
     RECT  31.296 67.237 33.096 67.283 ;
     RECT  39.36 67.237 40.512 67.285 ;
     RECT  56.16 66.325 56.712 67.285 ;
     RECT  26.208 21.589 26.232 67.333 ;
     RECT  27.36 66.755 27.912 67.333 ;
     RECT  70.752 66.085 70.776 67.333 ;
     RECT  72.6 64.979 72.912 67.333 ;
     RECT  74.64 66.757 74.664 67.333 ;
     RECT  71.904 67.333 74.664 67.381 ;
     RECT  53.808 22.117 53.832 67.429 ;
     RECT  55.488 67.285 56.712 67.429 ;
     RECT  57.84 67.045 59.112 67.477 ;
     RECT  61.8 65.987 62.52 67.573 ;
     RECT  63.6 66.755 63.624 67.573 ;
     RECT  67.2 66.323 69.288 67.573 ;
     RECT  45.6 66.755 45.912 67.669 ;
     RECT  26.208 67.333 27.912 67.715 ;
     RECT  38.688 67.285 40.512 67.715 ;
     RECT  49.872 65.603 51.312 67.765 ;
     RECT  65.232 67.717 65.256 67.765 ;
     RECT  66.576 67.573 69.288 67.765 ;
     RECT  45.12 67.669 45.912 67.861 ;
     RECT  29.4 66.901 30.168 67.909 ;
     RECT  61.8 67.573 63.624 67.909 ;
     RECT  47.856 65.027 47.88 67.957 ;
     RECT  49.44 67.765 51.312 67.957 ;
     RECT  53.808 67.429 56.712 68.005 ;
     RECT  57.696 67.477 59.112 68.005 ;
     RECT  29.088 67.909 30.168 68.051 ;
     RECT  65.232 67.765 69.288 68.053 ;
     RECT  70.656 67.333 70.776 68.053 ;
     RECT  37.152 66.901 37.176 68.099 ;
     RECT  45.024 67.861 45.912 68.101 ;
     RECT  47.856 67.957 51.312 68.101 ;
     RECT  45.024 68.101 46.056 68.195 ;
     RECT  61.536 67.909 63.72 68.197 ;
     RECT  34.8 66.179 35.112 68.293 ;
     RECT  53.808 68.005 59.112 68.341 ;
     RECT  61.536 68.197 63.864 68.341 ;
     RECT  53.568 68.341 59.112 68.389 ;
     RECT  61.248 68.341 63.864 68.485 ;
     RECT  65.232 68.053 70.776 68.485 ;
     RECT  71.808 67.381 74.664 68.485 ;
     RECT  31.296 67.283 31.32 68.629 ;
     RECT  40.2 67.715 40.512 68.629 ;
     RECT  61.2 68.485 63.864 68.629 ;
     RECT  34.704 68.293 35.112 68.675 ;
     RECT  31.2 68.629 31.32 68.771 ;
     RECT  40.2 68.629 40.872 68.771 ;
     RECT  45.312 68.195 46.056 68.867 ;
     RECT  33.072 67.283 33.096 68.917 ;
     RECT  45.6 68.867 46.056 68.917 ;
     RECT  47.856 68.101 52.296 68.917 ;
     RECT  53.568 68.389 60.024 68.963 ;
     RECT  43.584 20.869 43.608 69.059 ;
     RECT  38.688 67.715 38.712 69.107 ;
     RECT  31.296 68.771 31.32 69.157 ;
     RECT  43.296 69.157 43.32 69.299 ;
     RECT  27.312 67.715 27.912 69.301 ;
     RECT  65.232 68.485 74.664 69.395 ;
     RECT  27.312 69.301 28.248 69.443 ;
     RECT  53.568 68.963 58.728 69.491 ;
     RECT  34.8 68.675 35.112 69.493 ;
     RECT  54.048 69.491 58.728 69.539 ;
     RECT  61.2 68.629 63.96 69.541 ;
     RECT  65.232 69.395 70.104 69.541 ;
     RECT  47.856 68.917 52.584 69.635 ;
     RECT  32.976 68.917 33.096 69.733 ;
     RECT  71.28 69.395 74.664 69.829 ;
     RECT  75.888 68.917 75.912 69.829 ;
     RECT  1.056 66.323 24.792 69.877 ;
     RECT  26.208 67.715 26.232 69.877 ;
     RECT  40.2 68.771 40.512 69.877 ;
     RECT  1.056 69.877 26.232 70.019 ;
     RECT  32.784 69.733 33.096 70.019 ;
     RECT  33.072 70.019 33.096 70.021 ;
     RECT  1.056 70.019 24.792 70.067 ;
     RECT  27.312 69.443 27.912 70.163 ;
     RECT  54.096 69.539 58.728 70.163 ;
     RECT  61.2 69.541 70.104 70.163 ;
     RECT  40.08 69.877 40.512 70.309 ;
     RECT  1.056 70.067 2.712 70.355 ;
     RECT  45.6 68.917 46.632 70.405 ;
     RECT  29.4 68.051 30.168 70.501 ;
     RECT  36.672 69.061 36.696 70.595 ;
     RECT  26.208 70.019 26.232 70.597 ;
     RECT  54.432 70.163 58.728 70.597 ;
     RECT  71.28 69.829 75.912 70.691 ;
     RECT  47.856 69.635 48.312 70.693 ;
     RECT  26.208 70.597 26.328 70.739 ;
     RECT  40.08 70.309 40.632 70.885 ;
     RECT  47.856 70.693 48.456 70.979 ;
     RECT  39.984 70.885 40.632 70.981 ;
     RECT  43.344 70.933 43.368 71.075 ;
     RECT  54.432 70.597 58.968 71.173 ;
     RECT  31.296 69.157 31.752 71.315 ;
     RECT  34.8 69.493 35.352 71.315 ;
     RECT  47.856 70.979 48.264 71.315 ;
     RECT  3.984 70.067 24.792 71.363 ;
     RECT  39.984 70.981 40.968 71.653 ;
     RECT  42.288 67.669 42.312 71.749 ;
     RECT  61.2 70.163 70.056 71.749 ;
     RECT  71.28 70.691 74.664 71.749 ;
     RECT  26.208 70.739 26.232 71.797 ;
     RECT  27.36 70.163 27.912 71.797 ;
     RECT  29.28 70.501 30.168 71.797 ;
     RECT  31.296 71.315 31.32 71.797 ;
     RECT  33.072 70.021 33.384 71.797 ;
     RECT  39.792 71.653 40.968 71.797 ;
     RECT  42 71.749 42.312 71.797 ;
     RECT  4.32 71.363 24.792 71.843 ;
     RECT  39.792 71.797 42.456 71.893 ;
     RECT  4.848 71.843 24.792 71.941 ;
     RECT  39.696 71.893 42.456 72.037 ;
     RECT  39.696 72.037 43.368 72.083 ;
     RECT  39.696 72.083 41.304 72.131 ;
     RECT  29.28 71.797 31.32 72.229 ;
     RECT  61.2 71.749 74.664 72.275 ;
     RECT  32.688 71.797 33.384 72.277 ;
     RECT  26.208 71.797 27.912 72.371 ;
     RECT  61.2 72.275 73.56 72.419 ;
     RECT  38.064 72.229 38.088 72.421 ;
     RECT  48.24 71.315 48.264 72.421 ;
     RECT  49.584 69.635 52.584 72.421 ;
     RECT  71.28 72.419 73.56 72.515 ;
     RECT  42.432 72.083 43.368 72.517 ;
     RECT  39.792 72.131 41.304 72.563 ;
     RECT  48.24 72.421 52.584 72.563 ;
     RECT  38.064 72.421 38.808 72.565 ;
     RECT  29.232 72.229 31.32 72.611 ;
     RECT  37.824 72.565 38.808 72.851 ;
     RECT  29.232 72.611 30.216 72.949 ;
     RECT  45.6 70.405 46.68 73.043 ;
     RECT  48.24 72.563 48.264 73.045 ;
     RECT  49.344 72.563 52.584 73.093 ;
     RECT  53.664 71.173 58.968 73.093 ;
     RECT  28.896 72.949 30.216 73.139 ;
     RECT  38.304 72.851 38.808 73.139 ;
     RECT  39.792 72.563 41.16 73.187 ;
     RECT  49.344 73.093 58.968 73.235 ;
     RECT  71.328 72.515 73.56 73.237 ;
     RECT  74.64 72.275 74.664 73.237 ;
     RECT  61.2 72.419 70.056 73.283 ;
     RECT  71.328 73.237 74.664 73.283 ;
     RECT  4.848 71.941 25.128 73.381 ;
     RECT  29.088 73.139 30.216 73.427 ;
     RECT  34.8 71.315 35.304 73.427 ;
     RECT  48 73.045 48.264 73.427 ;
     RECT  32.688 72.277 33.576 73.475 ;
     RECT  3.936 73.381 25.128 73.523 ;
     RECT  29.4 73.427 30.216 73.619 ;
     RECT  37.056 73.477 37.08 73.619 ;
     RECT  38.304 73.139 38.328 73.619 ;
     RECT  69.552 73.283 70.056 73.621 ;
     RECT  71.328 73.283 74.376 73.621 ;
     RECT  48 73.427 48.168 73.763 ;
     RECT  69.552 73.621 74.376 73.763 ;
     RECT  1.68 70.355 2.712 73.909 ;
     RECT  32.688 73.475 33.48 74.099 ;
     RECT  75.888 70.691 75.912 74.099 ;
     RECT  3.936 73.523 24.648 74.195 ;
     RECT  48.144 73.763 48.168 74.387 ;
     RECT  53.664 73.235 58.968 74.387 ;
     RECT  60 68.963 60.024 74.485 ;
     RECT  61.2 73.283 68.568 74.485 ;
     RECT  71.328 73.763 74.376 74.533 ;
     RECT  40.2 73.187 41.016 74.581 ;
     RECT  37.536 74.485 37.56 74.629 ;
     RECT  60 74.485 68.568 74.629 ;
     RECT  69.552 73.763 70.056 74.629 ;
     RECT  26.496 72.371 27.912 74.675 ;
     RECT  40.2 74.581 41.064 74.723 ;
     RECT  49.344 73.235 52.584 74.723 ;
     RECT  53.664 74.387 53.688 74.723 ;
     RECT  60 74.629 70.056 74.723 ;
     RECT  71.328 74.533 75.192 74.723 ;
     RECT  33.072 74.099 33.48 74.725 ;
     RECT  34.8 73.427 35.112 74.725 ;
     RECT  61.584 74.723 70.056 74.771 ;
     RECT  1.68 73.909 2.904 74.867 ;
     RECT  61.584 74.771 67.512 74.915 ;
     RECT  37.536 74.629 38.472 75.011 ;
     RECT  61.584 74.915 62.112 75.011 ;
     RECT  50.208 74.723 52.584 75.013 ;
     RECT  50.208 75.013 53.496 75.107 ;
     RECT  33.072 74.725 35.112 75.203 ;
     RECT  42.432 72.517 43.944 75.299 ;
     RECT  55.248 74.387 58.968 75.299 ;
     RECT  72.24 74.723 75.192 75.299 ;
     RECT  27.36 74.675 27.912 75.395 ;
     RECT  55.248 75.299 58.152 75.395 ;
     RECT  72.336 75.299 75.192 75.395 ;
     RECT  61.632 75.011 62.112 75.443 ;
     RECT  63.216 74.915 67.512 75.443 ;
     RECT  72.336 75.395 74.376 75.443 ;
     RECT  50.208 75.107 51.312 75.491 ;
     RECT  55.248 75.395 57.096 75.491 ;
     RECT  72.336 75.443 73.176 75.491 ;
     RECT  65.856 75.443 67.512 75.539 ;
     RECT  68.928 74.771 70.056 75.539 ;
     RECT  55.248 75.491 56.712 75.589 ;
     RECT  38.448 75.011 38.472 75.635 ;
     RECT  55.152 75.589 56.712 75.731 ;
     RECT  58.128 75.395 58.152 75.731 ;
     RECT  63.84 75.443 64.632 75.731 ;
     RECT  68.928 75.539 69.864 75.731 ;
     RECT  65.952 75.539 67.512 75.733 ;
     RECT  33.84 75.203 35.112 75.827 ;
     RECT  29.4 73.619 30.168 75.829 ;
     RECT  31.296 72.611 31.32 75.829 ;
     RECT  42.432 75.299 42.984 75.875 ;
     RECT  52.56 75.107 53.496 75.875 ;
     RECT  69.84 75.731 69.864 75.875 ;
     RECT  60.24 74.723 60.264 75.971 ;
     RECT  52.56 75.875 52.584 76.261 ;
     RECT  65.952 75.733 68.376 76.403 ;
     RECT  40.2 74.723 40.512 76.405 ;
     RECT  29.088 75.829 31.32 76.453 ;
     RECT  42.432 75.875 42.744 76.499 ;
     RECT  65.952 76.403 67.656 76.499 ;
     RECT  74.352 75.443 74.376 76.499 ;
     RECT  4.8 74.195 24.648 76.501 ;
     RECT  26.592 76.357 26.616 76.501 ;
     RECT  39.792 76.405 40.512 76.501 ;
     RECT  28.992 76.453 31.32 76.643 ;
     RECT  45.6 73.043 45.912 76.645 ;
     RECT  34.8 75.827 35.112 76.741 ;
     RECT  64.608 75.731 64.632 76.787 ;
     RECT  4.8 76.501 26.616 76.931 ;
     RECT  52.512 76.261 52.584 76.979 ;
     RECT  61.68 75.443 62.112 76.979 ;
     RECT  27.792 75.395 27.912 77.027 ;
     RECT  58.512 76.357 58.536 77.027 ;
     RECT  67.2 76.499 67.656 77.075 ;
     RECT  65.952 76.499 66.216 77.267 ;
     RECT  1.68 74.867 2.712 77.363 ;
     RECT  39.792 76.501 40.968 77.411 ;
     RECT  39.792 77.411 40.632 77.461 ;
     RECT  45.264 76.645 45.912 77.555 ;
     RECT  65.952 77.267 65.976 77.555 ;
     RECT  72.6 75.491 73.176 77.555 ;
     RECT  47.856 76.309 47.88 77.603 ;
     RECT  42.72 76.499 42.744 77.795 ;
     RECT  4.8 76.931 26.328 77.843 ;
     RECT  52.512 76.979 52.536 77.843 ;
     RECT  27.792 77.027 27.864 77.891 ;
     RECT  4.8 77.843 6.6 77.987 ;
     RECT  7.68 77.843 26.328 77.987 ;
     RECT  4.8 77.987 6.264 78.179 ;
     RECT  7.68 77.987 17.592 78.227 ;
     RECT  11.184 78.227 17.496 78.371 ;
     RECT  11.184 78.371 17.256 78.467 ;
     RECT  27.84 77.891 27.864 78.469 ;
     RECT  29.28 76.643 31.32 78.469 ;
     RECT  4.8 78.179 5.064 78.613 ;
     RECT  6.192 78.179 6.264 78.659 ;
     RECT  27.84 78.469 31.32 78.661 ;
     RECT  32.592 77.941 32.616 78.661 ;
     RECT  18.6 77.987 26.328 78.707 ;
     RECT  38.352 78.901 38.376 78.997 ;
     RECT  7.68 78.227 9.816 79.189 ;
     RECT  27.84 78.661 32.616 79.237 ;
     RECT  4.704 78.613 5.064 79.283 ;
     RECT  18.6 78.707 25.416 79.283 ;
     RECT  37.488 78.997 38.376 79.525 ;
     RECT  11.184 78.467 16.872 79.571 ;
     RECT  27.12 79.237 32.616 79.717 ;
     RECT  7.68 79.189 9.912 79.859 ;
     RECT  18.6 79.283 24.6 79.907 ;
     RECT  26.688 79.717 32.616 80.005 ;
     RECT  37.2 79.525 38.376 80.053 ;
     RECT  34.8 76.741 35.256 80.149 ;
     RECT  39.648 77.461 40.632 80.245 ;
     RECT  42.096 79.189 42.12 80.245 ;
     RECT  4.704 79.283 4.872 80.291 ;
     RECT  9.792 79.859 9.912 80.291 ;
     RECT  39.648 80.245 42.12 80.341 ;
     RECT  7.68 79.859 8.52 80.435 ;
     RECT  26.688 80.005 32.76 80.629 ;
     RECT  34.176 80.149 35.256 80.629 ;
     RECT  26.688 80.629 35.256 80.821 ;
     RECT  11.376 79.571 16.872 81.203 ;
     RECT  26.688 80.821 35.352 81.349 ;
     RECT  37.2 80.053 38.664 81.397 ;
     RECT  39.648 80.341 42.552 81.397 ;
     RECT  37.2 81.397 42.552 81.637 ;
     RECT  11.376 81.203 13.512 81.683 ;
     RECT  36.768 81.637 42.552 82.069 ;
     RECT  26.688 81.349 35.64 82.213 ;
     RECT  36.768 82.069 42.84 82.213 ;
     RECT  6.24 78.659 6.264 82.451 ;
     RECT  7.68 80.435 8.112 82.499 ;
     RECT  18.6 79.907 24.312 83.221 ;
     RECT  26.688 82.213 42.84 83.317 ;
     RECT  18.6 83.221 25.272 83.363 ;
     RECT  23.28 83.363 25.272 83.651 ;
     RECT  14.592 81.203 16.872 83.795 ;
     RECT  23.856 83.651 25.272 83.797 ;
     RECT  26.4 83.317 42.84 83.797 ;
     RECT  11.472 81.683 13.512 83.843 ;
     RECT  14.832 83.795 16.872 83.843 ;
     RECT  14.832 83.843 15.336 83.891 ;
     RECT  4.848 80.291 4.872 84.083 ;
     RECT  16.416 83.843 16.872 84.131 ;
     RECT  14.832 83.891 15.192 84.179 ;
     RECT  18.6 83.363 21.864 84.179 ;
     RECT  2.4 77.363 2.712 84.249 ;
     RECT  7.8 82.499 8.112 84.249 ;
     RECT  13.2 83.843 13.512 84.249 ;
     RECT  45.6 77.555 45.912 84.249 ;
     RECT  51 75.491 51.312 84.249 ;
     RECT  56.4 75.731 56.712 84.249 ;
     RECT  61.8 76.979 62.112 84.249 ;
     RECT  67.2 77.075 67.512 84.249 ;
     RECT  72.6 77.555 72.912 84.249 ;
     RECT  78 18.899 78.312 84.249 ;
     RECT  83.4 17.027 83.712 84.249 ;
     RECT  88.8 65.267 89.112 84.249 ;
     RECT  94.2 14.867 94.512 84.249 ;
     RECT  99.6 2.151 99.912 84.249 ;
     RECT  105 2.151 105.312 84.249 ;
     RECT  110.4 2.151 110.712 84.249 ;
     RECT  115.8 22.403 116.112 84.249 ;
     RECT  121.2 26.627 121.512 84.249 ;
     RECT  126.6 2.151 126.912 84.249 ;
     RECT  132 2.151 132.312 84.249 ;
     RECT  137.4 2.151 137.712 84.249 ;
     RECT  2.4 84.249 2.52 84.263 ;
     RECT  7.8 84.249 7.92 84.263 ;
     RECT  13.2 84.249 13.32 84.263 ;
     RECT  18.6 84.179 19.56 84.263 ;
     RECT  45.6 84.249 45.72 84.263 ;
     RECT  51 84.249 51.12 84.263 ;
     RECT  56.4 84.249 56.52 84.263 ;
     RECT  61.8 84.249 61.92 84.263 ;
     RECT  67.2 84.249 67.32 84.263 ;
     RECT  72.6 84.249 72.72 84.263 ;
     RECT  78 84.249 78.12 84.263 ;
     RECT  83.4 84.249 83.52 84.263 ;
     RECT  88.8 84.249 88.92 84.263 ;
     RECT  94.2 84.249 94.32 84.263 ;
     RECT  99.6 84.249 99.72 84.263 ;
     RECT  105 84.249 105.12 84.263 ;
     RECT  110.4 84.249 110.52 84.263 ;
     RECT  115.8 84.249 115.92 84.263 ;
     RECT  121.2 84.249 121.32 84.263 ;
     RECT  126.6 84.249 126.72 84.263 ;
     RECT  132 84.249 132.12 84.263 ;
     RECT  137.4 84.249 137.52 84.263 ;
     RECT  9.792 80.291 9.816 84.467 ;
     RECT  11.472 83.843 11.496 84.707 ;
     RECT  15.168 84.179 15.192 84.851 ;
     RECT  20.832 84.179 21.864 84.947 ;
     RECT  23.856 83.797 42.84 85.235 ;
     RECT  16.416 84.131 16.44 85.331 ;
     RECT  19.056 84.263 19.56 85.379 ;
     RECT  19.536 85.379 19.56 85.427 ;
     RECT  21.36 84.947 21.864 86.195 ;
     RECT  24.528 85.235 42.84 86.224 ;
     RECT  21.84 86.195 21.864 86.243 ;
     RECT  24.984 0.851 26.112 1.859 ;
     RECT  41.112 1.523 42.816 1.715 ;
     RECT  38.952 1.667 40.2 3.781 ;
     RECT  5.688 1.669 6.96 8.485 ;
     RECT  42.096 1.715 42.816 2.773 ;
     RECT  49.608 1.715 50.592 1.763 ;
     RECT  71.112 2.137 72.6 2.915 ;
     RECT  45.912 2.195 46.992 2.579 ;
     RECT  31.032 2.387 32.016 2.915 ;
     RECT  59.544 2.387 60.528 2.531 ;
     RECT  8.112 2.485 9.12 7.189 ;
     RECT  45.912 2.579 47.28 3.395 ;
     RECT  18.912 2.725 20.208 2.869 ;
     RECT  48.936 2.771 49.176 3.349 ;
     RECT  42.096 2.773 42.288 2.821 ;
     RECT  42.312 2.819 43.584 2.963 ;
     RECT  27.288 2.867 28.416 2.915 ;
     RECT  26.112 2.915 26.256 3.397 ;
     RECT  31.032 2.915 32.448 3.973 ;
     RECT  57.672 2.915 58.704 3.011 ;
     RECT  42.216 2.963 43.584 3.731 ;
     RECT  57.384 3.011 58.704 3.395 ;
     RECT  11.784 3.013 13.2 3.637 ;
     RECT  13.512 3.061 14.544 3.157 ;
     RECT  14.568 3.061 15.888 3.109 ;
     RECT  54.072 3.347 55.056 5.747 ;
     RECT  48.936 3.349 50.112 3.395 ;
     RECT  21 3.397 22.176 3.493 ;
     RECT  25.08 3.397 26.256 3.683 ;
     RECT  51.312 3.491 52.752 4.595 ;
     RECT  11.784 3.637 12.768 3.877 ;
     RECT  26.16 3.683 26.256 4.307 ;
     RECT  9.144 3.925 10.56 6.805 ;
     RECT  31.032 3.973 32.064 4.115 ;
     RECT  31.032 4.115 32.448 4.643 ;
     RECT  26.16 4.307 26.184 4.549 ;
     RECT  15.912 4.405 16.992 4.981 ;
     RECT  30.936 4.643 32.448 5.075 ;
     RECT  32.904 4.787 33.888 5.171 ;
     RECT  32.616 5.171 33.888 5.219 ;
     RECT  67.512 5.219 67.608 6.661 ;
     RECT  41.112 5.701 42.576 6.035 ;
     RECT  35.784 6.131 36.96 8.723 ;
     RECT  82.344 6.229 83.4 8.677 ;
     RECT  9.288 6.805 10.56 7.669 ;
     RECT  83.712 6.805 85.056 8.821 ;
     RECT  87.576 6.805 88.8 7.139 ;
     RECT  119.88 6.949 121.2 13.429 ;
     RECT  87.552 7.139 88.8 8.533 ;
     RECT  70.536 7.381 71.808 7.427 ;
     RECT  67.992 7.427 68.088 8.003 ;
     RECT  72.384 7.427 72.6 8.437 ;
     RECT  72.912 7.909 74.16 9.107 ;
     RECT  78.792 7.909 80.256 8.675 ;
     RECT  67.512 8.003 68.088 8.725 ;
     RECT  89.112 8.003 89.496 8.197 ;
     RECT  89.112 8.197 90.576 9.061 ;
     RECT  41.592 8.243 41.784 8.437 ;
     RECT  41.592 8.437 43.296 9.061 ;
     RECT  74.184 8.485 75.216 9.107 ;
     RECT  87.528 8.533 88.8 9.013 ;
     RECT  78.792 8.675 80.136 9.061 ;
     RECT  35.208 8.723 36.96 9.061 ;
     RECT  67.512 8.725 68.832 9.061 ;
     RECT  83.712 8.821 85.008 11.027 ;
     RECT  22.296 8.965 23.712 9.107 ;
     RECT  64.728 9.013 66.096 9.203 ;
     RECT  66.12 9.013 67.2 11.797 ;
     RECT  82.344 9.059 83.4 10.021 ;
     RECT  35.208 9.061 36.24 9.635 ;
     RECT  41.592 9.061 42.912 9.155 ;
     RECT  67.608 9.061 68.64 9.589 ;
     RECT  79.272 9.061 80.136 9.781 ;
     RECT  91.224 9.061 92.544 9.397 ;
     RECT  92.568 9.061 94.08 9.589 ;
     RECT  72.912 9.107 73.032 9.253 ;
     RECT  74.88 9.107 75.216 9.157 ;
     RECT  42.936 9.155 43.32 10.261 ;
     RECT  64.704 9.203 66.096 9.349 ;
     RECT  52.992 9.251 53.016 9.589 ;
     RECT  2.712 9.301 3.84 10.883 ;
     RECT  63.336 9.349 66.096 9.397 ;
     RECT  63.528 9.397 66.096 9.493 ;
     RECT  91.224 9.397 92.496 9.973 ;
     RECT  64.392 9.493 66.096 10.309 ;
     RECT  46.632 9.587 46.728 10.403 ;
     RECT  52.992 9.589 53.088 10.213 ;
     RECT  92.568 9.589 93.984 9.829 ;
     RECT  35.112 9.635 36.24 9.971 ;
     RECT  85.512 9.637 86.688 10.019 ;
     RECT  79.8 9.781 80.136 9.829 ;
     RECT  78.792 9.827 79.776 10.981 ;
     RECT  92.712 9.829 93.984 10.355 ;
     RECT  24.312 9.877 25.728 10.165 ;
     RECT  68.952 9.923 69 10.933 ;
     RECT  35.112 9.971 36.96 11.221 ;
     RECT  85.368 10.019 86.688 10.739 ;
     RECT  75.24 10.163 76.368 10.883 ;
     RECT  24.312 10.165 25.392 12.083 ;
     RECT  51.312 10.213 52.416 12.277 ;
     RECT  45.504 10.307 45.6 10.501 ;
     RECT  90.024 10.307 91.68 11.365 ;
     RECT  64.968 10.309 66.096 10.453 ;
     RECT  87.816 10.355 88.8 12.709 ;
     RECT  92.616 10.355 93.984 14.387 ;
     RECT  30.552 10.403 30.984 10.789 ;
     RECT  46.44 10.403 46.728 10.789 ;
     RECT  64.968 10.453 66.048 10.547 ;
     RECT  44.04 10.501 45.6 10.643 ;
     RECT  64.632 10.547 66.048 10.787 ;
     RECT  45.504 10.643 45.6 11.701 ;
     RECT  57.384 10.693 58.512 11.413 ;
     RECT  86.976 10.739 87.168 11.749 ;
     RECT  42.936 10.787 43.416 11.941 ;
     RECT  64.44 10.787 66.048 11.941 ;
     RECT  30.552 10.789 32.112 11.365 ;
     RECT  46.44 10.789 47.664 11.795 ;
     RECT  2.712 10.883 3.936 12.805 ;
     RECT  75.24 10.883 76.416 12.277 ;
     RECT  22.824 10.933 24 11.125 ;
     RECT  83.712 11.027 85.344 11.749 ;
     RECT  48.12 11.077 49.584 11.939 ;
     RECT  59.592 11.125 61.008 11.365 ;
     RECT  35.112 11.221 36.864 11.413 ;
     RECT  22.344 11.267 23.664 15.587 ;
     RECT  25.416 11.267 25.896 11.365 ;
     RECT  71.592 11.315 72.6 12.757 ;
     RECT  4.536 11.365 5.664 12.563 ;
     RECT  25.416 11.365 26.592 12.083 ;
     RECT  31.032 11.365 32.112 13.141 ;
     RECT  59.832 11.365 61.008 12.949 ;
     RECT  90.6 11.365 91.68 11.701 ;
     RECT  35.64 11.413 36.864 12.517 ;
     RECT  41.832 11.653 42.912 13.715 ;
     RECT  90.6 11.701 91.632 12.227 ;
     RECT  84.216 11.749 85.344 13.573 ;
     RECT  48.432 11.939 49.584 12.275 ;
     RECT  27.912 11.941 29.4 13.285 ;
     RECT  32.136 11.941 33.12 13.333 ;
     RECT  33.144 11.941 34.56 11.989 ;
     RECT  64.44 11.941 65.712 12.565 ;
     RECT  33.144 11.989 34.176 15.109 ;
     RECT  24.312 12.083 26.592 12.275 ;
     RECT  24.312 12.275 26.736 12.517 ;
     RECT  48.432 12.275 49.824 12.901 ;
     RECT  58.2 12.275 59.184 12.563 ;
     RECT  51.312 12.277 52.32 13.141 ;
     RECT  75.816 12.323 76.896 13.331 ;
     RECT  78.792 12.467 79.776 13.669 ;
     RECT  24.312 12.517 25.632 13.139 ;
     RECT  25.656 12.517 26.736 13.139 ;
     RECT  64.44 12.707 65.712 13.283 ;
     RECT  35.736 12.899 36.864 14.915 ;
     RECT  48.456 12.901 49.824 13.379 ;
     RECT  73.752 12.901 75.216 13.429 ;
     RECT  79.8 12.947 80.928 13.091 ;
     RECT  59.832 12.949 60.864 13.811 ;
     RECT  69.672 13.045 70.992 13.091 ;
     RECT  69.288 13.091 70.992 13.235 ;
     RECT  63.288 13.139 64.272 13.763 ;
     RECT  69.288 13.235 71.52 13.525 ;
     RECT  64.344 13.283 65.712 13.859 ;
     RECT  27.912 13.285 29.28 13.477 ;
     RECT  52.44 13.331 53.424 14.771 ;
     RECT  75.72 13.331 76.896 14.291 ;
     RECT  48.456 13.379 49.968 14.965 ;
     RECT  73.752 13.429 74.88 13.813 ;
     RECT  42.936 13.475 43.896 13.957 ;
     RECT  62.112 13.475 63.12 13.667 ;
     RECT  27.912 13.477 29.184 13.765 ;
     RECT  69.288 13.525 70.368 14.915 ;
     RECT  70.392 13.525 71.52 65.555 ;
     RECT  84.36 13.573 85.344 14.195 ;
     RECT  31.032 13.619 32.112 13.715 ;
     RECT  32.136 13.667 33.12 14.339 ;
     RECT  62.112 13.667 63.216 14.917 ;
     RECT  30.888 13.715 32.112 14.339 ;
     RECT  41.784 13.715 42.912 15.491 ;
     RECT  81.792 13.715 82.32 14.773 ;
     RECT  63.24 13.763 64.272 15.011 ;
     RECT  27.912 13.765 29.136 14.005 ;
     RECT  59.592 13.811 60.864 14.147 ;
     RECT  64.344 13.859 66.048 15.011 ;
     RECT  42.936 13.957 44.256 14.581 ;
     RECT  44.28 13.957 45.6 14.053 ;
     RECT  27.912 14.005 29.088 14.245 ;
     RECT  44.616 14.053 45.6 14.195 ;
     RECT  53.448 14.147 53.496 15.589 ;
     RECT  66.072 14.147 67.2 15.925 ;
     RECT  1.032 14.149 2.4 25.477 ;
     RECT  117.048 14.149 118.176 17.413 ;
     RECT  44.28 14.195 45.6 16.213 ;
     RECT  78.312 14.243 79.344 16.693 ;
     RECT  27.912 14.245 29.04 14.291 ;
     RECT  27.624 14.291 29.04 14.341 ;
     RECT  76.608 14.291 76.896 14.965 ;
     RECT  32.448 14.339 33.12 15.155 ;
     RECT  27.624 14.341 28.608 14.579 ;
     RECT  92.616 14.387 94.08 14.867 ;
     RECT  27.624 14.579 29.04 15.347 ;
     RECT  46.488 14.725 47.76 14.915 ;
     RECT  43.224 14.771 44.256 15.491 ;
     RECT  51.72 14.771 53.424 15.877 ;
     RECT  24.888 14.773 26.064 15.059 ;
     RECT  79.8 14.773 81.024 16.835 ;
     RECT  81.048 14.773 82.32 16.789 ;
     RECT  35.736 14.915 36.96 15.971 ;
     RECT  46.152 14.915 47.76 14.963 ;
     RECT  69.192 14.915 70.368 16.547 ;
     RECT  46.008 14.963 47.76 15.877 ;
     RECT  4.488 14.965 5.664 16.981 ;
     RECT  57.816 14.965 59.184 15.107 ;
     RECT  63.24 15.011 66.048 15.013 ;
     RECT  63.24 15.013 64.608 15.299 ;
     RECT  64.632 15.013 66.048 15.299 ;
     RECT  86.616 15.059 87.744 15.539 ;
     RECT  89.208 15.059 89.304 16.117 ;
     RECT  57.72 15.107 59.184 15.299 ;
     RECT  67.608 15.107 68.64 17.699 ;
     RECT  32.448 15.155 33.6 15.299 ;
     RECT  48.696 15.155 49.968 16.837 ;
     RECT  82.344 15.203 83.4 19.571 ;
     RECT  76.92 15.251 77.904 15.299 ;
     RECT  32.448 15.299 32.472 15.493 ;
     RECT  65.04 15.299 66.048 15.349 ;
     RECT  76.632 15.299 77.904 16.693 ;
     RECT  27.528 15.347 29.04 17.123 ;
     RECT  65.04 15.349 65.664 15.541 ;
     RECT  40.512 15.443 41.76 17.507 ;
     RECT  41.784 15.491 44.256 15.877 ;
     RECT  86.616 15.539 88.032 16.595 ;
     RECT  22.344 15.587 24 15.973 ;
     RECT  34.272 15.779 34.56 16.981 ;
     RECT  42.504 15.877 44.016 16.453 ;
     RECT  46.008 15.877 47.232 16.021 ;
     RECT  51.72 15.877 53.232 15.925 ;
     RECT  51.72 15.925 52.848 18.661 ;
     RECT  35.64 15.971 36.96 17.509 ;
     RECT  22.44 15.973 24 16.885 ;
     RECT  46.152 16.021 47.232 17.749 ;
     RECT  44.376 16.213 45.6 16.453 ;
     RECT  42.504 16.453 43.92 16.499 ;
     RECT  71.544 16.499 72.6 65.555 ;
     RECT  69.096 16.547 70.368 17.653 ;
     RECT  65.664 16.595 66.048 17.605 ;
     RECT  86.592 16.595 88.032 16.981 ;
     RECT  81.288 16.789 82.32 18.757 ;
     RECT  79.8 16.835 81.264 18.805 ;
     RECT  24.888 16.837 25.872 16.981 ;
     RECT  83.88 16.885 84.912 16.981 ;
     RECT  78.312 16.979 79.392 17.507 ;
     RECT  33.048 16.981 34.56 17.123 ;
     RECT  86.568 16.981 88.032 17.699 ;
     RECT  83.712 17.027 84.816 17.123 ;
     RECT  52.872 17.075 53.4 18.181 ;
     RECT  4.536 17.123 5.664 18.181 ;
     RECT  24.888 17.123 25.872 17.651 ;
     RECT  33.888 17.123 34.56 18.133 ;
     RECT  40.512 17.507 41.208 17.845 ;
     RECT  44.28 17.507 45.6 17.891 ;
     RECT  78.312 17.507 79.776 20.003 ;
     RECT  35.64 17.509 36.864 18.275 ;
     RECT  65.64 17.699 66.96 18.757 ;
     RECT  67.512 17.699 68.64 21.637 ;
     RECT  88.464 17.747 88.8 19.237 ;
     RECT  22.44 17.939 23.424 18.035 ;
     RECT  69 17.987 70.368 22.165 ;
     RECT  30.744 18.083 30.888 19.045 ;
     RECT  4.536 18.181 5.52 20.149 ;
     RECT  52.872 18.181 54.24 18.373 ;
     RECT  24.312 18.275 24.6 19.669 ;
     RECT  35.352 18.275 36.864 18.947 ;
     RECT  53.016 18.373 54.24 19.475 ;
     RECT  51.72 18.661 52.8 18.803 ;
     RECT  51.72 18.803 52.992 19.523 ;
     RECT  79.8 18.805 81.072 19.763 ;
     RECT  38.232 18.899 39.216 64.451 ;
     RECT  35.352 18.947 36.96 19.331 ;
     RECT  35.112 19.331 36.96 20.053 ;
     RECT  81.096 19.475 82.32 19.571 ;
     RECT  49.896 19.667 51 21.253 ;
     RECT  33.888 19.715 34.08 21.061 ;
     RECT  62.52 19.811 62.664 20.965 ;
     RECT  35.112 20.053 36.72 20.485 ;
     RECT  66.12 20.099 67.2 64.739 ;
     RECT  45.912 20.387 46.992 64.259 ;
     RECT  35.448 20.485 36.72 64.451 ;
     RECT  22.584 21.061 24 22.165 ;
     RECT  33.096 21.061 34.08 66.179 ;
     RECT  4.536 21.155 5.664 22.789 ;
     RECT  60.696 21.301 61.8 21.637 ;
     RECT  27.96 21.541 29.4 63.733 ;
     RECT  26.232 21.589 27.36 67.333 ;
     RECT  55.176 21.925 56.4 64.837 ;
     RECT  31.464 21.973 32.736 22.021 ;
     RECT  53.832 22.117 55.152 65.603 ;
     RECT  22.968 22.165 24 22.213 ;
     RECT  48.744 22.213 49.872 64.117 ;
     RECT  116.112 22.403 117.144 63.528 ;
     RECT  4.584 22.789 5.664 23.701 ;
     RECT  1.128 25.477 2.4 27.877 ;
     RECT  119.736 26.627 121.2 29.315 ;
     RECT  117.24 30.083 118.656 31.811 ;
     RECT  117.24 31.811 118.704 32.195 ;
     RECT  28.056 63.733 29.4 66.755 ;
     RECT  36.744 64.019 37.776 64.787 ;
     RECT  24.792 64.213 26.208 69.877 ;
     RECT  48.12 64.403 49.584 65.027 ;
     RECT  62.52 64.403 62.664 65.701 ;
     RECT  67.056 64.739 67.2 66.181 ;
     RECT  55.176 64.837 56.208 65.603 ;
     RECT  70.392 65.555 70.776 65.603 ;
     RECT  56.16 65.603 56.208 66.325 ;
     RECT  56.712 65.603 57.84 67.477 ;
     RECT  69.288 65.603 70.776 66.085 ;
     RECT  62.52 65.701 63.6 67.573 ;
     RECT  37.776 65.987 38.208 66.035 ;
     RECT  37.776 66.035 38.232 66.901 ;
     RECT  57.864 66.037 59.232 66.421 ;
     RECT  69.288 66.085 70.752 67.333 ;
     RECT  67.056 66.323 67.2 67.573 ;
     RECT  57.864 66.421 58.848 67.045 ;
     RECT  27.912 66.755 29.4 67.909 ;
     RECT  45.912 66.755 46.008 68.101 ;
     RECT  63.624 66.755 63.96 67.717 ;
     RECT  37.176 66.901 38.232 67.237 ;
     RECT  30.168 67.237 31.296 68.629 ;
     RECT  37.176 67.237 39.36 67.285 ;
     RECT  37.176 67.285 38.688 68.099 ;
     RECT  69.288 67.333 70.656 68.053 ;
     RECT  70.776 67.333 71.904 67.381 ;
     RECT  70.776 67.381 71.808 68.485 ;
     RECT  56.712 67.477 57.696 68.005 ;
     RECT  42.312 67.669 43.584 69.059 ;
     RECT  43.608 67.669 45.12 67.861 ;
     RECT  26.232 67.715 27.312 70.163 ;
     RECT  38.712 67.715 40.2 69.107 ;
     RECT  63.624 67.717 65.232 67.909 ;
     RECT  65.256 67.717 66.576 67.765 ;
     RECT  43.608 67.861 45.024 68.195 ;
     RECT  27.912 67.909 29.088 68.051 ;
     RECT  63.72 67.909 65.232 68.197 ;
     RECT  27.912 68.051 29.4 69.301 ;
     RECT  52.296 68.101 53.808 68.341 ;
     RECT  63.864 68.197 65.232 68.629 ;
     RECT  52.296 68.341 53.568 68.917 ;
     RECT  60.024 68.389 61.248 68.485 ;
     RECT  60.024 68.485 61.2 74.485 ;
     RECT  30.168 68.629 31.2 68.771 ;
     RECT  40.872 68.629 42.288 68.771 ;
     RECT  63.96 68.629 65.232 69.541 ;
     RECT  34.704 68.675 34.8 70.021 ;
     RECT  30.168 68.771 31.296 71.797 ;
     RECT  46.632 68.917 47.856 70.405 ;
     RECT  52.584 68.917 53.568 69.491 ;
     RECT  74.664 68.917 75.888 69.829 ;
     RECT  58.728 68.963 60 70.597 ;
     RECT  42.312 69.059 43.32 69.157 ;
     RECT  40.08 69.107 40.2 69.877 ;
     RECT  31.752 69.157 32.976 69.733 ;
     RECT  42.312 69.157 43.296 69.299 ;
     RECT  28.248 69.301 29.4 69.443 ;
     RECT  70.104 69.395 71.28 70.163 ;
     RECT  27.912 69.443 29.4 70.501 ;
     RECT  52.584 69.491 54.048 69.539 ;
     RECT  35.352 69.493 36.672 70.595 ;
     RECT  52.584 69.539 54.096 70.163 ;
     RECT  48.312 69.635 49.584 70.693 ;
     RECT  31.752 69.733 32.784 70.019 ;
     RECT  24.792 70.019 26.208 71.941 ;
     RECT  31.752 70.019 33.072 71.315 ;
     RECT  33.384 70.021 34.8 72.277 ;
     RECT  2.712 70.067 3.984 71.363 ;
     RECT  26.232 70.163 27.36 70.597 ;
     RECT  52.584 70.163 54.432 71.173 ;
     RECT  70.056 70.163 71.28 71.749 ;
     RECT  46.68 70.405 47.856 71.315 ;
     RECT  27.912 70.501 29.28 72.229 ;
     RECT  26.328 70.597 27.36 70.739 ;
     RECT  58.968 70.597 60 74.723 ;
     RECT  74.664 70.691 75.888 73.283 ;
     RECT  48.456 70.693 49.584 70.979 ;
     RECT  26.232 70.739 27.36 71.797 ;
     RECT  42.312 70.933 43.344 71.075 ;
     RECT  48.264 70.979 49.584 72.421 ;
     RECT  40.968 70.981 42.288 71.749 ;
     RECT  42.312 71.075 43.368 71.797 ;
     RECT  52.584 71.173 53.664 73.093 ;
     RECT  31.32 71.315 33.072 71.797 ;
     RECT  40.968 71.749 42 71.797 ;
     RECT  31.32 71.797 32.688 74.099 ;
     RECT  42.456 71.797 43.368 72.037 ;
     RECT  25.128 71.941 26.208 72.371 ;
     RECT  41.304 72.083 42.432 72.563 ;
     RECT  39.696 72.131 39.792 72.421 ;
     RECT  27.912 72.229 29.232 72.949 ;
     RECT  73.56 72.275 74.64 73.237 ;
     RECT  33.576 72.277 34.8 73.475 ;
     RECT  25.128 72.371 26.496 73.523 ;
     RECT  70.056 72.419 71.28 72.515 ;
     RECT  38.808 72.421 39.792 73.139 ;
     RECT  70.056 72.515 71.328 73.621 ;
     RECT  41.16 72.563 42.432 73.187 ;
     RECT  48.264 72.563 49.344 73.427 ;
     RECT  30.216 72.611 31.296 73.619 ;
     RECT  37.824 72.851 38.304 73.477 ;
     RECT  27.912 72.949 28.896 73.139 ;
     RECT  27.912 73.139 29.088 73.427 ;
     RECT  38.328 73.139 39.792 73.187 ;
     RECT  38.328 73.187 38.472 73.619 ;
     RECT  41.016 73.187 42.432 74.581 ;
     RECT  52.584 73.235 53.664 74.723 ;
     RECT  68.568 73.283 69.552 74.629 ;
     RECT  74.376 73.283 75.888 74.099 ;
     RECT  2.712 73.381 3.936 73.909 ;
     RECT  27.912 73.427 29.4 75.829 ;
     RECT  48.168 73.427 49.344 74.387 ;
     RECT  33.48 73.475 34.8 74.725 ;
     RECT  37.08 73.477 38.304 73.619 ;
     RECT  30.168 73.619 31.296 75.829 ;
     RECT  37.536 73.619 38.472 74.485 ;
     RECT  70.056 73.763 71.328 74.723 ;
     RECT  2.904 73.909 3.936 74.195 ;
     RECT  74.376 74.099 75.192 74.533 ;
     RECT  53.688 74.387 55.248 74.723 ;
     RECT  37.56 74.485 38.472 74.629 ;
     RECT  41.064 74.581 42.432 74.723 ;
     RECT  52.584 74.723 53.496 75.013 ;
     RECT  55.152 74.723 55.248 75.589 ;
     RECT  58.968 74.723 60.24 75.299 ;
     RECT  60.264 74.723 61.584 75.011 ;
     RECT  67.512 74.771 68.928 75.731 ;
     RECT  62.112 74.915 63.216 75.443 ;
     RECT  60.264 75.011 61.632 75.443 ;
     RECT  51.312 75.107 52.56 76.261 ;
     RECT  58.152 75.299 58.536 75.731 ;
     RECT  27.36 75.395 27.792 76.357 ;
     RECT  57.096 75.395 58.128 75.491 ;
     RECT  60.264 75.443 61.68 75.971 ;
     RECT  64.632 75.443 65.856 75.539 ;
     RECT  73.176 75.443 74.352 76.499 ;
     RECT  56.712 75.491 58.128 75.731 ;
     RECT  64.632 75.539 65.952 76.787 ;
     RECT  58.512 75.731 58.536 76.357 ;
     RECT  67.512 75.731 69.84 75.733 ;
     RECT  68.376 75.733 69.84 75.875 ;
     RECT  27.912 75.829 29.088 76.453 ;
     RECT  51.312 76.261 52.512 77.843 ;
     RECT  26.616 76.357 27.792 76.931 ;
     RECT  27.912 76.453 28.992 76.643 ;
     RECT  66.216 76.499 67.2 77.267 ;
     RECT  27.912 76.643 29.28 77.027 ;
     RECT  26.328 76.931 27.792 77.891 ;
     RECT  27.864 77.027 29.28 78.469 ;
     RECT  65.976 77.267 67.2 77.555 ;
     RECT  6.6 77.843 7.68 77.987 ;
     RECT  26.328 77.891 27.84 78.707 ;
     RECT  31.32 77.941 32.592 78.661 ;
     RECT  6.264 77.987 7.68 82.451 ;
     RECT  17.592 77.987 18.6 78.227 ;
     RECT  5.064 78.179 6.192 78.659 ;
     RECT  9.816 78.227 11.184 79.189 ;
     RECT  17.496 78.227 18.6 78.371 ;
     RECT  17.256 78.371 18.6 78.467 ;
     RECT  5.064 78.659 6.24 79.283 ;
     RECT  25.416 78.707 27.84 79.237 ;
     RECT  38.376 78.901 39.648 80.053 ;
     RECT  9.912 79.189 11.184 79.571 ;
     RECT  40.632 79.189 42.096 80.245 ;
     RECT  25.416 79.237 27.12 79.283 ;
     RECT  4.872 79.283 6.24 82.451 ;
     RECT  26.688 79.283 27.12 79.717 ;
     RECT  9.912 79.571 11.376 80.291 ;
     RECT  8.52 79.859 9.792 80.435 ;
     RECT  38.664 80.053 39.648 81.397 ;
     RECT  32.76 80.149 34.176 80.629 ;
     RECT  13.512 81.203 14.592 83.795 ;
     RECT  35.64 81.637 36.768 82.213 ;
     RECT  25.272 83.221 26.688 83.317 ;
     RECT  25.272 83.317 26.4 83.797 ;
     RECT  21.864 83.363 23.28 83.651 ;
     RECT  13.512 83.795 14.832 84.179 ;
     RECT  15.336 83.843 16.416 83.891 ;
     RECT  15.192 83.891 16.416 84.851 ;
     RECT  19.56 84.179 20.832 84.947 ;
  END
END ot_s81_pq_qb_bank1_native
END LIBRARY
